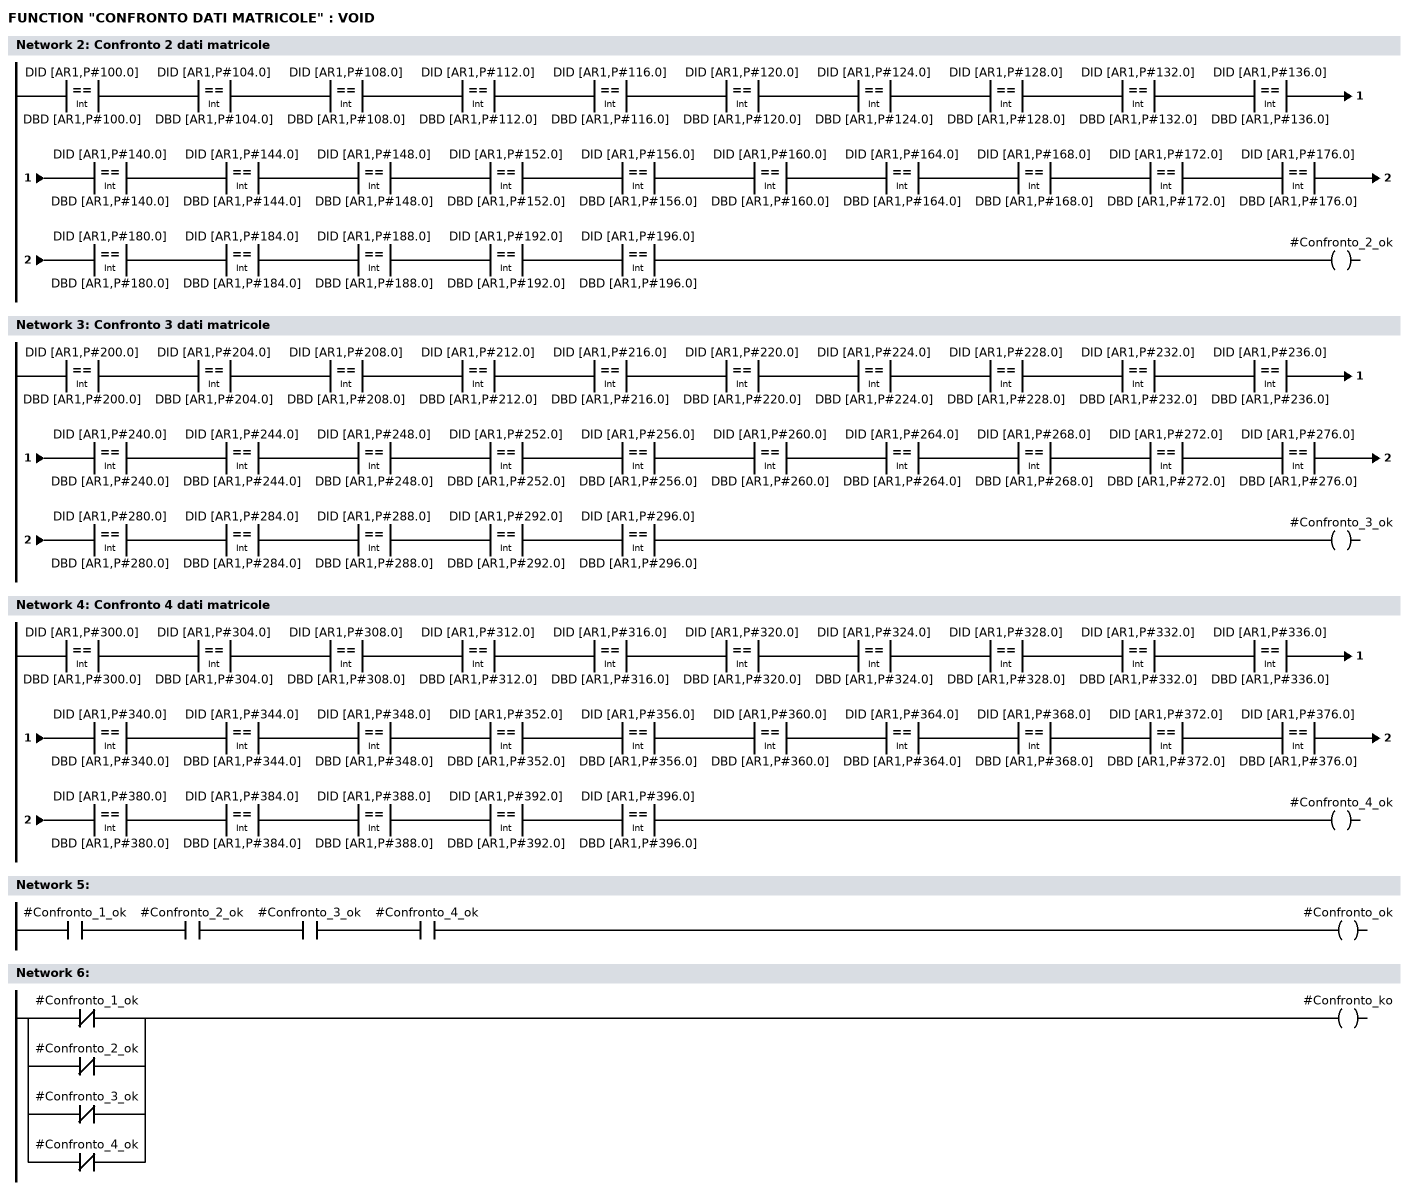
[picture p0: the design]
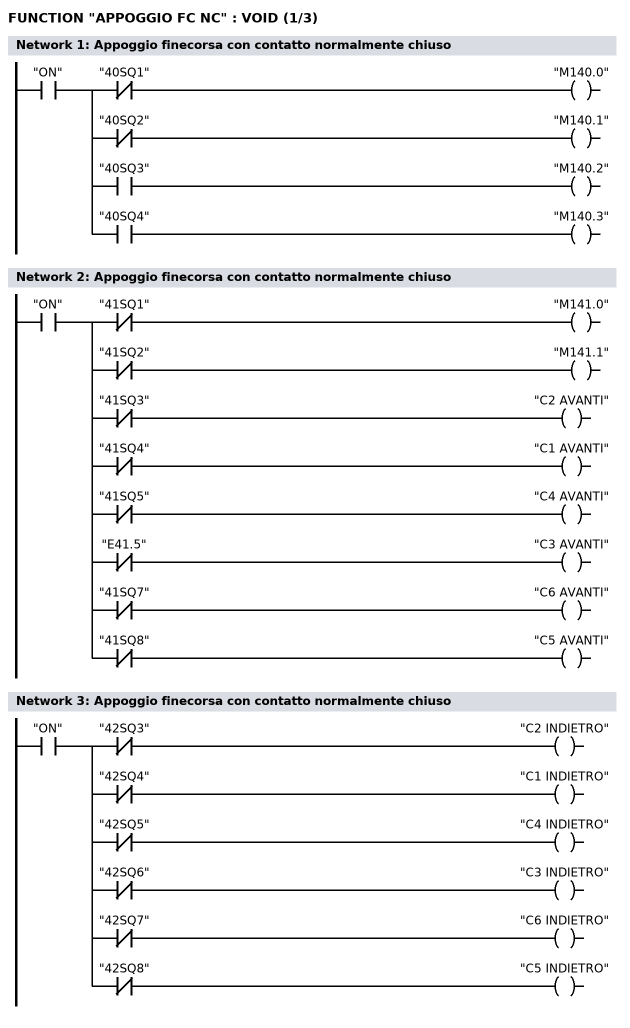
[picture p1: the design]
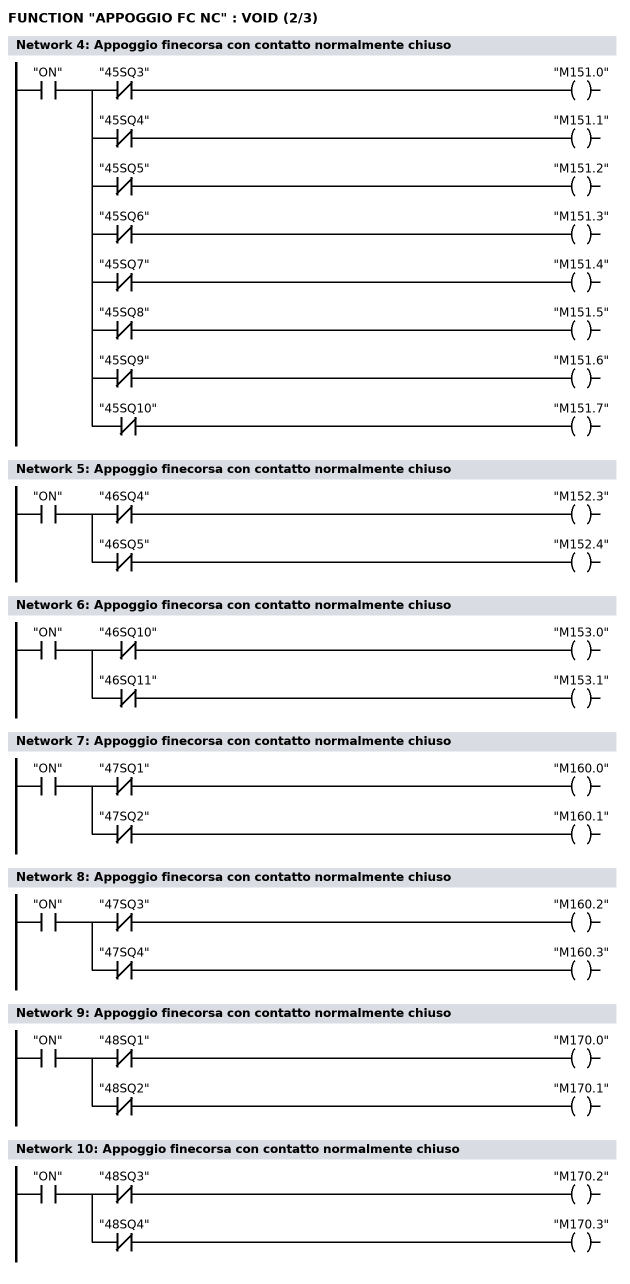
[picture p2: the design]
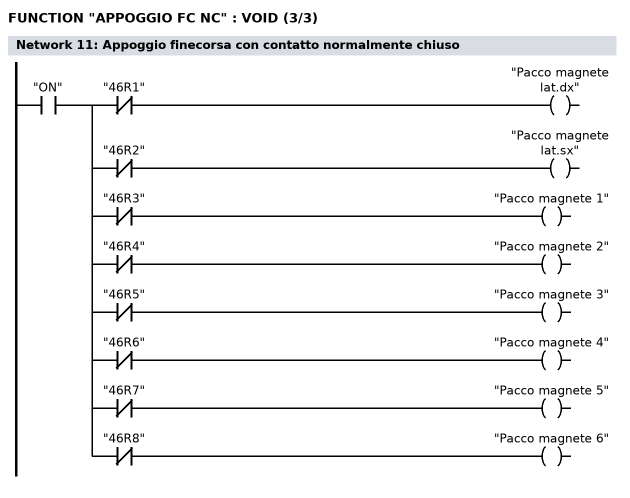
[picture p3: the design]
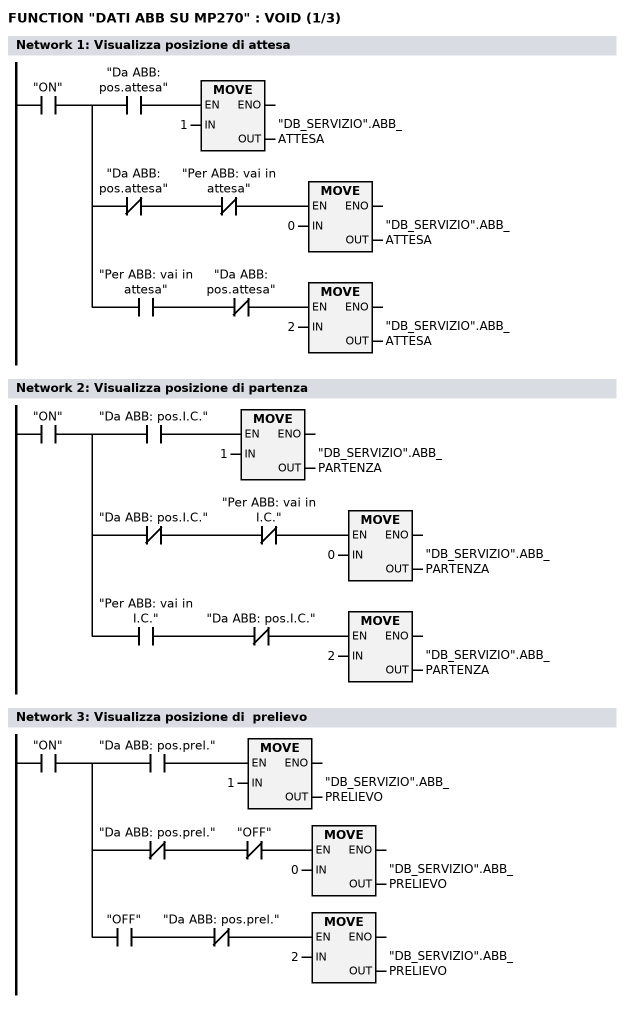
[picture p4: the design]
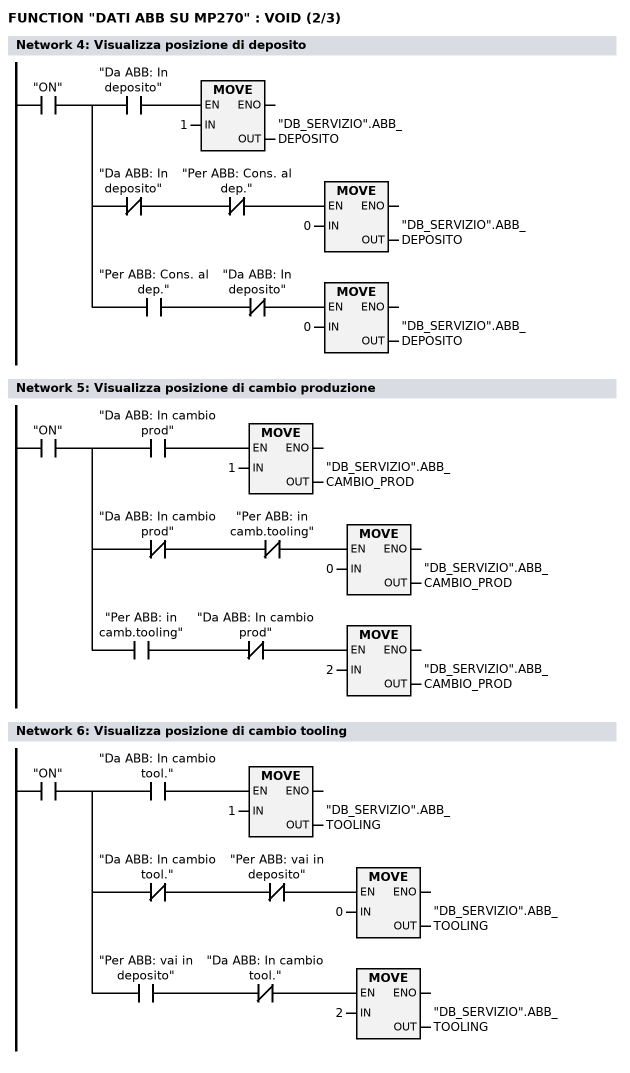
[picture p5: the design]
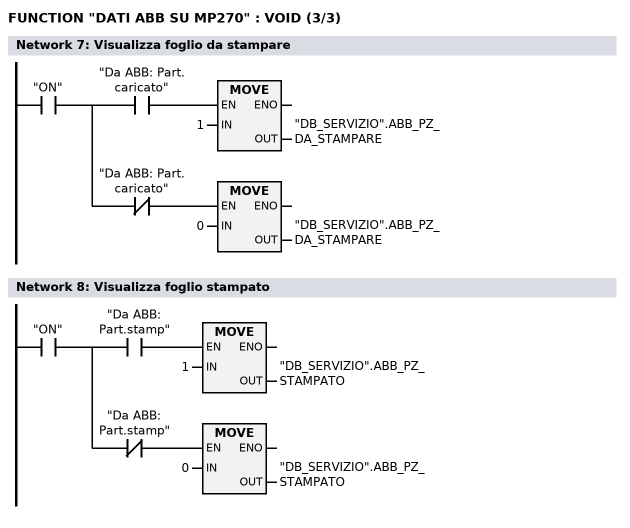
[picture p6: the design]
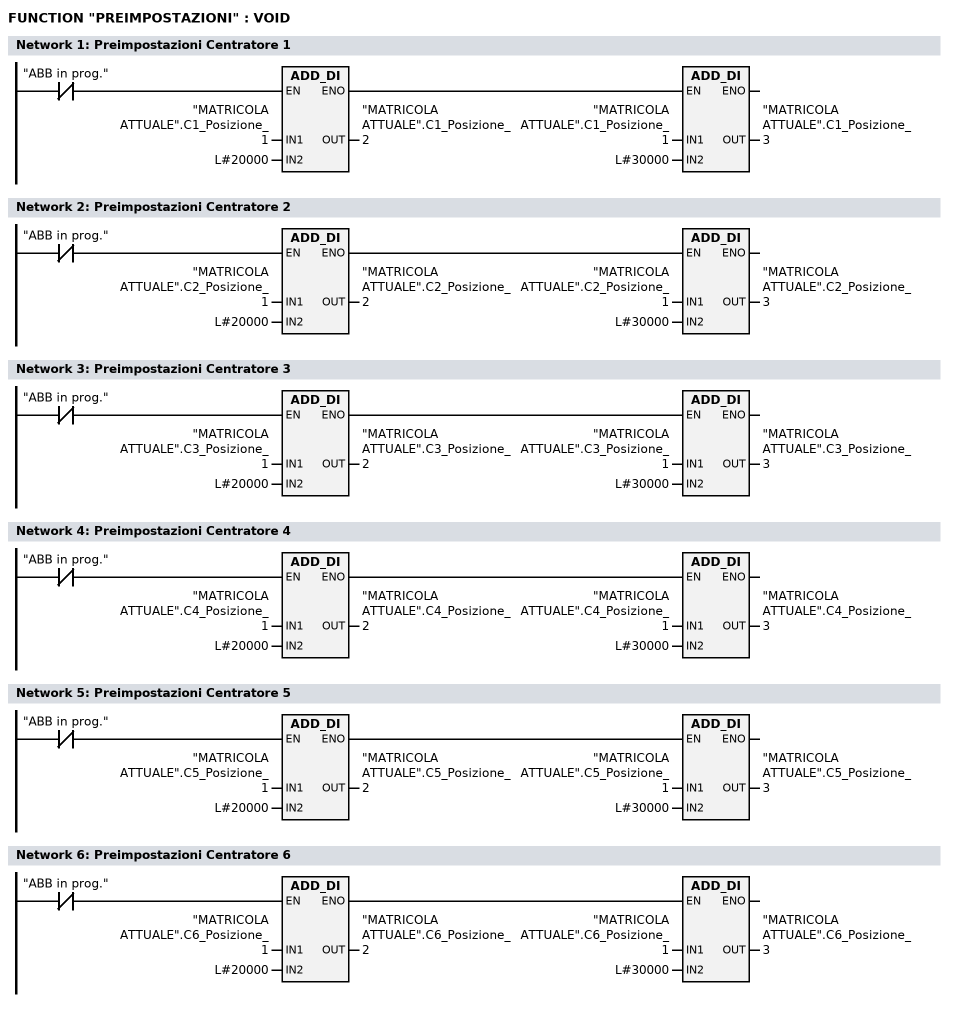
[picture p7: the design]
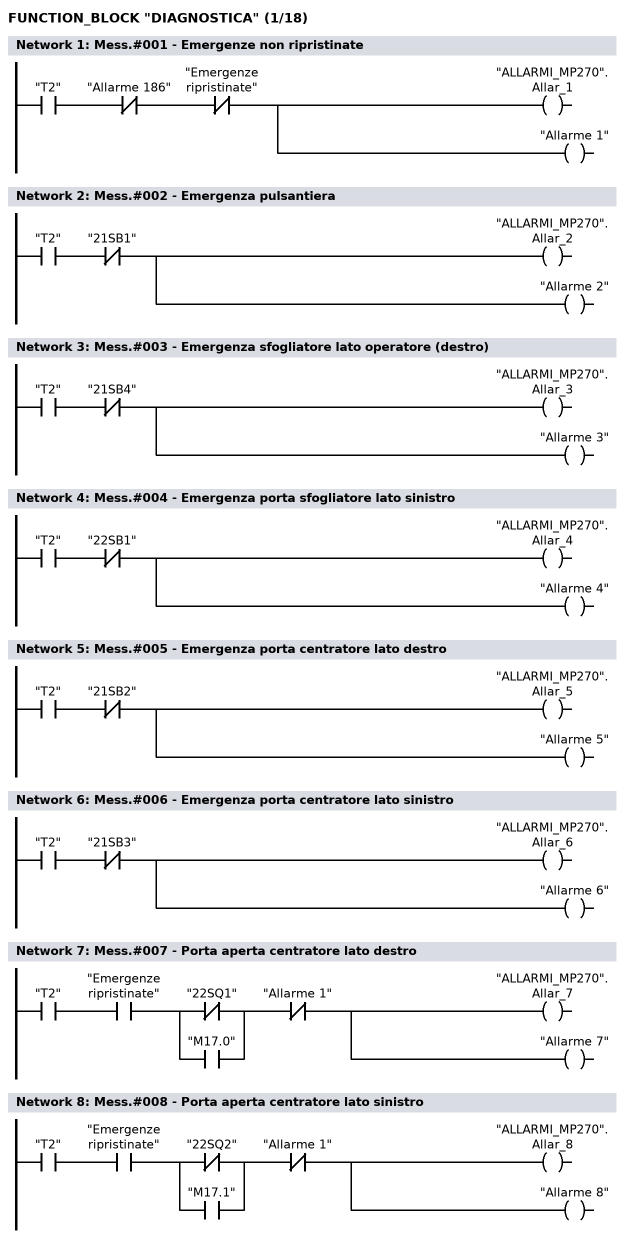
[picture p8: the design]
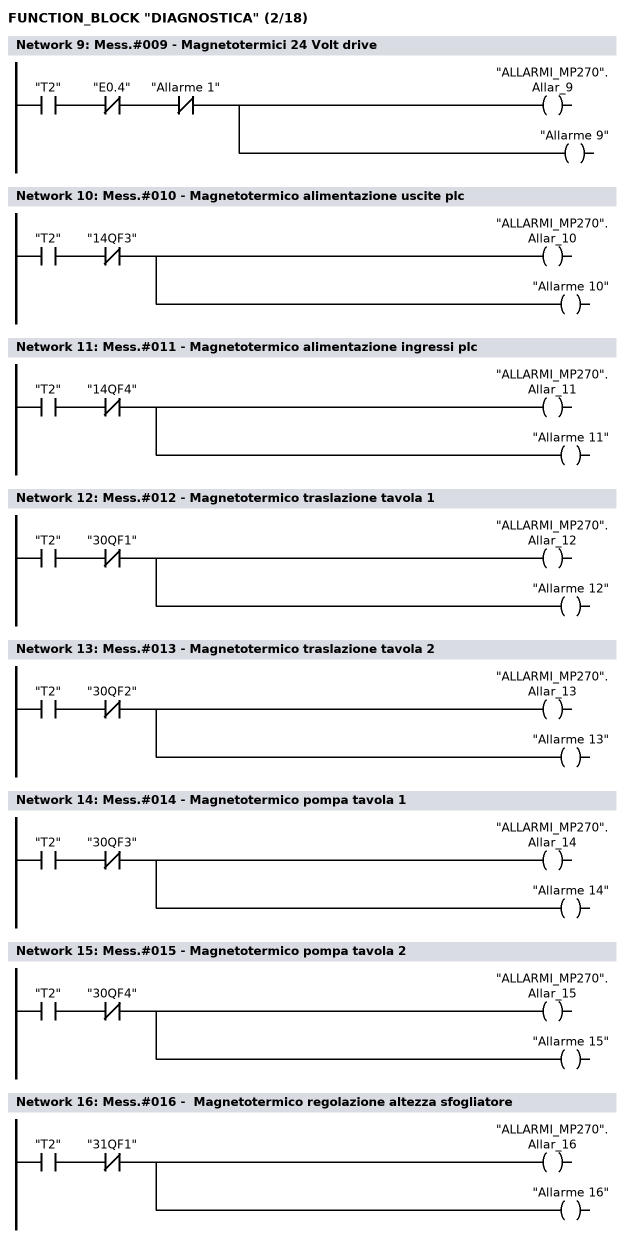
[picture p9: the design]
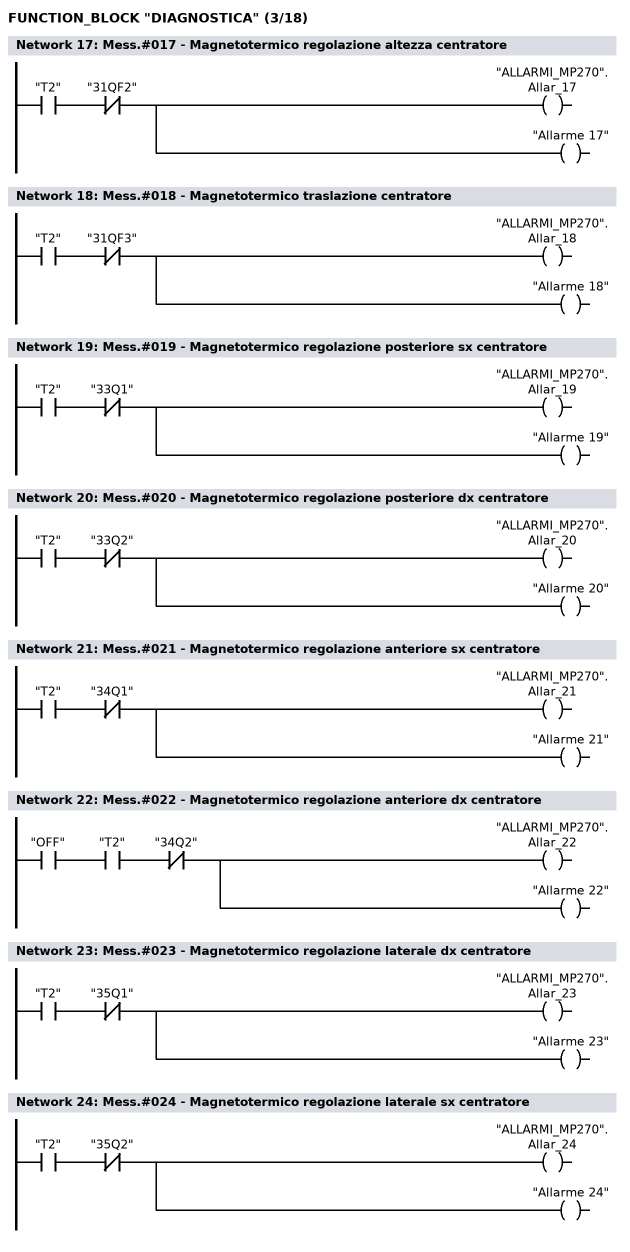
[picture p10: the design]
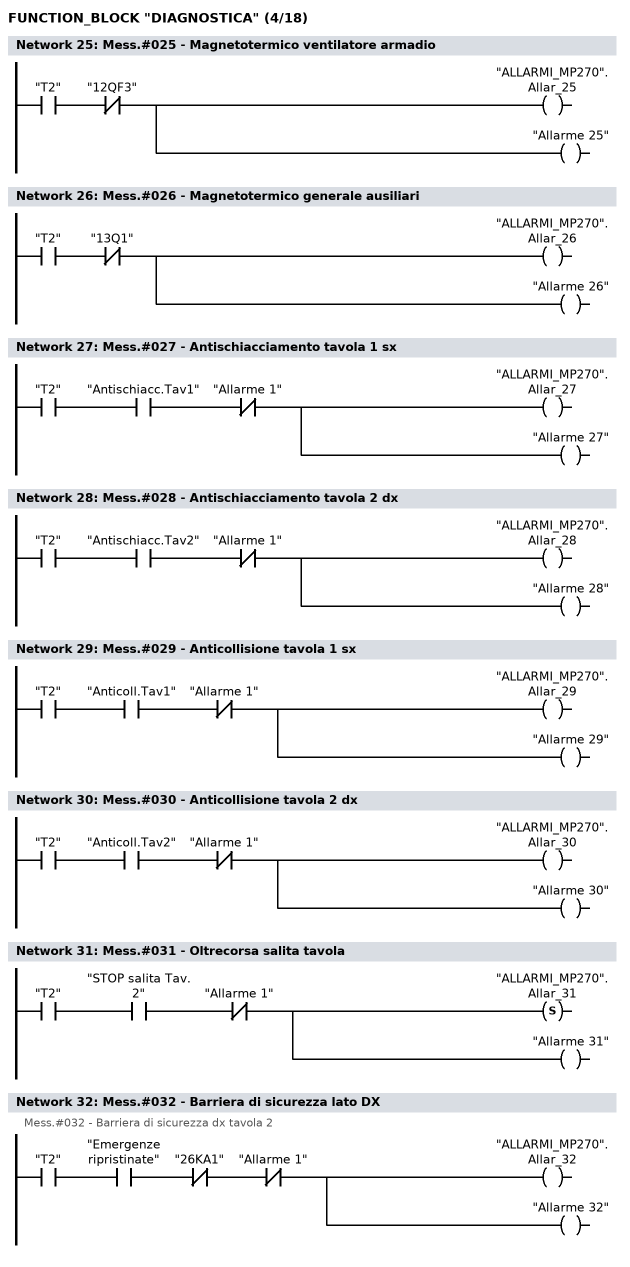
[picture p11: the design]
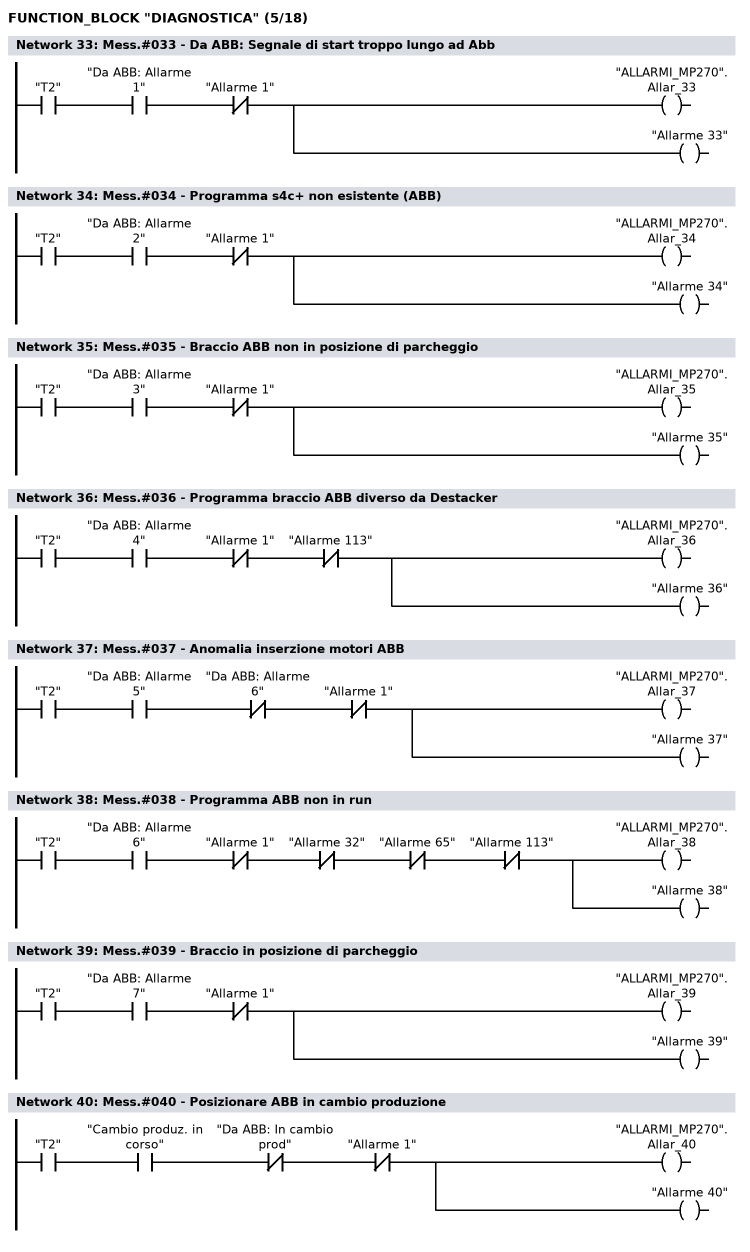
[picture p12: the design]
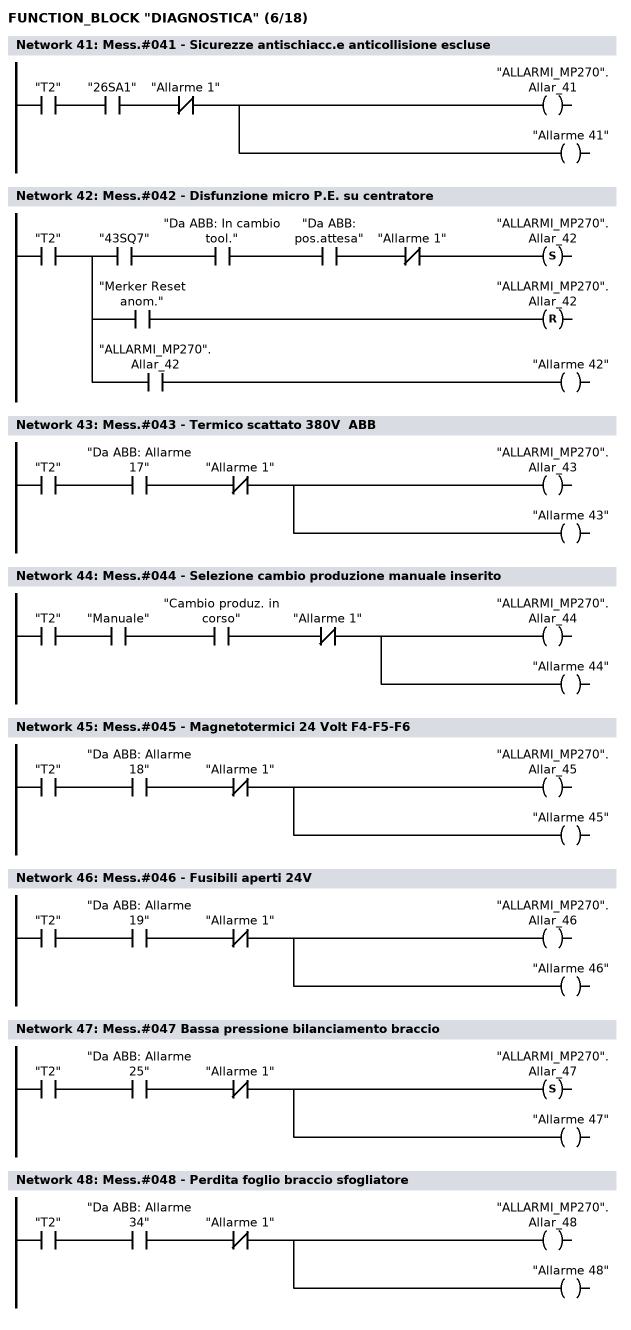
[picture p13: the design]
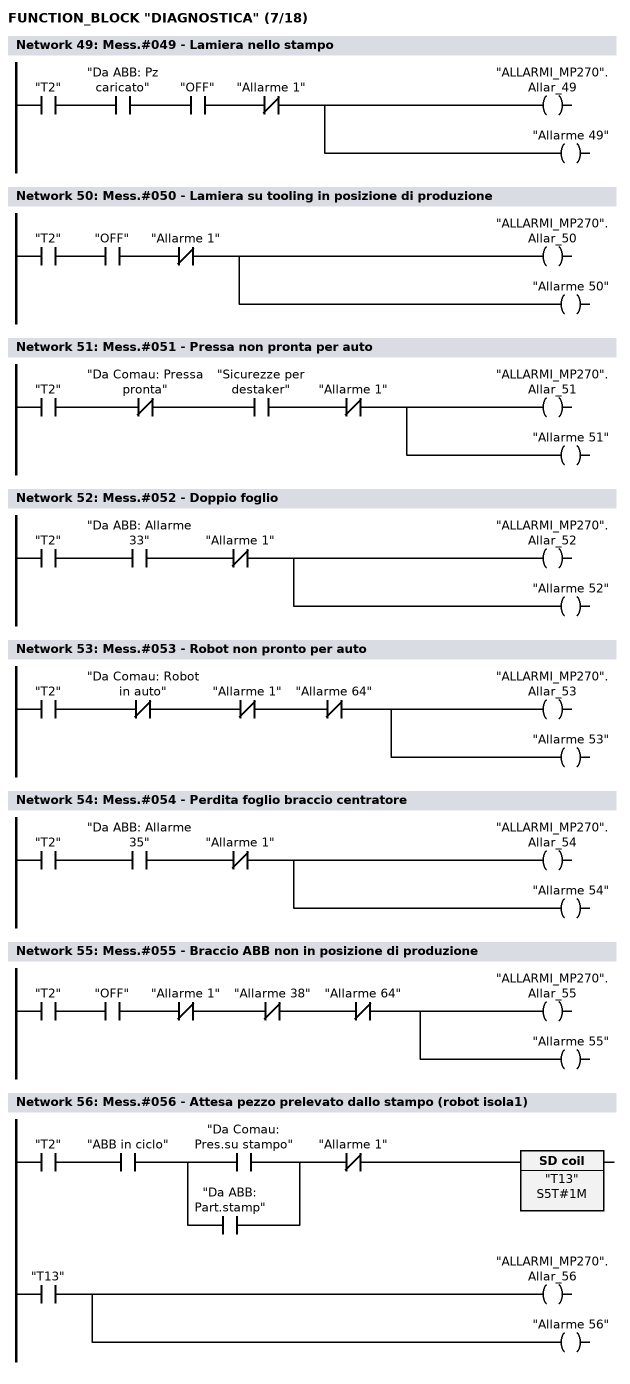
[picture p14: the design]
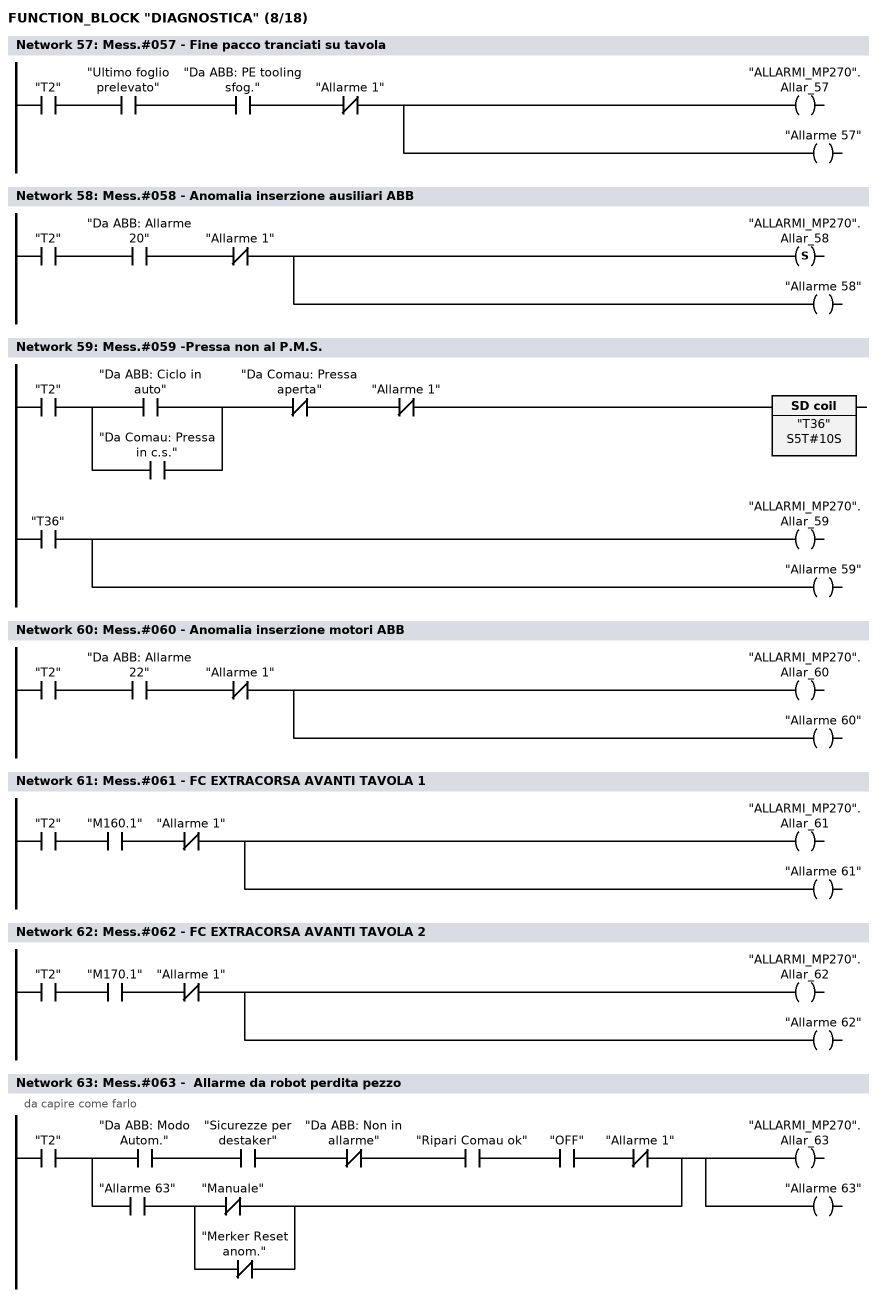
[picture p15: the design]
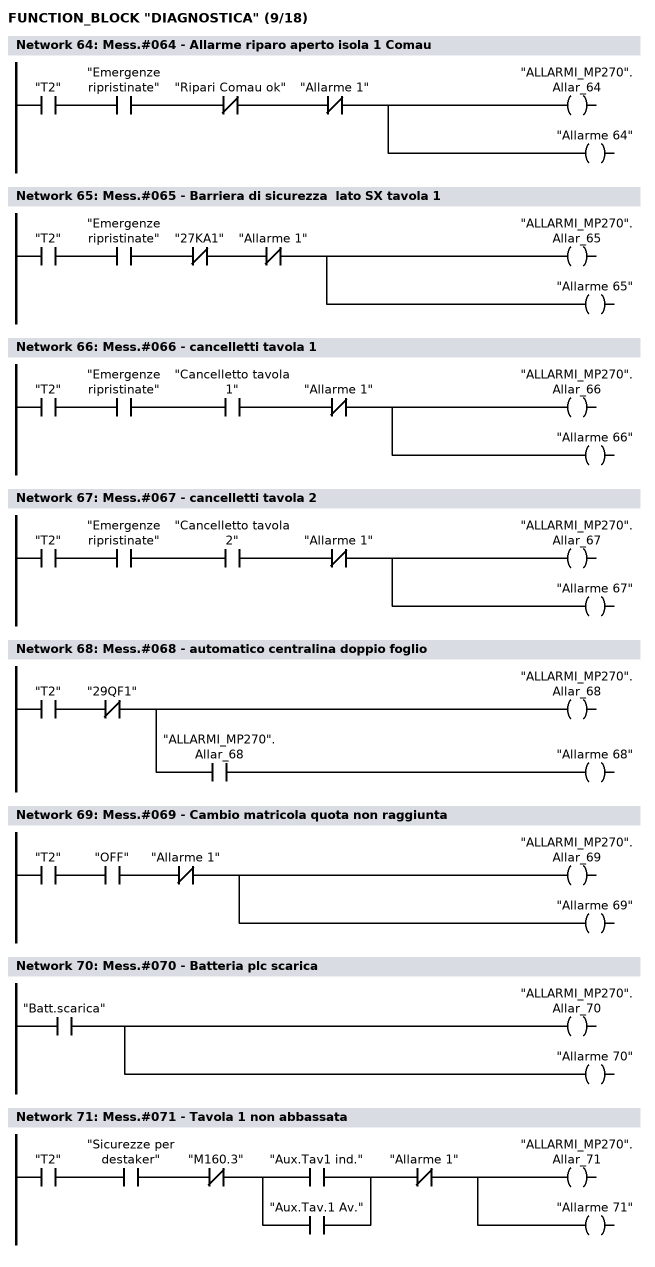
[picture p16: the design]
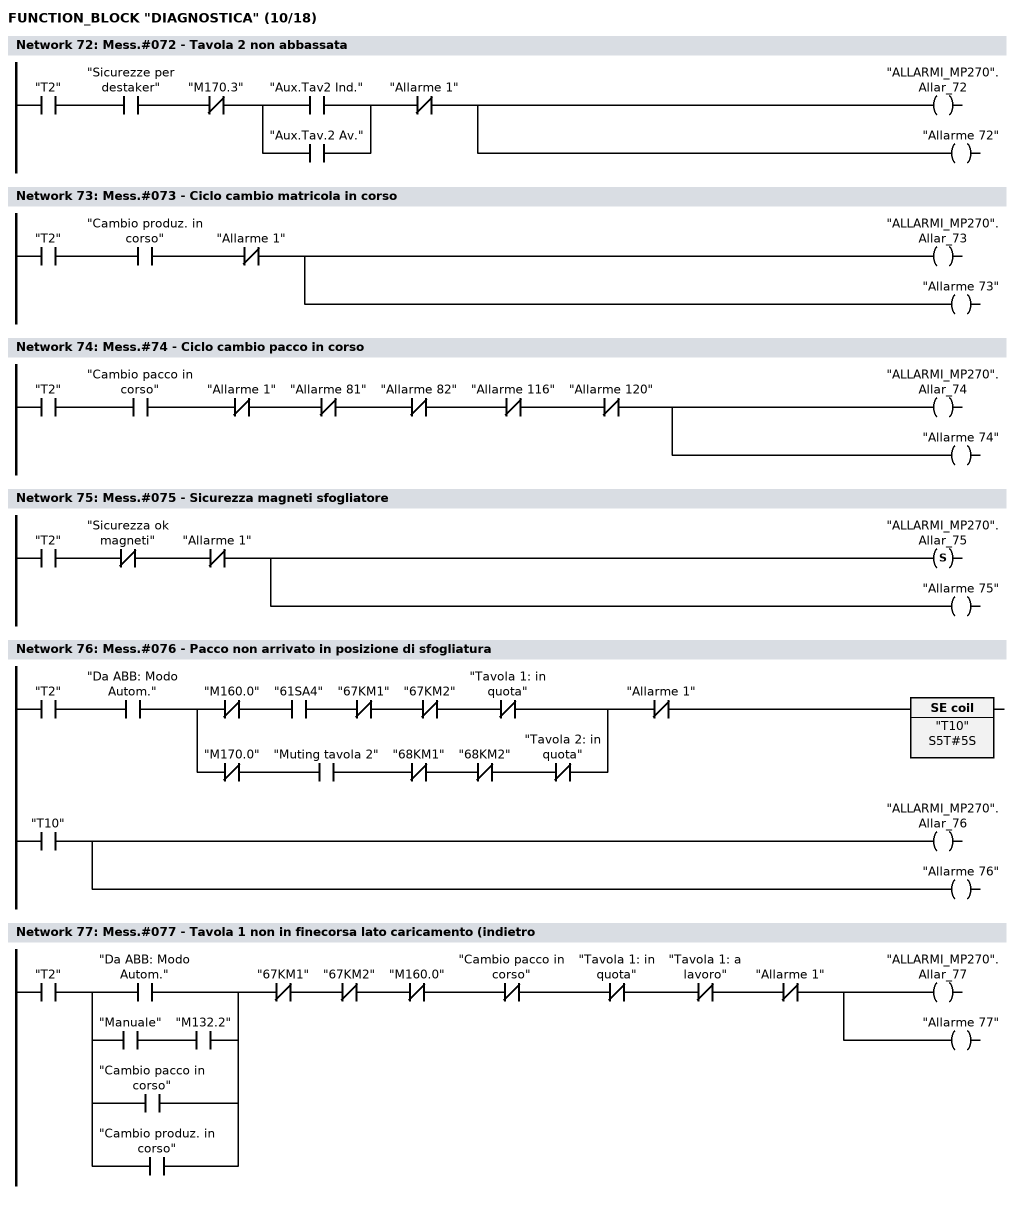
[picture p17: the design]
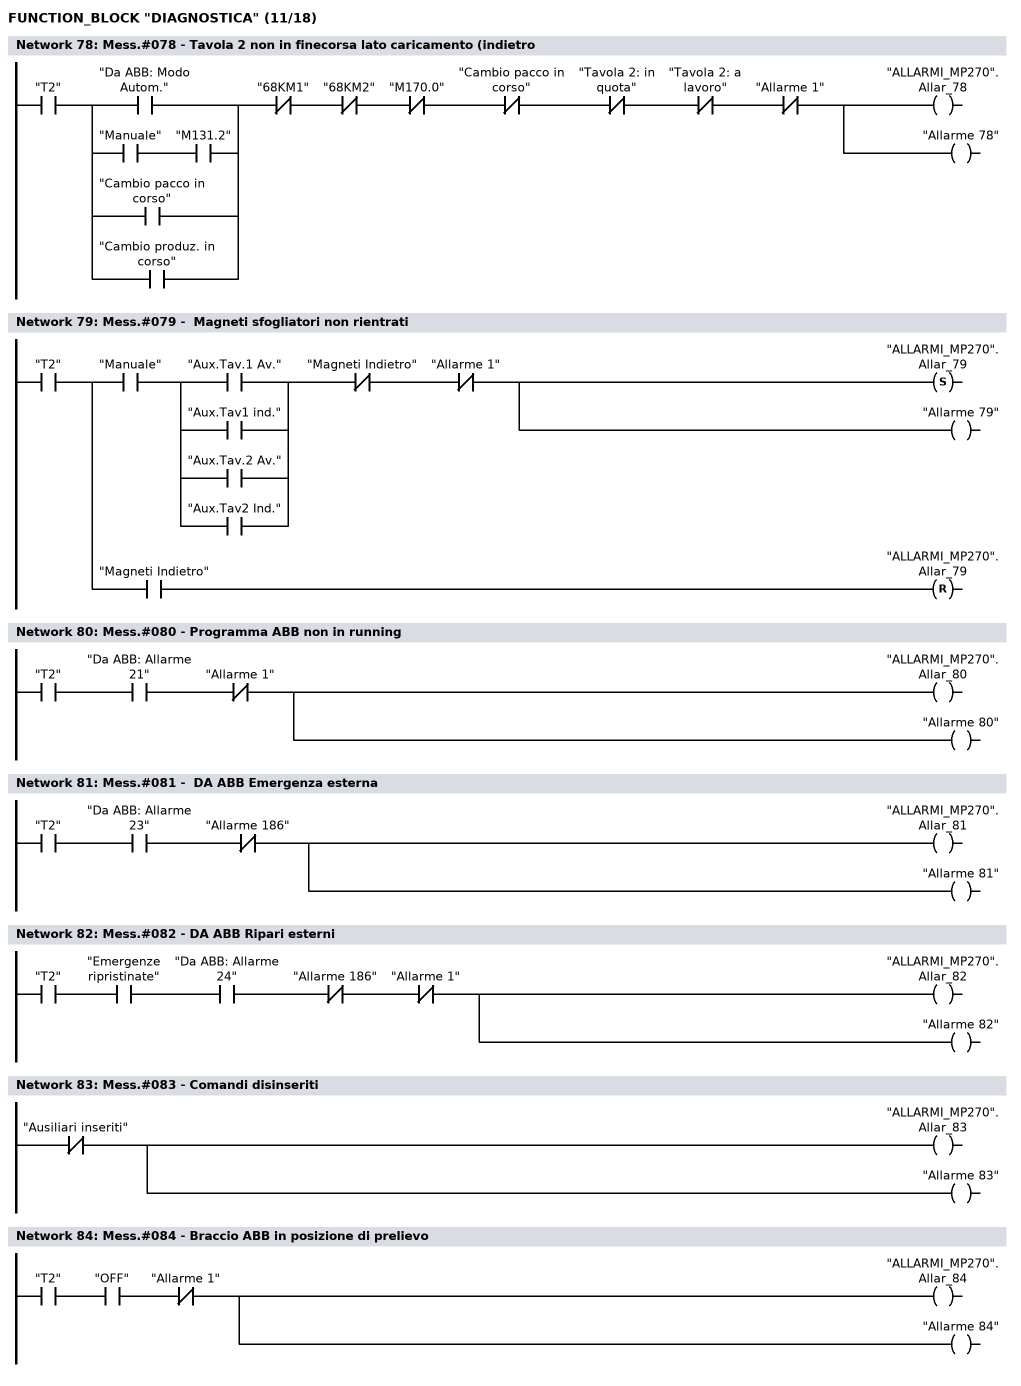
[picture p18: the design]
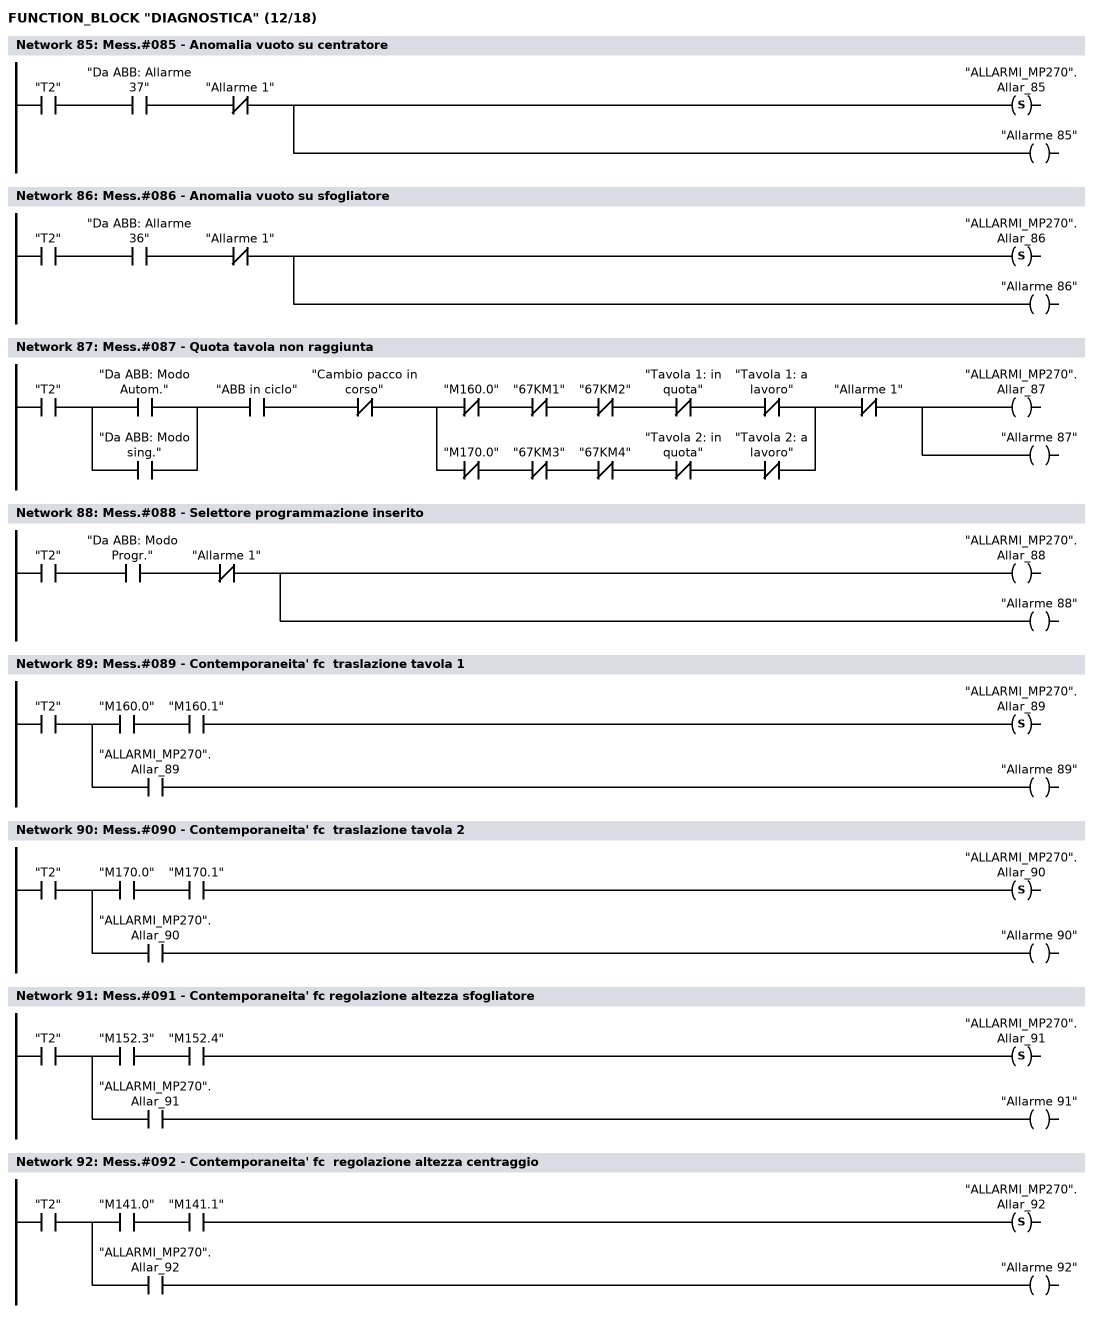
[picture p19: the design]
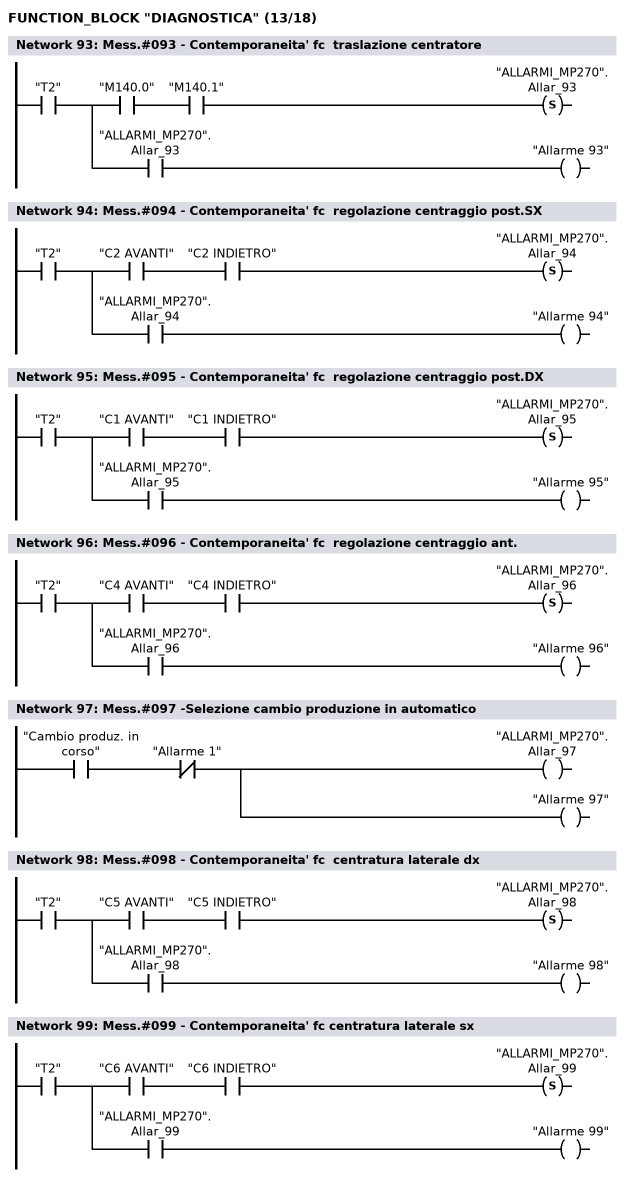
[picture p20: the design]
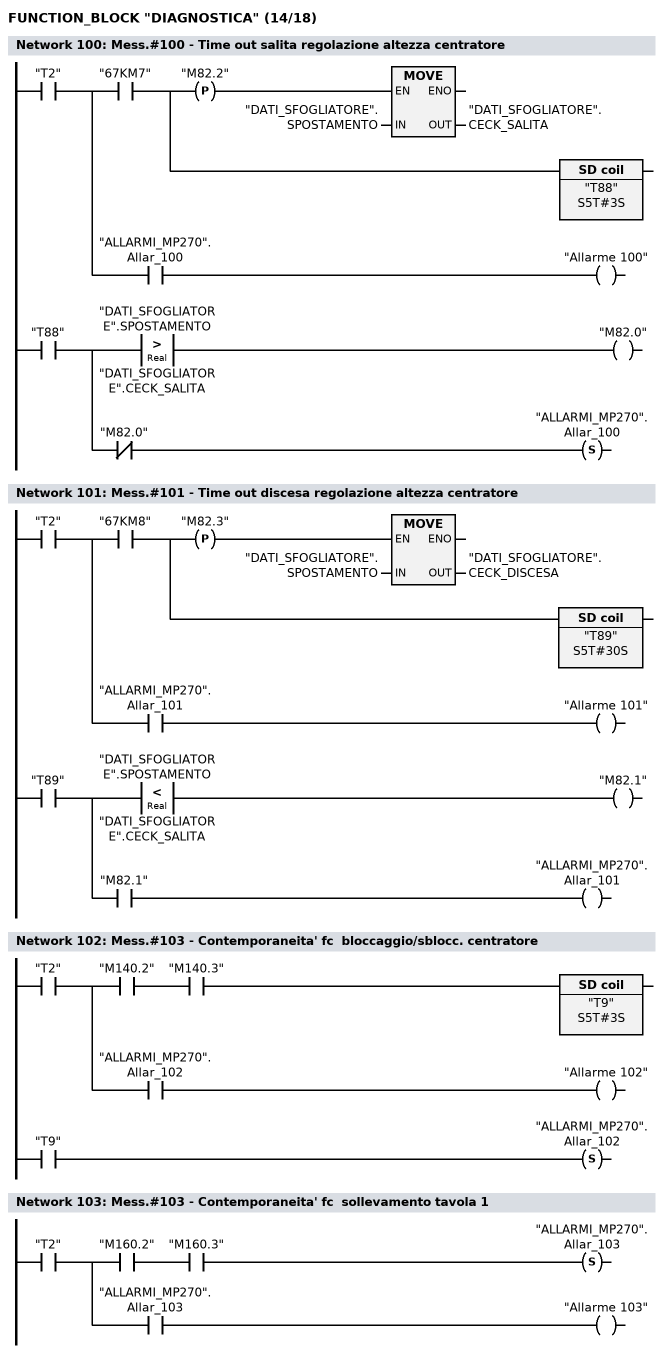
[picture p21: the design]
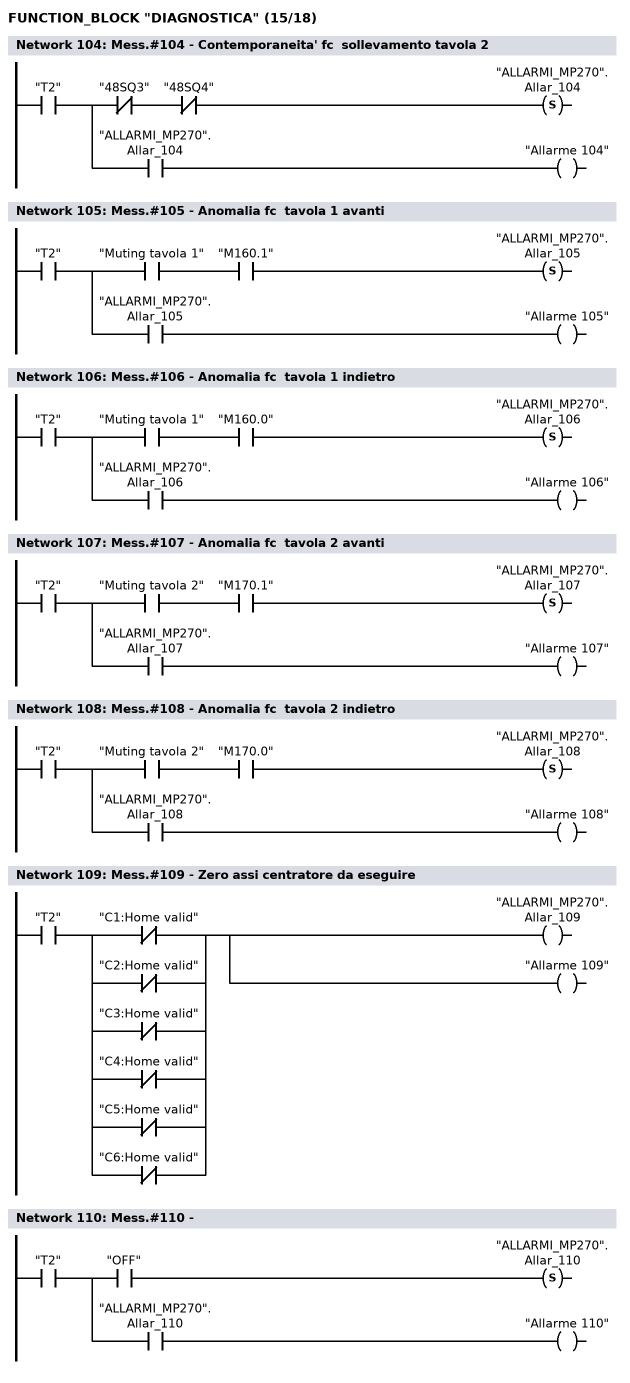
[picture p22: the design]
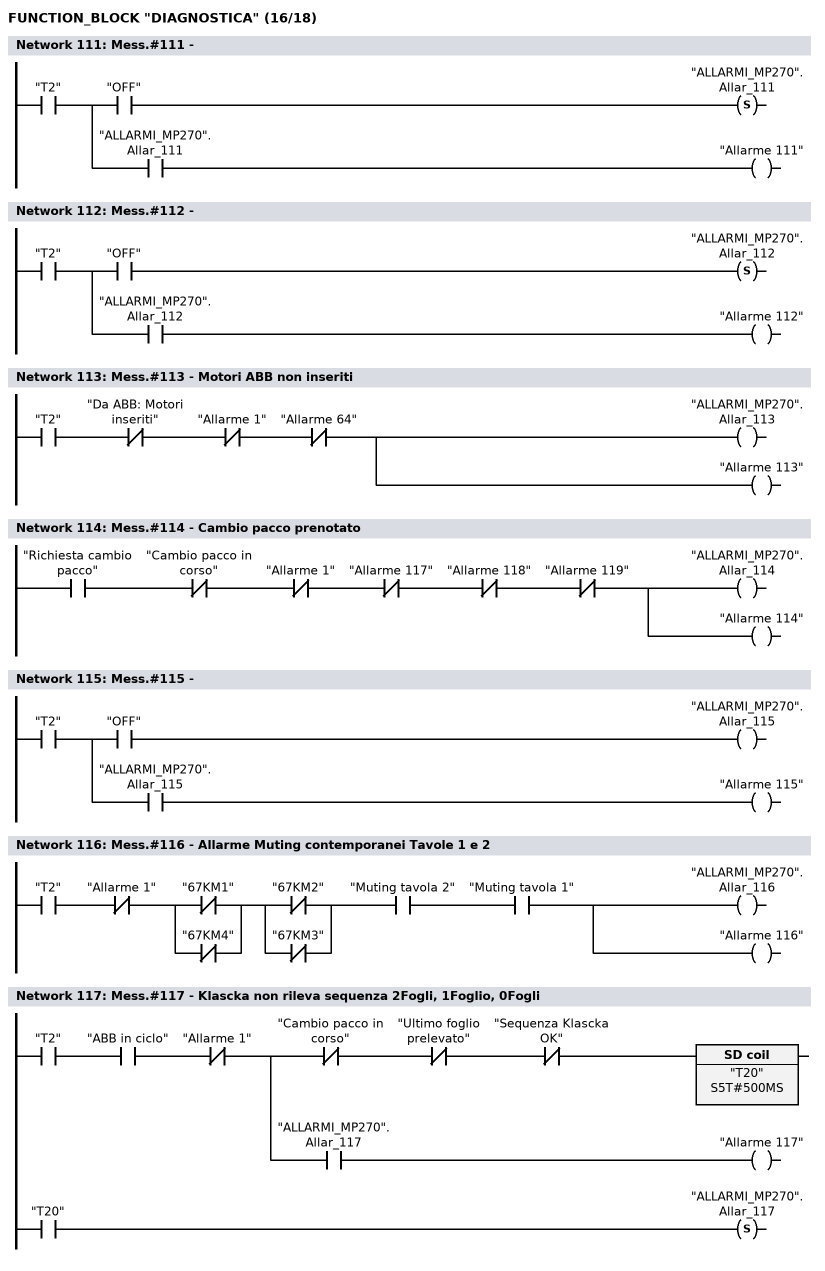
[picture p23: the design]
DATA_BLOCK "DB_MP270"
AUTHOR : DAVI
FAMILY : DESTACK
NAME : DB_OP
VERSION : 0.1


  STRUCT
   STAT0 : WORD ;
   STAT1 : S5TIME ;
   STAT2 : S5TIME ;
   STAT3 : S5TIME ;
   STAT4 : S5TIME ;
   STAT5 : S5TIME ;
   STAT6 : S5TIME ;
   STAT7 : S5TIME ;
   STAT8 : S5TIME ;
   STAT9 : S5TIME ;
   STAT10 : S5TIME ;
   STAT11 : S5TIME ;
   STAT12 : S5TIME ;
   STAT13 : S5TIME ;
   STAT14 : S5TIME ;
   STAT15 : S5TIME ;
   STAT16 : S5TIME ;
   STAT17 : S5TIME ;
   STAT18 : S5TIME ;
   STAT19 : S5TIME ;
   STAT20 : S5TIME ;
   STAT21 : S5TIME ;
   STAT22 : S5TIME ;
   STAT23 : S5TIME ;
   STAT24 : S5TIME ;
   STAT25 : S5TIME ;
   STAT26 : S5TIME ;
   STAT27 : S5TIME ;
   STAT28 : S5TIME ;
   STAT29 : S5TIME ;
   STAT30 : S5TIME ;
   STAT31 : S5TIME ;
   STAT32 : S5TIME ;
   STAT33 : S5TIME ;
   STAT34 : S5TIME ;
   STAT35 : S5TIME ;
   STAT36 : S5TIME ;
   STAT37 : S5TIME ;
   STAT38 : S5TIME ;
   STAT39 : S5TIME ;
   STAT40 : S5TIME ;
   STAT41 : S5TIME ;
   STAT42 : S5TIME ;
   STAT43 : S5TIME ;
   STAT44 : S5TIME ;
   STAT45 : S5TIME ;
   STAT46 : S5TIME ;
   STAT47 : S5TIME ;
   STAT48 : S5TIME ;
   STAT49 : S5TIME ;
   STAT50 : S5TIME ;
   STAT51 : S5TIME ;
   STAT52 : S5TIME ;
   STAT53 : S5TIME ;
   STAT54 : S5TIME ;
   STAT55 : S5TIME ;
   STAT56 : S5TIME ;
   STAT57 : S5TIME ;
   STAT58 : S5TIME ;
   STAT59 : S5TIME ;
   STAT60 : S5TIME ;
   STAT61 : S5TIME ;
   STAT62 : S5TIME ;
   STAT63 : S5TIME ;
   STAT64 : S5TIME ;
   STAT65 : S5TIME ;
   STAT66 : S5TIME ;
   STAT67 : S5TIME ;
   STAT68 : S5TIME ;
   STAT69 : S5TIME ;
   STAT70 : S5TIME ;
   STAT71 : S5TIME ;
   STAT72 : S5TIME ;
   STAT73 : S5TIME ;
   STAT74 : S5TIME ;
   STAT75 : S5TIME ;
   STAT76 : S5TIME ;
   STAT77 : S5TIME ;
   STAT78 : S5TIME ;
   STAT79 : S5TIME ;
   STAT80 : S5TIME ;
   STAT81 : S5TIME ;
   STAT82 : S5TIME ;
   STAT83 : S5TIME ;
   STAT84 : S5TIME ;
   STAT85 : S5TIME ;
   STAT86 : S5TIME ;
   STAT87 : S5TIME ;
   STAT88 : S5TIME ;
   STAT89 : S5TIME ;
   STAT90 : S5TIME ;
   STAT91 : S5TIME ;
   STAT92 : S5TIME ;
   STAT93 : S5TIME ;
   STAT94 : S5TIME ;
   STAT95 : S5TIME ;
   STAT96 : S5TIME ;
   STAT97 : S5TIME ;
   STAT98 : S5TIME ;
   STAT99 : S5TIME ;
   STAT100 : S5TIME ;
   STAT101 : S5TIME ;
   STAT102 : S5TIME ;
   STAT103 : S5TIME ;
   STAT104 : S5TIME ;
   STAT105 : S5TIME ;
   STAT106 : S5TIME ;
   STAT107 : S5TIME ;
   STAT108 : S5TIME ;
   STAT109 : S5TIME ;
   STAT110 : S5TIME ;
   STAT111 : S5TIME ;
   STAT112 : S5TIME ;
   STAT113 : S5TIME ;
   STAT114 : S5TIME ;
   STAT115 : S5TIME ;
   STAT116 : S5TIME ;
   STAT117 : S5TIME ;
   STAT118 : S5TIME ;
   STAT119 : S5TIME ;
   STAT120 : S5TIME ;
   STAT121 : S5TIME ;
   STAT122 : S5TIME ;
   STAT123 : S5TIME ;
   STAT124 : S5TIME ;
   STAT125 : S5TIME ;
   STAT126 : S5TIME ;
   STAT127 : S5TIME ;
   STAT128 : INT ;
   STAT129 : WORD ;
   STAT130 : WORD ;
   STAT131 : WORD ;
   STAT132 : WORD ;
   STAT133 : WORD ;
   STAT134 : WORD ;
   STAT135 : WORD ;
   STAT136 : WORD ;
   STAT137 : WORD ;
   STAT138 : WORD ;
   STAT139 : WORD ;
   STAT140 : WORD ;
   STAT141 : WORD ;
   STAT142 : WORD ;
   STAT143 : WORD ;
   STAT144 : WORD ;
   STAT145 : WORD ;
   STAT146 : WORD ;
   STAT147 : WORD ;
   STAT148 : WORD ;
   STAT149 : WORD ;
   STAT150 : BYTE ;
   STAT151 : BYTE ;
   STAT152 : BYTE ;
   STAT153 : BYTE ;
   STAT154 : WORD ;
   STAT155 : WORD ;
   STAT156 : WORD ;
   STAT157 : WORD ;
   STAT158 : BYTE ;
   STAT159 : BYTE ;
   STAT160 : BYTE ;
   STAT161 : BYTE ;
   STAT162 : BYTE ;
   STAT163 : BYTE ;
   STAT164 : BYTE ;
   STAT165 : BYTE ;
   STAT166 : BYTE ;
   STAT167 : BYTE ;
   STAT168 : BYTE ;
   STAT169 : BYTE ;
   STAT170 : BYTE ;
   STAT171 : BYTE ;
   STAT172 : BYTE ;
   STAT173 : BYTE ;
   STAT174 : BYTE ;
   STAT175 : BYTE ;
   STAT176 : BYTE ;
   STAT177 : BYTE ;
   STAT178 : WORD ;
   STAT179 : WORD ;
   STAT180 : WORD ;
   STAT181 : WORD ;
   STAT182 : INT ;
   STAT183 : BYTE ;
   STAT184 : BYTE ;
   STAT185 : BYTE ;
   STAT186 : BYTE ;
   STAT187 : WORD ;
   STAT188 : BOOL ;
   STAT189 : BOOL ;
   STAT190 : BOOL ;
   STAT191 : BOOL ;
   STAT192 : BOOL ;
   STAT193 : BOOL ;
   STAT194 : BOOL ;
   STAT195 : BOOL ;
   STAT196 : BOOL ;
   STAT197 : BOOL ;
   STAT198 : BOOL ;
   STAT199 : BOOL ;
   STAT200 : BOOL ;
   STAT201 : BOOL ;
   STAT202 : BOOL ;
   STAT203 : BOOL ;
   STAT204 : BOOL ;
   STAT205 : BOOL ;
   STAT206 : BOOL ;
   STAT207 : BOOL ;
   STAT208 : BOOL ;
   STAT209 : BOOL ;
   STAT210 : BOOL ;
   STAT211 : BOOL ;
   STAT212 : BOOL ;
   STAT213 : BOOL ;
   STAT214 : BOOL ;
   STAT215 : BOOL ;
   STAT216 : BOOL ;
   STAT217 : BOOL ;
   STAT218 : BOOL ;
   STAT219 : BOOL ;
   STAT220 : WORD ;
   STAT221 : WORD ;
   STAT222 : INT ;
   STAT223 : BYTE ;
   STAT224 : BYTE ;
   STAT225 : BOOL ;
   STAT226 : BOOL ;
   STAT227 : BOOL ;
   STAT228 : BOOL ;
   STAT229 : BOOL ;
   STAT230 : BOOL ;
   STAT231 : BOOL ;
   STAT232 : BOOL ;
   STAT233 : BOOL ;
   STAT234 : BOOL ;
   STAT235 : BOOL ;
   STAT236 : BOOL ;
   STAT237 : BOOL ;
   STAT238 : BOOL ;
   STAT239 : BOOL ;
   STAT240 : BOOL ;
   STAT241 : WORD ;
   STAT242 : INT ;
   STAT243 : WORD ;
   STAT244 : BOOL ;
   STAT245 : BOOL ;
   STAT246 : BOOL ;
   STAT247 : BOOL ;
   STAT248 : BOOL ;
   STAT249 : BOOL ;
   STAT250 : BOOL ;
   STAT251 : BOOL ;
   STAT252 : BOOL ;
   STAT253 : BOOL ;
   STAT254 : BOOL ;
   STAT255 : BOOL ;
   STAT256 : BOOL ;
   STAT257 : BOOL ;
   STAT258 : BOOL ;
   STAT259 : BOOL ;
   STAT260 : BOOL ;
   STAT261 : BOOL ;
   STAT262 : BOOL ;
   STAT263 : BOOL ;
   STAT264 : BOOL ;
   STAT265 : BOOL ;
   STAT266 : BOOL ;
   STAT267 : BOOL ;
   STAT268 : BOOL ;
   STAT269 : BOOL ;
   STAT270 : BOOL ;
   STAT271 : BOOL ;
   STAT272 : BOOL ;
   STAT273 : BOOL ;
   STAT274 : BOOL ;
   STAT275 : BOOL ;
   STAT276 : WORD ;
   STAT277 : WORD ;
   STAT278 : WORD ;
   STAT279 : WORD ;
   STAT280 : WORD ;
   STAT281 : WORD ;
   STAT282 : BOOL ;
   STAT283 : BOOL ;
   STAT284 : BOOL ;
   STAT285 : BOOL ;
   STAT286 : BOOL ;
   STAT287 : BOOL ;
   STAT288 : BOOL ;
   STAT289 : BOOL ;
   STAT290 : BOOL ;
   STAT291 : BOOL ;
   STAT292 : BOOL ;
   STAT293 : BOOL ;
   STAT294 : BOOL ;
   STAT295 : BOOL ;
   STAT296 : BOOL ;
   STAT297 : BOOL ;
   STAT298 : BOOL ;
   STAT299 : BOOL ;
   STAT300 : BOOL ;
   STAT301 : BOOL ;
   STAT302 : BOOL ;
   STAT303 : BOOL ;
   STAT304 : BOOL ;
   STAT305 : BOOL ;
   STAT306 : BOOL ;
   STAT307 : BOOL ;
   STAT308 : BOOL ;
   STAT309 : BOOL ;
   STAT310 : BOOL ;
   STAT311 : BOOL ;
   STAT312 : BOOL ;
   STAT313 : BOOL ;
   STAT314 : BOOL ;
   STAT315 : BOOL ;
   STAT316 : BOOL ;
   STAT317 : BOOL ;
   STAT318 : BOOL ;
   STAT319 : BOOL ;
   STAT320 : BOOL ;
   STAT321 : BOOL ;
   STAT322 : BOOL ;
   STAT323 : BOOL ;
   STAT324 : BOOL ;
   STAT325 : BOOL ;
   STAT326 : BOOL ;
   STAT327 : BOOL ;
   STAT328 : BOOL ;
   STAT329 : BOOL ;
   STAT330 : BOOL ;
   STAT331 : BOOL ;
   STAT332 : BOOL ;
   STAT333 : BOOL ;
   STAT334 : BOOL ;
   STAT335 : BOOL ;
   STAT336 : BOOL ;
   STAT337 : BOOL ;
   STAT338 : BOOL ;
   STAT339 : BOOL ;
   STAT340 : BOOL ;
   STAT341 : BOOL ;
   STAT342 : BOOL ;
   STAT343 : BOOL ;
   STAT344 : BOOL ;
   STAT345 : BOOL ;
   STAT346 : BOOL ;
   STAT347 : BOOL ;
   STAT348 : BOOL ;
   STAT349 : BOOL ;
   STAT350 : BOOL ;
   STAT351 : BOOL ;
   STAT352 : BOOL ;
   STAT353 : BOOL ;
   STAT354 : BOOL ;
   STAT355 : BOOL ;
   STAT356 : BOOL ;
   STAT357 : BOOL ;
   STAT358 : BOOL ;
   STAT359 : BOOL ;
   STAT360 : BOOL ;
   STAT361 : BOOL ;
   STAT362 : BYTE ;
   STAT363 : BYTE ;
   STAT364 : BOOL ;
   STAT365 : BOOL ;
   STAT366 : BOOL ;
   STAT367 : BOOL ;
   STAT368 : BOOL ;
   STAT369 : BOOL ;
   STAT370 : BOOL ;
   STAT371 : BOOL ;
   STAT372 : BOOL ;
   STAT373 : BOOL ;
   STAT374 : BOOL ;
   STAT375 : BOOL ;
   STAT376 : BOOL ;
   STAT377 : BOOL ;
   STAT378 : BOOL ;
   STAT379 : BOOL ;
   STAT380 : REAL  := 1.000000e+002;
   STAT381 : REAL  := 1.000000e+002;
   STAT382 : REAL ;
   STAT383 : REAL ;
   STAT384 : REAL ;
   STAT385 : REAL ;
   STAT386 : REAL ;
   STAT387 : REAL ;
   STAT388 : REAL ;
   STAT389 : REAL ;
   STAT390 : REAL ;
   STAT391 : REAL ;
   STAT392 : REAL ;
   STAT393 : REAL ;
   STAT394 : REAL ;
   STAT395 : DWORD ;
   STAT396 : REAL ;
   STAT397 : REAL ;
   STAT398 : REAL ;
   STAT399 : REAL ;
   STAT400 : REAL ;
   STAT401 : REAL ;
   STAT402 : INT ;
   STAT403 : INT ;
   STAT404 : REAL ;
   STAT405 : REAL ;
   STAT406 : REAL ;
   STAT407 : REAL ;
   STAT408 : REAL ;
   STAT409 : REAL ;
   STAT410 : REAL ;
   STAT411 : REAL ;
   STAT412 : REAL ;
   STAT413 : REAL ;
  END_STRUCT ;
BEGIN
   STAT0 := W#16#0;
   STAT1 := S5T#0MS;
   STAT2 := S5T#0MS;
   STAT3 := S5T#0MS;
   STAT4 := S5T#0MS;
   STAT5 := S5T#0MS;
   STAT6 := S5T#0MS;
   STAT7 := S5T#1S;
   STAT8 := S5T#0MS;
   STAT9 := S5T#0MS;
   STAT10 := S5T#0MS;
   STAT11 := S5T#0MS;
   STAT12 := S5T#0MS;
   STAT13 := S5T#3S;
   STAT14 := S5T#0MS;
   STAT15 := S5T#0MS;
   STAT16 := S5T#0MS;
   STAT17 := S5T#0MS;
   STAT18 := S5T#1S;
   STAT19 := S5T#60MS;
   STAT20 := S5T#0MS;
   STAT21 := S5T#1S;
   STAT22 := S5T#4S;
   STAT23 := S5T#4S;
   STAT24 := S5T#1S;
   STAT25 := S5T#1S;
   STAT26 := S5T#0MS;
   STAT27 := S5T#1M;
   STAT28 := S5T#0MS;
   STAT29 := S5T#0MS;
   STAT30 := S5T#0MS;
   STAT31 := S5T#0MS;
   STAT32 := S5T#0MS;
   STAT33 := S5T#0MS;
   STAT34 := S5T#0MS;
   STAT35 := S5T#0MS;
   STAT36 := S5T#0MS;
   STAT37 := S5T#0MS;
   STAT38 := S5T#0MS;
   STAT39 := S5T#0MS;
   STAT40 := S5T#0MS;
   STAT41 := S5T#2S;
   STAT42 := S5T#0MS;
   STAT43 := S5T#0MS;
   STAT44 := S5T#0MS;
   STAT45 := S5T#0MS;
   STAT46 := S5T#0MS;
   STAT47 := S5T#0MS;
   STAT48 := S5T#0MS;
   STAT49 := S5T#0MS;
   STAT50 := S5T#10MS;
   STAT51 := S5T#10MS;
   STAT52 := S5T#0MS;
   STAT53 := S5T#0MS;
   STAT54 := S5T#0MS;
   STAT55 := S5T#0MS;
   STAT56 := S5T#0MS;
   STAT57 := S5T#0MS;
   STAT58 := S5T#0MS;
   STAT59 := S5T#0MS;
   STAT60 := S5T#0MS;
   STAT61 := S5T#0MS;
   STAT62 := S5T#0MS;
   STAT63 := S5T#0MS;
   STAT64 := S5T#0MS;
   STAT65 := S5T#0MS;
   STAT66 := S5T#0MS;
   STAT67 := S5T#0MS;
   STAT68 := S5T#0MS;
   STAT69 := S5T#0MS;
   STAT70 := S5T#0MS;
   STAT71 := S5T#0MS;
   STAT72 := S5T#0MS;
   STAT73 := S5T#0MS;
   STAT74 := S5T#0MS;
   STAT75 := S5T#0MS;
   STAT76 := S5T#0MS;
   STAT77 := S5T#0MS;
   STAT78 := S5T#0MS;
   STAT79 := S5T#0MS;
   STAT80 := S5T#0MS;
   STAT81 := S5T#0MS;
   STAT82 := S5T#0MS;
   STAT83 := S5T#0MS;
   STAT84 := S5T#0MS;
   STAT85 := S5T#0MS;
   STAT86 := S5T#0MS;
   STAT87 := S5T#0MS;
   STAT88 := S5T#0MS;
   STAT89 := S5T#0MS;
   STAT90 := S5T#0MS;
   STAT91 := S5T#0MS;
   STAT92 := S5T#0MS;
   STAT93 := S5T#0MS;
   STAT94 := S5T#0MS;
   STAT95 := S5T#0MS;
   STAT96 := S5T#0MS;
   STAT97 := S5T#0MS;
   STAT98 := S5T#0MS;
   STAT99 := S5T#0MS;
   STAT100 := S5T#0MS;
   STAT101 := S5T#0MS;
   STAT102 := S5T#0MS;
   STAT103 := S5T#0MS;
   STAT104 := S5T#0MS;
   STAT105 := S5T#0MS;
   STAT106 := S5T#0MS;
   STAT107 := S5T#0MS;
   STAT108 := S5T#0MS;
   STAT109 := S5T#0MS;
   STAT110 := S5T#0MS;
   STAT111 := S5T#0MS;
   STAT112 := S5T#0MS;
   STAT113 := S5T#0MS;
   STAT114 := S5T#0MS;
   STAT115 := S5T#0MS;
   STAT116 := S5T#0MS;
   STAT117 := S5T#0MS;
   STAT118 := S5T#0MS;
   STAT119 := S5T#0MS;
   STAT120 := S5T#0MS;
   STAT121 := S5T#0MS;
   STAT122 := S5T#0MS;
   STAT123 := S5T#0MS;
   STAT124 := S5T#0MS;
   STAT125 := S5T#0MS;
   STAT126 := S5T#0MS;
   STAT127 := S5T#0MS;
   STAT128 := 0;
   STAT129 := W#16#0;
   STAT130 := W#16#0;
   STAT131 := W#16#0;
   STAT132 := W#16#0;
   STAT133 := W#16#0;
   STAT134 := W#16#0;
   STAT135 := W#16#0;
   STAT136 := W#16#0;
   STAT137 := W#16#0;
   STAT138 := W#16#0;
   STAT139 := W#16#0;
   STAT140 := W#16#0;
   STAT141 := W#16#0;
   STAT142 := W#16#0;
   STAT143 := W#16#0;
   STAT144 := W#16#0;
   STAT145 := W#16#0;
   STAT146 := W#16#0;
   STAT147 := W#16#0;
   STAT148 := W#16#0;
   STAT149 := W#16#0;
   STAT150 := B#16#0;
   STAT151 := B#16#1;
   STAT152 := B#16#0;
   STAT153 := B#16#0;
   STAT154 := W#16#0;
   STAT155 := W#16#5;
   STAT156 := W#16#0;
   STAT157 := W#16#0;
   STAT158 := B#16#0;
   STAT159 := B#16#0;
   STAT160 := B#16#0;
   STAT161 := B#16#0;
   STAT162 := B#16#0;
   STAT163 := B#16#0;
   STAT164 := B#16#0;
   STAT165 := B#16#0;
   STAT166 := B#16#0;
   STAT167 := B#16#0;
   STAT168 := B#16#0;
   STAT169 := B#16#0;
   STAT170 := B#16#0;
   STAT171 := B#16#0;
   STAT172 := B#16#0;
   STAT173 := B#16#0;
   STAT174 := B#16#0;
   STAT175 := B#16#0;
   STAT176 := B#16#0;
   STAT177 := B#16#0;
   STAT178 := W#16#0;
   STAT179 := W#16#0;
   STAT180 := W#16#0;
   STAT181 := W#16#0;
   STAT182 := 1;
   STAT183 := B#16#0;
   STAT184 := B#16#1;
   STAT185 := B#16#0;
   STAT186 := B#16#13;
   STAT187 := W#16#0;
   STAT188 := FALSE;
   STAT189 := FALSE;
   STAT190 := FALSE;
   STAT191 := FALSE;
   STAT192 := FALSE;
   STAT193 := FALSE;
   STAT194 := FALSE;
   STAT195 := FALSE;
   STAT196 := TRUE;
   STAT197 := FALSE;
   STAT198 := FALSE;
   STAT199 := FALSE;
   STAT200 := FALSE;
   STAT201 := FALSE;
   STAT202 := FALSE;
   STAT203 := FALSE;
   STAT204 := FALSE;
   STAT205 := FALSE;
   STAT206 := FALSE;
   STAT207 := FALSE;
   STAT208 := FALSE;
   STAT209 := FALSE;
   STAT210 := FALSE;
   STAT211 := FALSE;
   STAT212 := FALSE;
   STAT213 := FALSE;
   STAT214 := FALSE;
   STAT215 := FALSE;
   STAT216 := FALSE;
   STAT217 := FALSE;
   STAT218 := FALSE;
   STAT219 := FALSE;
   STAT220 := W#16#0;
   STAT221 := W#16#0;
   STAT222 := 0;
   STAT223 := B#16#0;
   STAT224 := B#16#0;
   STAT225 := FALSE;
   STAT226 := FALSE;
   STAT227 := FALSE;
   STAT228 := FALSE;
   STAT229 := FALSE;
   STAT230 := FALSE;
   STAT231 := FALSE;
   STAT232 := FALSE;
   STAT233 := FALSE;
   STAT234 := FALSE;
   STAT235 := FALSE;
   STAT236 := FALSE;
   STAT237 := FALSE;
   STAT238 := FALSE;
   STAT239 := FALSE;
   STAT240 := FALSE;
   STAT241 := W#16#0;
   STAT242 := 12;
   STAT243 := W#16#185;
   STAT244 := FALSE;
   STAT245 := FALSE;
   STAT246 := TRUE;
   STAT247 := FALSE;
   STAT248 := FALSE;
   STAT249 := FALSE;
   STAT250 := FALSE;
   STAT251 := FALSE;
   STAT252 := FALSE;
   STAT253 := FALSE;
   STAT254 := FALSE;
   STAT255 := FALSE;
   STAT256 := FALSE;
   STAT257 := FALSE;
   STAT258 := FALSE;
   STAT259 := FALSE;
   STAT260 := FALSE;
   STAT261 := FALSE;
   STAT262 := FALSE;
   STAT263 := FALSE;
   STAT264 := FALSE;
   STAT265 := FALSE;
   STAT266 := FALSE;
   STAT267 := FALSE;
   STAT268 := FALSE;
   STAT269 := FALSE;
   STAT270 := FALSE;
   STAT271 := FALSE;
   STAT272 := FALSE;
   STAT273 := FALSE;
   STAT274 := FALSE;
   STAT275 := FALSE;
   STAT276 := W#16#0;
   STAT277 := W#16#0;
   STAT278 := W#16#0;
   STAT279 := W#16#0;
   STAT280 := W#16#0;
   STAT281 := W#16#0;
   STAT282 := FALSE;
   STAT283 := FALSE;
   STAT284 := FALSE;
   STAT285 := FALSE;
   STAT286 := FALSE;
   STAT287 := FALSE;
   STAT288 := FALSE;
   STAT289 := FALSE;
   STAT290 := FALSE;
   STAT291 := FALSE;
   STAT292 := FALSE;
   STAT293 := FALSE;
   STAT294 := FALSE;
   STAT295 := FALSE;
   STAT296 := FALSE;
   STAT297 := FALSE;
   STAT298 := FALSE;
   STAT299 := FALSE;
   STAT300 := FALSE;
   STAT301 := FALSE;
   STAT302 := FALSE;
   STAT303 := FALSE;
   STAT304 := FALSE;
   STAT305 := TRUE;
   STAT306 := FALSE;
   STAT307 := FALSE;
   STAT308 := FALSE;
   STAT309 := FALSE;
   STAT310 := FALSE;
   STAT311 := FALSE;
   STAT312 := FALSE;
   STAT313 := FALSE;
   STAT314 := FALSE;
   STAT315 := FALSE;
   STAT316 := FALSE;
   STAT317 := FALSE;
   STAT318 := TRUE;
   STAT319 := FALSE;
   STAT320 := FALSE;
   STAT321 := FALSE;
   STAT322 := FALSE;
   STAT323 := FALSE;
   STAT324 := FALSE;
   STAT325 := FALSE;
   STAT326 := FALSE;
   STAT327 := FALSE;
   STAT328 := FALSE;
   STAT329 := FALSE;
   STAT330 := FALSE;
   STAT331 := FALSE;
   STAT332 := FALSE;
   STAT333 := FALSE;
   STAT334 := FALSE;
   STAT335 := FALSE;
   STAT336 := FALSE;
   STAT337 := FALSE;
   STAT338 := FALSE;
   STAT339 := FALSE;
   STAT340 := FALSE;
   STAT341 := FALSE;
   STAT342 := FALSE;
   STAT343 := FALSE;
   STAT344 := FALSE;
   STAT345 := FALSE;
   STAT346 := FALSE;
   STAT347 := FALSE;
   STAT348 := FALSE;
   STAT349 := FALSE;
   STAT350 := FALSE;
   STAT351 := FALSE;
   STAT352 := FALSE;
   STAT353 := FALSE;
   STAT354 := FALSE;
   STAT355 := FALSE;
   STAT356 := FALSE;
   STAT357 := FALSE;
   STAT358 := FALSE;
   STAT359 := FALSE;
   STAT360 := FALSE;
   STAT361 := FALSE;
   STAT362 := B#16#0;
   STAT363 := B#16#0;
   STAT364 := FALSE;
   STAT365 := FALSE;
   STAT366 := FALSE;
   STAT367 := FALSE;
   STAT368 := FALSE;
   STAT369 := FALSE;
   STAT370 := FALSE;
   STAT371 := FALSE;
   STAT372 := FALSE;
   STAT373 := FALSE;
   STAT374 := FALSE;
   STAT375 := FALSE;
   STAT376 := FALSE;
   STAT377 := FALSE;
   STAT378 := FALSE;
   STAT379 := FALSE;
   STAT380 := 0.000000e+000;
   STAT381 := 1.000000e+003;
   STAT382 := 1.500000e+003;
   STAT383 := 2.100000e+002;
   STAT384 := 7.100000e+002;
   STAT385 := 1.700000e+002;
   STAT386 := 2.500000e+002;
   STAT387 := 7.000000e+002;
   STAT388 := 1.450000e+003;
   STAT389 := 2.400013e+002;
   STAT390 := 7.100000e+002;
   STAT391 := 2.400013e+002;
   STAT392 := 1.500000e+003;
   STAT393 := 9.466667e+002;
   STAT394 := 2.001593e+003;
   STAT395 := DW#16#44F52525;
   STAT396 := 4.380000e+002;
   STAT397 := 4.560000e+002;
   STAT398 := 2.895000e+002;
   STAT399 := 0.000000e+000;
   STAT400 := 4.515000e+002;
   STAT401 := 3.735000e+002;
   STAT402 := 3;
   STAT403 := 350;
   STAT404 := 0.000000e+000;
   STAT405 := 0.000000e+000;
   STAT406 := 0.000000e+000;
   STAT407 := 4.000000e+001;
   STAT408 := 0.000000e+000;
   STAT409 := 6.289640e+003;
   STAT410 := 2.471810e-041;
   STAT411 := -2.403259e-004;
   STAT412 := 0.000000e+000;
   STAT413 := 0.000000e+000;
END_DATA_BLOCK

DATA_BLOCK "ALLARMI_MP270"
AUTHOR : LD
FAMILY : DESTACK
NAME : ALLARMI
VERSION : 0.1


  STRUCT
   Allar_9 : BOOL ;	//Magnetotermici 24 Volt drive
   Allar_10 : BOOL ;	//Magnetotermico alimentazione uscite plc
   Allar_11 : BOOL ;	//Magnetotermico alimentazione ingressi plc
   Allar_12 : BOOL ;	//Magnetotermico traslazione tavola 1
   Allar_13 : BOOL ;	//Magnetotermico traslazione tavola 2
   Allar_14 : BOOL ;	//Magnetotermico pompa tavola 1
   Allar_15 : BOOL ;	//Magnetotermico pompa tavola 2
   Allar_16 : BOOL ;	//Magnetotermico regolazione altezza sfogliatore
   Allar_1 : BOOL ;	//Emergenze da ripristinare
   Allar_2 : BOOL ;	//Emergenza pannello di comando
   Allar_3 : BOOL ;	//Emergenza sfogliatore lato operatore
   Allar_4 : BOOL ;	//Emergenza porta sfogliatore lato opposto operatore
   Allar_5 : BOOL ;	//Emergenza porta lato operatore
   Allar_6 : BOOL ;	//Emergenza porta lato opposto operatore
   Allar_7 : BOOL ;	//Porta aperta lato operatore
   Allar_8 : BOOL ;	//Porta aperta lato opposto operatore
   Allar_25 : BOOL ;	//Magnetotermico ventilatore armadio
   Allar_26 : BOOL ;	//Magnetotermico generale ausiliari
   Allar_27 : BOOL ;	//Antischiacciamento tavola 1 sx
   Allar_28 : BOOL ;	//Antischiacciamento tavola 2 dx
   Allar_29 : BOOL ;	//Anticollisione tavola 1 sx
   Allar_30 : BOOL ;	//Anticollisione tavola 2 dx
   Allar_31 : BOOL ;	//Oltrecorsa salita tavola
   Allar_32 : BOOL ;	//Barriera di sicurezza dx lato opposto operatore
   Allar_17 : BOOL ;	//Magnetotermico regolazione altezza centratore
   Allar_18 : BOOL ;	//Magnetotermico traslazione centratore
   Allar_19 : BOOL ;	//Magnetotermico regolazione posteriore sx centratore
   Allar_20 : BOOL ;	//Magnetotermico regolazione posteriore dx centratore
   Allar_21 : BOOL ;	//Magnetotermico regolazione anteriore sx centratore
   Allar_22 : BOOL ;	//Magnetotermico regolazione anteriore dx centratore
   Allar_23 : BOOL ;	//Magnetotermico regolazione laterale dx centratore
   Allar_24 : BOOL ;	//Magnetotermico regolazione laterale sx centratore
   Allar_41 : BOOL ;	//Sicurezze antischiacc.e anticollisione escluse
   Allar_42 : BOOL ;	//Disfunzione micro P.E. su centratore
   Allar_43 : BOOL ;	//Magnetotermico braccio ABB
   Allar_44 : BOOL ;	//Selezione cambio produzione manuale inserito
   Allar_45 : BOOL ;	//Magnetotermici 24 Volt F4-F5-F6
   Allar_46 : BOOL ;	//Magnetotermici 24 Volt F8-F9-F10
   Allar_47 : BOOL ;	//Bassa pressione bilanciamento braccio
   Allar_48 : BOOL ;	//Foglio presente solo su braccio centratore
   Allar_33 : BOOL ;	//Start programma s4c+ troppo lungo (ABB)
   Allar_34 : BOOL ;	//Programma s4c+ non esistente (ABB)
   Allar_35 : BOOL ;	//Braccio ABB non in posizione di parcheggio
   Allar_36 : BOOL ;	//Programma braccio ABB diverso da Destacker
   Allar_37 : BOOL ;	//Anomalia inserzione motori ABB
   Allar_38 : BOOL ;	//Programma ABB non in run
   Allar_39 : BOOL ;	//Braccio in posizione di parcheggio
   Allar_40 : BOOL ;	//Posizionare ABB in cambio produzione
   Allar_57 : BOOL ;	//Fine pacco tranciati su tavola
   Allar_58 : BOOL ;	//Perdita lamiera braccio caricatore lato sfogliatore
   Allar_59 : BOOL ;	//Pressa non al P.M.S.
   Allar_60 : BOOL ;	//Spina start pressa non inserita
   Allar_61 : BOOL ;	//FC TAVOLA 1 lato disimpilamento
   Allar_62 : BOOL ;	//FC TAVOLA 2 lato disimpilamento
   Allar_63 : BOOL ;	//Allarme da robot perdita pezzo
   Allar_64 : BOOL ;	//Allarme riparo aperto isola 1
   Allar_49 : BOOL ;	//Lamiera nello stampo
   Allar_50 : BOOL ;	//Lamiera su tooling in posizione di produzione
   Allar_51 : BOOL ;	//Pressa non pronta per auto
   Allar_52 : BOOL ;	//Doppio foglio
   Allar_53 : BOOL ;	//Robot non pronto per auto
   Allar_54 : BOOL ;	//Assenza foglio su stazione di centraggio
   Allar_55 : BOOL ;	//Braccio ABB non in posizione di produzione
   Allar_56 : BOOL ;	//Attesa pezzo prelevato dallo stampo (robot isola1)
   Allar_73 : BOOL ;	//Ciclo cambio matricola in corso
   Allar_74 : BOOL ;	//Ciclo cambio pacco in corso
   Allar_75 : BOOL ;	//Sicurezza magneti sfogliatore
   Allar_76 : BOOL ;	//Pacco non arrivato in posizione di sfogliatura
   Allar_77 : BOOL ;	//Tavola 1 non in finecorsa lato caricamento (indietro
   Allar_78 : BOOL ;	//Tavola 2 non in finecorsa lato caricamento (indietro
   Allar_79 : BOOL ;	//Magneti sfogliatori non rientrati
   Allar_80 : BOOL ;	//Anticollisione tavola 1 o 2 per urto accidentale
   Allar_65 : BOOL ;	//Barriera di sicurezza sx lato operatore
   Allar_66 : BOOL ;	//cancelletti tavola 1
   Allar_67 : BOOL ;	//cancelletti tavola 2x
   Allar_68 : BOOL ;	//Unita' di centraggio sbloccata
   Allar_69 : BOOL ;	//Cambio matricola quota non raggiunta
   Allar_70 : BOOL ;	//Batteria plc scarica
   Allar_71 : BOOL ;	//Tavola 1 non abbassata
   Allar_72 : BOOL ;	//Tavola 2 non abbassata
   Allar_89 : BOOL ;	//Contemporaneita' fc  traslazione tavola 1
   Allar_90 : BOOL ;	//Contemporaneita' fc  traslazione tavola 2
   Allar_91 : BOOL ;	//Contemporaneita' fc regolazione altezza sfogliatore
   Allar_92 : BOOL ;	//Contemporaneita' fc  regolazione altezza centraggio
   Allar_93 : BOOL ;	//Contemporaneita' fc  traslazione centratore
   Allar_94 : BOOL ;	//Contemporaneita' fc  regolazione centraggio post.SX
   Allar_95 : BOOL ;	//Contemporaneita' fc  regolazione centraggio post.DX
   Allar_96 : BOOL ;	//Contemporaneita' fc  regolazione centraggio ant.
   Allar_81 : BOOL ;	//Muting inserito tavola 1
   Allar_82 : BOOL ;	//Muting inserito tavola 2
   Allar_83 : BOOL ;	//Comandi disinseriti
   Allar_84 : BOOL ;	//Braccio ABB in posizione di prelievo
   Allar_85 : BOOL ;	//Anomalia vuoto su centratore
   Allar_86 : BOOL ;	//Anomalia vuoto su sfogliatore
   Allar_87 : BOOL ;	//Quota tavola non raggiunta
   Allar_88 : BOOL ;	//Selettore programmazione inserito
   Allar_105 : BOOL ;	//Anomalia fc  tavola 1 avanti lato dispilamento
   Allar_106 : BOOL ;	//Anomalia fc  tavola 1 indietro lato carico
   Allar_107 : BOOL ;	//Anomalia fc  tavola 2 avanti lato dispilamento
   Allar_108 : BOOL ;	//Anomalia fc  tavola 2 indietro lato carico
   Allar_109 : BOOL ;
   Allar_110 : BOOL ;
   Allar_111 : BOOL ;
   Allar_112 : BOOL ;
   Allar_97 : BOOL ;	//Selezione cambio produzione in automatico
   Allar_98 : BOOL ;	//Contemporaneita' fc  centratura laterale dx
   Allar_99 : BOOL ;	//Contemporaneita' fc centratura laterale sx
   Allar_100 : BOOL ;	//Time out centraggi longitudinali fuori
   Allar_101 : BOOL ;	//Time out centraggi laterale fuori
   Allar_102 : BOOL ;	//Contemporaneita' fc blocc/sblocc centratore
   Allar_103 : BOOL ;	//Contemporaneita' fc  sollevamento tavola 1
   Allar_104 : BOOL ;	//Contemporaneita' fc  sollevamento tavola 2
   Allar_121 : BOOL ;	//Assenza pedana materiale su tavola zona sfogliatura
   Allar_122 : BOOL ;	//Fotocellula 45B1 H200 guasta o disallineata
   Allar_123 : BOOL ;	//Fotocellula 45B3 H120 guasta o disallineata
   Allar_124 : BOOL ;	//Salire con la tavola in manuale
   Allar_125 : BOOL ;	//Anomalia dispositivo Klaska (cavo interrotto)
   Allar_126 : BOOL ;	//Time out Unita' di centraggio bloccata
   Allar_127 : BOOL ;	//Time out Unita' di centraggio sbloccata
   Allar_128 : BOOL ;	//Magnetotermico trasformatore brushless centratori (12QF2)
   Allar_113 : BOOL ;	//Motori ABB non inseriti
   Allar_114 : BOOL ;	//Cambio pacco prenotato
   Allar_115 : BOOL ;
   Allar_116 : BOOL ;	//Tavole 1 e 2  in muting
   Allar_117 : BOOL ;	//Klascka non rileva sequenza 2Fogli, 1Foglio, 0Fogli
   Allar_118 : BOOL ;	//Klascka non rileva 2 fogli nel prelievo
   Allar_119 : BOOL ;	//Klascka rileva 0 fogli nel ciclo di carico
   Allar_120 : BOOL ;	//Braccio ABB non in posizione di prelievo
   Allar_137 : BOOL ;	//Time out salita regolazione altezza centratore
   Allar_138 : BOOL ;	//Time out discesa regolazione altezza centratore
   Allar_139 : BOOL ;	//Time out centratore verso pressa
   Allar_140 : BOOL ;	//Time out centratore verso sfogliatore
   Allar_141 : BOOL ;	//Time out indietro magnete 1
   Allar_142 : BOOL ;	//Time out avanti magnete 1
   Allar_143 : BOOL ;	//Time out indietro magnete 2
   Allar_144 : BOOL ;	//Time out avanti magnete 2
   Allar_129 : BOOL ;	//Contemporaneita' fc magnete 1
   Allar_130 : BOOL ;	//Contemporaneita' fc magnete 2
   Allar_131 : BOOL ;	//Contemporaneita' fc magnete 3
   Allar_132 : BOOL ;	//Contemporaneita' fc magnete 4
   Allar_133 : BOOL ;	//Contemporaneita' fc magnete 5
   Allar_134 : BOOL ;	//Contemporaneita' fc magnete 6
   Allar_135 : BOOL ;	//Contemporaneita' fc magnete laterale sx
   Allar_136 : BOOL ;	//Contemporaneita' fc magnete laterale dx
   Allar_153 : BOOL ;	//Time out indietro magnete laterale sx
   Allar_154 : BOOL ;	//Time out avanti magnete laterale sx
   Allar_155 : BOOL ;	//Time out indietro magnete laterale dx
   Allar_156 : BOOL ;	//Time out avanti magnete laterale dx
   Allar_157 : BOOL ;	//Time out chiusura braccio magnete laterale sx
   Allar_158 : BOOL ;	//Time out apertura braccio magnete laterale sx
   Allar_159 : BOOL ;	//Time out chiusura braccio magnete laterale dx
   Allar_160 : BOOL ;	//Time out apertura braccio magnete laterale dx
   Allar_145 : BOOL ;	//Time out indietro magnete 3
   Allar_146 : BOOL ;	//Time out avanti magnete 3
   Allar_147 : BOOL ;	//Time out indietro magnete 4
   Allar_148 : BOOL ;	//Time out avanti magnete 4
   Allar_149 : BOOL ;	//Time out indietro magnete 5
   Allar_150 : BOOL ;	//Time out avanti magnete 5
   Allar_151 : BOOL ;	//Time out indietro magnete 6
   Allar_152 : BOOL ;	//Time out avanti magnete 6
   Allar_169 : BOOL ;	//Porta aperta sfogliatore lato dx
   Allar_170 : BOOL ;	//Porta aperta sfogliatore lato sx
   Allar_171 : BOOL ;	//Extracorsa avanti tavola 1
   Allar_172 : BOOL ;	//Extracorsa avanti tavola 2
   Allar_173 : BOOL ;	//Extracorsa indietro tavola 1
   Allar_174 : BOOL ;	//Extracorsa indietro tavola 2
   Allar_175 : BOOL ;	//Emergenza ABB
   Allar_176 : BOOL ;	//Extracorsa incremento pacco (fc su braccio ABB)
   Allar_161 : BOOL ;
   Allar_162 : BOOL ;
   Allar_163 : BOOL ;
   Allar_164 : BOOL ;
   Allar_165 : BOOL ;
   Allar_166 : BOOL ;
   Allar_167 : BOOL ;
   Allar_168 : BOOL ;
   Allar_185 : BOOL ;	//Attenzione!  dovresti aprire i centraggi
   Allar_186 : BOOL ;	//Emergenza linea Comau da ripristinare
   Allar_187 : BOOL ;	//Ripristinare sensore presenza su braccio ABB
   Allar_188 : BOOL ;	//Mancanza improvvisa consenso ingr.pressa
   Allar_189 : BOOL ;	//ABB non in start auto  (ciclo in corso)
   Allar_190 : BOOL ;	//Posizionare i gruppi a riposo per cambio tooling
   Allar_191 : BOOL ;	//Retrofitting pulsanti EM non premuti per comau
   Allar_192 : BOOL ;	//Retrofitting Ripari chiusi per ABB
   Allar_177 : BOOL ;	//Tavola 1 piena in uscita
   Allar_178 : BOOL ;	//Tavola 2 piena in uscita
   Allar_179 : BOOL ;	//Retrofitting rele' ciclo automatico destacker
   Allar_180 : BOOL ;	//Retrofitting rele' ripari/barriere destacker
   Allar_181 : BOOL ;	//Retrofitting rele' start pressa (per comau)
   Allar_182 : BOOL ;	//Retrofitting Rele' emergenza Destaker
   Allar_183 : BOOL ;	//Retrofitting anticollisione/antischiacciamento tavole
   Allar_184 : BOOL ;	//Retrofitting override barriere
   word_3042 : BOOL ;
   word_3043 : BOOL ;
   word_3044 : BOOL ;
   word_3045 : BOOL ;
   word_3046 : BOOL ;
   word_3047 : BOOL ;
   word_3048 : BOOL ;
   word_3049 : BOOL ;
   word_3050 : BOOL ;
   word_3051 : BOOL ;
   word_3052 : BOOL ;
   word_3053 : BOOL ;
   word_3054 : BOOL ;
   word_3055 : BOOL ;
   word_3056 : BOOL ;
   word_3057 : BOOL ;
   word_3058 : BOOL ;
   word_3059 : BOOL ;
   word_3060 : BOOL ;
   word_3061 : BOOL ;
   word_3062 : BOOL ;
   word_3063 : BOOL ;
  END_STRUCT ;
BEGIN
   Allar_9 := FALSE;
   Allar_10 := FALSE;
   Allar_11 := FALSE;
   Allar_12 := FALSE;
   Allar_13 := FALSE;
   Allar_14 := FALSE;
   Allar_15 := FALSE;
   Allar_16 := FALSE;
   Allar_1 := FALSE;
   Allar_2 := FALSE;
   Allar_3 := FALSE;
   Allar_4 := FALSE;
   Allar_5 := FALSE;
   Allar_6 := FALSE;
   Allar_7 := FALSE;
   Allar_8 := FALSE;
   Allar_25 := FALSE;
   Allar_26 := FALSE;
   Allar_27 := FALSE;
   Allar_28 := FALSE;
   Allar_29 := FALSE;
   Allar_30 := FALSE;
   Allar_31 := FALSE;
   Allar_32 := FALSE;
   Allar_17 := FALSE;
   Allar_18 := FALSE;
   Allar_19 := FALSE;
   Allar_20 := FALSE;
   Allar_21 := FALSE;
   Allar_22 := FALSE;
   Allar_23 := FALSE;
   Allar_24 := FALSE;
   Allar_41 := FALSE;
   Allar_42 := FALSE;
   Allar_43 := FALSE;
   Allar_44 := FALSE;
   Allar_45 := FALSE;
   Allar_46 := FALSE;
   Allar_47 := FALSE;
   Allar_48 := FALSE;
   Allar_33 := FALSE;
   Allar_34 := FALSE;
   Allar_35 := FALSE;
   Allar_36 := FALSE;
   Allar_37 := FALSE;
   Allar_38 := FALSE;
   Allar_39 := FALSE;
   Allar_40 := FALSE;
   Allar_57 := FALSE;
   Allar_58 := FALSE;
   Allar_59 := FALSE;
   Allar_60 := FALSE;
   Allar_61 := FALSE;
   Allar_62 := FALSE;
   Allar_63 := FALSE;
   Allar_64 := FALSE;
   Allar_49 := FALSE;
   Allar_50 := FALSE;
   Allar_51 := FALSE;
   Allar_52 := FALSE;
   Allar_53 := FALSE;
   Allar_54 := FALSE;
   Allar_55 := FALSE;
   Allar_56 := FALSE;
   Allar_73 := FALSE;
   Allar_74 := FALSE;
   Allar_75 := FALSE;
   Allar_76 := FALSE;
   Allar_77 := FALSE;
   Allar_78 := FALSE;
   Allar_79 := FALSE;
   Allar_80 := FALSE;
   Allar_65 := FALSE;
   Allar_66 := FALSE;
   Allar_67 := FALSE;
   Allar_68 := FALSE;
   Allar_69 := FALSE;
   Allar_70 := FALSE;
   Allar_71 := FALSE;
   Allar_72 := FALSE;
   Allar_89 := FALSE;
   Allar_90 := FALSE;
   Allar_91 := FALSE;
   Allar_92 := FALSE;
   Allar_93 := FALSE;
   Allar_94 := FALSE;
   Allar_95 := FALSE;
   Allar_96 := FALSE;
   Allar_81 := FALSE;
   Allar_82 := FALSE;
   Allar_83 := FALSE;
   Allar_84 := FALSE;
   Allar_85 := FALSE;
   Allar_86 := FALSE;
   Allar_87 := FALSE;
   Allar_88 := FALSE;
   Allar_105 := FALSE;
   Allar_106 := FALSE;
   Allar_107 := FALSE;
   Allar_108 := FALSE;
   Allar_109 := FALSE;
   Allar_110 := FALSE;
   Allar_111 := FALSE;
   Allar_112 := FALSE;
   Allar_97 := FALSE;
   Allar_98 := FALSE;
   Allar_99 := FALSE;
   Allar_100 := FALSE;
   Allar_101 := FALSE;
   Allar_102 := FALSE;
   Allar_103 := FALSE;
   Allar_104 := FALSE;
   Allar_121 := FALSE;
   Allar_122 := FALSE;
   Allar_123 := FALSE;
   Allar_124 := FALSE;
   Allar_125 := FALSE;
   Allar_126 := FALSE;
   Allar_127 := FALSE;
   Allar_128 := TRUE;
   Allar_113 := FALSE;
   Allar_114 := FALSE;
   Allar_115 := FALSE;
   Allar_116 := FALSE;
   Allar_117 := FALSE;
   Allar_118 := FALSE;
   Allar_119 := FALSE;
   Allar_120 := FALSE;
   Allar_137 := FALSE;
   Allar_138 := FALSE;
   Allar_139 := FALSE;
   Allar_140 := FALSE;
   Allar_141 := FALSE;
   Allar_142 := FALSE;
   Allar_143 := FALSE;
   Allar_144 := FALSE;
   Allar_129 := FALSE;
   Allar_130 := FALSE;
   Allar_131 := FALSE;
   Allar_132 := FALSE;
   Allar_133 := FALSE;
   Allar_134 := FALSE;
   Allar_135 := FALSE;
   Allar_136 := FALSE;
   Allar_153 := FALSE;
   Allar_154 := FALSE;
   Allar_155 := FALSE;
   Allar_156 := FALSE;
   Allar_157 := FALSE;
   Allar_158 := FALSE;
   Allar_159 := FALSE;
   Allar_160 := FALSE;
   Allar_145 := FALSE;
   Allar_146 := FALSE;
   Allar_147 := FALSE;
   Allar_148 := FALSE;
   Allar_149 := FALSE;
   Allar_150 := FALSE;
   Allar_151 := FALSE;
   Allar_152 := FALSE;
   Allar_169 := FALSE;
   Allar_170 := FALSE;
   Allar_171 := FALSE;
   Allar_172 := FALSE;
   Allar_173 := FALSE;
   Allar_174 := FALSE;
   Allar_175 := FALSE;
   Allar_176 := FALSE;
   Allar_161 := FALSE;
   Allar_162 := FALSE;
   Allar_163 := FALSE;
   Allar_164 := FALSE;
   Allar_165 := FALSE;
   Allar_166 := FALSE;
   Allar_167 := FALSE;
   Allar_168 := FALSE;
   Allar_185 := FALSE;
   Allar_186 := FALSE;
   Allar_187 := FALSE;
   Allar_188 := FALSE;
   Allar_189 := FALSE;
   Allar_190 := FALSE;
   Allar_191 := FALSE;
   Allar_192 := FALSE;
   Allar_177 := FALSE;
   Allar_178 := FALSE;
   Allar_179 := FALSE;
   Allar_180 := FALSE;
   Allar_181 := FALSE;
   Allar_182 := FALSE;
   Allar_183 := FALSE;
   Allar_184 := FALSE;
   word_3042 := FALSE;
   word_3043 := FALSE;
   word_3044 := FALSE;
   word_3045 := FALSE;
   word_3046 := FALSE;
   word_3047 := FALSE;
   word_3048 := FALSE;
   word_3049 := FALSE;
   word_3050 := FALSE;
   word_3051 := FALSE;
   word_3052 := FALSE;
   word_3053 := FALSE;
   word_3054 := FALSE;
   word_3055 := FALSE;
   word_3056 := FALSE;
   word_3057 := FALSE;
   word_3058 := FALSE;
   word_3059 := FALSE;
   word_3060 := FALSE;
   word_3061 := FALSE;
   word_3062 := FALSE;
   word_3063 := FALSE;
END_DATA_BLOCK

DATA_BLOCK "MATRICOLA ATTUALE"
AUTHOR : Lodato
FAMILY : DESTACK
NAME : DATI
VERSION : 0.1


  STRUCT
   LARGHEZZA_LAMIERA : REAL  := 1.500000e+003;	//LARGHEZZA LAMIERA ATTUALE
   COMPENSAZ_TAV_1 : REAL ;	//COMPENSAZIONE TAVOLA 1
   QUOTA_H_SFOGLIATORE : REAL ;	//Quota impostata altezza sfogliatore
   QUOTA_H_CENTRATORE : REAL ;	//Quota impostata altezza centratore
   word16 : S5TIME ;
   INCLINAZ_TAVOLA_ESCLUSA : BOOL ;	//INCLINAZIONE TAVOLA ESCLUSA
   dword20 : REAL ;
   dword24 : REAL ;
   dword28 : REAL ;
   dword32 : REAL ;
   dword36 : REAL ;
   NR_MATRICOLA : INT  := 1;	//Numero di matricola
   word42 : WORD ;
   MAGNETE_1_ESCLUSO : BOOL ;	//MAGNETE 1 ESCLUSO DA MP270
   MAGNETE_2_ESCLUSO : BOOL ;	//MAGNETE 2 ESCLUSO DA MP270
   MAGNETE_3_ESCLUSO : BOOL ;	//MAGNETE 3 ESCLUSO DA MP270
   MAGNETE_4_ESCLUSO : BOOL ;	//MAGNETE 4 ESCLUSO DA MP270
   MAGNETE_5_ESCLUSO : BOOL ;	//MAGNETE 5 ESCLUSO DA MP270
   MAGNETE_6_ESCLUSO : BOOL ;	//MAGNETE 6 ESCLUSO DA MP270
   MAGNETE_LAT_SX_ESCLUSO : BOOL ;	//MAGNETE LATERALE SX ESCLUSO DA MP270
   MAGNETE_LAT_DX_ESCLUSO : BOOL ;	//MAGNETE LATERALE DX ESCLUSO DA MP270
   COMPENSAZ_TAV_2 : REAL ;	//COMPENSAZIONE TAVOLA 2
   STAT22 : WORD ;
   STAT23 : WORD ;
   STAT24 : WORD ;
   STAT25 : WORD ;
   STAT251 : WORD ;
   STAT26 : TIME ;
   STAT29 : TIME ;
   STAT30 : TIME ;
   STAT31 : TIME ;
   C1_Timer : REAL ;	//Centratore 1: Timer ritardo partenza
   C2_Timer : REAL ;	//Centratore 2: Timer ritardo partenza
   C3_Timer : REAL ;	//Centratore 3: Timer ritardo partenza
   C4_Timer : REAL ;	//Centratore 4: Timer ritardo partenza
   C5_Timer : REAL ;	//Centratore 5: Timer ritardo partenza
   C6_Timer : REAL ;	//Centratore 6: Timer ritardo partenza
   C1_Posizione_1 : DINT  := L#500000;	//Centratore 1: Posizione 1 di avicinamento
   C1_Posizione_2 : DINT  := L#520000;	//Centratore 1: Posizione 2 di cambio velocita'
   C1_Posizione_3 : DINT  := L#530000;	//Centratore 1: Posizione 3 di cambio velocita'
   C1_Posizione_4 : DINT  := L#565400;	//Centratore 1: Posizione 4 di arrivo
   C1_Velocita_1 : DINT  := L#50;	//Centratore 1: Velocita' 1 di avvicinamento
   C1_Velocita_2 : DINT  := L#50;	//Centratore 1: Velocita' 2
   C1_Velocita_3 : DINT  := L#50;	//Centratore 1: Velocita' 3
   C1_Velocita_4 : DINT  := L#50;	//Centratore 1: Velocita' 4 di arrivo
   C1_Accell_1 : DINT  := L#500;	//Centratore 1: Accelerazione 1 di avvicinamento
   C1_Accell_2 : DINT  := L#500;	//Centratore 1: Accelerazione 2
   C1_Accell_3 : DINT  := L#500;	//Centratore 1: Accelerazione 3
   C1_Accell_4 : DINT  := L#500;	//Centratore 1: Accelerazione 4 di arrivo
   word_148 : WORD ;
   C2_Posizione_1 : DINT  := L#500000;	//Centratore 2: Posizione 1 di avicinamento
   C2_Posizione_2 : DINT  := L#520000;	//Centratore 2: Posizione 2 di cambio velocita'
   C2_Posizione_3 : DINT  := L#530000;	//Centratore 2: Posizione 3 di cambio velocita'
   C2_Posizione_4 : DINT  := L#559000;	//Centratore 2: Posizione 4 di arrivo
   C2_Velocita_1 : DINT  := L#50;	//Centratore 2: Velocita' 1 di avvicinamento
   C2_Velocita_2 : DINT  := L#50;	//Centratore 2: Velocita' 2
   C2_Velocita_3 : DINT  := L#50;	//Centratore 2: Velocita' 3
   C2_Velocita_4 : DINT  := L#50;	//Centratore 2: Velocita' 4 di arrivo
   C2_Accell_1 : DINT  := L#500;	//Centratore 2: Accelerazione 1 di avvicinamento
   C2_Accell_2 : DINT  := L#500;	//Centratore 2: Accelerazione 2
   C2_Accell_3 : DINT  := L#500;	//Centratore 2: Accelerazione 3
   C2_Accell_4 : DINT  := L#500;	//Centratore 2: Accelerazione 4 di arrivo
   word_198 : WORD ;
   C3_Posizione_1 : DINT  := L#630000;	//Centratore 3: Posizione 1 di avicinamento
   C3_Posizione_2 : DINT  := L#650000;	//Centratore 3: Posizione 2 di cambio velocita'
   C3_Posizione_3 : DINT  := L#660000;	//Centratore 3: Posizione 3 di cambio velocita'
   C3_Posizione_4 : DINT  := L#698600;	//Centratore 3: Posizione 4 di arrivo
   C3_Velocita_1 : DINT  := L#50;	//Centratore 3: Velocita' 1 di avvicinamento
   C3_Velocita_2 : DINT  := L#50;	//Centratore 3: Velocita' 2
   C3_Velocita_3 : DINT  := L#50;	//Centratore 3: Velocita' 3
   C3_Velocita_4 : DINT  := L#50;	//Centratore 3: Velocita' 4 di arrivo
   C3_Accell_1 : DINT  := L#500;	//Centratore 3: Accelerazione 1 di avvicinamento
   C3_Accell_2 : DINT  := L#500;	//Centratore 3: Accelerazione 2
   C3_Accell_3 : DINT  := L#500;	//Centratore 3: Accelerazione 3
   C3_Accell_4 : DINT  := L#500;	//Centratore 3: Accelerazione 4 di arrivo
   word_248 : WORD ;
   C4_Posizione_1 : DINT  := L#630000;	//Centratore 4: Posizione 1 di avicinamento
   C4_Posizione_2 : DINT  := L#650000;	//Centratore 4: Posizione 2 di cambio velocita'
   C4_Posizione_3 : DINT  := L#660000;	//Centratore 4: Posizione 3 di cambio velocita'
   C4_Posizione_4 : DINT  := L#706200;	//Centratore 4: Posizione 4 di arrivo
   C4_Velocita_1 : DINT  := L#50;	//Centratore 4: Velocita' 1 di avvicinamento
   C4_Velocita_2 : DINT  := L#50;	//Centratore 4: Velocita' 2
   C4_Velocita_3 : DINT  := L#50;	//Centratore 4: Velocita' 3
   C4_Velocita_4 : DINT  := L#50;	//Centratore 4: Velocita' 4 di arrivo
   C4_Accell_1 : DINT  := L#500;	//Centratore 4: Accelerazione 1 di avvicinamento
   C4_Accell_2 : DINT  := L#500;	//Centratore 4: Accelerazione 2
   C4_Accell_3 : DINT  := L#500;	//Centratore 4: Accelerazione 3
   C4_Accell_4 : DINT  := L#500;	//Centratore 4: Accelerazione 4 di arrivo
   word_298 : WORD ;
   C5_Posizione_1 : DINT  := L#1180000;	//Centratore 5: Posizione 1 di avicinamento
   C5_Posizione_2 : DINT  := L#1200000;	//Centratore 5: Posizione 2 di cambio velocita'
   C5_Posizione_3 : DINT  := L#1220000;	//Centratore 5: Posizione 3 di cambio velocita'
   C5_Posizione_4 : DINT  := L#1247000;	//Centratore 5: Posizione 4 di arrivo
   C5_Velocita_1 : DINT  := L#50;	//Centratore 5: Velocita' 1 di avvicinamento
   C5_Velocita_2 : DINT  := L#50;	//Centratore 5: Velocita' 2
   C5_Velocita_3 : DINT  := L#50;	//Centratore 5: Velocita' 3
   C5_Velocita_4 : DINT  := L#50;	//Centratore 5: Velocita' 4 di arrivo
   C5_Accell_1 : DINT  := L#500;	//Centratore 5: Accelerazione 1 di avvicinamento
   C5_Accell_2 : DINT  := L#500;	//Centratore 5: Accelerazione 2
   C5_Accell_3 : DINT  := L#500;	//Centratore 5: Accelerazione 3
   C5_Accell_4 : DINT  := L#500;	//Centratore 5: Accelerazione 4 di arrivo
   word_348 : WORD ;
   C6_Posizione_1 : DINT  := L#1180000;	//Centratore 6: Posizione 1 di avicinamento
   C6_Posizione_2 : DINT  := L#1200000;	//Centratore 6: Posizione 2 di cambio velocita'
   C6_Posizione_3 : DINT  := L#1220000;	//Centratore 6: Posizione 3 di cambio velocita'
   C6_Posizione_4 : DINT  := L#1237400;	//Centratore 6: Posizione 4 di arrivo
   C6_Velocita_1 : DINT  := L#50;	//Centratore 6: Velocita' 1 di avvicinamento
   C6_Velocita_2 : DINT  := L#50;	//Centratore 6: Velocita' 2
   C6_Velocita_3 : DINT  := L#50;	//Centratore 6: Velocita' 3
   C6_Velocita_4 : DINT  := L#50;	//Centratore 6: Velocita' 4 di arrivo
   C6_Accell_1 : DINT  := L#500;	//Centratore 6: Accelerazione 1 di avvicinamento
   C6_Accell_2 : DINT  := L#500;	//Centratore 6: Accelerazione 2
   C6_Accell_3 : DINT  := L#500;	//Centratore 6: Accelerazione 3
   C6_Accell_4 : DINT  := L#500;	//Centratore 6: Accelerazione 4 di arrivo
   word_398 : WORD ;
  END_STRUCT ;
BEGIN
   LARGHEZZA_LAMIERA := 1.500000e+003;
   COMPENSAZ_TAV_1 := 0.000000e+000;
   QUOTA_H_SFOGLIATORE := 0.000000e+000;
   QUOTA_H_CENTRATORE := 0.000000e+000;
   word16 := S5T#0MS;
   INCLINAZ_TAVOLA_ESCLUSA := FALSE;
   dword20 := 0.000000e+000;
   dword24 := 0.000000e+000;
   dword28 := 0.000000e+000;
   dword32 := 0.000000e+000;
   dword36 := 0.000000e+000;
   NR_MATRICOLA := 1;
   word42 := W#16#0;
   MAGNETE_1_ESCLUSO := FALSE;
   MAGNETE_2_ESCLUSO := FALSE;
   MAGNETE_3_ESCLUSO := FALSE;
   MAGNETE_4_ESCLUSO := FALSE;
   MAGNETE_5_ESCLUSO := FALSE;
   MAGNETE_6_ESCLUSO := FALSE;
   MAGNETE_LAT_SX_ESCLUSO := FALSE;
   MAGNETE_LAT_DX_ESCLUSO := FALSE;
   COMPENSAZ_TAV_2 := 0.000000e+000;
   STAT22 := W#16#0;
   STAT23 := W#16#0;
   STAT24 := W#16#0;
   STAT25 := W#16#0;
   STAT251 := W#16#0;
   STAT26 := T#0MS;
   STAT29 := T#0MS;
   STAT30 := T#0MS;
   STAT31 := T#0MS;
   C1_Timer := 0.000000e+000;
   C2_Timer := 0.000000e+000;
   C3_Timer := 0.000000e+000;
   C4_Timer := 0.000000e+000;
   C5_Timer := 0.000000e+000;
   C6_Timer := 0.000000e+000;
   C1_Posizione_1 := L#500000;
   C1_Posizione_2 := L#520000;
   C1_Posizione_3 := L#530000;
   C1_Posizione_4 := L#565400;
   C1_Velocita_1 := L#50;
   C1_Velocita_2 := L#50;
   C1_Velocita_3 := L#50;
   C1_Velocita_4 := L#50;
   C1_Accell_1 := L#500;
   C1_Accell_2 := L#500;
   C1_Accell_3 := L#500;
   C1_Accell_4 := L#500;
   word_148 := W#16#0;
   C2_Posizione_1 := L#500000;
   C2_Posizione_2 := L#520000;
   C2_Posizione_3 := L#530000;
   C2_Posizione_4 := L#559000;
   C2_Velocita_1 := L#50;
   C2_Velocita_2 := L#50;
   C2_Velocita_3 := L#50;
   C2_Velocita_4 := L#50;
   C2_Accell_1 := L#500;
   C2_Accell_2 := L#500;
   C2_Accell_3 := L#500;
   C2_Accell_4 := L#500;
   word_198 := W#16#0;
   C3_Posizione_1 := L#630000;
   C3_Posizione_2 := L#650000;
   C3_Posizione_3 := L#660000;
   C3_Posizione_4 := L#698600;
   C3_Velocita_1 := L#50;
   C3_Velocita_2 := L#50;
   C3_Velocita_3 := L#50;
   C3_Velocita_4 := L#50;
   C3_Accell_1 := L#500;
   C3_Accell_2 := L#500;
   C3_Accell_3 := L#500;
   C3_Accell_4 := L#500;
   word_248 := W#16#0;
   C4_Posizione_1 := L#630000;
   C4_Posizione_2 := L#650000;
   C4_Posizione_3 := L#660000;
   C4_Posizione_4 := L#706200;
   C4_Velocita_1 := L#50;
   C4_Velocita_2 := L#50;
   C4_Velocita_3 := L#50;
   C4_Velocita_4 := L#50;
   C4_Accell_1 := L#500;
   C4_Accell_2 := L#500;
   C4_Accell_3 := L#500;
   C4_Accell_4 := L#500;
   word_298 := W#16#0;
   C5_Posizione_1 := L#1180000;
   C5_Posizione_2 := L#1200000;
   C5_Posizione_3 := L#1220000;
   C5_Posizione_4 := L#1247000;
   C5_Velocita_1 := L#50;
   C5_Velocita_2 := L#50;
   C5_Velocita_3 := L#50;
   C5_Velocita_4 := L#50;
   C5_Accell_1 := L#500;
   C5_Accell_2 := L#500;
   C5_Accell_3 := L#500;
   C5_Accell_4 := L#500;
   word_348 := W#16#0;
   C6_Posizione_1 := L#1180000;
   C6_Posizione_2 := L#1200000;
   C6_Posizione_3 := L#1220000;
   C6_Posizione_4 := L#1237400;
   C6_Velocita_1 := L#50;
   C6_Velocita_2 := L#50;
   C6_Velocita_3 := L#50;
   C6_Velocita_4 := L#50;
   C6_Accell_1 := L#500;
   C6_Accell_2 := L#500;
   C6_Accell_3 := L#500;
   C6_Accell_4 := L#500;
   word_398 := W#16#0;
END_DATA_BLOCK

DATA_BLOCK DB 12
VERSION : 0.1


  STRUCT
   STAT0 : INT ;
   STAT1 : INT ;
   STAT2 : INT ;
   STAT3 : INT ;
   STAT4 : INT ;
   STAT5 : INT ;
   STAT6 : INT ;
   STAT7 : INT ;
   STAT8 : INT ;
   STAT9 : INT ;
   STAT10 : INT ;
   STAT11 : INT ;
   STAT12 : INT ;
   STAT13 : INT ;
   STAT14 : INT ;
   STAT15 : INT ;
   STAT16 : INT ;
   STAT17 : INT ;
   STAT18 : INT ;
   STAT19 : INT ;
   STAT20 : INT ;
   STAT21 : INT ;
   STAT22 : INT ;
   STAT23 : INT ;
   STAT24 : INT ;
   STAT25 : INT ;
   STAT26 : INT ;
   STAT27 : INT ;
  END_STRUCT ;
BEGIN
   STAT0 := 0;
   STAT1 := 0;
   STAT2 := 0;
   STAT3 := 0;
   STAT4 := 0;
   STAT5 := 0;
   STAT6 := 0;
   STAT7 := 0;
   STAT8 := 0;
   STAT9 := 0;
   STAT10 := 0;
   STAT11 := 0;
   STAT12 := 0;
   STAT13 := 0;
   STAT14 := 0;
   STAT15 := 0;
   STAT16 := 0;
   STAT17 := 0;
   STAT18 := 0;
   STAT19 := 0;
   STAT20 := 0;
   STAT21 := 0;
   STAT22 := 0;
   STAT23 := 0;
   STAT24 := 0;
   STAT25 := 0;
   STAT26 := 0;
   STAT27 := 0;
END_DATA_BLOCK

DATA_BLOCK "VISUALIZZA FC"
TITLE =
VERSION : 0.1


  STRUCT
   FC_TAV_1_IND : WORD ;	//FC TAVOLA 1 INDIETRO
   FC_TAV_1_AV : WORD ;	//FC TAVOLA 1 AVANTI
   FC_TAV_1_ALTA : WORD ;	//FC TAVOLA 1 ALTA
   FC_TAV_1_BASSA : WORD ;	//FC TAVOLA 1 BASSA
   FC_TAV_1_INCLINATA_ALTA : WORD ;	//FC TAVOLA 1 INCLINATA ALTA
   FC_TAV_2_IND : WORD ;	//FC TAVOLA 2 INDIETRO
   FC_TAV_2_AV : WORD ;	//FC TAVOLA 2 AVANTI
   FC_TAV_2_ALTA : WORD ;	//FC TAVOLA 2 ALTA
   FC_TAV_2_BASSA : WORD ;	//FC TAVOLA 2 BASSA
   FC_TAV_2_INCLINATA_ALTA : WORD ;	//FC TAVOLA 2 INCLINATA ALTA
   FC_MAGNETE_1_IND : WORD ;	//FC MAGNETE 1 INDIETRO
   FC_MAGNETE_1_ARRESTO : WORD ;	//FC MAGNETE 1 ARRESTO SOLLEVAMENTO PACCO
   FC_MAGNETE_1_CONT_PACCO : WORD ;	//FC MAGNETE 1 CONTATTO PACCO
   DB_VAR26 : WORD ;	//
   DB_VAR28 : WORD ;	//
   FC_MAGNETE_2_IND : WORD ;	//FC MAGNETE 2 INDIETRO
   FC_MAGNETE_2_ARRESTO : WORD ;	//FC MAGNETE 2 ARRESTO SOLLEVAMENTO PACCO
   FC_MAGNETE_2_CONT_PACCO : WORD ;	//FC MAGNETE 2 CONTATTO PACCO
   DB_VAR36 : WORD ;	//
   DB_VAR38 : WORD ;	//
   FC_MAGNETE_3_IND : WORD ;	//FC MAGNETE 3 INDIETRO
   FC_MAGNETE_3_ARRESTO : WORD ;	//FC MAGNETE 3 ARRESTO SOLLEVAMENTO PACCO
   FC_MAGNETE_3_CONT_PACCO : WORD ;	//FC MAGNETE 3 CONTATTO PACCO
   DB_VAR46 : WORD ;	//
   DB_VAR48 : WORD ;	//
   FC_MAGNETE_4_IND : WORD ;	//FC MAGNETE 4 INDIETRO
   FC_MAGNETE_4_ARRESTO : WORD ;	//FC MAGNETE 4 ARRESTO SOLLEVAMENTO PACCO
   FC_MAGNETE_4_CONT_PACCO : WORD ;	//FC MAGNETE 4 CONTATTO PACCO
   DB_VAR56 : WORD ;
   DB_VAR58 : WORD ;
   FC_MAGNETE_5_IND : WORD ;	//FC MAGNETE 5 INDIETRO
   FC_MAGNETE_5_ARRESTO : WORD ;	//FC MAGNETE 5 ARRESTO SOLLEVAMENTO PACCO
   FC_MAGNETE_5_CONT_PACCO : WORD ;	//FC MAGNETE 5 CONTATTO PACCO
   DB_VAR66 : WORD ;	//
   DB_VAR68 : WORD ;	//
   FC_MAGNETE_6_IND : WORD ;	//FC MAGNETE 6 INDIETRO
   FC_MAGNETE_6_ARRESTO : WORD ;	//FC MAGNETE 6 ARRESTO SOLLEVAMENTO PACCO
   FC_MAGNETE_6_CONT_PACCO : WORD ;	//FC MAGNETE 6 CONTATTO PACCO
   DB_VAR76 : WORD ;	//
   DB_VAR78 : WORD ;	//
   FC_MAGNETE_LAT_SX_IND : WORD ;	//FC MAGNETE SFOGLIATORE LATERALE SX INDIETRO
   FC_MAGNETE_LAT_SX_STOP : WORD ;	//FC MAGNETE SFOGLIATORE LATERALE SX ARRESTO SOLLEVAMENTO PACCO
   FC_MAGNETE_LAT_SX_CONT : WORD ;	//FC MAGNETE SFOGLIATORE LATERALE SX CONTATTO PACCO
   FC_BRACCIO_LAT_SX_APERTO : WORD ;	//FC BRACCIO MAGNETE LATERALE SX APERTO
   FC_MAGNETE_LAT_SX_AV : WORD ;	//FC MAGNETE SFOGLIATORE LATERALE SX AVANTI
   FC_MAGNETE_LAT_DX_IND : WORD ;	//FC MAGNETE SFOGLIATORE LATERALE DX INDIETRO
   FC_MAGNETE_LAT_DX_STOP : WORD ;	//FC MAGNETE SFOGLIATORE LATERALE DX ARRESTO SOLLEVAMENTO PACCO
   FC_MAGNETE_LAT_DX_CONT : WORD ;	//FC MAGNETE SFOGLIATORE LATERALE DX CONTATTO PACCO
   FC_BRACCIO_LAT_DX_APERTO : WORD ;	//FC BRACCIO MAGNETE LATERALE DX APERTO
   FC_MAGNETE_LAT_DX_AV : WORD ;	//FC MAGNETE SFOGLIATORE LATERALE DX AVANTI
   FC_SFOGLIATORE_ALTO : WORD ;	//FC SFOGLIATORE ALTO
   FC_SFOGLIATORE_BASSO : WORD ;	//FC SFOGLIATORE BASSO
   DB_VAR104 : WORD ;	//
   DB_VAR105 : WORD ;	//
   DB_VAR106 : WORD ;	//
   FC_CENTRATORE_BLOCCATO : WORD ;	//FC CENTRATORE BLOCCATO
   FC_CENTRATORE_SBLOCCATO : WORD ;	//FC CENTRATORE SBLOCCATO
   FC_CENTRATORE_ALTO : WORD ;	//FC CENTRATORE ALTO
   FC_CENTRATORE_BASSO : WORD ;	//FC CENTRATORE  ASSO
   FC_CENTRATORE_V_PRESSA : WORD ;	//FC CENTRATORE VERSO PRESSA
   FC_CENTRATORE_V_SFOGLIAT : WORD ;	//FC CENTRATORE VERSO SFOGLIATORE
  END_STRUCT ;
BEGIN
   FC_TAV_1_IND := W#16#2;
   FC_TAV_1_AV := W#16#0;
   FC_TAV_1_ALTA := W#16#0;
   FC_TAV_1_BASSA := W#16#2;
   FC_TAV_1_INCLINATA_ALTA := W#16#1;
   FC_TAV_2_IND := W#16#0;
   FC_TAV_2_AV := W#16#0;
   FC_TAV_2_ALTA := W#16#0;
   FC_TAV_2_BASSA := W#16#0;
   FC_TAV_2_INCLINATA_ALTA := W#16#1;
   FC_MAGNETE_1_IND := W#16#0;
   FC_MAGNETE_1_ARRESTO := W#16#0;
   FC_MAGNETE_1_CONT_PACCO := W#16#1;
   DB_VAR26 := W#16#0;
   DB_VAR28 := W#16#0;
   FC_MAGNETE_2_IND := W#16#0;
   FC_MAGNETE_2_ARRESTO := W#16#0;
   FC_MAGNETE_2_CONT_PACCO := W#16#1;
   DB_VAR36 := W#16#0;
   DB_VAR38 := W#16#0;
   FC_MAGNETE_3_IND := W#16#0;
   FC_MAGNETE_3_ARRESTO := W#16#0;
   FC_MAGNETE_3_CONT_PACCO := W#16#1;
   DB_VAR46 := W#16#0;
   DB_VAR48 := W#16#0;
   FC_MAGNETE_4_IND := W#16#0;
   FC_MAGNETE_4_ARRESTO := W#16#0;
   FC_MAGNETE_4_CONT_PACCO := W#16#1;
   DB_VAR56 := W#16#0;
   DB_VAR58 := W#16#0;
   FC_MAGNETE_5_IND := W#16#0;
   FC_MAGNETE_5_ARRESTO := W#16#0;
   FC_MAGNETE_5_CONT_PACCO := W#16#1;
   DB_VAR66 := W#16#0;
   DB_VAR68 := W#16#0;
   FC_MAGNETE_6_IND := W#16#0;
   FC_MAGNETE_6_ARRESTO := W#16#0;
   FC_MAGNETE_6_CONT_PACCO := W#16#1;
   DB_VAR76 := W#16#0;
   DB_VAR78 := W#16#0;
   FC_MAGNETE_LAT_SX_IND := W#16#0;
   FC_MAGNETE_LAT_SX_STOP := W#16#0;
   FC_MAGNETE_LAT_SX_CONT := W#16#1;
   FC_BRACCIO_LAT_SX_APERTO := W#16#0;
   FC_MAGNETE_LAT_SX_AV := W#16#1;
   FC_MAGNETE_LAT_DX_IND := W#16#0;
   FC_MAGNETE_LAT_DX_STOP := W#16#0;
   FC_MAGNETE_LAT_DX_CONT := W#16#1;
   FC_BRACCIO_LAT_DX_APERTO := W#16#0;
   FC_MAGNETE_LAT_DX_AV := W#16#1;
   FC_SFOGLIATORE_ALTO := W#16#0;
   FC_SFOGLIATORE_BASSO := W#16#0;
   DB_VAR104 := W#16#0;
   DB_VAR105 := W#16#0;
   DB_VAR106 := W#16#0;
   FC_CENTRATORE_BLOCCATO := W#16#1;
   FC_CENTRATORE_SBLOCCATO := W#16#0;
   FC_CENTRATORE_ALTO := W#16#5;
   FC_CENTRATORE_BASSO := W#16#0;
   FC_CENTRATORE_V_PRESSA := W#16#1;
   FC_CENTRATORE_V_SFOGLIAT := W#16#0;
END_DATA_BLOCK

DATA_BLOCK "DATI_TAVOLA1"
AUTHOR : DAVI
VERSION : 0.1


  STRUCT
   Pos_assoluta : REAL ;	//Posizione assoluta tavola
   Pos_relativa : REAL ;	//Posizione relativa tavola
   Pos_ass_da_MP270 : REAL ;	//Posizione assoluta tavola da MP270
   Ftc_Mezzeria : REAL ;	//Valore di posizione fotocellula
   dword_16 : REAL ;	//
   dword_20 : DWORD ;	//
   dword_24 : DWORD ;	//
   dword_28 : REAL ;	//
   Aux_compensazione : REAL ;	//Dato di appoggio: Aux compensazione tavola 1
   dword_36 : REAL ;	//
   CONTA_ENCODER : REAL ;	//Valore di conteggio corrente encoder in real assoluto
   SPOSTAMENTO_ASSOLUTO : REAL ;	//Valore convertito di spostamento tavola assoluto
   SPOSTAMENTO_RELATIVO : REAL ;	//Valore convertito di spostamento tavola relativo
   dword_52 : REAL ;
   dword_56 : REAL ;	//
   Aux_Pos_assoluta_DINT : DINT ;	//Dato di appoggio: Aux Posizione assoluta tavola in DINT
   Aux_Pos_relativa_DINT : DINT ;	//Dato di appoggio: Aux Posizione relativa tavola in DINT
   dword_68 : REAL ;	//
   dword_72 : REAL ;	//
   dword_76 : REAL ;
   dword_80 : DINT ;
  END_STRUCT ;
BEGIN
   Pos_assoluta := 0.000000e+000;
   Pos_relativa := 6.350000e+002;
   Pos_ass_da_MP270 := 4.223895e-043;
   Ftc_Mezzeria := 0.000000e+000;
   dword_16 := 3.509233e-043;
   dword_20 := DW#16#0;
   dword_24 := DW#16#0;
   dword_28 := 3.088844e-043;
   Aux_compensazione := 1.530000e+003;
   dword_36 := 1.743597e-043;
   CONTA_ENCODER := 0.000000e+000;
   SPOSTAMENTO_ASSOLUTO := 0.000000e+000;
   SPOSTAMENTO_RELATIVO := 0.000000e+000;
   dword_52 := 0.000000e+000;
   dword_56 := 1.080000e+002;
   Aux_Pos_assoluta_DINT := L#0;
   Aux_Pos_relativa_DINT := L#0;
   dword_68 := 3.251137e+003;
   dword_72 := 0.000000e+000;
   dword_76 := 0.000000e+000;
   dword_80 := L#0;
END_DATA_BLOCK

DATA_BLOCK "DATI_TAVOLA2"
AUTHOR : DAVI
VERSION : 0.1


  STRUCT
   Pos_assoluta : REAL ;	//Posizione assoluta tavola
   Pos_relativa : REAL ;	//Posizione relativa tavola
   Pos_ass_da_MP270 : REAL ;	//Posizione assoluta tavola da MP270
   Ftc_Mezzeria : REAL ;	//Valore di posizione fotocellula
   Posizioneincrementata : REAL ;	//Posizione incrementata
   dword_20 : DWORD ;	//
   dword_24 : DWORD ;	//
   dword_28 : REAL ;	//
   Aux_compensazione : REAL ;	//Dato di appoggio: Aux compensazione tavola 1
   dword_36 : REAL ;	//
   CONTA_ENCODER : REAL ;	//Valore di conteggio corrente encoder in real assoluto
   SPOSTAMENTO_ASSOLUTO : REAL ;	//Valore convertito di spostamento tavola assoluto
   SPOSTAMENTO_RELATIVO : REAL ;	//Valore convertito di spostamento tavola relativo
   dword_52 : REAL ;
   dword_56 : REAL ;	//
   Aux_Pos_assoluta_DINT : DINT ;	//Dato di appoggio: Aux Posizione assoluta tavola in DINT
   Aux_Pos_relativa_DINT : DINT ;	//Dato di appoggio: Aux Posizione relativa tavola in DINT
   dword_68 : REAL ;	//
   dword_72 : REAL ;	//
   dword_76 : REAL ;
   dword_80 : DINT ;
  END_STRUCT ;
BEGIN
   Pos_assoluta := 0.000000e+000;
   Pos_relativa := 6.350000e+002;
   Pos_ass_da_MP270 := 4.223895e-043;
   Ftc_Mezzeria := 0.000000e+000;
   Posizioneincrementata := 3.509233e-043;
   dword_20 := DW#16#0;
   dword_24 := DW#16#0;
   dword_28 := 3.088844e-043;
   Aux_compensazione := 1.530000e+003;
   dword_36 := 1.743597e-043;
   CONTA_ENCODER := 6.418000e+003;
   SPOSTAMENTO_ASSOLUTO := 6.289640e+003;
   SPOSTAMENTO_RELATIVO := 0.000000e+000;
   dword_52 := 0.000000e+000;
   dword_56 := 1.080000e+002;
   Aux_Pos_assoluta_DINT := L#0;
   Aux_Pos_relativa_DINT := L#0;
   dword_68 := 3.251137e+003;
   dword_72 := 0.000000e+000;
   dword_76 := 0.000000e+000;
   dword_80 := L#0;
END_DATA_BLOCK

DATA_BLOCK "DATI_SFOGLIATORE"
AUTHOR : DAVI
VERSION : 0.1


  STRUCT
   CONTA_ENCODER : REAL ;	//Valore di conteggio corrente encoder in real
   SPOSTAMENTO : REAL ;	//Valore convertito di spostamento sfogliatore
   CECK_SALITA : REAL ;	//Valore di controllo time out per salita
   CECK_DISCESA : REAL ;	//Valore di controllo time out per discesa
   dw16 : REAL ;
  END_STRUCT ;
BEGIN
   CONTA_ENCODER := 2.303000e+003;
   SPOSTAMENTO := 5.015934e+002;
   CECK_SALITA := -8.712000e+000;
   CECK_DISCESA := 5.015934e+002;
   dw16 := 3.509233e-043;
END_DATA_BLOCK

DATA_BLOCK "DATI_ALTEZZA_CENTRAT"
AUTHOR : DAVI
VERSION : 0.1


  STRUCT
   CONTA_ENCODER : REAL ;	//Valore di conteggio corrente encoder in real
   SPOSTAMENTO : REAL ;	//Valore convertito di spostamento centratore
   CECK_SALITA : REAL ;	//Valore di controllo time out per salita
   CECK_DISCESA : REAL ;	//Valore di controllo time out per discesa
   dw16 : REAL ;	//
  END_STRUCT ;
BEGIN
   CONTA_ENCODER := 4.486000e+003;
   SPOSTAMENTO := 4.611608e+002;
   CECK_SALITA := -4.112000e-001;
   CECK_DISCESA := 4.610580e+002;
   dw16 := 3.509233e-043;
END_DATA_BLOCK

DATA_BLOCK DB 26
VERSION : 0.1


  STRUCT
   STAT0 : INT ;
  END_STRUCT ;
BEGIN
   STAT0 := 0;
END_DATA_BLOCK

DATA_BLOCK "DB_SERVIZIO"
TITLE =
VERSION : 0.1


  STRUCT
   UP_DW_1 : DWORD ;	//
   UP_DW_2 : DWORD ;	//
   UP_DW_3 : DWORD ;	//
   Tasto_aquis_dati_pos1 : BOOL ;	//Tasto acquisisci dati posizione di avvicinamento
   Tasto_aquis_dati_pos2 : BOOL ;	//Tasto acquisisci dati posizione di cambio velocita'1
   Tasto_aquis_dati_pos3 : BOOL ;	//Tasto acquisisci dati posizione di cambio velocita'2
   Tasto_aquis_dati_pos4 : BOOL ;	//Tasto acquisisci dati posizione di arrivo
   Tasto_Zero_Assi : BOOL ;	//Tasto azeramento assi contemporaneo
   Tasto_Avvicinam_Assi : BOOL ;	//Tasto avanzamento assi contemporaneo verso arrivo
   Tasto_Arrivo_Assi : BOOL ;	//Tasto avanzamento assi contemporaneo verso avvicinamento
   Tasto_Restart : BOOL ;	//Tasto restart passi ciclo centratori
   Tasto_Riposo_assi : BOOL ;	//Tasto assi a riposo
   Tasto_Ritorno_magneti : BOOL ;	//Tasto ritorno magmeti
   TASTO_SI : BOOL ;	//Visualizza tasto si
   TASTO_NO : BOOL ;	//Visualizza tasto no
   VISUAL_TASTO_TRASF_DATI : BOOL ;	//Visualizza tasto trasferisci dati
   VISUAL_TASTO_SALVA_DATI : BOOL ;	//Visualizza tasto salva dati
   matric_trasfer_uguali : BOOL ;	//Visualizza i dati trasferiti sono uguali su MP270
   matric_salvati_uguali : BOOL ;	//Visualizza i dati salvati sono uguali su MP270
   DB_MATRICOLA_DA_TRASF : INT ;	//dB matricola da trasferire
   ALLARMI_MATRICOLA : BYTE ;	//Visualizza allarmi matricola su MP270
   DB_MATRICOLA_DA_SALVARE : INT ;	//dB matricola da salvare
   ABB_ATTESA : BYTE ;	//Visualizza stato ABB posizione di attesa al carico su MP270
   ABB_PARTENZA : BYTE ;	//Visualizza stato ABB posizione di partenza su MP270
   ABB_PRELIEVO : BYTE ;	//Visualizza stato ABB posizione di prelievo su MP270
   ABB_DEPOSITO : BYTE ;	//Visualizza stato ABB posizione di deposito su MP270
   ABB_CAMBIO_PROD : BYTE ;	//Visualizza stato ABB posizione di cambio produzione su MP270
   ABB_TOOLING : BYTE ;	//Visualizza stato ABB posizione di cambio tooling su MP270
   ABB_PZ_DA_STAMPARE : BYTE ;	//Visualizza stato ABB pezzo caricato da stampare su MP270
   ABB_PZ_STAMPATO : BYTE ;	//Visualizza stato ABB pezzo stampato da caricare su MP270
   Tasto_Canc_Elemento : BOOL ;	//Cancella Elemento Caricato
   DWORD_30 : DWORD ;
   CICLO_IN_CORSO : BYTE ;	//Visualizza ciclo in corso su MP270
   INFO_SALVA : WORD ;	//INFO SALVA  DATI MATRICOLA
   WORD_38 : WORD ;
   WORD_40 : WORD ;
   DWORD_42 : DWORD ;
   Contapezzi_totale : DWORD ;	//Contapezzi_totale
   Contapezzi_preset : DWORD ;	//Contapezzi_preset
   Contapezzi_parziale : DWORD ;	//Contapezzi_parziale
   INFO_TASFERISCI : BYTE ;	//INFO TRASFERISCI DATI MATRICOLA
   Contapezzi_servizio : BYTE ;	//Contapezzi per impulso magneti indietro
   BYTE_60 : BYTE ;	//
   C1_ASSE_A_ZERO : BYTE ;	//Visualizza stato asse centratore 1 a zero
   C2_ASSE_A_ZERO : BYTE ;	//Visualizza stato asse centratore 2 a zero
   C3_ASSE_A_ZERO : BYTE ;	//Visualizza stato asse centratore 3 a zero
   C4_ASSE_A_ZERO : BYTE ;	//Visualizza stato asse centratore 4 a zero
   C5_ASSE_A_ZERO : BYTE ;	//Visualizza stato asse centratore 5 a zero
   C6_ASSE_A_ZERO : BYTE ;	//Visualizza stato asse centratore 6 a zero
   POS_AVVICINAMENTO : BYTE ;	//Posizione di avvicinnamento di tutti i centratori
   POS_ARRRIVO : BYTE ;	//Posizione di arrivo di tutti i centratori
   POS_RIPOSO : BYTE ;	//Posizione di riposo di tutti i centratori
   BYTE70 : BYTE ;
   C1_ASSE_A_RIPOSO : BYTE ;	//Visualizza stato asse centratore 1 a riposo
   C2_ASSE_A_RIPOSO : BYTE ;	//Visualizza stato asse centratore 2 a riposo
   C3_ASSE_A_RIPOSO : BYTE ;	//Visualizza stato asse centratore 3 a riposo
   C4_ASSE_A_RIPOSO : BYTE ;	//Visualizza stato asse centratore 4 a riposo
   C5_ASSE_A_RIPOSO : BYTE ;	//Visualizza stato asse centratore 5 a riposo
   C6_ASSE_A_RIPOSO : BYTE ;	//Visualizza stato asse centratore 6 a riposo
   BYTE76 : BYTE ;
   BYTE77 : BYTE ;
   BYTE78 : BYTE ;
   BYTE79 : BYTE ;
   C1_ASSE_IN_AVVICIN : BYTE ;	//Visualizza stato asse centratore 1 in avvicinamento
   C2_ASSE_IN_AVVICIN : BYTE ;	//Visualizza stato asse centratore 2 in avvicinamento
   C3_ASSE_IN_AVVICIN : BYTE ;	//Visualizza stato asse centratore 3 in avvicinamento
   C4_ASSE_IN_AVVICIN : BYTE ;	//Visualizza stato asse centratore 4 in avvicinamento
   C5_ASSE_IN_AVVICIN : BYTE ;	//Visualizza stato asse centratore 5 in avvicinamento
   C6_ASSE_IN_AVVICIN : BYTE ;	//Visualizza stato asse centratore 6 in avvicinamento
   BYTE86 : BYTE ;
   BYTE87 : BYTE ;
   BYTE88 : BYTE ;
   BYTE89 : BYTE ;
   C1_ASSE_IN_ARRIVO : BYTE ;	//Visualizza stato asse centratore 1 in arrivo
   C2_ASSE_IN_ARRIVO : BYTE ;	//Visualizza stato asse centratore 2 in arrivo
   C3_ASSE_IN_ARRIVO : BYTE ;	//Visualizza stato asse centratore 3 in arrivo
   C4_ASSE_IN_ARRIVO : BYTE ;	//Visualizza stato asse centratore 4 in arrivo
   C5_ASSE_IN_ARRIVO : BYTE ;	//Visualizza stato asse centratore 5 in arrivo
   C6_ASSE_IN_ARRIVO : BYTE ;	//Visualizza stato asse centratore 6 in arrivo
  END_STRUCT ;
BEGIN
   UP_DW_1 := DW#16#0;
   UP_DW_2 := DW#16#0;
   UP_DW_3 := DW#16#0;
   Tasto_aquis_dati_pos1 := FALSE;
   Tasto_aquis_dati_pos2 := FALSE;
   Tasto_aquis_dati_pos3 := FALSE;
   Tasto_aquis_dati_pos4 := FALSE;
   Tasto_Zero_Assi := FALSE;
   Tasto_Avvicinam_Assi := FALSE;
   Tasto_Arrivo_Assi := FALSE;
   Tasto_Restart := FALSE;
   Tasto_Riposo_assi := FALSE;
   Tasto_Ritorno_magneti := FALSE;
   TASTO_SI := FALSE;
   TASTO_NO := FALSE;
   VISUAL_TASTO_TRASF_DATI := TRUE;
   VISUAL_TASTO_SALVA_DATI := TRUE;
   matric_trasfer_uguali := TRUE;
   matric_salvati_uguali := TRUE;
   DB_MATRICOLA_DA_TRASF := 203;
   ALLARMI_MATRICOLA := B#16#0;
   DB_MATRICOLA_DA_SALVARE := 203;
   ABB_ATTESA := B#16#1;
   ABB_PARTENZA := B#16#0;
   ABB_PRELIEVO := B#16#0;
   ABB_DEPOSITO := B#16#2;
   ABB_CAMBIO_PROD := B#16#0;
   ABB_TOOLING := B#16#0;
   ABB_PZ_DA_STAMPARE := B#16#0;
   ABB_PZ_STAMPATO := B#16#1;
   Tasto_Canc_Elemento := FALSE;
   DWORD_30 := DW#16#0;
   CICLO_IN_CORSO := B#16#1;
   INFO_SALVA := W#16#1;
   WORD_38 := W#16#0;
   WORD_40 := W#16#0;
   DWORD_42 := DW#16#D0000;
   Contapezzi_totale := DW#16#19D;
   Contapezzi_preset := DW#16#0;
   Contapezzi_parziale := DW#16#78;
   INFO_TASFERISCI := B#16#2;
   Contapezzi_servizio := B#16#0;
   BYTE_60 := B#16#0;
   C1_ASSE_A_ZERO := B#16#1;
   C2_ASSE_A_ZERO := B#16#1;
   C3_ASSE_A_ZERO := B#16#1;
   C4_ASSE_A_ZERO := B#16#1;
   C5_ASSE_A_ZERO := B#16#1;
   C6_ASSE_A_ZERO := B#16#1;
   POS_AVVICINAMENTO := B#16#1;
   POS_ARRRIVO := B#16#0;
   POS_RIPOSO := B#16#0;
   BYTE70 := B#16#0;
   C1_ASSE_A_RIPOSO := B#16#0;
   C2_ASSE_A_RIPOSO := B#16#0;
   C3_ASSE_A_RIPOSO := B#16#0;
   C4_ASSE_A_RIPOSO := B#16#0;
   C5_ASSE_A_RIPOSO := B#16#0;
   C6_ASSE_A_RIPOSO := B#16#0;
   BYTE76 := B#16#0;
   BYTE77 := B#16#0;
   BYTE78 := B#16#0;
   BYTE79 := B#16#0;
   C1_ASSE_IN_AVVICIN := B#16#1;
   C2_ASSE_IN_AVVICIN := B#16#1;
   C3_ASSE_IN_AVVICIN := B#16#1;
   C4_ASSE_IN_AVVICIN := B#16#1;
   C5_ASSE_IN_AVVICIN := B#16#1;
   C6_ASSE_IN_AVVICIN := B#16#1;
   BYTE86 := B#16#0;
   BYTE87 := B#16#0;
   BYTE88 := B#16#0;
   BYTE89 := B#16#0;
   C1_ASSE_IN_ARRIVO := B#16#0;
   C2_ASSE_IN_ARRIVO := B#16#0;
   C3_ASSE_IN_ARRIVO := B#16#0;
   C4_ASSE_IN_ARRIVO := B#16#0;
   C5_ASSE_IN_ARRIVO := B#16#0;
   C6_ASSE_IN_ARRIVO := B#16#0;
END_DATA_BLOCK

DATA_BLOCK "C1 SCRITTURA DATI"
TITLE =
VERSION : 0.1


  STRUCT
   Telegrammkennung : BYTE ;
   frei : BYTE ;	//vorläufige Platzhaltervariable
   PROFIDRIVE_Controlword : WORD ;
   Posizione_da_raggiungere : DINT ;	//zu übertragender Parameter in default-Parametrierung
   Velocita_da_attuare : DINT ;	//zu übertragender Parameter in default-Parametrierung
   Accelerazione_da_attuare : DINT ;	//zu übertragender Parameter in default-Parametrierung
   Velocita_Jog : DINT ;	//Velocita' di jog
   access : BYTE  := B#16#1;	//lettura = 1   scrittura = 2   nulla =0
   parameternumber_highbyte : BYTE  := B#16#24;	//byte alto numero di parametro can
   parameternumber_lowbyte : BYTE  := B#16#15;	//byte basso numero di parametro can
   subindex : BYTE  := B#16#2;	//sotto indice del parametro
   data_current_limit : DINT ;	//dato di corrente limite in milliampere
   dummy : DINT ;
  END_STRUCT ;
BEGIN
   Telegrammkennung := B#16#E0;
   frei := B#16#0;
   PROFIDRIVE_Controlword := W#16#43F;
   Posizione_da_raggiungere := L#163000;
   Velocita_da_attuare := L#500;
   Accelerazione_da_attuare := L#500;
   Velocita_Jog := L#50;
   access := B#16#42;
   parameternumber_highbyte := B#16#24;
   parameternumber_lowbyte := B#16#15;
   subindex := B#16#2;
   data_current_limit := L#5000;
   dummy := L#0;
END_DATA_BLOCK

DATA_BLOCK "C2 SCRITTURA DATI"
TITLE =
VERSION : 0.1


  STRUCT
   Telegrammkennung : BYTE ;
   frei : BYTE ;	//vorläufige Platzhaltervariable
   PROFIDRIVE_Controlword : WORD ;
   Posizione_da_raggiungere : DINT ;	//zu übertragender Parameter in default-Parametrierung
   Velocita_da_attuare : DINT ;	//zu übertragender Parameter in default-Parametrierung
   Accelerazione_da_attuare : DINT ;	//zu übertragender Parameter in default-Parametrierung
   Velocita_Jog : DINT ;	//Velocita' di jog
   access : BYTE  := B#16#1;	//lettura = 1   scrittura = 2   nulla =0
   parameternumber_highbyte : BYTE  := B#16#24;	//byte alto numero di parametro can
   parameternumber_lowbyte : BYTE  := B#16#15;	//byte basso numero di parametro can
   subindex : BYTE  := B#16#2;	//sotto indice del parametro
   data_current_limit : DINT ;	//dato di corrente limite in milliampere
   dummy : DINT ;
  END_STRUCT ;
BEGIN
   Telegrammkennung := B#16#E0;
   frei := B#16#0;
   PROFIDRIVE_Controlword := W#16#43F;
   Posizione_da_raggiungere := L#326000;
   Velocita_da_attuare := L#500;
   Accelerazione_da_attuare := L#500;
   Velocita_Jog := L#50;
   access := B#16#42;
   parameternumber_highbyte := B#16#24;
   parameternumber_lowbyte := B#16#15;
   subindex := B#16#2;
   data_current_limit := L#5000;
   dummy := L#0;
END_DATA_BLOCK

DATA_BLOCK "C3 SCRITTURA DATI"
TITLE =
VERSION : 0.1


  STRUCT
   Telegrammkennung : BYTE ;
   frei : BYTE ;	//vorläufige Platzhaltervariable
   PROFIDRIVE_Controlword : WORD ;
   Posizione_da_raggiungere : DINT ;	//zu übertragender Parameter in default-Parametrierung
   Velocita_da_attuare : DINT ;	//zu übertragender Parameter in default-Parametrierung
   Accelerazione_da_attuare : DINT ;	//zu übertragender Parameter in default-Parametrierung
   Velocita_Jog : DINT ;	//Velocita' di jog
   access : BYTE  := B#16#1;	//lettura = 1   scrittura = 2   nulla =0
   parameternumber_highbyte : BYTE  := B#16#24;	//byte alto numero di parametro can
   parameternumber_lowbyte : BYTE  := B#16#15;	//byte basso numero di parametro can
   subindex : BYTE  := B#16#2;	//sotto indice del parametro
   data_current_limit : DINT ;	//dato di corrente limite in milliampere
   dummy : DINT ;
  END_STRUCT ;
BEGIN
   Telegrammkennung := B#16#E0;
   frei := B#16#0;
   PROFIDRIVE_Controlword := W#16#43F;
   Posizione_da_raggiungere := L#256000;
   Velocita_da_attuare := L#500;
   Accelerazione_da_attuare := L#500;
   Velocita_Jog := L#50;
   access := B#16#42;
   parameternumber_highbyte := B#16#24;
   parameternumber_lowbyte := B#16#15;
   subindex := B#16#2;
   data_current_limit := L#5000;
   dummy := L#0;
END_DATA_BLOCK

DATA_BLOCK "C4 SCRITTURA DATI"
TITLE =
VERSION : 0.1


  STRUCT
   Telegrammkennung : BYTE ;
   frei : BYTE ;	//vorläufige Platzhaltervariable
   PROFIDRIVE_Controlword : WORD ;
   Posizione_da_raggiungere : DINT ;	//zu übertragender Parameter in default-Parametrierung
   Velocita_da_attuare : DINT ;	//zu übertragender Parameter in default-Parametrierung
   Accelerazione_da_attuare : DINT ;	//zu übertragender Parameter in default-Parametrierung
   Velocita_Jog : DINT ;	//Velocita' di jog
   access : BYTE  := B#16#1;	//lettura = 1   scrittura = 2   nulla =0
   parameternumber_highbyte : BYTE  := B#16#24;	//byte alto numero di parametro can
   parameternumber_lowbyte : BYTE  := B#16#15;	//byte basso numero di parametro can
   subindex : BYTE  := B#16#2;	//sotto indice del parametro
   data_current_limit : DINT ;	//dato di corrente limite in milliampere
   dummy : DINT ;
  END_STRUCT ;
BEGIN
   Telegrammkennung := B#16#E0;
   frei := B#16#0;
   PROFIDRIVE_Controlword := W#16#43F;
   Posizione_da_raggiungere := L#154000;
   Velocita_da_attuare := L#500;
   Accelerazione_da_attuare := L#500;
   Velocita_Jog := L#50;
   access := B#16#42;
   parameternumber_highbyte := B#16#24;
   parameternumber_lowbyte := B#16#15;
   subindex := B#16#2;
   data_current_limit := L#5000;
   dummy := L#0;
END_DATA_BLOCK

DATA_BLOCK "C5 SCRITTURA DATI"
TITLE =
VERSION : 0.1


  STRUCT
   Telegrammkennung : BYTE ;
   frei : BYTE ;	//vorläufige Platzhaltervariable
   PROFIDRIVE_Controlword : WORD ;
   Posizione_da_raggiungere : DINT ;	//zu übertragender Parameter in default-Parametrierung
   Velocita_da_attuare : DINT ;	//zu übertragender Parameter in default-Parametrierung
   Accelerazione_da_attuare : DINT ;	//zu übertragender Parameter in default-Parametrierung
   Velocita_Jog : DINT ;	//Velocita' di jog
   access : BYTE  := B#16#1;	//lettura = 1   scrittura = 2   nulla =0
   parameternumber_highbyte : BYTE  := B#16#24;	//byte alto numero di parametro can
   parameternumber_lowbyte : BYTE  := B#16#15;	//byte basso numero di parametro can
   subindex : BYTE  := B#16#2;	//sotto indice del parametro
   data_current_limit : DINT ;	//dato di corrente limite in milliampere
   dummy : DINT ;
  END_STRUCT ;
BEGIN
   Telegrammkennung := B#16#E0;
   frei := B#16#0;
   PROFIDRIVE_Controlword := W#16#43F;
   Posizione_da_raggiungere := L#395000;
   Velocita_da_attuare := L#500;
   Accelerazione_da_attuare := L#500;
   Velocita_Jog := L#50;
   access := B#16#42;
   parameternumber_highbyte := B#16#24;
   parameternumber_lowbyte := B#16#15;
   subindex := B#16#2;
   data_current_limit := L#5000;
   dummy := L#0;
END_DATA_BLOCK

DATA_BLOCK "C6 SCRITTURA DATI"
TITLE =
VERSION : 0.1


  STRUCT
   Telegrammkennung : BYTE ;
   frei : BYTE ;	//vorläufige Platzhaltervariable
   PROFIDRIVE_Controlword : WORD ;
   Posizione_da_raggiungere : DINT ;	//zu übertragender Parameter in default-Parametrierung
   Velocita_da_attuare : DINT ;	//zu übertragender Parameter in default-Parametrierung
   Accelerazione_da_attuare : DINT ;	//zu übertragender Parameter in default-Parametrierung
   Velocita_Jog : DINT ;	//Velocita' di jog
   access : BYTE  := B#16#1;	//lettura = 1   scrittura = 2   nulla =0
   parameternumber_highbyte : BYTE  := B#16#24;	//byte alto numero di parametro can
   parameternumber_lowbyte : BYTE  := B#16#15;	//byte basso numero di parametro can
   subindex : BYTE  := B#16#2;	//sotto indice del parametro
   data_current_limit : DINT ;	//dato di corrente limite in milliampere
   dummy : DINT ;
  END_STRUCT ;
BEGIN
   Telegrammkennung := B#16#E0;
   frei := B#16#0;
   PROFIDRIVE_Controlword := W#16#43F;
   Posizione_da_raggiungere := L#430000;
   Velocita_da_attuare := L#500;
   Accelerazione_da_attuare := L#500;
   Velocita_Jog := L#50;
   access := B#16#42;
   parameternumber_highbyte := B#16#24;
   parameternumber_lowbyte := B#16#15;
   subindex := B#16#2;
   data_current_limit := L#5000;
   dummy := L#0;
END_DATA_BLOCK

DATA_BLOCK "C1 LETTURA DATI"
TITLE =
VERSION : 0.1


  STRUCT
   Telegrammkennung : BYTE ;
   Betriebsart : BYTE ;	//herstellerspezifisch
   PROFIDRIVE_Statusword : WORD ;
   Posizione_attuale : DINT ;	//übertragener Parameter in default-Parametrierung
   Velocita_attuale : DINT ;	//übertragener Parameter in default-Parametrierung
   Accellerazione_attuale : DINT ;	//übertragener Parameter in default-Parametrierung
   digitale_Eingaenge : DINT ;	//übertragener Parameter in default-Parametrierung
   access : BYTE ;
   parameter_number_highbyt : BYTE ;
   parameter_number_lowbyte : BYTE ;
   subindex : BYTE ;
   data_current_limit1 : DINT ;
   current_actual_value : DINT ;	//valora di corrente attuale
  END_STRUCT ;
BEGIN
   Telegrammkennung := B#16#F0;
   Betriebsart := B#16#10;
   PROFIDRIVE_Statusword := W#16#2B07;
   Posizione_attuale := L#163003;
   Velocita_attuale := L#0;
   Accellerazione_attuale := L#-1;
   digitale_Eingaenge := L#480;
   access := B#16#42;
   parameter_number_highbyt := B#16#24;
   parameter_number_lowbyte := B#16#15;
   subindex := B#16#2;
   data_current_limit1 := L#0;
   current_actual_value := L#-1;
END_DATA_BLOCK

DATA_BLOCK "C2 LETTURA DATI"
TITLE =
VERSION : 0.1


  STRUCT
   Telegrammkennung : BYTE ;
   Betriebsart : BYTE ;	//herstellerspezifisch
   PROFIDRIVE_Statusword : WORD ;
   Posizione_attuale : DINT ;	//übertragener Parameter in default-Parametrierung
   Velocita_attuale : DINT ;	//übertragener Parameter in default-Parametrierung
   Accellerazione_attuale : DINT ;	//übertragener Parameter in default-Parametrierung
   digitale_Eingaenge : DINT ;	//übertragener Parameter in default-Parametrierung
   access : BYTE ;
   parameter_number_highbyt : BYTE ;
   parameter_number_lowbyte : BYTE ;
   subindex : BYTE ;
   data_current_limit1 : DINT ;
   current_actual_value : DINT ;	//valora di corrente attuale
  END_STRUCT ;
BEGIN
   Telegrammkennung := B#16#F0;
   Betriebsart := B#16#10;
   PROFIDRIVE_Statusword := W#16#2B07;
   Posizione_attuale := L#326008;
   Velocita_attuale := L#0;
   Accellerazione_attuale := L#-5;
   digitale_Eingaenge := L#482;
   access := B#16#42;
   parameter_number_highbyt := B#16#24;
   parameter_number_lowbyte := B#16#15;
   subindex := B#16#2;
   data_current_limit1 := L#0;
   current_actual_value := L#-5;
END_DATA_BLOCK

DATA_BLOCK "C3 LETTURA DATI"
TITLE =
VERSION : 0.1


  STRUCT
   Telegrammkennung : BYTE ;
   Betriebsart : BYTE ;	//herstellerspezifisch
   PROFIDRIVE_Statusword : WORD ;
   Posizione_attuale : DINT ;	//übertragener Parameter in default-Parametrierung
   Velocita_attuale : DINT ;	//übertragener Parameter in default-Parametrierung
   Accellerazione_attuale : DINT ;	//übertragener Parameter in default-Parametrierung
   digitale_Eingaenge : DINT ;	//übertragener Parameter in default-Parametrierung
   access : BYTE ;
   parameter_number_highbyt : BYTE ;
   parameter_number_lowbyte : BYTE ;
   subindex : BYTE ;
   data_current_limit1 : DINT ;
   current_actual_value : DINT ;	//valora di corrente attuale
  END_STRUCT ;
BEGIN
   Telegrammkennung := B#16#F0;
   Betriebsart := B#16#10;
   PROFIDRIVE_Statusword := W#16#2B07;
   Posizione_attuale := L#256006;
   Velocita_attuale := L#0;
   Accellerazione_attuale := L#2;
   digitale_Eingaenge := L#484;
   access := B#16#42;
   parameter_number_highbyt := B#16#24;
   parameter_number_lowbyte := B#16#15;
   subindex := B#16#2;
   data_current_limit1 := L#0;
   current_actual_value := L#2;
END_DATA_BLOCK

DATA_BLOCK "C4 LETTURA DATI"
TITLE =
VERSION : 0.1


  STRUCT
   Telegrammkennung : BYTE ;
   Betriebsart : BYTE ;	//herstellerspezifisch
   PROFIDRIVE_Statusword : WORD ;
   Posizione_attuale : DINT ;	//übertragener Parameter in default-Parametrierung
   Velocita_attuale : DINT ;	//übertragener Parameter in default-Parametrierung
   Accellerazione_attuale : DINT ;	//übertragener Parameter in default-Parametrierung
   digitale_Eingaenge : DINT ;	//übertragener Parameter in default-Parametrierung
   access : BYTE ;
   parameter_number_highbyt : BYTE ;
   parameter_number_lowbyte : BYTE ;
   subindex : BYTE ;
   data_current_limit1 : DINT ;
   current_actual_value : DINT ;	//valora di corrente attuale
  END_STRUCT ;
BEGIN
   Telegrammkennung := B#16#F0;
   Betriebsart := B#16#10;
   PROFIDRIVE_Statusword := W#16#2B07;
   Posizione_attuale := L#154012;
   Velocita_attuale := L#0;
   Accellerazione_attuale := L#-1;
   digitale_Eingaenge := L#486;
   access := B#16#42;
   parameter_number_highbyt := B#16#24;
   parameter_number_lowbyte := B#16#15;
   subindex := B#16#2;
   data_current_limit1 := L#0;
   current_actual_value := L#-1;
END_DATA_BLOCK

DATA_BLOCK "C5 LETTURA DATI"
TITLE =
VERSION : 0.1


  STRUCT
   Telegrammkennung : BYTE ;
   Betriebsart : BYTE ;	//herstellerspezifisch
   PROFIDRIVE_Statusword : WORD ;
   Posizione_attuale : DINT ;	//übertragener Parameter in default-Parametrierung
   Velocita_attuale : DINT ;	//übertragener Parameter in default-Parametrierung
   Accellerazione_attuale : DINT ;	//übertragener Parameter in default-Parametrierung
   digitale_Eingaenge : DINT ;	//übertragener Parameter in default-Parametrierung
   access : BYTE ;
   parameter_number_highbyt : BYTE ;
   parameter_number_lowbyte : BYTE ;
   subindex : BYTE ;
   data_current_limit1 : DINT ;
   current_actual_value : DINT ;	//valora di corrente attuale
  END_STRUCT ;
BEGIN
   Telegrammkennung := B#16#F0;
   Betriebsart := B#16#10;
   PROFIDRIVE_Statusword := W#16#2B07;
   Posizione_attuale := L#395002;
   Velocita_attuale := L#0;
   Accellerazione_attuale := L#-2;
   digitale_Eingaenge := L#488;
   access := B#16#42;
   parameter_number_highbyt := B#16#24;
   parameter_number_lowbyte := B#16#15;
   subindex := B#16#2;
   data_current_limit1 := L#0;
   current_actual_value := L#-2;
END_DATA_BLOCK

DATA_BLOCK "C6 LETTURA DATI"
TITLE =
VERSION : 0.1


  STRUCT
   Telegrammkennung : BYTE ;
   Betriebsart : BYTE ;	//herstellerspezifisch
   PROFIDRIVE_Statusword : WORD ;
   Posizione_attuale : DINT ;	//übertragener Parameter in default-Parametrierung
   Velocita_attuale : DINT ;	//übertragener Parameter in default-Parametrierung
   Accellerazione_attuale : DINT ;	//übertragener Parameter in default-Parametrierung
   digitale_Eingaenge : DINT ;	//übertragener Parameter in default-Parametrierung
   access : BYTE ;
   parameter_number_highbyt : BYTE ;
   parameter_number_lowbyte : BYTE ;
   subindex : BYTE ;
   data_current_limit1 : DINT ;
   current_actual_value : DINT ;	//valora di corrente attuale
  END_STRUCT ;
BEGIN
   Telegrammkennung := B#16#F0;
   Betriebsart := B#16#10;
   PROFIDRIVE_Statusword := W#16#2B07;
   Posizione_attuale := L#430000;
   Velocita_attuale := L#0;
   Accellerazione_attuale := L#2;
   digitale_Eingaenge := L#490;
   access := B#16#42;
   parameter_number_highbyt := B#16#24;
   parameter_number_lowbyte := B#16#15;
   subindex := B#16#2;
   data_current_limit1 := L#0;
   current_actual_value := L#2;
END_DATA_BLOCK

DATA_BLOCK "CONFRONTI CENTRATORI"
TITLE =
VERSION : 0.1


  STRUCT
   C1_Attuale : DINT ;	//
   C1_Pos_1_Max : DINT ;	//
   C1_Pos_1_Min : DINT ;	//
   C1_Pos_2_Max : DINT ;	//
   C1_Pos_2_Min : DINT ;	//
   C1_Pos_3_Max : DINT ;
   C1_Pos_3_Min : DINT ;	//
   C1_Pos_4_Max : DINT ;	//
   C1_Pos_4_Min : DINT ;	//
   C2_Attuale : DINT ;	//
   C2_Pos_1_Max : DINT ;	//
   C2_Pos_1_Min : DINT ;	//
   C2_Pos_2_Max : DINT ;	//
   C2_Pos_2_Min : DINT ;	//
   C2_Pos_3_Max : DINT ;
   C2_Pos_3_Min : DINT ;	//
   C2_Pos_4_Max : DINT ;	//
   C2_Pos_4_Min : DINT ;	//
   C3_Attuale : DINT ;
   C3_Pos_1_Max : DINT ;	//
   C3_Pos_1_Min : DINT ;	//
   C3_Pos_2_Max : DINT ;	//
   C3_Pos_2_Min : DINT ;	//
   C3_Pos_3_Max : DINT ;
   C3_Pos_3_Min : DINT ;	//
   C3_Pos_4_Max : DINT ;	//
   C3_Pos_4_Min : DINT ;	//
   C4_Attuale1 : DINT ;	//
   C4_Pos_1_Max : DINT ;	//
   C4_Pos_1_Min : DINT ;	//
   C4_Pos_2_Max : DINT ;	//
   C4_Pos_2_Min : DINT ;	//
   C4_Pos_3_Max : DINT ;
   C4_Pos_3_Min : DINT ;	//
   C4_Pos_4_Max : DINT ;	//
   C4_Pos_4_Min : DINT ;	//
   C5_Attuale : DINT ;	//
   C5_Pos_1_Max : DINT ;	//
   C5_Pos_1_Min : DINT ;	//
   C5_Pos_2_Max : DINT ;	//
   C5_Pos_2_Min : DINT ;	//
   C5_Pos_3_Max : DINT ;
   C5_Pos_3_Min : DINT ;	//
   C5_Pos_4_Max : DINT ;	//
   C5_Pos_4_Min : DINT ;	//
   C6_Attuale : DINT ;
   C6_Pos_1_Max : DINT ;	//
   C6_Pos_1_Min : DINT ;	//
   C6_Pos_2_Max : DINT ;	//
   C6_Pos_2_Min : DINT ;	//
   C6_Pos_3_Max : DINT ;
   C6_Pos_3_Min : DINT ;	//
   C6_Pos_4_Max : DINT ;	//
   C6_Pos_4_Min : DINT ;	//
  END_STRUCT ;
BEGIN
   C1_Attuale := L#0;
   C1_Pos_1_Max := L#163200;
   C1_Pos_1_Min := L#162900;
   C1_Pos_2_Max := L#233000;
   C1_Pos_2_Min := L#182900;
   C1_Pos_3_Max := L#243000;
   C1_Pos_3_Min := L#192900;
   C1_Pos_4_Max := L#235100;
   C1_Pos_4_Min := L#234900;
   C2_Attuale := L#0;
   C2_Pos_1_Max := L#326200;
   C2_Pos_1_Min := L#325900;
   C2_Pos_2_Max := L#396000;
   C2_Pos_2_Min := L#345900;
   C2_Pos_3_Max := L#406000;
   C2_Pos_3_Min := L#355900;
   C2_Pos_4_Max := L#401100;
   C2_Pos_4_Min := L#400900;
   C3_Attuale := L#0;
   C3_Pos_1_Max := L#256200;
   C3_Pos_1_Min := L#255900;
   C3_Pos_2_Max := L#326000;
   C3_Pos_2_Min := L#275900;
   C3_Pos_3_Max := L#336000;
   C3_Pos_3_Min := L#285900;
   C3_Pos_4_Max := L#385100;
   C3_Pos_4_Min := L#384900;
   C4_Attuale1 := L#0;
   C4_Pos_1_Max := L#154200;
   C4_Pos_1_Min := L#153900;
   C4_Pos_2_Max := L#224000;
   C4_Pos_2_Min := L#173900;
   C4_Pos_3_Max := L#234000;
   C4_Pos_3_Min := L#183900;
   C4_Pos_4_Max := L#283100;
   C4_Pos_4_Min := L#282900;
   C5_Attuale := L#0;
   C5_Pos_1_Max := L#395200;
   C5_Pos_1_Min := L#394900;
   C5_Pos_2_Max := L#465000;
   C5_Pos_2_Min := L#414900;
   C5_Pos_3_Max := L#475000;
   C5_Pos_3_Min := L#424900;
   C5_Pos_4_Max := L#510100;
   C5_Pos_4_Min := L#509900;
   C6_Attuale := L#0;
   C6_Pos_1_Max := L#430200;
   C6_Pos_1_Min := L#429900;
   C6_Pos_2_Max := L#500000;
   C6_Pos_2_Min := L#449900;
   C6_Pos_3_Max := L#510000;
   C6_Pos_3_Min := L#459900;
   C6_Pos_4_Max := L#525100;
   C6_Pos_4_Min := L#524900;
END_DATA_BLOCK

DATA_BLOCK "C1--MP270"
TITLE =
VERSION : 0.1


  STRUCT
   Bar_Graf : DINT ;	//Visualizza grafica quota attuale
   limite_Bar_Graf : WORD ;	//Variabile limite bar_graf
   Imposta_posizione : DINT ;	//Imposta_posizione
   Imposta_velocita : DINT ;	//Imposta_velocita
   Imposta_accelerazione : DINT ;	//Imposta_accelerazione
   word_18 : WORD ;	//
   FC_in_quota_zero : WORD ;	//Visualizza Fc in quota di zero
   FC_in_quota_avvicin : WORD ;	//Visualizza Fc in quota di avvicinamento
   FC_in_quota_arrivo : WORD ;	//Visualizza Fc in quota di arrivo
   word_26 : WORD ;	//
   word_28 : WORD ;	//
   Tasto_Jog_Piu : BOOL ;	//Tasto Jog +
   Tasto_Jog_Meno : BOOL ;	//Tasto Jog -
   Tasto_Avanti : BOOL ;	//Tasto Avanti
   Tasto_Indietro : BOOL ;	//Tasto Indietro
   Tasto_Riposo : BOOL ;	//Tasto Riposo
   Tasto_Homing : BOOL ;	//Tasto Homing (zero asse)
   bit_30_6 : BOOL ;
   bit_30_7 : BOOL ;
   flag_1 : BOOL ;	//One shot
   flag_2 : BOOL ;
   flag_3 : BOOL ;
   flag_4 : BOOL ;
   flag_5 : BOOL ;
   flag_6 : BOOL ;
   flag_7 : BOOL ;
   flag_8 : BOOL ;
   BYTE_32 : BYTE ;	//
   WORD_34 : WORD ;
   WORD_36 : WORD ;
   word_38 : WORD ;	//
   Posizione_attuale : DINT ;	//Posizione attuale
   Posizione_1_impostata : DINT ;	//Posizione 1 di avicinamento
   Posizione_2_impostata : DINT ;	//Posizione 2 di cambio velocita'
   Posizione_3_impostata : DINT ;	//Posizione 3 di cambio velocita'
   Posizione_4_impostata : DINT ;	//Posizione 4 di arrivo
   Velocita_1_impostata : DINT ;	//Velocita' 1 di avvicinamento
   Velocita_2_impostata : DINT ;	//Velocita' 2
   Velocita_3_impostata : DINT ;	//Velocita' 3
   Velocita_4_impostata : DINT ;	//Velocita' 4 di arrivo
   Accell_1_impostata : DINT ;	//Accelerazione 1 di avvicinamento
   Accell_2_impostata : DINT ;	//Accelerazione 2
   Accell_3_impostata : DINT ;	//Accelerazione 3
   Accell_4_impostata : DINT ;	//Accelerazione 4 di arrivo
  END_STRUCT ;
BEGIN
   Bar_Graf := L#163003;
   limite_Bar_Graf := W#16#0;
   Imposta_posizione := L#0;
   Imposta_velocita := L#0;
   Imposta_accelerazione := L#0;
   word_18 := W#16#0;
   FC_in_quota_zero := W#16#0;
   FC_in_quota_avvicin := W#16#1;
   FC_in_quota_arrivo := W#16#0;
   word_26 := W#16#0;
   word_28 := W#16#0;
   Tasto_Jog_Piu := FALSE;
   Tasto_Jog_Meno := FALSE;
   Tasto_Avanti := FALSE;
   Tasto_Indietro := FALSE;
   Tasto_Riposo := FALSE;
   Tasto_Homing := TRUE;
   bit_30_6 := FALSE;
   bit_30_7 := FALSE;
   flag_1 := TRUE;
   flag_2 := FALSE;
   flag_3 := FALSE;
   flag_4 := FALSE;
   flag_5 := FALSE;
   flag_6 := FALSE;
   flag_7 := FALSE;
   flag_8 := FALSE;
   BYTE_32 := B#16#0;
   WORD_34 := W#16#0;
   WORD_36 := W#16#0;
   word_38 := W#16#0;
   Posizione_attuale := L#163003;
   Posizione_1_impostata := L#0;
   Posizione_2_impostata := L#0;
   Posizione_3_impostata := L#0;
   Posizione_4_impostata := L#235000;
   Velocita_1_impostata := L#0;
   Velocita_2_impostata := L#0;
   Velocita_3_impostata := L#0;
   Velocita_4_impostata := L#0;
   Accell_1_impostata := L#0;
   Accell_2_impostata := L#0;
   Accell_3_impostata := L#0;
   Accell_4_impostata := L#0;
END_DATA_BLOCK

DATA_BLOCK "C2--MP270"
TITLE =
VERSION : 0.1


  STRUCT
   Bar_Graf : DINT ;	//Visualizza grafica quota attuale
   limite_Bar_Graf : WORD ;	//Variabile limite bar_graf
   Imposta_posizione : DINT ;	//Imposta_posizione
   Imposta_velocita : DINT ;	//Imposta_velocita
   Imposta_accelerazione : DINT ;	//Imposta_accelerazione
   word_18 : WORD ;	//
   FC_in_quota_zero : WORD ;	//Visualizza Fc in quota di zero
   FC_in_quota_avvicin : WORD ;	//Visualizza Fc in quota di avvicinamento
   FC_in_quota_arrivo : WORD ;	//Visualizza Fc in quota di arrivo
   word_26 : WORD ;	//
   word_28 : WORD ;	//
   Tasto_Jog_Piu : BOOL ;	//Tasto Jog +
   Tasto_Jog_Meno : BOOL ;	//Tasto Jog -
   Tasto_Avanti : BOOL ;	//Tasto Avanti
   Tasto_Indietro : BOOL ;	//Tasto Indietro
   Tasto_Riposo : BOOL ;	//Tasto Riposo
   Tasto_Homing : BOOL ;	//Tasto Homing (zero asse)
   bit_30_6 : BOOL ;
   bit_30_7 : BOOL ;
   flag_1 : BOOL ;	//One shot
   flag_2 : BOOL ;
   flag_3 : BOOL ;
   flag_4 : BOOL ;
   flag_5 : BOOL ;
   flag_6 : BOOL ;
   flag_7 : BOOL ;
   flag_8 : BOOL ;
   BYTE_32 : BYTE ;	//
   WORD_34 : WORD ;
   WORD_36 : WORD ;
   word_38 : WORD ;	//
   Posizione_attuale : DINT ;	//Posizione attuale
   Posizione_1_impostata : DINT ;	//Posizione 1 di avicinamento
   Posizione_2_impostata : DINT ;	//Posizione 2 di cambio velocita'
   Posizione_3_impostata : DINT ;	//Posizione 3 di cambio velocita'
   Posizione_4_impostata : DINT ;	//Posizione 4 di arrivo
   Velocita_1_impostata : DINT ;	//Velocita' 1 di avvicinamento
   Velocita_2_impostata : DINT ;	//Velocita' 2
   Velocita_3_impostata : DINT ;	//Velocita' 3
   Velocita_4_impostata : DINT ;	//Velocita' 4 di arrivo
   Accell_1_impostata : DINT ;	//Accelerazione 1 di avvicinamento
   Accell_2_impostata : DINT ;	//Accelerazione 2
   Accell_3_impostata : DINT ;	//Accelerazione 3
   Accell_4_impostata : DINT ;	//Accelerazione 4 di arrivo
  END_STRUCT ;
BEGIN
   Bar_Graf := L#326008;
   limite_Bar_Graf := W#16#0;
   Imposta_posizione := L#0;
   Imposta_velocita := L#0;
   Imposta_accelerazione := L#0;
   word_18 := W#16#0;
   FC_in_quota_zero := W#16#0;
   FC_in_quota_avvicin := W#16#1;
   FC_in_quota_arrivo := W#16#0;
   word_26 := W#16#0;
   word_28 := W#16#0;
   Tasto_Jog_Piu := FALSE;
   Tasto_Jog_Meno := FALSE;
   Tasto_Avanti := FALSE;
   Tasto_Indietro := FALSE;
   Tasto_Riposo := FALSE;
   Tasto_Homing := TRUE;
   bit_30_6 := FALSE;
   bit_30_7 := FALSE;
   flag_1 := TRUE;
   flag_2 := FALSE;
   flag_3 := FALSE;
   flag_4 := FALSE;
   flag_5 := FALSE;
   flag_6 := FALSE;
   flag_7 := FALSE;
   flag_8 := FALSE;
   BYTE_32 := B#16#0;
   WORD_34 := W#16#0;
   WORD_36 := W#16#0;
   word_38 := W#16#0;
   Posizione_attuale := L#326008;
   Posizione_1_impostata := L#0;
   Posizione_2_impostata := L#0;
   Posizione_3_impostata := L#0;
   Posizione_4_impostata := L#401000;
   Velocita_1_impostata := L#0;
   Velocita_2_impostata := L#0;
   Velocita_3_impostata := L#0;
   Velocita_4_impostata := L#0;
   Accell_1_impostata := L#0;
   Accell_2_impostata := L#0;
   Accell_3_impostata := L#0;
   Accell_4_impostata := L#0;
END_DATA_BLOCK

DATA_BLOCK "C3--MP270"
TITLE =
VERSION : 0.1


  STRUCT
   Bar_Graf : DINT ;	//Visualizza grafica quota attuale
   limite_Bar_Graf : WORD ;	//Variabile limite bar_graf
   Imposta_posizione : DINT ;	//Imposta_posizione
   Imposta_velocita : DINT ;	//Imposta_velocita
   Imposta_accelerazione : DINT ;	//Imposta_accelerazione
   word_18 : WORD ;	//
   FC_in_quota_zero : WORD ;	//Visualizza Fc in quota di zero
   FC_in_quota_avvicin : WORD ;	//Visualizza Fc in quota di avvicinamento
   FC_in_quota_arrivo : WORD ;	//Visualizza Fc in quota di arrivo
   word_26 : WORD ;	//
   word_28 : WORD ;	//
   Tasto_Jog_Piu : BOOL ;	//Tasto Jog +
   Tasto_Jog_Meno : BOOL ;	//Tasto Jog -
   Tasto_Avanti : BOOL ;	//Tasto Avanti
   Tasto_Indietro : BOOL ;	//Tasto Indietro
   Tasto_Riposo : BOOL ;	//Tasto Riposo
   Tasto_Homing : BOOL ;	//Tasto Homing (zero asse)
   bit_30_6 : BOOL ;
   bit_30_7 : BOOL ;
   flag_1 : BOOL ;	//One shot
   flag_2 : BOOL ;
   flag_3 : BOOL ;
   flag_4 : BOOL ;
   flag_5 : BOOL ;
   flag_6 : BOOL ;
   flag_7 : BOOL ;
   flag_8 : BOOL ;
   BYTE_32 : BYTE ;	//
   WORD_34 : WORD ;
   WORD_36 : WORD ;
   word_38 : WORD ;	//
   Posizione_attuale : DINT ;	//Posizione attuale
   Posizione_1_impostata : DINT ;	//Posizione 1 di avicinamento
   Posizione_2_impostata : DINT ;	//Posizione 2 di cambio velocita'
   Posizione_3_impostata : DINT ;	//Posizione 3 di cambio velocita'
   Posizione_4_impostata : DINT ;	//Posizione 4 di arrivo
   Velocita_1_impostata : DINT ;	//Velocita' 1 di avvicinamento
   Velocita_2_impostata : DINT ;	//Velocita' 2
   Velocita_3_impostata : DINT ;	//Velocita' 3
   Velocita_4_impostata : DINT ;	//Velocita' 4 di arrivo
   Accell_1_impostata : DINT ;	//Accelerazione 1 di avvicinamento
   Accell_2_impostata : DINT ;	//Accelerazione 2
   Accell_3_impostata : DINT ;	//Accelerazione 3
   Accell_4_impostata : DINT ;	//Accelerazione 4 di arrivo
  END_STRUCT ;
BEGIN
   Bar_Graf := L#256005;
   limite_Bar_Graf := W#16#0;
   Imposta_posizione := L#0;
   Imposta_velocita := L#0;
   Imposta_accelerazione := L#0;
   word_18 := W#16#0;
   FC_in_quota_zero := W#16#0;
   FC_in_quota_avvicin := W#16#1;
   FC_in_quota_arrivo := W#16#0;
   word_26 := W#16#0;
   word_28 := W#16#0;
   Tasto_Jog_Piu := FALSE;
   Tasto_Jog_Meno := FALSE;
   Tasto_Avanti := FALSE;
   Tasto_Indietro := FALSE;
   Tasto_Riposo := FALSE;
   Tasto_Homing := FALSE;
   bit_30_6 := FALSE;
   bit_30_7 := FALSE;
   flag_1 := TRUE;
   flag_2 := FALSE;
   flag_3 := FALSE;
   flag_4 := FALSE;
   flag_5 := FALSE;
   flag_6 := FALSE;
   flag_7 := FALSE;
   flag_8 := FALSE;
   BYTE_32 := B#16#0;
   WORD_34 := W#16#0;
   WORD_36 := W#16#0;
   word_38 := W#16#0;
   Posizione_attuale := L#256005;
   Posizione_1_impostata := L#0;
   Posizione_2_impostata := L#0;
   Posizione_3_impostata := L#0;
   Posizione_4_impostata := L#385000;
   Velocita_1_impostata := L#0;
   Velocita_2_impostata := L#0;
   Velocita_3_impostata := L#0;
   Velocita_4_impostata := L#0;
   Accell_1_impostata := L#0;
   Accell_2_impostata := L#0;
   Accell_3_impostata := L#0;
   Accell_4_impostata := L#0;
END_DATA_BLOCK

DATA_BLOCK "C4--MP270"
TITLE =
VERSION : 0.1


  STRUCT
   Bar_Graf : DINT ;	//Visualizza grafica quota attuale
   limite_Bar_Graf : WORD ;	//Variabile limite bar_graf
   Imposta_posizione : DINT ;	//Imposta_posizione
   Imposta_velocita : DINT ;	//Imposta_velocita
   Imposta_accelerazione : DINT ;	//Imposta_accelerazione
   word_18 : WORD ;	//
   FC_in_quota_zero : WORD ;	//Visualizza Fc in quota di zero
   FC_in_quota_avvicin : WORD ;	//Visualizza Fc in quota di avvicinamento
   FC_in_quota_arrivo : WORD ;	//Visualizza Fc in quota di arrivo
   word_26 : WORD ;	//
   word_28 : WORD ;	//
   Tasto_Jog_Piu : BOOL ;	//Tasto Jog +
   Tasto_Jog_Meno : BOOL ;	//Tasto Jog -
   Tasto_Avanti : BOOL ;	//Tasto Avanti
   Tasto_Indietro : BOOL ;	//Tasto Indietro
   Tasto_Riposo : BOOL ;	//Tasto Riposo
   Tasto_Homing : BOOL ;	//Tasto Homing (zero asse)
   bit_30_6 : BOOL ;
   bit_30_7 : BOOL ;
   flag_1 : BOOL ;	//One shot
   flag_2 : BOOL ;
   flag_3 : BOOL ;
   flag_4 : BOOL ;
   flag_5 : BOOL ;
   flag_6 : BOOL ;
   flag_7 : BOOL ;
   flag_8 : BOOL ;
   BYTE_32 : BYTE ;	//
   WORD_34 : WORD ;
   WORD_36 : WORD ;
   word_38 : WORD ;	//
   Posizione_attuale : DINT ;	//Posizione attuale
   Posizione_1_impostata : DINT ;	//Posizione 1 di avicinamento
   Posizione_2_impostata : DINT ;	//Posizione 2 di cambio velocita'
   Posizione_3_impostata : DINT ;	//Posizione 3 di cambio velocita'
   Posizione_4_impostata : DINT ;	//Posizione 4 di arrivo
   Velocita_1_impostata : DINT ;	//Velocita' 1 di avvicinamento
   Velocita_2_impostata : DINT ;	//Velocita' 2
   Velocita_3_impostata : DINT ;	//Velocita' 3
   Velocita_4_impostata : DINT ;	//Velocita' 4 di arrivo
   Accell_1_impostata : DINT ;	//Accelerazione 1 di avvicinamento
   Accell_2_impostata : DINT ;	//Accelerazione 2
   Accell_3_impostata : DINT ;	//Accelerazione 3
   Accell_4_impostata : DINT ;	//Accelerazione 4 di arrivo
  END_STRUCT ;
BEGIN
   Bar_Graf := L#154013;
   limite_Bar_Graf := W#16#0;
   Imposta_posizione := L#0;
   Imposta_velocita := L#0;
   Imposta_accelerazione := L#0;
   word_18 := W#16#0;
   FC_in_quota_zero := W#16#0;
   FC_in_quota_avvicin := W#16#1;
   FC_in_quota_arrivo := W#16#0;
   word_26 := W#16#0;
   word_28 := W#16#0;
   Tasto_Jog_Piu := FALSE;
   Tasto_Jog_Meno := FALSE;
   Tasto_Avanti := FALSE;
   Tasto_Indietro := FALSE;
   Tasto_Riposo := FALSE;
   Tasto_Homing := FALSE;
   bit_30_6 := FALSE;
   bit_30_7 := FALSE;
   flag_1 := TRUE;
   flag_2 := FALSE;
   flag_3 := FALSE;
   flag_4 := FALSE;
   flag_5 := FALSE;
   flag_6 := FALSE;
   flag_7 := FALSE;
   flag_8 := FALSE;
   BYTE_32 := B#16#0;
   WORD_34 := W#16#0;
   WORD_36 := W#16#0;
   word_38 := W#16#0;
   Posizione_attuale := L#154013;
   Posizione_1_impostata := L#0;
   Posizione_2_impostata := L#0;
   Posizione_3_impostata := L#0;
   Posizione_4_impostata := L#283000;
   Velocita_1_impostata := L#0;
   Velocita_2_impostata := L#0;
   Velocita_3_impostata := L#0;
   Velocita_4_impostata := L#0;
   Accell_1_impostata := L#0;
   Accell_2_impostata := L#0;
   Accell_3_impostata := L#0;
   Accell_4_impostata := L#0;
END_DATA_BLOCK

DATA_BLOCK "C5--MP270"
TITLE =
VERSION : 0.1


  STRUCT
   Bar_Graf : DINT ;	//Visualizza grafica quota attuale
   limite_Bar_Graf : WORD ;	//Variabile limite bar_graf
   Imposta_posizione : DINT ;	//Imposta_posizione
   Imposta_velocita : DINT ;	//Imposta_velocita
   Imposta_accelerazione : DINT ;	//Imposta_accelerazione
   word_18 : WORD ;	//
   FC_in_quota_zero : WORD ;	//Visualizza Fc in quota di zero
   FC_in_quota_avvicin : WORD ;	//Visualizza Fc in quota di avvicinamento
   FC_in_quota_arrivo : WORD ;	//Visualizza Fc in quota di arrivo
   word_26 : WORD ;	//
   word_28 : WORD ;	//
   Tasto_Jog_Piu : BOOL ;	//Tasto Jog +
   Tasto_Jog_Meno : BOOL ;	//Tasto Jog -
   Tasto_Avanti : BOOL ;	//Tasto Avanti
   Tasto_Indietro : BOOL ;	//Tasto Indietro
   Tasto_Riposo : BOOL ;	//Tasto Riposo
   Tasto_Homing : BOOL ;	//Tasto Homing (zero asse)
   bit_30_6 : BOOL ;
   bit_30_7 : BOOL ;
   flag_1 : BOOL ;	//One shot
   flag_2 : BOOL ;
   flag_3 : BOOL ;
   flag_4 : BOOL ;
   flag_5 : BOOL ;
   flag_6 : BOOL ;
   flag_7 : BOOL ;
   flag_8 : BOOL ;
   BYTE_32 : BYTE ;	//
   WORD_34 : WORD ;
   WORD_36 : WORD ;
   word_38 : WORD ;	//
   Posizione_attuale : DINT ;	//Posizione attuale
   Posizione_1_impostata : DINT ;	//Posizione 1 di avicinamento
   Posizione_2_impostata : DINT ;	//Posizione 2 di cambio velocita'
   Posizione_3_impostata : DINT ;	//Posizione 3 di cambio velocita'
   Posizione_4_impostata : DINT ;	//Posizione 4 di arrivo
   Velocita_1_impostata : DINT ;	//Velocita' 1 di avvicinamento
   Velocita_2_impostata : DINT ;	//Velocita' 2
   Velocita_3_impostata : DINT ;	//Velocita' 3
   Velocita_4_impostata : DINT ;	//Velocita' 4 di arrivo
   Accell_1_impostata : DINT ;	//Accelerazione 1 di avvicinamento
   Accell_2_impostata : DINT ;	//Accelerazione 2
   Accell_3_impostata : DINT ;	//Accelerazione 3
   Accell_4_impostata : DINT ;	//Accelerazione 4 di arrivo
  END_STRUCT ;
BEGIN
   Bar_Graf := L#395002;
   limite_Bar_Graf := W#16#0;
   Imposta_posizione := L#0;
   Imposta_velocita := L#0;
   Imposta_accelerazione := L#0;
   word_18 := W#16#0;
   FC_in_quota_zero := W#16#0;
   FC_in_quota_avvicin := W#16#1;
   FC_in_quota_arrivo := W#16#0;
   word_26 := W#16#0;
   word_28 := W#16#0;
   Tasto_Jog_Piu := FALSE;
   Tasto_Jog_Meno := FALSE;
   Tasto_Avanti := FALSE;
   Tasto_Indietro := FALSE;
   Tasto_Riposo := FALSE;
   Tasto_Homing := FALSE;
   bit_30_6 := FALSE;
   bit_30_7 := FALSE;
   flag_1 := TRUE;
   flag_2 := FALSE;
   flag_3 := FALSE;
   flag_4 := FALSE;
   flag_5 := FALSE;
   flag_6 := FALSE;
   flag_7 := FALSE;
   flag_8 := FALSE;
   BYTE_32 := B#16#0;
   WORD_34 := W#16#0;
   WORD_36 := W#16#0;
   word_38 := W#16#0;
   Posizione_attuale := L#395002;
   Posizione_1_impostata := L#0;
   Posizione_2_impostata := L#0;
   Posizione_3_impostata := L#0;
   Posizione_4_impostata := L#510000;
   Velocita_1_impostata := L#0;
   Velocita_2_impostata := L#0;
   Velocita_3_impostata := L#0;
   Velocita_4_impostata := L#0;
   Accell_1_impostata := L#0;
   Accell_2_impostata := L#0;
   Accell_3_impostata := L#0;
   Accell_4_impostata := L#0;
END_DATA_BLOCK

DATA_BLOCK "C6--MP270"
TITLE =
VERSION : 0.1


  STRUCT
   Bar_Graf : DINT ;	//Visualizza grafica quota attuale
   limite_Bar_Graf : WORD ;	//Variabile limite bar_graf
   Imposta_posizione : DINT ;	//Imposta_posizione
   Imposta_velocita : DINT ;	//Imposta_velocita
   Imposta_accelerazione : DINT ;	//Imposta_accelerazione
   word_18 : WORD ;	//
   FC_in_quota_zero : WORD ;	//Visualizza Fc in quota di zero
   FC_in_quota_avvicin : WORD ;	//Visualizza Fc in quota di avvicinamento
   FC_in_quota_arrivo : WORD ;	//Visualizza Fc in quota di arrivo
   word_26 : WORD ;	//
   word_28 : WORD ;	//
   Tasto_Jog_Piu : BOOL ;	//Tasto Jog +
   Tasto_Jog_Meno : BOOL ;	//Tasto Jog -
   Tasto_Avanti : BOOL ;	//Tasto Avanti
   Tasto_Indietro : BOOL ;	//Tasto Indietro
   Tasto_Riposo : BOOL ;	//Tasto Riposo
   Tasto_Homing : BOOL ;	//Tasto Homing (zero asse)
   bit_30_6 : BOOL ;
   bit_30_7 : BOOL ;
   flag_1 : BOOL ;	//One shot
   flag_2 : BOOL ;
   flag_3 : BOOL ;
   flag_4 : BOOL ;
   flag_5 : BOOL ;
   flag_6 : BOOL ;
   flag_7 : BOOL ;
   flag_8 : BOOL ;
   BYTE_32 : BYTE ;	//
   WORD_34 : WORD ;
   WORD_36 : WORD ;
   word_38 : WORD ;	//
   Posizione_attuale : DINT ;	//Posizione attuale
   Posizione_1_impostata : DINT ;	//Posizione 1 di avicinamento
   Posizione_2_impostata : DINT ;	//Posizione 2 di cambio velocita'
   Posizione_3_impostata : DINT ;	//Posizione 3 di cambio velocita'
   Posizione_4_impostata : DINT ;	//Posizione 4 di arrivo
   Velocita_1_impostata : DINT ;	//Velocita' 1 di avvicinamento
   Velocita_2_impostata : DINT ;	//Velocita' 2
   Velocita_3_impostata : DINT ;	//Velocita' 3
   Velocita_4_impostata : DINT ;	//Velocita' 4 di arrivo
   Accell_1_impostata : DINT ;	//Accelerazione 1 di avvicinamento
   Accell_2_impostata : DINT ;	//Accelerazione 2
   Accell_3_impostata : DINT ;	//Accelerazione 3
   Accell_4_impostata : DINT ;	//Accelerazione 4 di arrivo
  END_STRUCT ;
BEGIN
   Bar_Graf := L#430000;
   limite_Bar_Graf := W#16#0;
   Imposta_posizione := L#0;
   Imposta_velocita := L#0;
   Imposta_accelerazione := L#0;
   word_18 := W#16#0;
   FC_in_quota_zero := W#16#0;
   FC_in_quota_avvicin := W#16#1;
   FC_in_quota_arrivo := W#16#0;
   word_26 := W#16#0;
   word_28 := W#16#0;
   Tasto_Jog_Piu := FALSE;
   Tasto_Jog_Meno := FALSE;
   Tasto_Avanti := FALSE;
   Tasto_Indietro := FALSE;
   Tasto_Riposo := FALSE;
   Tasto_Homing := FALSE;
   bit_30_6 := FALSE;
   bit_30_7 := FALSE;
   flag_1 := TRUE;
   flag_2 := FALSE;
   flag_3 := FALSE;
   flag_4 := FALSE;
   flag_5 := FALSE;
   flag_6 := FALSE;
   flag_7 := FALSE;
   flag_8 := FALSE;
   BYTE_32 := B#16#0;
   WORD_34 := W#16#0;
   WORD_36 := W#16#0;
   word_38 := W#16#0;
   Posizione_attuale := L#430000;
   Posizione_1_impostata := L#0;
   Posizione_2_impostata := L#0;
   Posizione_3_impostata := L#0;
   Posizione_4_impostata := L#525000;
   Velocita_1_impostata := L#0;
   Velocita_2_impostata := L#0;
   Velocita_3_impostata := L#0;
   Velocita_4_impostata := L#0;
   Accell_1_impostata := L#0;
   Accell_2_impostata := L#0;
   Accell_3_impostata := L#0;
   Accell_4_impostata := L#0;
END_DATA_BLOCK

DATA_BLOCK "GESTIONE MATRICOLE"
TITLE =
VERSION : 0.1


  STRUCT
   NR_matric_da_MP270 : INT ;	//Numero matricola letta da operatore
   NR_matric_da_linea : INT ;	//Numero matricola letta da linea Comau
   NR_matric_MP270_confront : INT ;	//Numero matricola da confrontare letto da MP270
   NR_matric_linea_confront : INT ;	//Numero matricola da confrontare letto da linea
   word8 : INT ;
  END_STRUCT ;
BEGIN
   NR_matric_da_MP270 := 3;
   NR_matric_da_linea := 2;
   NR_matric_MP270_confront := 3;
   NR_matric_linea_confront := 2;
   word8 := 0;
END_DATA_BLOCK

DATA_BLOCK "MATRICOLA 1"
AUTHOR : Lodato
FAMILY : DESTACK
NAME : DATI
VERSION : 0.1


  STRUCT
   LARGHEZZA_LAMIERA : REAL  := 1.500000e+003;	//LARGHEZZA LAMIERA ATTUALE
   COMPENSAZ_TAV_1 : REAL ;	//COMPENSAZIONE TAVOLA 1
   QUOTA_H_SFOGLIATORE : REAL ;	//Quota impostata altezza sfogliatore
   QUOTA_H_CENTRATORE : REAL ;	//Quota impostata altezza centratore
   word16 : S5TIME ;
   INCLINAZ_TAVOLA_ESCLUSA : BOOL ;	//INCLINAZIONE TAVOLA ESCLUSA
   dword20 : REAL ;
   dword24 : REAL ;
   dword28 : REAL ;
   dword32 : REAL ;
   dword36 : REAL ;
   NR_MATRICOLA : INT  := 1;	//Numero di matricola
   word42 : WORD ;
   MAGNETE_1_ESCLUSO : BOOL ;	//MAGNETE 1 ESCLUSO DA MP270
   MAGNETE_2_ESCLUSO : BOOL ;	//MAGNETE 2 ESCLUSO DA MP270
   MAGNETE_3_ESCLUSO : BOOL ;	//MAGNETE 3 ESCLUSO DA MP270
   MAGNETE_4_ESCLUSO : BOOL ;	//MAGNETE 4 ESCLUSO DA MP270
   MAGNETE_5_ESCLUSO : BOOL ;	//MAGNETE 5 ESCLUSO DA MP270
   MAGNETE_6_ESCLUSO : BOOL ;	//MAGNETE 6 ESCLUSO DA MP270
   MAGNETE_LAT_SX_ESCLUSO : BOOL ;	//MAGNETE LATERALE SX ESCLUSO DA MP270
   MAGNETE_LAT_DX_ESCLUSO : BOOL ;	//MAGNETE LATERALE DX ESCLUSO DA MP270
   COMPENSAZ_TAV_2 : REAL ;	//COMPENSAZIONE TAVOLA 2
   STAT22 : WORD ;
   STAT23 : WORD ;
   STAT24 : WORD ;
   STAT25 : WORD ;
   STAT251 : WORD ;
   STAT26 : TIME ;
   STAT29 : TIME ;
   STAT30 : TIME ;
   STAT31 : TIME ;
   C1_Timer : REAL ;	//Centratore 1: Timer ritardo partenza
   C2_Timer : REAL ;	//Centratore 2: Timer ritardo partenza
   C3_Timer : REAL ;	//Centratore 3: Timer ritardo partenza
   C4_Timer : REAL ;	//Centratore 4: Timer ritardo partenza
   C5_Timer : REAL ;	//Centratore 5: Timer ritardo partenza
   C6_Timer : REAL ;	//Centratore 6: Timer ritardo partenza
   C1_Posizione_1 : DINT  := L#500000;	//Centratore 1: Posizione 1 di avicinamento
   C1_Posizione_2 : DINT  := L#520000;	//Centratore 1: Posizione 2 di cambio velocita'
   C1_Posizione_3 : DINT  := L#530000;	//Centratore 1: Posizione 3 di cambio velocita'
   C1_Posizione_4 : DINT  := L#565400;	//Centratore 1: Posizione 4 di arrivo
   C1_Velocita_1 : DINT  := L#50;	//Centratore 1: Velocita' 1 di avvicinamento
   C1_Velocita_2 : DINT  := L#50;	//Centratore 1: Velocita' 2
   C1_Velocita_3 : DINT  := L#50;	//Centratore 1: Velocita' 3
   C1_Velocita_4 : DINT  := L#50;	//Centratore 1: Velocita' 4 di arrivo
   C1_Accell_1 : DINT  := L#500;	//Centratore 1: Accelerazione 1 di avvicinamento
   C1_Accell_2 : DINT  := L#500;	//Centratore 1: Accelerazione 2
   C1_Accell_3 : DINT  := L#500;	//Centratore 1: Accelerazione 3
   C1_Accell_4 : DINT  := L#500;	//Centratore 1: Accelerazione 4 di arrivo
   word_148 : WORD ;
   C2_Posizione_1 : DINT  := L#500000;	//Centratore 2: Posizione 1 di avicinamento
   C2_Posizione_2 : DINT  := L#520000;	//Centratore 2: Posizione 2 di cambio velocita'
   C2_Posizione_3 : DINT  := L#530000;	//Centratore 2: Posizione 3 di cambio velocita'
   C2_Posizione_4 : DINT  := L#559000;	//Centratore 2: Posizione 4 di arrivo
   C2_Velocita_1 : DINT  := L#50;	//Centratore 2: Velocita' 1 di avvicinamento
   C2_Velocita_2 : DINT  := L#50;	//Centratore 2: Velocita' 2
   C2_Velocita_3 : DINT  := L#50;	//Centratore 2: Velocita' 3
   C2_Velocita_4 : DINT  := L#50;	//Centratore 2: Velocita' 4 di arrivo
   C2_Accell_1 : DINT  := L#500;	//Centratore 2: Accelerazione 1 di avvicinamento
   C2_Accell_2 : DINT  := L#500;	//Centratore 2: Accelerazione 2
   C2_Accell_3 : DINT  := L#500;	//Centratore 2: Accelerazione 3
   C2_Accell_4 : DINT  := L#500;	//Centratore 2: Accelerazione 4 di arrivo
   word_198 : WORD ;
   C3_Posizione_1 : DINT  := L#630000;	//Centratore 3: Posizione 1 di avicinamento
   C3_Posizione_2 : DINT  := L#650000;	//Centratore 3: Posizione 2 di cambio velocita'
   C3_Posizione_3 : DINT  := L#660000;	//Centratore 3: Posizione 3 di cambio velocita'
   C3_Posizione_4 : DINT  := L#698600;	//Centratore 3: Posizione 4 di arrivo
   C3_Velocita_1 : DINT  := L#50;	//Centratore 3: Velocita' 1 di avvicinamento
   C3_Velocita_2 : DINT  := L#50;	//Centratore 3: Velocita' 2
   C3_Velocita_3 : DINT  := L#50;	//Centratore 3: Velocita' 3
   C3_Velocita_4 : DINT  := L#50;	//Centratore 3: Velocita' 4 di arrivo
   C3_Accell_1 : DINT  := L#500;	//Centratore 3: Accelerazione 1 di avvicinamento
   C3_Accell_2 : DINT  := L#500;	//Centratore 3: Accelerazione 2
   C3_Accell_3 : DINT  := L#500;	//Centratore 3: Accelerazione 3
   C3_Accell_4 : DINT  := L#500;	//Centratore 3: Accelerazione 4 di arrivo
   word_248 : WORD ;
   C4_Posizione_1 : DINT  := L#630000;	//Centratore 4: Posizione 1 di avicinamento
   C4_Posizione_2 : DINT  := L#650000;	//Centratore 4: Posizione 2 di cambio velocita'
   C4_Posizione_3 : DINT  := L#660000;	//Centratore 4: Posizione 3 di cambio velocita'
   C4_Posizione_4 : DINT  := L#706200;	//Centratore 4: Posizione 4 di arrivo
   C4_Velocita_1 : DINT  := L#50;	//Centratore 4: Velocita' 1 di avvicinamento
   C4_Velocita_2 : DINT  := L#50;	//Centratore 4: Velocita' 2
   C4_Velocita_3 : DINT  := L#50;	//Centratore 4: Velocita' 3
   C4_Velocita_4 : DINT  := L#50;	//Centratore 4: Velocita' 4 di arrivo
   C4_Accell_1 : DINT  := L#500;	//Centratore 4: Accelerazione 1 di avvicinamento
   C4_Accell_2 : DINT  := L#500;	//Centratore 4: Accelerazione 2
   C4_Accell_3 : DINT  := L#500;	//Centratore 4: Accelerazione 3
   C4_Accell_4 : DINT  := L#500;	//Centratore 4: Accelerazione 4 di arrivo
   word_298 : WORD ;
   C5_Posizione_1 : DINT  := L#1180000;	//Centratore 5: Posizione 1 di avicinamento
   C5_Posizione_2 : DINT  := L#1200000;	//Centratore 5: Posizione 2 di cambio velocita'
   C5_Posizione_3 : DINT  := L#1220000;	//Centratore 5: Posizione 3 di cambio velocita'
   C5_Posizione_4 : DINT  := L#1247000;	//Centratore 5: Posizione 4 di arrivo
   C5_Velocita_1 : DINT  := L#50;	//Centratore 5: Velocita' 1 di avvicinamento
   C5_Velocita_2 : DINT  := L#50;	//Centratore 5: Velocita' 2
   C5_Velocita_3 : DINT  := L#50;	//Centratore 5: Velocita' 3
   C5_Velocita_4 : DINT  := L#50;	//Centratore 5: Velocita' 4 di arrivo
   C5_Accell_1 : DINT  := L#500;	//Centratore 5: Accelerazione 1 di avvicinamento
   C5_Accell_2 : DINT  := L#500;	//Centratore 5: Accelerazione 2
   C5_Accell_3 : DINT  := L#500;	//Centratore 5: Accelerazione 3
   C5_Accell_4 : DINT  := L#500;	//Centratore 5: Accelerazione 4 di arrivo
   word_348 : WORD ;
   C6_Posizione_1 : DINT  := L#1180000;	//Centratore 6: Posizione 1 di avicinamento
   C6_Posizione_2 : DINT  := L#1200000;	//Centratore 6: Posizione 2 di cambio velocita'
   C6_Posizione_3 : DINT  := L#1220000;	//Centratore 6: Posizione 3 di cambio velocita'
   C6_Posizione_4 : DINT  := L#1237400;	//Centratore 6: Posizione 4 di arrivo
   C6_Velocita_1 : DINT  := L#50;	//Centratore 6: Velocita' 1 di avvicinamento
   C6_Velocita_2 : DINT  := L#50;	//Centratore 6: Velocita' 2
   C6_Velocita_3 : DINT  := L#50;	//Centratore 6: Velocita' 3
   C6_Velocita_4 : DINT  := L#50;	//Centratore 6: Velocita' 4 di arrivo
   C6_Accell_1 : DINT  := L#500;	//Centratore 6: Accelerazione 1 di avvicinamento
   C6_Accell_2 : DINT  := L#500;	//Centratore 6: Accelerazione 2
   C6_Accell_3 : DINT  := L#500;	//Centratore 6: Accelerazione 3
   C6_Accell_4 : DINT  := L#500;	//Centratore 6: Accelerazione 4 di arrivo
   word_398 : WORD ;
  END_STRUCT ;
BEGIN
   LARGHEZZA_LAMIERA := 1.600000e+003;
   COMPENSAZ_TAV_1 := -3.000000e+001;
   QUOTA_H_SFOGLIATORE := 1.630000e+003;
   QUOTA_H_CENTRATORE := 1.630000e+003;
   word16 := S5T#0MS;
   INCLINAZ_TAVOLA_ESCLUSA := TRUE;
   dword20 := 0.000000e+000;
   dword24 := 0.000000e+000;
   dword28 := 0.000000e+000;
   dword32 := 0.000000e+000;
   dword36 := 0.000000e+000;
   NR_MATRICOLA := 1;
   word42 := W#16#0;
   MAGNETE_1_ESCLUSO := TRUE;
   MAGNETE_2_ESCLUSO := FALSE;
   MAGNETE_3_ESCLUSO := FALSE;
   MAGNETE_4_ESCLUSO := FALSE;
   MAGNETE_5_ESCLUSO := FALSE;
   MAGNETE_6_ESCLUSO := TRUE;
   MAGNETE_LAT_SX_ESCLUSO := TRUE;
   MAGNETE_LAT_DX_ESCLUSO := TRUE;
   COMPENSAZ_TAV_2 := -3.000000e+001;
   STAT22 := W#16#0;
   STAT23 := W#16#0;
   STAT24 := W#16#0;
   STAT25 := W#16#0;
   STAT251 := W#16#0;
   STAT26 := T#0MS;
   STAT29 := T#0MS;
   STAT30 := T#0MS;
   STAT31 := T#0MS;
   C1_Timer := 0.000000e+000;
   C2_Timer := 0.000000e+000;
   C3_Timer := 0.000000e+000;
   C4_Timer := 0.000000e+000;
   C5_Timer := 0.000000e+000;
   C6_Timer := 0.000000e+000;
   C1_Posizione_1 := L#500000;
   C1_Posizione_2 := L#520000;
   C1_Posizione_3 := L#530000;
   C1_Posizione_4 := L#565400;
   C1_Velocita_1 := L#500;
   C1_Velocita_2 := L#200;
   C1_Velocita_3 := L#200;
   C1_Velocita_4 := L#50;
   C1_Accell_1 := L#500;
   C1_Accell_2 := L#500;
   C1_Accell_3 := L#500;
   C1_Accell_4 := L#500;
   word_148 := W#16#0;
   C2_Posizione_1 := L#500000;
   C2_Posizione_2 := L#520000;
   C2_Posizione_3 := L#530000;
   C2_Posizione_4 := L#559000;
   C2_Velocita_1 := L#500;
   C2_Velocita_2 := L#200;
   C2_Velocita_3 := L#200;
   C2_Velocita_4 := L#50;
   C2_Accell_1 := L#500;
   C2_Accell_2 := L#500;
   C2_Accell_3 := L#500;
   C2_Accell_4 := L#500;
   word_198 := W#16#0;
   C3_Posizione_1 := L#630000;
   C3_Posizione_2 := L#650000;
   C3_Posizione_3 := L#660000;
   C3_Posizione_4 := L#698600;
   C3_Velocita_1 := L#500;
   C3_Velocita_2 := L#200;
   C3_Velocita_3 := L#200;
   C3_Velocita_4 := L#50;
   C3_Accell_1 := L#500;
   C3_Accell_2 := L#500;
   C3_Accell_3 := L#500;
   C3_Accell_4 := L#500;
   word_248 := W#16#0;
   C4_Posizione_1 := L#630000;
   C4_Posizione_2 := L#650000;
   C4_Posizione_3 := L#660000;
   C4_Posizione_4 := L#706200;
   C4_Velocita_1 := L#500;
   C4_Velocita_2 := L#200;
   C4_Velocita_3 := L#200;
   C4_Velocita_4 := L#50;
   C4_Accell_1 := L#500;
   C4_Accell_2 := L#500;
   C4_Accell_3 := L#500;
   C4_Accell_4 := L#500;
   word_298 := W#16#0;
   C5_Posizione_1 := L#1180000;
   C5_Posizione_2 := L#1200000;
   C5_Posizione_3 := L#1210000;
   C5_Posizione_4 := L#1247000;
   C5_Velocita_1 := L#500;
   C5_Velocita_2 := L#200;
   C5_Velocita_3 := L#200;
   C5_Velocita_4 := L#50;
   C5_Accell_1 := L#500;
   C5_Accell_2 := L#500;
   C5_Accell_3 := L#500;
   C5_Accell_4 := L#500;
   word_348 := W#16#0;
   C6_Posizione_1 := L#1180000;
   C6_Posizione_2 := L#1200000;
   C6_Posizione_3 := L#1210000;
   C6_Posizione_4 := L#1237400;
   C6_Velocita_1 := L#500;
   C6_Velocita_2 := L#200;
   C6_Velocita_3 := L#200;
   C6_Velocita_4 := L#50;
   C6_Accell_1 := L#500;
   C6_Accell_2 := L#500;
   C6_Accell_3 := L#500;
   C6_Accell_4 := L#500;
   word_398 := W#16#0;
END_DATA_BLOCK

DATA_BLOCK "MATRICOLA 2"
AUTHOR : Lodato
FAMILY : DESTACK
NAME : DATI
VERSION : 0.1


  STRUCT
   LARGHEZZA_LAMIERA : REAL  := 1.500000e+003;	//LARGHEZZA LAMIERA ATTUALE
   COMPENSAZ_TAV_1 : REAL ;	//COMPENSAZIONE TAVOLA 1
   QUOTA_H_SFOGLIATORE : REAL ;	//Quota impostata altezza sfogliatore
   QUOTA_H_CENTRATORE : REAL ;	//Quota impostata altezza centratore
   word16 : S5TIME ;
   INCLINAZ_TAVOLA_ESCLUSA : BOOL ;	//INCLINAZIONE TAVOLA ESCLUSA
   dword20 : REAL ;
   dword24 : REAL ;
   dword28 : REAL ;
   dword32 : REAL ;
   dword36 : REAL ;
   NR_MATRICOLA : INT  := 1;	//Numero di matricola
   word42 : WORD ;
   MAGNETE_1_ESCLUSO : BOOL ;	//MAGNETE 1 ESCLUSO DA MP270
   MAGNETE_2_ESCLUSO : BOOL ;	//MAGNETE 2 ESCLUSO DA MP270
   MAGNETE_3_ESCLUSO : BOOL ;	//MAGNETE 3 ESCLUSO DA MP270
   MAGNETE_4_ESCLUSO : BOOL ;	//MAGNETE 4 ESCLUSO DA MP270
   MAGNETE_5_ESCLUSO : BOOL ;	//MAGNETE 5 ESCLUSO DA MP270
   MAGNETE_6_ESCLUSO : BOOL ;	//MAGNETE 6 ESCLUSO DA MP270
   MAGNETE_LAT_SX_ESCLUSO : BOOL ;	//MAGNETE LATERALE SX ESCLUSO DA MP270
   MAGNETE_LAT_DX_ESCLUSO : BOOL ;	//MAGNETE LATERALE DX ESCLUSO DA MP270
   COMPENSAZ_TAV_2 : REAL ;	//COMPENSAZIONE TAVOLA 2
   STAT22 : WORD ;
   STAT23 : WORD ;
   STAT24 : WORD ;
   STAT25 : WORD ;
   STAT251 : WORD ;
   STAT26 : TIME ;
   STAT29 : TIME ;
   STAT30 : TIME ;
   STAT31 : TIME ;
   C1_Timer : REAL ;	//Centratore 1: Timer ritardo partenza
   C2_Timer : REAL ;	//Centratore 2: Timer ritardo partenza
   C3_Timer : REAL ;	//Centratore 3: Timer ritardo partenza
   C4_Timer : REAL ;	//Centratore 4: Timer ritardo partenza
   C5_Timer : REAL ;	//Centratore 5: Timer ritardo partenza
   C6_Timer : REAL ;	//Centratore 6: Timer ritardo partenza
   C1_Posizione_1 : DINT  := L#500000;	//Centratore 1: Posizione 1 di avicinamento
   C1_Posizione_2 : DINT  := L#520000;	//Centratore 1: Posizione 2 di cambio velocita'
   C1_Posizione_3 : DINT  := L#530000;	//Centratore 1: Posizione 3 di cambio velocita'
   C1_Posizione_4 : DINT  := L#565400;	//Centratore 1: Posizione 4 di arrivo
   C1_Velocita_1 : DINT  := L#50;	//Centratore 1: Velocita' 1 di avvicinamento
   C1_Velocita_2 : DINT  := L#50;	//Centratore 1: Velocita' 2
   C1_Velocita_3 : DINT  := L#50;	//Centratore 1: Velocita' 3
   C1_Velocita_4 : DINT  := L#50;	//Centratore 1: Velocita' 4 di arrivo
   C1_Accell_1 : DINT  := L#500;	//Centratore 1: Accelerazione 1 di avvicinamento
   C1_Accell_2 : DINT  := L#500;	//Centratore 1: Accelerazione 2
   C1_Accell_3 : DINT  := L#500;	//Centratore 1: Accelerazione 3
   C1_Accell_4 : DINT  := L#500;	//Centratore 1: Accelerazione 4 di arrivo
   word_148 : WORD ;
   C2_Posizione_1 : DINT  := L#500000;	//Centratore 2: Posizione 1 di avicinamento
   C2_Posizione_2 : DINT  := L#520000;	//Centratore 2: Posizione 2 di cambio velocita'
   C2_Posizione_3 : DINT  := L#530000;	//Centratore 2: Posizione 3 di cambio velocita'
   C2_Posizione_4 : DINT  := L#559000;	//Centratore 2: Posizione 4 di arrivo
   C2_Velocita_1 : DINT  := L#50;	//Centratore 2: Velocita' 1 di avvicinamento
   C2_Velocita_2 : DINT  := L#50;	//Centratore 2: Velocita' 2
   C2_Velocita_3 : DINT  := L#50;	//Centratore 2: Velocita' 3
   C2_Velocita_4 : DINT  := L#50;	//Centratore 2: Velocita' 4 di arrivo
   C2_Accell_1 : DINT  := L#500;	//Centratore 2: Accelerazione 1 di avvicinamento
   C2_Accell_2 : DINT  := L#500;	//Centratore 2: Accelerazione 2
   C2_Accell_3 : DINT  := L#500;	//Centratore 2: Accelerazione 3
   C2_Accell_4 : DINT  := L#500;	//Centratore 2: Accelerazione 4 di arrivo
   word_198 : WORD ;
   C3_Posizione_1 : DINT  := L#630000;	//Centratore 3: Posizione 1 di avicinamento
   C3_Posizione_2 : DINT  := L#650000;	//Centratore 3: Posizione 2 di cambio velocita'
   C3_Posizione_3 : DINT  := L#660000;	//Centratore 3: Posizione 3 di cambio velocita'
   C3_Posizione_4 : DINT  := L#698600;	//Centratore 3: Posizione 4 di arrivo
   C3_Velocita_1 : DINT  := L#50;	//Centratore 3: Velocita' 1 di avvicinamento
   C3_Velocita_2 : DINT  := L#50;	//Centratore 3: Velocita' 2
   C3_Velocita_3 : DINT  := L#50;	//Centratore 3: Velocita' 3
   C3_Velocita_4 : DINT  := L#50;	//Centratore 3: Velocita' 4 di arrivo
   C3_Accell_1 : DINT  := L#500;	//Centratore 3: Accelerazione 1 di avvicinamento
   C3_Accell_2 : DINT  := L#500;	//Centratore 3: Accelerazione 2
   C3_Accell_3 : DINT  := L#500;	//Centratore 3: Accelerazione 3
   C3_Accell_4 : DINT  := L#500;	//Centratore 3: Accelerazione 4 di arrivo
   word_248 : WORD ;
   C4_Posizione_1 : DINT  := L#630000;	//Centratore 4: Posizione 1 di avicinamento
   C4_Posizione_2 : DINT  := L#650000;	//Centratore 4: Posizione 2 di cambio velocita'
   C4_Posizione_3 : DINT  := L#660000;	//Centratore 4: Posizione 3 di cambio velocita'
   C4_Posizione_4 : DINT  := L#706200;	//Centratore 4: Posizione 4 di arrivo
   C4_Velocita_1 : DINT  := L#50;	//Centratore 4: Velocita' 1 di avvicinamento
   C4_Velocita_2 : DINT  := L#50;	//Centratore 4: Velocita' 2
   C4_Velocita_3 : DINT  := L#50;	//Centratore 4: Velocita' 3
   C4_Velocita_4 : DINT  := L#50;	//Centratore 4: Velocita' 4 di arrivo
   C4_Accell_1 : DINT  := L#500;	//Centratore 4: Accelerazione 1 di avvicinamento
   C4_Accell_2 : DINT  := L#500;	//Centratore 4: Accelerazione 2
   C4_Accell_3 : DINT  := L#500;	//Centratore 4: Accelerazione 3
   C4_Accell_4 : DINT  := L#500;	//Centratore 4: Accelerazione 4 di arrivo
   word_298 : WORD ;
   C5_Posizione_1 : DINT  := L#1180000;	//Centratore 5: Posizione 1 di avicinamento
   C5_Posizione_2 : DINT  := L#1200000;	//Centratore 5: Posizione 2 di cambio velocita'
   C5_Posizione_3 : DINT  := L#1220000;	//Centratore 5: Posizione 3 di cambio velocita'
   C5_Posizione_4 : DINT  := L#1247000;	//Centratore 5: Posizione 4 di arrivo
   C5_Velocita_1 : DINT  := L#50;	//Centratore 5: Velocita' 1 di avvicinamento
   C5_Velocita_2 : DINT  := L#50;	//Centratore 5: Velocita' 2
   C5_Velocita_3 : DINT  := L#50;	//Centratore 5: Velocita' 3
   C5_Velocita_4 : DINT  := L#50;	//Centratore 5: Velocita' 4 di arrivo
   C5_Accell_1 : DINT  := L#500;	//Centratore 5: Accelerazione 1 di avvicinamento
   C5_Accell_2 : DINT  := L#500;	//Centratore 5: Accelerazione 2
   C5_Accell_3 : DINT  := L#500;	//Centratore 5: Accelerazione 3
   C5_Accell_4 : DINT  := L#500;	//Centratore 5: Accelerazione 4 di arrivo
   word_348 : WORD ;
   C6_Posizione_1 : DINT  := L#1180000;	//Centratore 6: Posizione 1 di avicinamento
   C6_Posizione_2 : DINT  := L#1200000;	//Centratore 6: Posizione 2 di cambio velocita'
   C6_Posizione_3 : DINT  := L#1220000;	//Centratore 6: Posizione 3 di cambio velocita'
   C6_Posizione_4 : DINT  := L#1237400;	//Centratore 6: Posizione 4 di arrivo
   C6_Velocita_1 : DINT  := L#50;	//Centratore 6: Velocita' 1 di avvicinamento
   C6_Velocita_2 : DINT  := L#50;	//Centratore 6: Velocita' 2
   C6_Velocita_3 : DINT  := L#50;	//Centratore 6: Velocita' 3
   C6_Velocita_4 : DINT  := L#50;	//Centratore 6: Velocita' 4 di arrivo
   C6_Accell_1 : DINT  := L#500;	//Centratore 6: Accelerazione 1 di avvicinamento
   C6_Accell_2 : DINT  := L#500;	//Centratore 6: Accelerazione 2
   C6_Accell_3 : DINT  := L#500;	//Centratore 6: Accelerazione 3
   C6_Accell_4 : DINT  := L#500;	//Centratore 6: Accelerazione 4 di arrivo
   word_398 : WORD ;
  END_STRUCT ;
BEGIN
   LARGHEZZA_LAMIERA := 3.060000e+003;
   COMPENSAZ_TAV_1 := -7.000000e+001;
   QUOTA_H_SFOGLIATORE := 2.000000e+003;
   QUOTA_H_CENTRATORE := 1.960000e+003;
   word16 := S5T#0MS;
   INCLINAZ_TAVOLA_ESCLUSA := FALSE;
   dword20 := 0.000000e+000;
   dword24 := 0.000000e+000;
   dword28 := 0.000000e+000;
   dword32 := 0.000000e+000;
   dword36 := 0.000000e+000;
   NR_MATRICOLA := 2;
   word42 := W#16#0;
   MAGNETE_1_ESCLUSO := FALSE;
   MAGNETE_2_ESCLUSO := FALSE;
   MAGNETE_3_ESCLUSO := FALSE;
   MAGNETE_4_ESCLUSO := FALSE;
   MAGNETE_5_ESCLUSO := FALSE;
   MAGNETE_6_ESCLUSO := FALSE;
   MAGNETE_LAT_SX_ESCLUSO := FALSE;
   MAGNETE_LAT_DX_ESCLUSO := FALSE;
   COMPENSAZ_TAV_2 := -3.000000e+001;
   STAT22 := W#16#0;
   STAT23 := W#16#0;
   STAT24 := W#16#0;
   STAT25 := W#16#0;
   STAT251 := W#16#0;
   STAT26 := T#0MS;
   STAT29 := T#0MS;
   STAT30 := T#0MS;
   STAT31 := T#0MS;
   C1_Timer := 0.000000e+000;
   C2_Timer := 0.000000e+000;
   C3_Timer := 0.000000e+000;
   C4_Timer := 0.000000e+000;
   C5_Timer := 0.000000e+000;
   C6_Timer := 0.000000e+000;
   C1_Posizione_1 := L#163000;
   C1_Posizione_2 := L#183000;
   C1_Posizione_3 := L#193000;
   C1_Posizione_4 := L#235000;
   C1_Velocita_1 := L#500;
   C1_Velocita_2 := L#200;
   C1_Velocita_3 := L#200;
   C1_Velocita_4 := L#50;
   C1_Accell_1 := L#500;
   C1_Accell_2 := L#500;
   C1_Accell_3 := L#500;
   C1_Accell_4 := L#500;
   word_148 := W#16#0;
   C2_Posizione_1 := L#326000;
   C2_Posizione_2 := L#346000;
   C2_Posizione_3 := L#356000;
   C2_Posizione_4 := L#401000;
   C2_Velocita_1 := L#500;
   C2_Velocita_2 := L#200;
   C2_Velocita_3 := L#200;
   C2_Velocita_4 := L#50;
   C2_Accell_1 := L#500;
   C2_Accell_2 := L#500;
   C2_Accell_3 := L#500;
   C2_Accell_4 := L#500;
   word_198 := W#16#0;
   C3_Posizione_1 := L#200000;
   C3_Posizione_2 := L#220000;
   C3_Posizione_3 := L#230000;
   C3_Posizione_4 := L#385000;
   C3_Velocita_1 := L#500;
   C3_Velocita_2 := L#200;
   C3_Velocita_3 := L#200;
   C3_Velocita_4 := L#50;
   C3_Accell_1 := L#500;
   C3_Accell_2 := L#500;
   C3_Accell_3 := L#500;
   C3_Accell_4 := L#500;
   word_248 := W#16#0;
   C4_Posizione_1 := L#100000;
   C4_Posizione_2 := L#120000;
   C4_Posizione_3 := L#130000;
   C4_Posizione_4 := L#283000;
   C4_Velocita_1 := L#500;
   C4_Velocita_2 := L#200;
   C4_Velocita_3 := L#200;
   C4_Velocita_4 := L#50;
   C4_Accell_1 := L#500;
   C4_Accell_2 := L#500;
   C4_Accell_3 := L#500;
   C4_Accell_4 := L#500;
   word_298 := W#16#0;
   C5_Posizione_1 := L#395000;
   C5_Posizione_2 := L#415000;
   C5_Posizione_3 := L#425000;
   C5_Posizione_4 := L#510000;
   C5_Velocita_1 := L#500;
   C5_Velocita_2 := L#200;
   C5_Velocita_3 := L#200;
   C5_Velocita_4 := L#50;
   C5_Accell_1 := L#500;
   C5_Accell_2 := L#500;
   C5_Accell_3 := L#500;
   C5_Accell_4 := L#500;
   word_348 := W#16#0;
   C6_Posizione_1 := L#430000;
   C6_Posizione_2 := L#450000;
   C6_Posizione_3 := L#460000;
   C6_Posizione_4 := L#525000;
   C6_Velocita_1 := L#500;
   C6_Velocita_2 := L#200;
   C6_Velocita_3 := L#200;
   C6_Velocita_4 := L#50;
   C6_Accell_1 := L#500;
   C6_Accell_2 := L#500;
   C6_Accell_3 := L#500;
   C6_Accell_4 := L#500;
   word_398 := W#16#0;
END_DATA_BLOCK

DATA_BLOCK "MATRICOLA 3"
AUTHOR : Lodato
FAMILY : DESTACK
NAME : DATI
VERSION : 0.1


  STRUCT
   LARGHEZZA_LAMIERA : REAL  := 1.500000e+003;	//LARGHEZZA LAMIERA ATTUALE
   COMPENSAZ_TAV_1 : REAL ;	//COMPENSAZIONE TAVOLA 1
   QUOTA_H_SFOGLIATORE : REAL ;	//Quota impostata altezza sfogliatore
   QUOTA_H_CENTRATORE : REAL ;	//Quota impostata altezza centratore
   word16 : S5TIME ;
   INCLINAZ_TAVOLA_ESCLUSA : BOOL ;	//INCLINAZIONE TAVOLA ESCLUSA
   dword20 : REAL ;
   dword24 : REAL ;
   dword28 : REAL ;
   dword32 : REAL ;
   dword36 : REAL ;
   NR_MATRICOLA : INT  := 1;	//Numero di matricola
   word42 : WORD ;
   MAGNETE_1_ESCLUSO : BOOL ;	//MAGNETE 1 ESCLUSO DA MP270
   MAGNETE_2_ESCLUSO : BOOL ;	//MAGNETE 2 ESCLUSO DA MP270
   MAGNETE_3_ESCLUSO : BOOL ;	//MAGNETE 3 ESCLUSO DA MP270
   MAGNETE_4_ESCLUSO : BOOL ;	//MAGNETE 4 ESCLUSO DA MP270
   MAGNETE_5_ESCLUSO : BOOL ;	//MAGNETE 5 ESCLUSO DA MP270
   MAGNETE_6_ESCLUSO : BOOL ;	//MAGNETE 6 ESCLUSO DA MP270
   MAGNETE_LAT_SX_ESCLUSO : BOOL ;	//MAGNETE LATERALE SX ESCLUSO DA MP270
   MAGNETE_LAT_DX_ESCLUSO : BOOL ;	//MAGNETE LATERALE DX ESCLUSO DA MP270
   COMPENSAZ_TAV_2 : REAL ;	//COMPENSAZIONE TAVOLA 2
   STAT22 : WORD ;
   STAT23 : WORD ;
   STAT24 : WORD ;
   STAT25 : WORD ;
   STAT251 : WORD ;
   STAT26 : TIME ;
   STAT29 : TIME ;
   STAT30 : TIME ;
   STAT31 : TIME ;
   C1_Timer : REAL ;	//Centratore 1: Timer ritardo partenza
   C2_Timer : REAL ;	//Centratore 2: Timer ritardo partenza
   C3_Timer : REAL ;	//Centratore 3: Timer ritardo partenza
   C4_Timer : REAL ;	//Centratore 4: Timer ritardo partenza
   C5_Timer : REAL ;	//Centratore 5: Timer ritardo partenza
   C6_Timer : REAL ;	//Centratore 6: Timer ritardo partenza
   C1_Posizione_1 : DINT  := L#500000;	//Centratore 1: Posizione 1 di avicinamento
   C1_Posizione_2 : DINT  := L#520000;	//Centratore 1: Posizione 2 di cambio velocita'
   C1_Posizione_3 : DINT  := L#530000;	//Centratore 1: Posizione 3 di cambio velocita'
   C1_Posizione_4 : DINT  := L#565400;	//Centratore 1: Posizione 4 di arrivo
   C1_Velocita_1 : DINT  := L#50;	//Centratore 1: Velocita' 1 di avvicinamento
   C1_Velocita_2 : DINT  := L#50;	//Centratore 1: Velocita' 2
   C1_Velocita_3 : DINT  := L#50;	//Centratore 1: Velocita' 3
   C1_Velocita_4 : DINT  := L#50;	//Centratore 1: Velocita' 4 di arrivo
   C1_Accell_1 : DINT  := L#500;	//Centratore 1: Accelerazione 1 di avvicinamento
   C1_Accell_2 : DINT  := L#500;	//Centratore 1: Accelerazione 2
   C1_Accell_3 : DINT  := L#500;	//Centratore 1: Accelerazione 3
   C1_Accell_4 : DINT  := L#500;	//Centratore 1: Accelerazione 4 di arrivo
   word_148 : WORD ;
   C2_Posizione_1 : DINT  := L#500000;	//Centratore 2: Posizione 1 di avicinamento
   C2_Posizione_2 : DINT  := L#520000;	//Centratore 2: Posizione 2 di cambio velocita'
   C2_Posizione_3 : DINT  := L#530000;	//Centratore 2: Posizione 3 di cambio velocita'
   C2_Posizione_4 : DINT  := L#559000;	//Centratore 2: Posizione 4 di arrivo
   C2_Velocita_1 : DINT  := L#50;	//Centratore 2: Velocita' 1 di avvicinamento
   C2_Velocita_2 : DINT  := L#50;	//Centratore 2: Velocita' 2
   C2_Velocita_3 : DINT  := L#50;	//Centratore 2: Velocita' 3
   C2_Velocita_4 : DINT  := L#50;	//Centratore 2: Velocita' 4 di arrivo
   C2_Accell_1 : DINT  := L#500;	//Centratore 2: Accelerazione 1 di avvicinamento
   C2_Accell_2 : DINT  := L#500;	//Centratore 2: Accelerazione 2
   C2_Accell_3 : DINT  := L#500;	//Centratore 2: Accelerazione 3
   C2_Accell_4 : DINT  := L#500;	//Centratore 2: Accelerazione 4 di arrivo
   word_198 : WORD ;
   C3_Posizione_1 : DINT  := L#630000;	//Centratore 3: Posizione 1 di avicinamento
   C3_Posizione_2 : DINT  := L#650000;	//Centratore 3: Posizione 2 di cambio velocita'
   C3_Posizione_3 : DINT  := L#660000;	//Centratore 3: Posizione 3 di cambio velocita'
   C3_Posizione_4 : DINT  := L#698600;	//Centratore 3: Posizione 4 di arrivo
   C3_Velocita_1 : DINT  := L#50;	//Centratore 3: Velocita' 1 di avvicinamento
   C3_Velocita_2 : DINT  := L#50;	//Centratore 3: Velocita' 2
   C3_Velocita_3 : DINT  := L#50;	//Centratore 3: Velocita' 3
   C3_Velocita_4 : DINT  := L#50;	//Centratore 3: Velocita' 4 di arrivo
   C3_Accell_1 : DINT  := L#500;	//Centratore 3: Accelerazione 1 di avvicinamento
   C3_Accell_2 : DINT  := L#500;	//Centratore 3: Accelerazione 2
   C3_Accell_3 : DINT  := L#500;	//Centratore 3: Accelerazione 3
   C3_Accell_4 : DINT  := L#500;	//Centratore 3: Accelerazione 4 di arrivo
   word_248 : WORD ;
   C4_Posizione_1 : DINT  := L#630000;	//Centratore 4: Posizione 1 di avicinamento
   C4_Posizione_2 : DINT  := L#650000;	//Centratore 4: Posizione 2 di cambio velocita'
   C4_Posizione_3 : DINT  := L#660000;	//Centratore 4: Posizione 3 di cambio velocita'
   C4_Posizione_4 : DINT  := L#706200;	//Centratore 4: Posizione 4 di arrivo
   C4_Velocita_1 : DINT  := L#50;	//Centratore 4: Velocita' 1 di avvicinamento
   C4_Velocita_2 : DINT  := L#50;	//Centratore 4: Velocita' 2
   C4_Velocita_3 : DINT  := L#50;	//Centratore 4: Velocita' 3
   C4_Velocita_4 : DINT  := L#50;	//Centratore 4: Velocita' 4 di arrivo
   C4_Accell_1 : DINT  := L#500;	//Centratore 4: Accelerazione 1 di avvicinamento
   C4_Accell_2 : DINT  := L#500;	//Centratore 4: Accelerazione 2
   C4_Accell_3 : DINT  := L#500;	//Centratore 4: Accelerazione 3
   C4_Accell_4 : DINT  := L#500;	//Centratore 4: Accelerazione 4 di arrivo
   word_298 : WORD ;
   C5_Posizione_1 : DINT  := L#1180000;	//Centratore 5: Posizione 1 di avicinamento
   C5_Posizione_2 : DINT  := L#1200000;	//Centratore 5: Posizione 2 di cambio velocita'
   C5_Posizione_3 : DINT  := L#1220000;	//Centratore 5: Posizione 3 di cambio velocita'
   C5_Posizione_4 : DINT  := L#1247000;	//Centratore 5: Posizione 4 di arrivo
   C5_Velocita_1 : DINT  := L#50;	//Centratore 5: Velocita' 1 di avvicinamento
   C5_Velocita_2 : DINT  := L#50;	//Centratore 5: Velocita' 2
   C5_Velocita_3 : DINT  := L#50;	//Centratore 5: Velocita' 3
   C5_Velocita_4 : DINT  := L#50;	//Centratore 5: Velocita' 4 di arrivo
   C5_Accell_1 : DINT  := L#500;	//Centratore 5: Accelerazione 1 di avvicinamento
   C5_Accell_2 : DINT  := L#500;	//Centratore 5: Accelerazione 2
   C5_Accell_3 : DINT  := L#500;	//Centratore 5: Accelerazione 3
   C5_Accell_4 : DINT  := L#500;	//Centratore 5: Accelerazione 4 di arrivo
   word_348 : WORD ;
   C6_Posizione_1 : DINT  := L#1180000;	//Centratore 6: Posizione 1 di avicinamento
   C6_Posizione_2 : DINT  := L#1200000;	//Centratore 6: Posizione 2 di cambio velocita'
   C6_Posizione_3 : DINT  := L#1220000;	//Centratore 6: Posizione 3 di cambio velocita'
   C6_Posizione_4 : DINT  := L#1237400;	//Centratore 6: Posizione 4 di arrivo
   C6_Velocita_1 : DINT  := L#50;	//Centratore 6: Velocita' 1 di avvicinamento
   C6_Velocita_2 : DINT  := L#50;	//Centratore 6: Velocita' 2
   C6_Velocita_3 : DINT  := L#50;	//Centratore 6: Velocita' 3
   C6_Velocita_4 : DINT  := L#50;	//Centratore 6: Velocita' 4 di arrivo
   C6_Accell_1 : DINT  := L#500;	//Centratore 6: Accelerazione 1 di avvicinamento
   C6_Accell_2 : DINT  := L#500;	//Centratore 6: Accelerazione 2
   C6_Accell_3 : DINT  := L#500;	//Centratore 6: Accelerazione 3
   C6_Accell_4 : DINT  := L#500;	//Centratore 6: Accelerazione 4 di arrivo
   word_398 : WORD ;
  END_STRUCT ;
BEGIN
   LARGHEZZA_LAMIERA := 3.060000e+003;
   COMPENSAZ_TAV_1 := -7.000000e+001;
   QUOTA_H_SFOGLIATORE := 2.000000e+003;
   QUOTA_H_CENTRATORE := 1.960000e+003;
   word16 := S5T#0MS;
   INCLINAZ_TAVOLA_ESCLUSA := FALSE;
   dword20 := 0.000000e+000;
   dword24 := 0.000000e+000;
   dword28 := 0.000000e+000;
   dword32 := 0.000000e+000;
   dword36 := 0.000000e+000;
   NR_MATRICOLA := 2;
   word42 := W#16#0;
   MAGNETE_1_ESCLUSO := FALSE;
   MAGNETE_2_ESCLUSO := FALSE;
   MAGNETE_3_ESCLUSO := FALSE;
   MAGNETE_4_ESCLUSO := FALSE;
   MAGNETE_5_ESCLUSO := FALSE;
   MAGNETE_6_ESCLUSO := FALSE;
   MAGNETE_LAT_SX_ESCLUSO := FALSE;
   MAGNETE_LAT_DX_ESCLUSO := FALSE;
   COMPENSAZ_TAV_2 := -3.000000e+001;
   STAT22 := W#16#0;
   STAT23 := W#16#0;
   STAT24 := W#16#0;
   STAT25 := W#16#0;
   STAT251 := W#16#0;
   STAT26 := T#0MS;
   STAT29 := T#0MS;
   STAT30 := T#0MS;
   STAT31 := T#0MS;
   C1_Timer := 0.000000e+000;
   C2_Timer := 0.000000e+000;
   C3_Timer := 0.000000e+000;
   C4_Timer := 0.000000e+000;
   C5_Timer := 0.000000e+000;
   C6_Timer := 0.000000e+000;
   C1_Posizione_1 := L#163000;
   C1_Posizione_2 := L#183000;
   C1_Posizione_3 := L#193000;
   C1_Posizione_4 := L#235000;
   C1_Velocita_1 := L#500;
   C1_Velocita_2 := L#200;
   C1_Velocita_3 := L#200;
   C1_Velocita_4 := L#50;
   C1_Accell_1 := L#500;
   C1_Accell_2 := L#500;
   C1_Accell_3 := L#500;
   C1_Accell_4 := L#500;
   word_148 := W#16#0;
   C2_Posizione_1 := L#326000;
   C2_Posizione_2 := L#346000;
   C2_Posizione_3 := L#356000;
   C2_Posizione_4 := L#401000;
   C2_Velocita_1 := L#500;
   C2_Velocita_2 := L#200;
   C2_Velocita_3 := L#200;
   C2_Velocita_4 := L#50;
   C2_Accell_1 := L#500;
   C2_Accell_2 := L#500;
   C2_Accell_3 := L#500;
   C2_Accell_4 := L#500;
   word_198 := W#16#0;
   C3_Posizione_1 := L#200000;
   C3_Posizione_2 := L#220000;
   C3_Posizione_3 := L#230000;
   C3_Posizione_4 := L#385000;
   C3_Velocita_1 := L#500;
   C3_Velocita_2 := L#200;
   C3_Velocita_3 := L#200;
   C3_Velocita_4 := L#50;
   C3_Accell_1 := L#500;
   C3_Accell_2 := L#500;
   C3_Accell_3 := L#500;
   C3_Accell_4 := L#500;
   word_248 := W#16#0;
   C4_Posizione_1 := L#100000;
   C4_Posizione_2 := L#120000;
   C4_Posizione_3 := L#130000;
   C4_Posizione_4 := L#283000;
   C4_Velocita_1 := L#500;
   C4_Velocita_2 := L#200;
   C4_Velocita_3 := L#200;
   C4_Velocita_4 := L#50;
   C4_Accell_1 := L#500;
   C4_Accell_2 := L#500;
   C4_Accell_3 := L#500;
   C4_Accell_4 := L#500;
   word_298 := W#16#0;
   C5_Posizione_1 := L#395000;
   C5_Posizione_2 := L#415000;
   C5_Posizione_3 := L#425000;
   C5_Posizione_4 := L#510000;
   C5_Velocita_1 := L#500;
   C5_Velocita_2 := L#200;
   C5_Velocita_3 := L#200;
   C5_Velocita_4 := L#50;
   C5_Accell_1 := L#500;
   C5_Accell_2 := L#500;
   C5_Accell_3 := L#500;
   C5_Accell_4 := L#500;
   word_348 := W#16#0;
   C6_Posizione_1 := L#430000;
   C6_Posizione_2 := L#450000;
   C6_Posizione_3 := L#460000;
   C6_Posizione_4 := L#525000;
   C6_Velocita_1 := L#500;
   C6_Velocita_2 := L#200;
   C6_Velocita_3 := L#200;
   C6_Velocita_4 := L#50;
   C6_Accell_1 := L#500;
   C6_Accell_2 := L#500;
   C6_Accell_3 := L#500;
   C6_Accell_4 := L#500;
   word_398 := W#16#0;
END_DATA_BLOCK

DATA_BLOCK "MATRICOLA 4"
AUTHOR : Lodato
FAMILY : DESTACK
NAME : DATI
VERSION : 0.1


  STRUCT
   LARGHEZZA_LAMIERA : REAL  := 1.500000e+003;	//LARGHEZZA LAMIERA ATTUALE
   COMPENSAZ_TAV_1 : REAL ;	//COMPENSAZIONE TAVOLA 1
   QUOTA_H_SFOGLIATORE : REAL ;	//Quota impostata altezza sfogliatore
   QUOTA_H_CENTRATORE : REAL ;	//Quota impostata altezza centratore
   word16 : S5TIME ;
   INCLINAZ_TAVOLA_ESCLUSA : BOOL ;	//INCLINAZIONE TAVOLA ESCLUSA
   dword20 : REAL ;
   dword24 : REAL ;
   dword28 : REAL ;
   dword32 : REAL ;
   dword36 : REAL ;
   NR_MATRICOLA : INT  := 1;	//Numero di matricola
   word42 : WORD ;
   MAGNETE_1_ESCLUSO : BOOL ;	//MAGNETE 1 ESCLUSO DA MP270
   MAGNETE_2_ESCLUSO : BOOL ;	//MAGNETE 2 ESCLUSO DA MP270
   MAGNETE_3_ESCLUSO : BOOL ;	//MAGNETE 3 ESCLUSO DA MP270
   MAGNETE_4_ESCLUSO : BOOL ;	//MAGNETE 4 ESCLUSO DA MP270
   MAGNETE_5_ESCLUSO : BOOL ;	//MAGNETE 5 ESCLUSO DA MP270
   MAGNETE_6_ESCLUSO : BOOL ;	//MAGNETE 6 ESCLUSO DA MP270
   MAGNETE_LAT_SX_ESCLUSO : BOOL ;	//MAGNETE LATERALE SX ESCLUSO DA MP270
   MAGNETE_LAT_DX_ESCLUSO : BOOL ;	//MAGNETE LATERALE DX ESCLUSO DA MP270
   COMPENSAZ_TAV_2 : REAL ;	//COMPENSAZIONE TAVOLA 2
   STAT22 : WORD ;
   STAT23 : WORD ;
   STAT24 : WORD ;
   STAT25 : WORD ;
   STAT251 : WORD ;
   STAT26 : TIME ;
   STAT29 : TIME ;
   STAT30 : TIME ;
   STAT31 : TIME ;
   C1_Timer : REAL ;	//Centratore 1: Timer ritardo partenza
   C2_Timer : REAL ;	//Centratore 2: Timer ritardo partenza
   C3_Timer : REAL ;	//Centratore 3: Timer ritardo partenza
   C4_Timer : REAL ;	//Centratore 4: Timer ritardo partenza
   C5_Timer : REAL ;	//Centratore 5: Timer ritardo partenza
   C6_Timer : REAL ;	//Centratore 6: Timer ritardo partenza
   C1_Posizione_1 : DINT  := L#500000;	//Centratore 1: Posizione 1 di avicinamento
   C1_Posizione_2 : DINT  := L#520000;	//Centratore 1: Posizione 2 di cambio velocita'
   C1_Posizione_3 : DINT  := L#530000;	//Centratore 1: Posizione 3 di cambio velocita'
   C1_Posizione_4 : DINT  := L#565400;	//Centratore 1: Posizione 4 di arrivo
   C1_Velocita_1 : DINT  := L#50;	//Centratore 1: Velocita' 1 di avvicinamento
   C1_Velocita_2 : DINT  := L#50;	//Centratore 1: Velocita' 2
   C1_Velocita_3 : DINT  := L#50;	//Centratore 1: Velocita' 3
   C1_Velocita_4 : DINT  := L#50;	//Centratore 1: Velocita' 4 di arrivo
   C1_Accell_1 : DINT  := L#500;	//Centratore 1: Accelerazione 1 di avvicinamento
   C1_Accell_2 : DINT  := L#500;	//Centratore 1: Accelerazione 2
   C1_Accell_3 : DINT  := L#500;	//Centratore 1: Accelerazione 3
   C1_Accell_4 : DINT  := L#500;	//Centratore 1: Accelerazione 4 di arrivo
   word_148 : WORD ;
   C2_Posizione_1 : DINT  := L#500000;	//Centratore 2: Posizione 1 di avicinamento
   C2_Posizione_2 : DINT  := L#520000;	//Centratore 2: Posizione 2 di cambio velocita'
   C2_Posizione_3 : DINT  := L#530000;	//Centratore 2: Posizione 3 di cambio velocita'
   C2_Posizione_4 : DINT  := L#559000;	//Centratore 2: Posizione 4 di arrivo
   C2_Velocita_1 : DINT  := L#50;	//Centratore 2: Velocita' 1 di avvicinamento
   C2_Velocita_2 : DINT  := L#50;	//Centratore 2: Velocita' 2
   C2_Velocita_3 : DINT  := L#50;	//Centratore 2: Velocita' 3
   C2_Velocita_4 : DINT  := L#50;	//Centratore 2: Velocita' 4 di arrivo
   C2_Accell_1 : DINT  := L#500;	//Centratore 2: Accelerazione 1 di avvicinamento
   C2_Accell_2 : DINT  := L#500;	//Centratore 2: Accelerazione 2
   C2_Accell_3 : DINT  := L#500;	//Centratore 2: Accelerazione 3
   C2_Accell_4 : DINT  := L#500;	//Centratore 2: Accelerazione 4 di arrivo
   word_198 : WORD ;
   C3_Posizione_1 : DINT  := L#630000;	//Centratore 3: Posizione 1 di avicinamento
   C3_Posizione_2 : DINT  := L#650000;	//Centratore 3: Posizione 2 di cambio velocita'
   C3_Posizione_3 : DINT  := L#660000;	//Centratore 3: Posizione 3 di cambio velocita'
   C3_Posizione_4 : DINT  := L#698600;	//Centratore 3: Posizione 4 di arrivo
   C3_Velocita_1 : DINT  := L#50;	//Centratore 3: Velocita' 1 di avvicinamento
   C3_Velocita_2 : DINT  := L#50;	//Centratore 3: Velocita' 2
   C3_Velocita_3 : DINT  := L#50;	//Centratore 3: Velocita' 3
   C3_Velocita_4 : DINT  := L#50;	//Centratore 3: Velocita' 4 di arrivo
   C3_Accell_1 : DINT  := L#500;	//Centratore 3: Accelerazione 1 di avvicinamento
   C3_Accell_2 : DINT  := L#500;	//Centratore 3: Accelerazione 2
   C3_Accell_3 : DINT  := L#500;	//Centratore 3: Accelerazione 3
   C3_Accell_4 : DINT  := L#500;	//Centratore 3: Accelerazione 4 di arrivo
   word_248 : WORD ;
   C4_Posizione_1 : DINT  := L#630000;	//Centratore 4: Posizione 1 di avicinamento
   C4_Posizione_2 : DINT  := L#650000;	//Centratore 4: Posizione 2 di cambio velocita'
   C4_Posizione_3 : DINT  := L#660000;	//Centratore 4: Posizione 3 di cambio velocita'
   C4_Posizione_4 : DINT  := L#706200;	//Centratore 4: Posizione 4 di arrivo
   C4_Velocita_1 : DINT  := L#50;	//Centratore 4: Velocita' 1 di avvicinamento
   C4_Velocita_2 : DINT  := L#50;	//Centratore 4: Velocita' 2
   C4_Velocita_3 : DINT  := L#50;	//Centratore 4: Velocita' 3
   C4_Velocita_4 : DINT  := L#50;	//Centratore 4: Velocita' 4 di arrivo
   C4_Accell_1 : DINT  := L#500;	//Centratore 4: Accelerazione 1 di avvicinamento
   C4_Accell_2 : DINT  := L#500;	//Centratore 4: Accelerazione 2
   C4_Accell_3 : DINT  := L#500;	//Centratore 4: Accelerazione 3
   C4_Accell_4 : DINT  := L#500;	//Centratore 4: Accelerazione 4 di arrivo
   word_298 : WORD ;
   C5_Posizione_1 : DINT  := L#1180000;	//Centratore 5: Posizione 1 di avicinamento
   C5_Posizione_2 : DINT  := L#1200000;	//Centratore 5: Posizione 2 di cambio velocita'
   C5_Posizione_3 : DINT  := L#1220000;	//Centratore 5: Posizione 3 di cambio velocita'
   C5_Posizione_4 : DINT  := L#1247000;	//Centratore 5: Posizione 4 di arrivo
   C5_Velocita_1 : DINT  := L#50;	//Centratore 5: Velocita' 1 di avvicinamento
   C5_Velocita_2 : DINT  := L#50;	//Centratore 5: Velocita' 2
   C5_Velocita_3 : DINT  := L#50;	//Centratore 5: Velocita' 3
   C5_Velocita_4 : DINT  := L#50;	//Centratore 5: Velocita' 4 di arrivo
   C5_Accell_1 : DINT  := L#500;	//Centratore 5: Accelerazione 1 di avvicinamento
   C5_Accell_2 : DINT  := L#500;	//Centratore 5: Accelerazione 2
   C5_Accell_3 : DINT  := L#500;	//Centratore 5: Accelerazione 3
   C5_Accell_4 : DINT  := L#500;	//Centratore 5: Accelerazione 4 di arrivo
   word_348 : WORD ;
   C6_Posizione_1 : DINT  := L#1180000;	//Centratore 6: Posizione 1 di avicinamento
   C6_Posizione_2 : DINT  := L#1200000;	//Centratore 6: Posizione 2 di cambio velocita'
   C6_Posizione_3 : DINT  := L#1220000;	//Centratore 6: Posizione 3 di cambio velocita'
   C6_Posizione_4 : DINT  := L#1237400;	//Centratore 6: Posizione 4 di arrivo
   C6_Velocita_1 : DINT  := L#50;	//Centratore 6: Velocita' 1 di avvicinamento
   C6_Velocita_2 : DINT  := L#50;	//Centratore 6: Velocita' 2
   C6_Velocita_3 : DINT  := L#50;	//Centratore 6: Velocita' 3
   C6_Velocita_4 : DINT  := L#50;	//Centratore 6: Velocita' 4 di arrivo
   C6_Accell_1 : DINT  := L#500;	//Centratore 6: Accelerazione 1 di avvicinamento
   C6_Accell_2 : DINT  := L#500;	//Centratore 6: Accelerazione 2
   C6_Accell_3 : DINT  := L#500;	//Centratore 6: Accelerazione 3
   C6_Accell_4 : DINT  := L#500;	//Centratore 6: Accelerazione 4 di arrivo
   word_398 : WORD ;
  END_STRUCT ;
BEGIN
   LARGHEZZA_LAMIERA := 1.600000e+003;
   COMPENSAZ_TAV_1 := -3.000000e+001;
   QUOTA_H_SFOGLIATORE := 1.630000e+003;
   QUOTA_H_CENTRATORE := 1.630000e+003;
   word16 := S5T#0MS;
   INCLINAZ_TAVOLA_ESCLUSA := TRUE;
   dword20 := 0.000000e+000;
   dword24 := 0.000000e+000;
   dword28 := 0.000000e+000;
   dword32 := 0.000000e+000;
   dword36 := 0.000000e+000;
   NR_MATRICOLA := 1;
   word42 := W#16#0;
   MAGNETE_1_ESCLUSO := TRUE;
   MAGNETE_2_ESCLUSO := FALSE;
   MAGNETE_3_ESCLUSO := FALSE;
   MAGNETE_4_ESCLUSO := FALSE;
   MAGNETE_5_ESCLUSO := FALSE;
   MAGNETE_6_ESCLUSO := TRUE;
   MAGNETE_LAT_SX_ESCLUSO := TRUE;
   MAGNETE_LAT_DX_ESCLUSO := TRUE;
   COMPENSAZ_TAV_2 := -3.000000e+001;
   STAT22 := W#16#0;
   STAT23 := W#16#0;
   STAT24 := W#16#0;
   STAT25 := W#16#0;
   STAT251 := W#16#0;
   STAT26 := T#0MS;
   STAT29 := T#0MS;
   STAT30 := T#0MS;
   STAT31 := T#0MS;
   C1_Timer := 0.000000e+000;
   C2_Timer := 0.000000e+000;
   C3_Timer := 0.000000e+000;
   C4_Timer := 0.000000e+000;
   C5_Timer := 0.000000e+000;
   C6_Timer := 0.000000e+000;
   C1_Posizione_1 := L#500000;
   C1_Posizione_2 := L#520000;
   C1_Posizione_3 := L#530000;
   C1_Posizione_4 := L#565400;
   C1_Velocita_1 := L#500;
   C1_Velocita_2 := L#200;
   C1_Velocita_3 := L#200;
   C1_Velocita_4 := L#50;
   C1_Accell_1 := L#500;
   C1_Accell_2 := L#500;
   C1_Accell_3 := L#500;
   C1_Accell_4 := L#500;
   word_148 := W#16#0;
   C2_Posizione_1 := L#500000;
   C2_Posizione_2 := L#520000;
   C2_Posizione_3 := L#530000;
   C2_Posizione_4 := L#559000;
   C2_Velocita_1 := L#500;
   C2_Velocita_2 := L#200;
   C2_Velocita_3 := L#200;
   C2_Velocita_4 := L#50;
   C2_Accell_1 := L#500;
   C2_Accell_2 := L#500;
   C2_Accell_3 := L#500;
   C2_Accell_4 := L#500;
   word_198 := W#16#0;
   C3_Posizione_1 := L#630000;
   C3_Posizione_2 := L#650000;
   C3_Posizione_3 := L#660000;
   C3_Posizione_4 := L#698600;
   C3_Velocita_1 := L#500;
   C3_Velocita_2 := L#200;
   C3_Velocita_3 := L#200;
   C3_Velocita_4 := L#50;
   C3_Accell_1 := L#500;
   C3_Accell_2 := L#500;
   C3_Accell_3 := L#500;
   C3_Accell_4 := L#500;
   word_248 := W#16#0;
   C4_Posizione_1 := L#630000;
   C4_Posizione_2 := L#650000;
   C4_Posizione_3 := L#660000;
   C4_Posizione_4 := L#706200;
   C4_Velocita_1 := L#500;
   C4_Velocita_2 := L#200;
   C4_Velocita_3 := L#200;
   C4_Velocita_4 := L#50;
   C4_Accell_1 := L#500;
   C4_Accell_2 := L#500;
   C4_Accell_3 := L#500;
   C4_Accell_4 := L#500;
   word_298 := W#16#0;
   C5_Posizione_1 := L#1180000;
   C5_Posizione_2 := L#1200000;
   C5_Posizione_3 := L#1210000;
   C5_Posizione_4 := L#1247000;
   C5_Velocita_1 := L#500;
   C5_Velocita_2 := L#200;
   C5_Velocita_3 := L#200;
   C5_Velocita_4 := L#50;
   C5_Accell_1 := L#500;
   C5_Accell_2 := L#500;
   C5_Accell_3 := L#500;
   C5_Accell_4 := L#500;
   word_348 := W#16#0;
   C6_Posizione_1 := L#1180000;
   C6_Posizione_2 := L#1200000;
   C6_Posizione_3 := L#1210000;
   C6_Posizione_4 := L#1237400;
   C6_Velocita_1 := L#500;
   C6_Velocita_2 := L#200;
   C6_Velocita_3 := L#200;
   C6_Velocita_4 := L#50;
   C6_Accell_1 := L#500;
   C6_Accell_2 := L#500;
   C6_Accell_3 := L#500;
   C6_Accell_4 := L#500;
   word_398 := W#16#0;
END_DATA_BLOCK

DATA_BLOCK "MATRICOLA 5"
AUTHOR : Lodato
FAMILY : DESTACK
NAME : DATI
VERSION : 0.1


  STRUCT
   LARGHEZZA_LAMIERA : REAL  := 1.500000e+003;	//LARGHEZZA LAMIERA ATTUALE
   COMPENSAZ_TAV_1 : REAL ;	//COMPENSAZIONE TAVOLA 1
   QUOTA_H_SFOGLIATORE : REAL ;	//Quota impostata altezza sfogliatore
   QUOTA_H_CENTRATORE : REAL ;	//Quota impostata altezza centratore
   word16 : S5TIME ;
   INCLINAZ_TAVOLA_ESCLUSA : BOOL ;	//INCLINAZIONE TAVOLA ESCLUSA
   dword20 : REAL ;
   dword24 : REAL ;
   dword28 : REAL ;
   dword32 : REAL ;
   dword36 : REAL ;
   NR_MATRICOLA : INT  := 1;	//Numero di matricola
   word42 : WORD ;
   MAGNETE_1_ESCLUSO : BOOL ;	//MAGNETE 1 ESCLUSO DA MP270
   MAGNETE_2_ESCLUSO : BOOL ;	//MAGNETE 2 ESCLUSO DA MP270
   MAGNETE_3_ESCLUSO : BOOL ;	//MAGNETE 3 ESCLUSO DA MP270
   MAGNETE_4_ESCLUSO : BOOL ;	//MAGNETE 4 ESCLUSO DA MP270
   MAGNETE_5_ESCLUSO : BOOL ;	//MAGNETE 5 ESCLUSO DA MP270
   MAGNETE_6_ESCLUSO : BOOL ;	//MAGNETE 6 ESCLUSO DA MP270
   MAGNETE_LAT_SX_ESCLUSO : BOOL ;	//MAGNETE LATERALE SX ESCLUSO DA MP270
   MAGNETE_LAT_DX_ESCLUSO : BOOL ;	//MAGNETE LATERALE DX ESCLUSO DA MP270
   COMPENSAZ_TAV_2 : REAL ;	//COMPENSAZIONE TAVOLA 2
   STAT22 : WORD ;
   STAT23 : WORD ;
   STAT24 : WORD ;
   STAT25 : WORD ;
   STAT251 : WORD ;
   STAT26 : TIME ;
   STAT29 : TIME ;
   STAT30 : TIME ;
   STAT31 : TIME ;
   C1_Timer : REAL ;	//Centratore 1: Timer ritardo partenza
   C2_Timer : REAL ;	//Centratore 2: Timer ritardo partenza
   C3_Timer : REAL ;	//Centratore 3: Timer ritardo partenza
   C4_Timer : REAL ;	//Centratore 4: Timer ritardo partenza
   C5_Timer : REAL ;	//Centratore 5: Timer ritardo partenza
   C6_Timer : REAL ;	//Centratore 6: Timer ritardo partenza
   C1_Posizione_1 : DINT  := L#500000;	//Centratore 1: Posizione 1 di avicinamento
   C1_Posizione_2 : DINT  := L#520000;	//Centratore 1: Posizione 2 di cambio velocita'
   C1_Posizione_3 : DINT  := L#530000;	//Centratore 1: Posizione 3 di cambio velocita'
   C1_Posizione_4 : DINT  := L#565400;	//Centratore 1: Posizione 4 di arrivo
   C1_Velocita_1 : DINT  := L#50;	//Centratore 1: Velocita' 1 di avvicinamento
   C1_Velocita_2 : DINT  := L#50;	//Centratore 1: Velocita' 2
   C1_Velocita_3 : DINT  := L#50;	//Centratore 1: Velocita' 3
   C1_Velocita_4 : DINT  := L#50;	//Centratore 1: Velocita' 4 di arrivo
   C1_Accell_1 : DINT  := L#500;	//Centratore 1: Accelerazione 1 di avvicinamento
   C1_Accell_2 : DINT  := L#500;	//Centratore 1: Accelerazione 2
   C1_Accell_3 : DINT  := L#500;	//Centratore 1: Accelerazione 3
   C1_Accell_4 : DINT  := L#500;	//Centratore 1: Accelerazione 4 di arrivo
   word_148 : WORD ;
   C2_Posizione_1 : DINT  := L#500000;	//Centratore 2: Posizione 1 di avicinamento
   C2_Posizione_2 : DINT  := L#520000;	//Centratore 2: Posizione 2 di cambio velocita'
   C2_Posizione_3 : DINT  := L#530000;	//Centratore 2: Posizione 3 di cambio velocita'
   C2_Posizione_4 : DINT  := L#559000;	//Centratore 2: Posizione 4 di arrivo
   C2_Velocita_1 : DINT  := L#50;	//Centratore 2: Velocita' 1 di avvicinamento
   C2_Velocita_2 : DINT  := L#50;	//Centratore 2: Velocita' 2
   C2_Velocita_3 : DINT  := L#50;	//Centratore 2: Velocita' 3
   C2_Velocita_4 : DINT  := L#50;	//Centratore 2: Velocita' 4 di arrivo
   C2_Accell_1 : DINT  := L#500;	//Centratore 2: Accelerazione 1 di avvicinamento
   C2_Accell_2 : DINT  := L#500;	//Centratore 2: Accelerazione 2
   C2_Accell_3 : DINT  := L#500;	//Centratore 2: Accelerazione 3
   C2_Accell_4 : DINT  := L#500;	//Centratore 2: Accelerazione 4 di arrivo
   word_198 : WORD ;
   C3_Posizione_1 : DINT  := L#630000;	//Centratore 3: Posizione 1 di avicinamento
   C3_Posizione_2 : DINT  := L#650000;	//Centratore 3: Posizione 2 di cambio velocita'
   C3_Posizione_3 : DINT  := L#660000;	//Centratore 3: Posizione 3 di cambio velocita'
   C3_Posizione_4 : DINT  := L#698600;	//Centratore 3: Posizione 4 di arrivo
   C3_Velocita_1 : DINT  := L#50;	//Centratore 3: Velocita' 1 di avvicinamento
   C3_Velocita_2 : DINT  := L#50;	//Centratore 3: Velocita' 2
   C3_Velocita_3 : DINT  := L#50;	//Centratore 3: Velocita' 3
   C3_Velocita_4 : DINT  := L#50;	//Centratore 3: Velocita' 4 di arrivo
   C3_Accell_1 : DINT  := L#500;	//Centratore 3: Accelerazione 1 di avvicinamento
   C3_Accell_2 : DINT  := L#500;	//Centratore 3: Accelerazione 2
   C3_Accell_3 : DINT  := L#500;	//Centratore 3: Accelerazione 3
   C3_Accell_4 : DINT  := L#500;	//Centratore 3: Accelerazione 4 di arrivo
   word_248 : WORD ;
   C4_Posizione_1 : DINT  := L#630000;	//Centratore 4: Posizione 1 di avicinamento
   C4_Posizione_2 : DINT  := L#650000;	//Centratore 4: Posizione 2 di cambio velocita'
   C4_Posizione_3 : DINT  := L#660000;	//Centratore 4: Posizione 3 di cambio velocita'
   C4_Posizione_4 : DINT  := L#706200;	//Centratore 4: Posizione 4 di arrivo
   C4_Velocita_1 : DINT  := L#50;	//Centratore 4: Velocita' 1 di avvicinamento
   C4_Velocita_2 : DINT  := L#50;	//Centratore 4: Velocita' 2
   C4_Velocita_3 : DINT  := L#50;	//Centratore 4: Velocita' 3
   C4_Velocita_4 : DINT  := L#50;	//Centratore 4: Velocita' 4 di arrivo
   C4_Accell_1 : DINT  := L#500;	//Centratore 4: Accelerazione 1 di avvicinamento
   C4_Accell_2 : DINT  := L#500;	//Centratore 4: Accelerazione 2
   C4_Accell_3 : DINT  := L#500;	//Centratore 4: Accelerazione 3
   C4_Accell_4 : DINT  := L#500;	//Centratore 4: Accelerazione 4 di arrivo
   word_298 : WORD ;
   C5_Posizione_1 : DINT  := L#1180000;	//Centratore 5: Posizione 1 di avicinamento
   C5_Posizione_2 : DINT  := L#1200000;	//Centratore 5: Posizione 2 di cambio velocita'
   C5_Posizione_3 : DINT  := L#1220000;	//Centratore 5: Posizione 3 di cambio velocita'
   C5_Posizione_4 : DINT  := L#1247000;	//Centratore 5: Posizione 4 di arrivo
   C5_Velocita_1 : DINT  := L#50;	//Centratore 5: Velocita' 1 di avvicinamento
   C5_Velocita_2 : DINT  := L#50;	//Centratore 5: Velocita' 2
   C5_Velocita_3 : DINT  := L#50;	//Centratore 5: Velocita' 3
   C5_Velocita_4 : DINT  := L#50;	//Centratore 5: Velocita' 4 di arrivo
   C5_Accell_1 : DINT  := L#500;	//Centratore 5: Accelerazione 1 di avvicinamento
   C5_Accell_2 : DINT  := L#500;	//Centratore 5: Accelerazione 2
   C5_Accell_3 : DINT  := L#500;	//Centratore 5: Accelerazione 3
   C5_Accell_4 : DINT  := L#500;	//Centratore 5: Accelerazione 4 di arrivo
   word_348 : WORD ;
   C6_Posizione_1 : DINT  := L#1180000;	//Centratore 6: Posizione 1 di avicinamento
   C6_Posizione_2 : DINT  := L#1200000;	//Centratore 6: Posizione 2 di cambio velocita'
   C6_Posizione_3 : DINT  := L#1220000;	//Centratore 6: Posizione 3 di cambio velocita'
   C6_Posizione_4 : DINT  := L#1237400;	//Centratore 6: Posizione 4 di arrivo
   C6_Velocita_1 : DINT  := L#50;	//Centratore 6: Velocita' 1 di avvicinamento
   C6_Velocita_2 : DINT  := L#50;	//Centratore 6: Velocita' 2
   C6_Velocita_3 : DINT  := L#50;	//Centratore 6: Velocita' 3
   C6_Velocita_4 : DINT  := L#50;	//Centratore 6: Velocita' 4 di arrivo
   C6_Accell_1 : DINT  := L#500;	//Centratore 6: Accelerazione 1 di avvicinamento
   C6_Accell_2 : DINT  := L#500;	//Centratore 6: Accelerazione 2
   C6_Accell_3 : DINT  := L#500;	//Centratore 6: Accelerazione 3
   C6_Accell_4 : DINT  := L#500;	//Centratore 6: Accelerazione 4 di arrivo
   word_398 : WORD ;
  END_STRUCT ;
BEGIN
   LARGHEZZA_LAMIERA := 3.060000e+003;
   COMPENSAZ_TAV_1 := -7.000000e+001;
   QUOTA_H_SFOGLIATORE := 2.000000e+003;
   QUOTA_H_CENTRATORE := 1.960000e+003;
   word16 := S5T#0MS;
   INCLINAZ_TAVOLA_ESCLUSA := FALSE;
   dword20 := 0.000000e+000;
   dword24 := 0.000000e+000;
   dword28 := 0.000000e+000;
   dword32 := 0.000000e+000;
   dword36 := 0.000000e+000;
   NR_MATRICOLA := 2;
   word42 := W#16#0;
   MAGNETE_1_ESCLUSO := FALSE;
   MAGNETE_2_ESCLUSO := FALSE;
   MAGNETE_3_ESCLUSO := FALSE;
   MAGNETE_4_ESCLUSO := FALSE;
   MAGNETE_5_ESCLUSO := FALSE;
   MAGNETE_6_ESCLUSO := FALSE;
   MAGNETE_LAT_SX_ESCLUSO := FALSE;
   MAGNETE_LAT_DX_ESCLUSO := FALSE;
   COMPENSAZ_TAV_2 := -3.000000e+001;
   STAT22 := W#16#0;
   STAT23 := W#16#0;
   STAT24 := W#16#0;
   STAT25 := W#16#0;
   STAT251 := W#16#0;
   STAT26 := T#0MS;
   STAT29 := T#0MS;
   STAT30 := T#0MS;
   STAT31 := T#0MS;
   C1_Timer := 0.000000e+000;
   C2_Timer := 0.000000e+000;
   C3_Timer := 0.000000e+000;
   C4_Timer := 0.000000e+000;
   C5_Timer := 0.000000e+000;
   C6_Timer := 0.000000e+000;
   C1_Posizione_1 := L#163000;
   C1_Posizione_2 := L#183000;
   C1_Posizione_3 := L#193000;
   C1_Posizione_4 := L#235000;
   C1_Velocita_1 := L#500;
   C1_Velocita_2 := L#200;
   C1_Velocita_3 := L#200;
   C1_Velocita_4 := L#50;
   C1_Accell_1 := L#500;
   C1_Accell_2 := L#500;
   C1_Accell_3 := L#500;
   C1_Accell_4 := L#500;
   word_148 := W#16#0;
   C2_Posizione_1 := L#326000;
   C2_Posizione_2 := L#346000;
   C2_Posizione_3 := L#356000;
   C2_Posizione_4 := L#401000;
   C2_Velocita_1 := L#500;
   C2_Velocita_2 := L#200;
   C2_Velocita_3 := L#200;
   C2_Velocita_4 := L#50;
   C2_Accell_1 := L#500;
   C2_Accell_2 := L#500;
   C2_Accell_3 := L#500;
   C2_Accell_4 := L#500;
   word_198 := W#16#0;
   C3_Posizione_1 := L#200000;
   C3_Posizione_2 := L#220000;
   C3_Posizione_3 := L#230000;
   C3_Posizione_4 := L#385000;
   C3_Velocita_1 := L#500;
   C3_Velocita_2 := L#200;
   C3_Velocita_3 := L#200;
   C3_Velocita_4 := L#50;
   C3_Accell_1 := L#500;
   C3_Accell_2 := L#500;
   C3_Accell_3 := L#500;
   C3_Accell_4 := L#500;
   word_248 := W#16#0;
   C4_Posizione_1 := L#100000;
   C4_Posizione_2 := L#120000;
   C4_Posizione_3 := L#130000;
   C4_Posizione_4 := L#283000;
   C4_Velocita_1 := L#500;
   C4_Velocita_2 := L#200;
   C4_Velocita_3 := L#200;
   C4_Velocita_4 := L#50;
   C4_Accell_1 := L#500;
   C4_Accell_2 := L#500;
   C4_Accell_3 := L#500;
   C4_Accell_4 := L#500;
   word_298 := W#16#0;
   C5_Posizione_1 := L#395000;
   C5_Posizione_2 := L#415000;
   C5_Posizione_3 := L#425000;
   C5_Posizione_4 := L#510000;
   C5_Velocita_1 := L#500;
   C5_Velocita_2 := L#200;
   C5_Velocita_3 := L#200;
   C5_Velocita_4 := L#50;
   C5_Accell_1 := L#500;
   C5_Accell_2 := L#500;
   C5_Accell_3 := L#500;
   C5_Accell_4 := L#500;
   word_348 := W#16#0;
   C6_Posizione_1 := L#430000;
   C6_Posizione_2 := L#450000;
   C6_Posizione_3 := L#460000;
   C6_Posizione_4 := L#525000;
   C6_Velocita_1 := L#500;
   C6_Velocita_2 := L#200;
   C6_Velocita_3 := L#200;
   C6_Velocita_4 := L#50;
   C6_Accell_1 := L#500;
   C6_Accell_2 := L#500;
   C6_Accell_3 := L#500;
   C6_Accell_4 := L#500;
   word_398 := W#16#0;
END_DATA_BLOCK

DATA_BLOCK "MATRICOLA 6"
AUTHOR : Lodato
FAMILY : DESTACK
NAME : DATI
VERSION : 0.1


  STRUCT
   LARGHEZZA_LAMIERA : REAL  := 1.500000e+003;	//LARGHEZZA LAMIERA ATTUALE
   COMPENSAZ_TAV_1 : REAL ;	//COMPENSAZIONE TAVOLA 1
   QUOTA_H_SFOGLIATORE : REAL ;	//Quota impostata altezza sfogliatore
   QUOTA_H_CENTRATORE : REAL ;	//Quota impostata altezza centratore
   word16 : S5TIME ;
   INCLINAZ_TAVOLA_ESCLUSA : BOOL ;	//INCLINAZIONE TAVOLA ESCLUSA
   dword20 : REAL ;
   dword24 : REAL ;
   dword28 : REAL ;
   dword32 : REAL ;
   dword36 : REAL ;
   NR_MATRICOLA : INT  := 1;	//Numero di matricola
   word42 : WORD ;
   MAGNETE_1_ESCLUSO : BOOL ;	//MAGNETE 1 ESCLUSO DA MP270
   MAGNETE_2_ESCLUSO : BOOL ;	//MAGNETE 2 ESCLUSO DA MP270
   MAGNETE_3_ESCLUSO : BOOL ;	//MAGNETE 3 ESCLUSO DA MP270
   MAGNETE_4_ESCLUSO : BOOL ;	//MAGNETE 4 ESCLUSO DA MP270
   MAGNETE_5_ESCLUSO : BOOL ;	//MAGNETE 5 ESCLUSO DA MP270
   MAGNETE_6_ESCLUSO : BOOL ;	//MAGNETE 6 ESCLUSO DA MP270
   MAGNETE_LAT_SX_ESCLUSO : BOOL ;	//MAGNETE LATERALE SX ESCLUSO DA MP270
   MAGNETE_LAT_DX_ESCLUSO : BOOL ;	//MAGNETE LATERALE DX ESCLUSO DA MP270
   COMPENSAZ_TAV_2 : REAL ;	//COMPENSAZIONE TAVOLA 2
   STAT22 : WORD ;
   STAT23 : WORD ;
   STAT24 : WORD ;
   STAT25 : WORD ;
   STAT251 : WORD ;
   STAT26 : TIME ;
   STAT29 : TIME ;
   STAT30 : TIME ;
   STAT31 : TIME ;
   C1_Timer : REAL ;	//Centratore 1: Timer ritardo partenza
   C2_Timer : REAL ;	//Centratore 2: Timer ritardo partenza
   C3_Timer : REAL ;	//Centratore 3: Timer ritardo partenza
   C4_Timer : REAL ;	//Centratore 4: Timer ritardo partenza
   C5_Timer : REAL ;	//Centratore 5: Timer ritardo partenza
   C6_Timer : REAL ;	//Centratore 6: Timer ritardo partenza
   C1_Posizione_1 : DINT  := L#500000;	//Centratore 1: Posizione 1 di avicinamento
   C1_Posizione_2 : DINT  := L#520000;	//Centratore 1: Posizione 2 di cambio velocita'
   C1_Posizione_3 : DINT  := L#530000;	//Centratore 1: Posizione 3 di cambio velocita'
   C1_Posizione_4 : DINT  := L#565400;	//Centratore 1: Posizione 4 di arrivo
   C1_Velocita_1 : DINT  := L#50;	//Centratore 1: Velocita' 1 di avvicinamento
   C1_Velocita_2 : DINT  := L#50;	//Centratore 1: Velocita' 2
   C1_Velocita_3 : DINT  := L#50;	//Centratore 1: Velocita' 3
   C1_Velocita_4 : DINT  := L#50;	//Centratore 1: Velocita' 4 di arrivo
   C1_Accell_1 : DINT  := L#500;	//Centratore 1: Accelerazione 1 di avvicinamento
   C1_Accell_2 : DINT  := L#500;	//Centratore 1: Accelerazione 2
   C1_Accell_3 : DINT  := L#500;	//Centratore 1: Accelerazione 3
   C1_Accell_4 : DINT  := L#500;	//Centratore 1: Accelerazione 4 di arrivo
   word_148 : WORD ;
   C2_Posizione_1 : DINT  := L#500000;	//Centratore 2: Posizione 1 di avicinamento
   C2_Posizione_2 : DINT  := L#520000;	//Centratore 2: Posizione 2 di cambio velocita'
   C2_Posizione_3 : DINT  := L#530000;	//Centratore 2: Posizione 3 di cambio velocita'
   C2_Posizione_4 : DINT  := L#559000;	//Centratore 2: Posizione 4 di arrivo
   C2_Velocita_1 : DINT  := L#50;	//Centratore 2: Velocita' 1 di avvicinamento
   C2_Velocita_2 : DINT  := L#50;	//Centratore 2: Velocita' 2
   C2_Velocita_3 : DINT  := L#50;	//Centratore 2: Velocita' 3
   C2_Velocita_4 : DINT  := L#50;	//Centratore 2: Velocita' 4 di arrivo
   C2_Accell_1 : DINT  := L#500;	//Centratore 2: Accelerazione 1 di avvicinamento
   C2_Accell_2 : DINT  := L#500;	//Centratore 2: Accelerazione 2
   C2_Accell_3 : DINT  := L#500;	//Centratore 2: Accelerazione 3
   C2_Accell_4 : DINT  := L#500;	//Centratore 2: Accelerazione 4 di arrivo
   word_198 : WORD ;
   C3_Posizione_1 : DINT  := L#630000;	//Centratore 3: Posizione 1 di avicinamento
   C3_Posizione_2 : DINT  := L#650000;	//Centratore 3: Posizione 2 di cambio velocita'
   C3_Posizione_3 : DINT  := L#660000;	//Centratore 3: Posizione 3 di cambio velocita'
   C3_Posizione_4 : DINT  := L#698600;	//Centratore 3: Posizione 4 di arrivo
   C3_Velocita_1 : DINT  := L#50;	//Centratore 3: Velocita' 1 di avvicinamento
   C3_Velocita_2 : DINT  := L#50;	//Centratore 3: Velocita' 2
   C3_Velocita_3 : DINT  := L#50;	//Centratore 3: Velocita' 3
   C3_Velocita_4 : DINT  := L#50;	//Centratore 3: Velocita' 4 di arrivo
   C3_Accell_1 : DINT  := L#500;	//Centratore 3: Accelerazione 1 di avvicinamento
   C3_Accell_2 : DINT  := L#500;	//Centratore 3: Accelerazione 2
   C3_Accell_3 : DINT  := L#500;	//Centratore 3: Accelerazione 3
   C3_Accell_4 : DINT  := L#500;	//Centratore 3: Accelerazione 4 di arrivo
   word_248 : WORD ;
   C4_Posizione_1 : DINT  := L#630000;	//Centratore 4: Posizione 1 di avicinamento
   C4_Posizione_2 : DINT  := L#650000;	//Centratore 4: Posizione 2 di cambio velocita'
   C4_Posizione_3 : DINT  := L#660000;	//Centratore 4: Posizione 3 di cambio velocita'
   C4_Posizione_4 : DINT  := L#706200;	//Centratore 4: Posizione 4 di arrivo
   C4_Velocita_1 : DINT  := L#50;	//Centratore 4: Velocita' 1 di avvicinamento
   C4_Velocita_2 : DINT  := L#50;	//Centratore 4: Velocita' 2
   C4_Velocita_3 : DINT  := L#50;	//Centratore 4: Velocita' 3
   C4_Velocita_4 : DINT  := L#50;	//Centratore 4: Velocita' 4 di arrivo
   C4_Accell_1 : DINT  := L#500;	//Centratore 4: Accelerazione 1 di avvicinamento
   C4_Accell_2 : DINT  := L#500;	//Centratore 4: Accelerazione 2
   C4_Accell_3 : DINT  := L#500;	//Centratore 4: Accelerazione 3
   C4_Accell_4 : DINT  := L#500;	//Centratore 4: Accelerazione 4 di arrivo
   word_298 : WORD ;
   C5_Posizione_1 : DINT  := L#1180000;	//Centratore 5: Posizione 1 di avicinamento
   C5_Posizione_2 : DINT  := L#1200000;	//Centratore 5: Posizione 2 di cambio velocita'
   C5_Posizione_3 : DINT  := L#1220000;	//Centratore 5: Posizione 3 di cambio velocita'
   C5_Posizione_4 : DINT  := L#1247000;	//Centratore 5: Posizione 4 di arrivo
   C5_Velocita_1 : DINT  := L#50;	//Centratore 5: Velocita' 1 di avvicinamento
   C5_Velocita_2 : DINT  := L#50;	//Centratore 5: Velocita' 2
   C5_Velocita_3 : DINT  := L#50;	//Centratore 5: Velocita' 3
   C5_Velocita_4 : DINT  := L#50;	//Centratore 5: Velocita' 4 di arrivo
   C5_Accell_1 : DINT  := L#500;	//Centratore 5: Accelerazione 1 di avvicinamento
   C5_Accell_2 : DINT  := L#500;	//Centratore 5: Accelerazione 2
   C5_Accell_3 : DINT  := L#500;	//Centratore 5: Accelerazione 3
   C5_Accell_4 : DINT  := L#500;	//Centratore 5: Accelerazione 4 di arrivo
   word_348 : WORD ;
   C6_Posizione_1 : DINT  := L#1180000;	//Centratore 6: Posizione 1 di avicinamento
   C6_Posizione_2 : DINT  := L#1200000;	//Centratore 6: Posizione 2 di cambio velocita'
   C6_Posizione_3 : DINT  := L#1220000;	//Centratore 6: Posizione 3 di cambio velocita'
   C6_Posizione_4 : DINT  := L#1237400;	//Centratore 6: Posizione 4 di arrivo
   C6_Velocita_1 : DINT  := L#50;	//Centratore 6: Velocita' 1 di avvicinamento
   C6_Velocita_2 : DINT  := L#50;	//Centratore 6: Velocita' 2
   C6_Velocita_3 : DINT  := L#50;	//Centratore 6: Velocita' 3
   C6_Velocita_4 : DINT  := L#50;	//Centratore 6: Velocita' 4 di arrivo
   C6_Accell_1 : DINT  := L#500;	//Centratore 6: Accelerazione 1 di avvicinamento
   C6_Accell_2 : DINT  := L#500;	//Centratore 6: Accelerazione 2
   C6_Accell_3 : DINT  := L#500;	//Centratore 6: Accelerazione 3
   C6_Accell_4 : DINT  := L#500;	//Centratore 6: Accelerazione 4 di arrivo
   word_398 : WORD ;
  END_STRUCT ;
BEGIN
   LARGHEZZA_LAMIERA := 3.060000e+003;
   COMPENSAZ_TAV_1 := -7.000000e+001;
   QUOTA_H_SFOGLIATORE := 2.000000e+003;
   QUOTA_H_CENTRATORE := 1.960000e+003;
   word16 := S5T#0MS;
   INCLINAZ_TAVOLA_ESCLUSA := FALSE;
   dword20 := 0.000000e+000;
   dword24 := 0.000000e+000;
   dword28 := 0.000000e+000;
   dword32 := 0.000000e+000;
   dword36 := 0.000000e+000;
   NR_MATRICOLA := 2;
   word42 := W#16#0;
   MAGNETE_1_ESCLUSO := FALSE;
   MAGNETE_2_ESCLUSO := FALSE;
   MAGNETE_3_ESCLUSO := FALSE;
   MAGNETE_4_ESCLUSO := FALSE;
   MAGNETE_5_ESCLUSO := FALSE;
   MAGNETE_6_ESCLUSO := FALSE;
   MAGNETE_LAT_SX_ESCLUSO := FALSE;
   MAGNETE_LAT_DX_ESCLUSO := FALSE;
   COMPENSAZ_TAV_2 := -3.000000e+001;
   STAT22 := W#16#0;
   STAT23 := W#16#0;
   STAT24 := W#16#0;
   STAT25 := W#16#0;
   STAT251 := W#16#0;
   STAT26 := T#0MS;
   STAT29 := T#0MS;
   STAT30 := T#0MS;
   STAT31 := T#0MS;
   C1_Timer := 0.000000e+000;
   C2_Timer := 0.000000e+000;
   C3_Timer := 0.000000e+000;
   C4_Timer := 0.000000e+000;
   C5_Timer := 0.000000e+000;
   C6_Timer := 0.000000e+000;
   C1_Posizione_1 := L#163000;
   C1_Posizione_2 := L#183000;
   C1_Posizione_3 := L#193000;
   C1_Posizione_4 := L#235000;
   C1_Velocita_1 := L#500;
   C1_Velocita_2 := L#200;
   C1_Velocita_3 := L#200;
   C1_Velocita_4 := L#50;
   C1_Accell_1 := L#500;
   C1_Accell_2 := L#500;
   C1_Accell_3 := L#500;
   C1_Accell_4 := L#500;
   word_148 := W#16#0;
   C2_Posizione_1 := L#326000;
   C2_Posizione_2 := L#346000;
   C2_Posizione_3 := L#356000;
   C2_Posizione_4 := L#401000;
   C2_Velocita_1 := L#500;
   C2_Velocita_2 := L#200;
   C2_Velocita_3 := L#200;
   C2_Velocita_4 := L#50;
   C2_Accell_1 := L#500;
   C2_Accell_2 := L#500;
   C2_Accell_3 := L#500;
   C2_Accell_4 := L#500;
   word_198 := W#16#0;
   C3_Posizione_1 := L#200000;
   C3_Posizione_2 := L#220000;
   C3_Posizione_3 := L#230000;
   C3_Posizione_4 := L#385000;
   C3_Velocita_1 := L#500;
   C3_Velocita_2 := L#200;
   C3_Velocita_3 := L#200;
   C3_Velocita_4 := L#50;
   C3_Accell_1 := L#500;
   C3_Accell_2 := L#500;
   C3_Accell_3 := L#500;
   C3_Accell_4 := L#500;
   word_248 := W#16#0;
   C4_Posizione_1 := L#100000;
   C4_Posizione_2 := L#120000;
   C4_Posizione_3 := L#130000;
   C4_Posizione_4 := L#283000;
   C4_Velocita_1 := L#500;
   C4_Velocita_2 := L#200;
   C4_Velocita_3 := L#200;
   C4_Velocita_4 := L#50;
   C4_Accell_1 := L#500;
   C4_Accell_2 := L#500;
   C4_Accell_3 := L#500;
   C4_Accell_4 := L#500;
   word_298 := W#16#0;
   C5_Posizione_1 := L#395000;
   C5_Posizione_2 := L#415000;
   C5_Posizione_3 := L#425000;
   C5_Posizione_4 := L#510000;
   C5_Velocita_1 := L#500;
   C5_Velocita_2 := L#200;
   C5_Velocita_3 := L#200;
   C5_Velocita_4 := L#50;
   C5_Accell_1 := L#500;
   C5_Accell_2 := L#500;
   C5_Accell_3 := L#500;
   C5_Accell_4 := L#500;
   word_348 := W#16#0;
   C6_Posizione_1 := L#430000;
   C6_Posizione_2 := L#450000;
   C6_Posizione_3 := L#460000;
   C6_Posizione_4 := L#525000;
   C6_Velocita_1 := L#500;
   C6_Velocita_2 := L#200;
   C6_Velocita_3 := L#200;
   C6_Velocita_4 := L#50;
   C6_Accell_1 := L#500;
   C6_Accell_2 := L#500;
   C6_Accell_3 := L#500;
   C6_Accell_4 := L#500;
   word_398 := W#16#0;
END_DATA_BLOCK

DATA_BLOCK "MATRICOLA 7"
AUTHOR : Lodato
FAMILY : DESTACK
NAME : DATI
VERSION : 0.1


  STRUCT
   LARGHEZZA_LAMIERA : REAL  := 1.500000e+003;	//LARGHEZZA LAMIERA ATTUALE
   COMPENSAZ_TAV_1 : REAL ;	//COMPENSAZIONE TAVOLA 1
   QUOTA_H_SFOGLIATORE : REAL ;	//Quota impostata altezza sfogliatore
   QUOTA_H_CENTRATORE : REAL ;	//Quota impostata altezza centratore
   word16 : S5TIME ;
   INCLINAZ_TAVOLA_ESCLUSA : BOOL ;	//INCLINAZIONE TAVOLA ESCLUSA
   dword20 : REAL ;
   dword24 : REAL ;
   dword28 : REAL ;
   dword32 : REAL ;
   dword36 : REAL ;
   NR_MATRICOLA : INT  := 1;	//Numero di matricola
   word42 : WORD ;
   MAGNETE_1_ESCLUSO : BOOL ;	//MAGNETE 1 ESCLUSO DA MP270
   MAGNETE_2_ESCLUSO : BOOL ;	//MAGNETE 2 ESCLUSO DA MP270
   MAGNETE_3_ESCLUSO : BOOL ;	//MAGNETE 3 ESCLUSO DA MP270
   MAGNETE_4_ESCLUSO : BOOL ;	//MAGNETE 4 ESCLUSO DA MP270
   MAGNETE_5_ESCLUSO : BOOL ;	//MAGNETE 5 ESCLUSO DA MP270
   MAGNETE_6_ESCLUSO : BOOL ;	//MAGNETE 6 ESCLUSO DA MP270
   MAGNETE_LAT_SX_ESCLUSO : BOOL ;	//MAGNETE LATERALE SX ESCLUSO DA MP270
   MAGNETE_LAT_DX_ESCLUSO : BOOL ;	//MAGNETE LATERALE DX ESCLUSO DA MP270
   COMPENSAZ_TAV_2 : REAL ;	//COMPENSAZIONE TAVOLA 2
   STAT22 : WORD ;
   STAT23 : WORD ;
   STAT24 : WORD ;
   STAT25 : WORD ;
   STAT251 : WORD ;
   STAT26 : TIME ;
   STAT29 : TIME ;
   STAT30 : TIME ;
   STAT31 : TIME ;
   C1_Timer : REAL ;	//Centratore 1: Timer ritardo partenza
   C2_Timer : REAL ;	//Centratore 2: Timer ritardo partenza
   C3_Timer : REAL ;	//Centratore 3: Timer ritardo partenza
   C4_Timer : REAL ;	//Centratore 4: Timer ritardo partenza
   C5_Timer : REAL ;	//Centratore 5: Timer ritardo partenza
   C6_Timer : REAL ;	//Centratore 6: Timer ritardo partenza
   C1_Posizione_1 : DINT  := L#500000;	//Centratore 1: Posizione 1 di avicinamento
   C1_Posizione_2 : DINT  := L#520000;	//Centratore 1: Posizione 2 di cambio velocita'
   C1_Posizione_3 : DINT  := L#530000;	//Centratore 1: Posizione 3 di cambio velocita'
   C1_Posizione_4 : DINT  := L#565400;	//Centratore 1: Posizione 4 di arrivo
   C1_Velocita_1 : DINT  := L#50;	//Centratore 1: Velocita' 1 di avvicinamento
   C1_Velocita_2 : DINT  := L#50;	//Centratore 1: Velocita' 2
   C1_Velocita_3 : DINT  := L#50;	//Centratore 1: Velocita' 3
   C1_Velocita_4 : DINT  := L#50;	//Centratore 1: Velocita' 4 di arrivo
   C1_Accell_1 : DINT  := L#500;	//Centratore 1: Accelerazione 1 di avvicinamento
   C1_Accell_2 : DINT  := L#500;	//Centratore 1: Accelerazione 2
   C1_Accell_3 : DINT  := L#500;	//Centratore 1: Accelerazione 3
   C1_Accell_4 : DINT  := L#500;	//Centratore 1: Accelerazione 4 di arrivo
   word_148 : WORD ;
   C2_Posizione_1 : DINT  := L#500000;	//Centratore 2: Posizione 1 di avicinamento
   C2_Posizione_2 : DINT  := L#520000;	//Centratore 2: Posizione 2 di cambio velocita'
   C2_Posizione_3 : DINT  := L#530000;	//Centratore 2: Posizione 3 di cambio velocita'
   C2_Posizione_4 : DINT  := L#559000;	//Centratore 2: Posizione 4 di arrivo
   C2_Velocita_1 : DINT  := L#50;	//Centratore 2: Velocita' 1 di avvicinamento
   C2_Velocita_2 : DINT  := L#50;	//Centratore 2: Velocita' 2
   C2_Velocita_3 : DINT  := L#50;	//Centratore 2: Velocita' 3
   C2_Velocita_4 : DINT  := L#50;	//Centratore 2: Velocita' 4 di arrivo
   C2_Accell_1 : DINT  := L#500;	//Centratore 2: Accelerazione 1 di avvicinamento
   C2_Accell_2 : DINT  := L#500;	//Centratore 2: Accelerazione 2
   C2_Accell_3 : DINT  := L#500;	//Centratore 2: Accelerazione 3
   C2_Accell_4 : DINT  := L#500;	//Centratore 2: Accelerazione 4 di arrivo
   word_198 : WORD ;
   C3_Posizione_1 : DINT  := L#630000;	//Centratore 3: Posizione 1 di avicinamento
   C3_Posizione_2 : DINT  := L#650000;	//Centratore 3: Posizione 2 di cambio velocita'
   C3_Posizione_3 : DINT  := L#660000;	//Centratore 3: Posizione 3 di cambio velocita'
   C3_Posizione_4 : DINT  := L#698600;	//Centratore 3: Posizione 4 di arrivo
   C3_Velocita_1 : DINT  := L#50;	//Centratore 3: Velocita' 1 di avvicinamento
   C3_Velocita_2 : DINT  := L#50;	//Centratore 3: Velocita' 2
   C3_Velocita_3 : DINT  := L#50;	//Centratore 3: Velocita' 3
   C3_Velocita_4 : DINT  := L#50;	//Centratore 3: Velocita' 4 di arrivo
   C3_Accell_1 : DINT  := L#500;	//Centratore 3: Accelerazione 1 di avvicinamento
   C3_Accell_2 : DINT  := L#500;	//Centratore 3: Accelerazione 2
   C3_Accell_3 : DINT  := L#500;	//Centratore 3: Accelerazione 3
   C3_Accell_4 : DINT  := L#500;	//Centratore 3: Accelerazione 4 di arrivo
   word_248 : WORD ;
   C4_Posizione_1 : DINT  := L#630000;	//Centratore 4: Posizione 1 di avicinamento
   C4_Posizione_2 : DINT  := L#650000;	//Centratore 4: Posizione 2 di cambio velocita'
   C4_Posizione_3 : DINT  := L#660000;	//Centratore 4: Posizione 3 di cambio velocita'
   C4_Posizione_4 : DINT  := L#706200;	//Centratore 4: Posizione 4 di arrivo
   C4_Velocita_1 : DINT  := L#50;	//Centratore 4: Velocita' 1 di avvicinamento
   C4_Velocita_2 : DINT  := L#50;	//Centratore 4: Velocita' 2
   C4_Velocita_3 : DINT  := L#50;	//Centratore 4: Velocita' 3
   C4_Velocita_4 : DINT  := L#50;	//Centratore 4: Velocita' 4 di arrivo
   C4_Accell_1 : DINT  := L#500;	//Centratore 4: Accelerazione 1 di avvicinamento
   C4_Accell_2 : DINT  := L#500;	//Centratore 4: Accelerazione 2
   C4_Accell_3 : DINT  := L#500;	//Centratore 4: Accelerazione 3
   C4_Accell_4 : DINT  := L#500;	//Centratore 4: Accelerazione 4 di arrivo
   word_298 : WORD ;
   C5_Posizione_1 : DINT  := L#1180000;	//Centratore 5: Posizione 1 di avicinamento
   C5_Posizione_2 : DINT  := L#1200000;	//Centratore 5: Posizione 2 di cambio velocita'
   C5_Posizione_3 : DINT  := L#1220000;	//Centratore 5: Posizione 3 di cambio velocita'
   C5_Posizione_4 : DINT  := L#1247000;	//Centratore 5: Posizione 4 di arrivo
   C5_Velocita_1 : DINT  := L#50;	//Centratore 5: Velocita' 1 di avvicinamento
   C5_Velocita_2 : DINT  := L#50;	//Centratore 5: Velocita' 2
   C5_Velocita_3 : DINT  := L#50;	//Centratore 5: Velocita' 3
   C5_Velocita_4 : DINT  := L#50;	//Centratore 5: Velocita' 4 di arrivo
   C5_Accell_1 : DINT  := L#500;	//Centratore 5: Accelerazione 1 di avvicinamento
   C5_Accell_2 : DINT  := L#500;	//Centratore 5: Accelerazione 2
   C5_Accell_3 : DINT  := L#500;	//Centratore 5: Accelerazione 3
   C5_Accell_4 : DINT  := L#500;	//Centratore 5: Accelerazione 4 di arrivo
   word_348 : WORD ;
   C6_Posizione_1 : DINT  := L#1180000;	//Centratore 6: Posizione 1 di avicinamento
   C6_Posizione_2 : DINT  := L#1200000;	//Centratore 6: Posizione 2 di cambio velocita'
   C6_Posizione_3 : DINT  := L#1220000;	//Centratore 6: Posizione 3 di cambio velocita'
   C6_Posizione_4 : DINT  := L#1237400;	//Centratore 6: Posizione 4 di arrivo
   C6_Velocita_1 : DINT  := L#50;	//Centratore 6: Velocita' 1 di avvicinamento
   C6_Velocita_2 : DINT  := L#50;	//Centratore 6: Velocita' 2
   C6_Velocita_3 : DINT  := L#50;	//Centratore 6: Velocita' 3
   C6_Velocita_4 : DINT  := L#50;	//Centratore 6: Velocita' 4 di arrivo
   C6_Accell_1 : DINT  := L#500;	//Centratore 6: Accelerazione 1 di avvicinamento
   C6_Accell_2 : DINT  := L#500;	//Centratore 6: Accelerazione 2
   C6_Accell_3 : DINT  := L#500;	//Centratore 6: Accelerazione 3
   C6_Accell_4 : DINT  := L#500;	//Centratore 6: Accelerazione 4 di arrivo
   word_398 : WORD ;
  END_STRUCT ;
BEGIN
   LARGHEZZA_LAMIERA := 3.060000e+003;
   COMPENSAZ_TAV_1 := -7.000000e+001;
   QUOTA_H_SFOGLIATORE := 2.000000e+003;
   QUOTA_H_CENTRATORE := 1.960000e+003;
   word16 := S5T#0MS;
   INCLINAZ_TAVOLA_ESCLUSA := FALSE;
   dword20 := 0.000000e+000;
   dword24 := 0.000000e+000;
   dword28 := 0.000000e+000;
   dword32 := 0.000000e+000;
   dword36 := 0.000000e+000;
   NR_MATRICOLA := 2;
   word42 := W#16#0;
   MAGNETE_1_ESCLUSO := FALSE;
   MAGNETE_2_ESCLUSO := FALSE;
   MAGNETE_3_ESCLUSO := FALSE;
   MAGNETE_4_ESCLUSO := FALSE;
   MAGNETE_5_ESCLUSO := FALSE;
   MAGNETE_6_ESCLUSO := FALSE;
   MAGNETE_LAT_SX_ESCLUSO := FALSE;
   MAGNETE_LAT_DX_ESCLUSO := FALSE;
   COMPENSAZ_TAV_2 := -3.000000e+001;
   STAT22 := W#16#0;
   STAT23 := W#16#0;
   STAT24 := W#16#0;
   STAT25 := W#16#0;
   STAT251 := W#16#0;
   STAT26 := T#0MS;
   STAT29 := T#0MS;
   STAT30 := T#0MS;
   STAT31 := T#0MS;
   C1_Timer := 0.000000e+000;
   C2_Timer := 0.000000e+000;
   C3_Timer := 0.000000e+000;
   C4_Timer := 0.000000e+000;
   C5_Timer := 0.000000e+000;
   C6_Timer := 0.000000e+000;
   C1_Posizione_1 := L#163000;
   C1_Posizione_2 := L#183000;
   C1_Posizione_3 := L#193000;
   C1_Posizione_4 := L#235000;
   C1_Velocita_1 := L#500;
   C1_Velocita_2 := L#200;
   C1_Velocita_3 := L#200;
   C1_Velocita_4 := L#50;
   C1_Accell_1 := L#500;
   C1_Accell_2 := L#500;
   C1_Accell_3 := L#500;
   C1_Accell_4 := L#500;
   word_148 := W#16#0;
   C2_Posizione_1 := L#326000;
   C2_Posizione_2 := L#346000;
   C2_Posizione_3 := L#356000;
   C2_Posizione_4 := L#401000;
   C2_Velocita_1 := L#500;
   C2_Velocita_2 := L#200;
   C2_Velocita_3 := L#200;
   C2_Velocita_4 := L#50;
   C2_Accell_1 := L#500;
   C2_Accell_2 := L#500;
   C2_Accell_3 := L#500;
   C2_Accell_4 := L#500;
   word_198 := W#16#0;
   C3_Posizione_1 := L#200000;
   C3_Posizione_2 := L#220000;
   C3_Posizione_3 := L#230000;
   C3_Posizione_4 := L#385000;
   C3_Velocita_1 := L#500;
   C3_Velocita_2 := L#200;
   C3_Velocita_3 := L#200;
   C3_Velocita_4 := L#50;
   C3_Accell_1 := L#500;
   C3_Accell_2 := L#500;
   C3_Accell_3 := L#500;
   C3_Accell_4 := L#500;
   word_248 := W#16#0;
   C4_Posizione_1 := L#100000;
   C4_Posizione_2 := L#120000;
   C4_Posizione_3 := L#130000;
   C4_Posizione_4 := L#283000;
   C4_Velocita_1 := L#500;
   C4_Velocita_2 := L#200;
   C4_Velocita_3 := L#200;
   C4_Velocita_4 := L#50;
   C4_Accell_1 := L#500;
   C4_Accell_2 := L#500;
   C4_Accell_3 := L#500;
   C4_Accell_4 := L#500;
   word_298 := W#16#0;
   C5_Posizione_1 := L#395000;
   C5_Posizione_2 := L#415000;
   C5_Posizione_3 := L#425000;
   C5_Posizione_4 := L#510000;
   C5_Velocita_1 := L#500;
   C5_Velocita_2 := L#200;
   C5_Velocita_3 := L#200;
   C5_Velocita_4 := L#50;
   C5_Accell_1 := L#500;
   C5_Accell_2 := L#500;
   C5_Accell_3 := L#500;
   C5_Accell_4 := L#500;
   word_348 := W#16#0;
   C6_Posizione_1 := L#430000;
   C6_Posizione_2 := L#450000;
   C6_Posizione_3 := L#460000;
   C6_Posizione_4 := L#525000;
   C6_Velocita_1 := L#500;
   C6_Velocita_2 := L#200;
   C6_Velocita_3 := L#200;
   C6_Velocita_4 := L#50;
   C6_Accell_1 := L#500;
   C6_Accell_2 := L#500;
   C6_Accell_3 := L#500;
   C6_Accell_4 := L#500;
   word_398 := W#16#0;
END_DATA_BLOCK

DATA_BLOCK "MATRICOLA 8"
AUTHOR : Lodato
FAMILY : DESTACK
NAME : DATI
VERSION : 0.1


  STRUCT
   LARGHEZZA_LAMIERA : REAL  := 1.500000e+003;	//LARGHEZZA LAMIERA ATTUALE
   COMPENSAZ_TAV_1 : REAL ;	//COMPENSAZIONE TAVOLA 1
   QUOTA_H_SFOGLIATORE : REAL ;	//Quota impostata altezza sfogliatore
   QUOTA_H_CENTRATORE : REAL ;	//Quota impostata altezza centratore
   word16 : S5TIME ;
   INCLINAZ_TAVOLA_ESCLUSA : BOOL ;	//INCLINAZIONE TAVOLA ESCLUSA
   dword20 : REAL ;
   dword24 : REAL ;
   dword28 : REAL ;
   dword32 : REAL ;
   dword36 : REAL ;
   NR_MATRICOLA : INT  := 1;	//Numero di matricola
   word42 : WORD ;
   MAGNETE_1_ESCLUSO : BOOL ;	//MAGNETE 1 ESCLUSO DA MP270
   MAGNETE_2_ESCLUSO : BOOL ;	//MAGNETE 2 ESCLUSO DA MP270
   MAGNETE_3_ESCLUSO : BOOL ;	//MAGNETE 3 ESCLUSO DA MP270
   MAGNETE_4_ESCLUSO : BOOL ;	//MAGNETE 4 ESCLUSO DA MP270
   MAGNETE_5_ESCLUSO : BOOL ;	//MAGNETE 5 ESCLUSO DA MP270
   MAGNETE_6_ESCLUSO : BOOL ;	//MAGNETE 6 ESCLUSO DA MP270
   MAGNETE_LAT_SX_ESCLUSO : BOOL ;	//MAGNETE LATERALE SX ESCLUSO DA MP270
   MAGNETE_LAT_DX_ESCLUSO : BOOL ;	//MAGNETE LATERALE DX ESCLUSO DA MP270
   COMPENSAZ_TAV_2 : REAL ;	//COMPENSAZIONE TAVOLA 2
   STAT22 : WORD ;
   STAT23 : WORD ;
   STAT24 : WORD ;
   STAT25 : WORD ;
   STAT251 : WORD ;
   STAT26 : TIME ;
   STAT29 : TIME ;
   STAT30 : TIME ;
   STAT31 : TIME ;
   C1_Timer : REAL ;	//Centratore 1: Timer ritardo partenza
   C2_Timer : REAL ;	//Centratore 2: Timer ritardo partenza
   C3_Timer : REAL ;	//Centratore 3: Timer ritardo partenza
   C4_Timer : REAL ;	//Centratore 4: Timer ritardo partenza
   C5_Timer : REAL ;	//Centratore 5: Timer ritardo partenza
   C6_Timer : REAL ;	//Centratore 6: Timer ritardo partenza
   C1_Posizione_1 : DINT  := L#500000;	//Centratore 1: Posizione 1 di avicinamento
   C1_Posizione_2 : DINT  := L#520000;	//Centratore 1: Posizione 2 di cambio velocita'
   C1_Posizione_3 : DINT  := L#530000;	//Centratore 1: Posizione 3 di cambio velocita'
   C1_Posizione_4 : DINT  := L#565400;	//Centratore 1: Posizione 4 di arrivo
   C1_Velocita_1 : DINT  := L#50;	//Centratore 1: Velocita' 1 di avvicinamento
   C1_Velocita_2 : DINT  := L#50;	//Centratore 1: Velocita' 2
   C1_Velocita_3 : DINT  := L#50;	//Centratore 1: Velocita' 3
   C1_Velocita_4 : DINT  := L#50;	//Centratore 1: Velocita' 4 di arrivo
   C1_Accell_1 : DINT  := L#500;	//Centratore 1: Accelerazione 1 di avvicinamento
   C1_Accell_2 : DINT  := L#500;	//Centratore 1: Accelerazione 2
   C1_Accell_3 : DINT  := L#500;	//Centratore 1: Accelerazione 3
   C1_Accell_4 : DINT  := L#500;	//Centratore 1: Accelerazione 4 di arrivo
   word_148 : WORD ;
   C2_Posizione_1 : DINT  := L#500000;	//Centratore 2: Posizione 1 di avicinamento
   C2_Posizione_2 : DINT  := L#520000;	//Centratore 2: Posizione 2 di cambio velocita'
   C2_Posizione_3 : DINT  := L#530000;	//Centratore 2: Posizione 3 di cambio velocita'
   C2_Posizione_4 : DINT  := L#559000;	//Centratore 2: Posizione 4 di arrivo
   C2_Velocita_1 : DINT  := L#50;	//Centratore 2: Velocita' 1 di avvicinamento
   C2_Velocita_2 : DINT  := L#50;	//Centratore 2: Velocita' 2
   C2_Velocita_3 : DINT  := L#50;	//Centratore 2: Velocita' 3
   C2_Velocita_4 : DINT  := L#50;	//Centratore 2: Velocita' 4 di arrivo
   C2_Accell_1 : DINT  := L#500;	//Centratore 2: Accelerazione 1 di avvicinamento
   C2_Accell_2 : DINT  := L#500;	//Centratore 2: Accelerazione 2
   C2_Accell_3 : DINT  := L#500;	//Centratore 2: Accelerazione 3
   C2_Accell_4 : DINT  := L#500;	//Centratore 2: Accelerazione 4 di arrivo
   word_198 : WORD ;
   C3_Posizione_1 : DINT  := L#630000;	//Centratore 3: Posizione 1 di avicinamento
   C3_Posizione_2 : DINT  := L#650000;	//Centratore 3: Posizione 2 di cambio velocita'
   C3_Posizione_3 : DINT  := L#660000;	//Centratore 3: Posizione 3 di cambio velocita'
   C3_Posizione_4 : DINT  := L#698600;	//Centratore 3: Posizione 4 di arrivo
   C3_Velocita_1 : DINT  := L#50;	//Centratore 3: Velocita' 1 di avvicinamento
   C3_Velocita_2 : DINT  := L#50;	//Centratore 3: Velocita' 2
   C3_Velocita_3 : DINT  := L#50;	//Centratore 3: Velocita' 3
   C3_Velocita_4 : DINT  := L#50;	//Centratore 3: Velocita' 4 di arrivo
   C3_Accell_1 : DINT  := L#500;	//Centratore 3: Accelerazione 1 di avvicinamento
   C3_Accell_2 : DINT  := L#500;	//Centratore 3: Accelerazione 2
   C3_Accell_3 : DINT  := L#500;	//Centratore 3: Accelerazione 3
   C3_Accell_4 : DINT  := L#500;	//Centratore 3: Accelerazione 4 di arrivo
   word_248 : WORD ;
   C4_Posizione_1 : DINT  := L#630000;	//Centratore 4: Posizione 1 di avicinamento
   C4_Posizione_2 : DINT  := L#650000;	//Centratore 4: Posizione 2 di cambio velocita'
   C4_Posizione_3 : DINT  := L#660000;	//Centratore 4: Posizione 3 di cambio velocita'
   C4_Posizione_4 : DINT  := L#706200;	//Centratore 4: Posizione 4 di arrivo
   C4_Velocita_1 : DINT  := L#50;	//Centratore 4: Velocita' 1 di avvicinamento
   C4_Velocita_2 : DINT  := L#50;	//Centratore 4: Velocita' 2
   C4_Velocita_3 : DINT  := L#50;	//Centratore 4: Velocita' 3
   C4_Velocita_4 : DINT  := L#50;	//Centratore 4: Velocita' 4 di arrivo
   C4_Accell_1 : DINT  := L#500;	//Centratore 4: Accelerazione 1 di avvicinamento
   C4_Accell_2 : DINT  := L#500;	//Centratore 4: Accelerazione 2
   C4_Accell_3 : DINT  := L#500;	//Centratore 4: Accelerazione 3
   C4_Accell_4 : DINT  := L#500;	//Centratore 4: Accelerazione 4 di arrivo
   word_298 : WORD ;
   C5_Posizione_1 : DINT  := L#1180000;	//Centratore 5: Posizione 1 di avicinamento
   C5_Posizione_2 : DINT  := L#1200000;	//Centratore 5: Posizione 2 di cambio velocita'
   C5_Posizione_3 : DINT  := L#1220000;	//Centratore 5: Posizione 3 di cambio velocita'
   C5_Posizione_4 : DINT  := L#1247000;	//Centratore 5: Posizione 4 di arrivo
   C5_Velocita_1 : DINT  := L#50;	//Centratore 5: Velocita' 1 di avvicinamento
   C5_Velocita_2 : DINT  := L#50;	//Centratore 5: Velocita' 2
   C5_Velocita_3 : DINT  := L#50;	//Centratore 5: Velocita' 3
   C5_Velocita_4 : DINT  := L#50;	//Centratore 5: Velocita' 4 di arrivo
   C5_Accell_1 : DINT  := L#500;	//Centratore 5: Accelerazione 1 di avvicinamento
   C5_Accell_2 : DINT  := L#500;	//Centratore 5: Accelerazione 2
   C5_Accell_3 : DINT  := L#500;	//Centratore 5: Accelerazione 3
   C5_Accell_4 : DINT  := L#500;	//Centratore 5: Accelerazione 4 di arrivo
   word_348 : WORD ;
   C6_Posizione_1 : DINT  := L#1180000;	//Centratore 6: Posizione 1 di avicinamento
   C6_Posizione_2 : DINT  := L#1200000;	//Centratore 6: Posizione 2 di cambio velocita'
   C6_Posizione_3 : DINT  := L#1220000;	//Centratore 6: Posizione 3 di cambio velocita'
   C6_Posizione_4 : DINT  := L#1237400;	//Centratore 6: Posizione 4 di arrivo
   C6_Velocita_1 : DINT  := L#50;	//Centratore 6: Velocita' 1 di avvicinamento
   C6_Velocita_2 : DINT  := L#50;	//Centratore 6: Velocita' 2
   C6_Velocita_3 : DINT  := L#50;	//Centratore 6: Velocita' 3
   C6_Velocita_4 : DINT  := L#50;	//Centratore 6: Velocita' 4 di arrivo
   C6_Accell_1 : DINT  := L#500;	//Centratore 6: Accelerazione 1 di avvicinamento
   C6_Accell_2 : DINT  := L#500;	//Centratore 6: Accelerazione 2
   C6_Accell_3 : DINT  := L#500;	//Centratore 6: Accelerazione 3
   C6_Accell_4 : DINT  := L#500;	//Centratore 6: Accelerazione 4 di arrivo
   word_398 : WORD ;
  END_STRUCT ;
BEGIN
   LARGHEZZA_LAMIERA := 3.060000e+003;
   COMPENSAZ_TAV_1 := -7.000000e+001;
   QUOTA_H_SFOGLIATORE := 2.000000e+003;
   QUOTA_H_CENTRATORE := 1.960000e+003;
   word16 := S5T#0MS;
   INCLINAZ_TAVOLA_ESCLUSA := FALSE;
   dword20 := 0.000000e+000;
   dword24 := 0.000000e+000;
   dword28 := 0.000000e+000;
   dword32 := 0.000000e+000;
   dword36 := 0.000000e+000;
   NR_MATRICOLA := 2;
   word42 := W#16#0;
   MAGNETE_1_ESCLUSO := FALSE;
   MAGNETE_2_ESCLUSO := FALSE;
   MAGNETE_3_ESCLUSO := FALSE;
   MAGNETE_4_ESCLUSO := FALSE;
   MAGNETE_5_ESCLUSO := FALSE;
   MAGNETE_6_ESCLUSO := FALSE;
   MAGNETE_LAT_SX_ESCLUSO := FALSE;
   MAGNETE_LAT_DX_ESCLUSO := FALSE;
   COMPENSAZ_TAV_2 := -3.000000e+001;
   STAT22 := W#16#0;
   STAT23 := W#16#0;
   STAT24 := W#16#0;
   STAT25 := W#16#0;
   STAT251 := W#16#0;
   STAT26 := T#0MS;
   STAT29 := T#0MS;
   STAT30 := T#0MS;
   STAT31 := T#0MS;
   C1_Timer := 0.000000e+000;
   C2_Timer := 0.000000e+000;
   C3_Timer := 0.000000e+000;
   C4_Timer := 0.000000e+000;
   C5_Timer := 0.000000e+000;
   C6_Timer := 0.000000e+000;
   C1_Posizione_1 := L#163000;
   C1_Posizione_2 := L#183000;
   C1_Posizione_3 := L#193000;
   C1_Posizione_4 := L#235000;
   C1_Velocita_1 := L#500;
   C1_Velocita_2 := L#200;
   C1_Velocita_3 := L#200;
   C1_Velocita_4 := L#50;
   C1_Accell_1 := L#500;
   C1_Accell_2 := L#500;
   C1_Accell_3 := L#500;
   C1_Accell_4 := L#500;
   word_148 := W#16#0;
   C2_Posizione_1 := L#326000;
   C2_Posizione_2 := L#346000;
   C2_Posizione_3 := L#356000;
   C2_Posizione_4 := L#401000;
   C2_Velocita_1 := L#500;
   C2_Velocita_2 := L#200;
   C2_Velocita_3 := L#200;
   C2_Velocita_4 := L#50;
   C2_Accell_1 := L#500;
   C2_Accell_2 := L#500;
   C2_Accell_3 := L#500;
   C2_Accell_4 := L#500;
   word_198 := W#16#0;
   C3_Posizione_1 := L#200000;
   C3_Posizione_2 := L#220000;
   C3_Posizione_3 := L#230000;
   C3_Posizione_4 := L#385000;
   C3_Velocita_1 := L#500;
   C3_Velocita_2 := L#200;
   C3_Velocita_3 := L#200;
   C3_Velocita_4 := L#50;
   C3_Accell_1 := L#500;
   C3_Accell_2 := L#500;
   C3_Accell_3 := L#500;
   C3_Accell_4 := L#500;
   word_248 := W#16#0;
   C4_Posizione_1 := L#100000;
   C4_Posizione_2 := L#120000;
   C4_Posizione_3 := L#130000;
   C4_Posizione_4 := L#283000;
   C4_Velocita_1 := L#500;
   C4_Velocita_2 := L#200;
   C4_Velocita_3 := L#200;
   C4_Velocita_4 := L#50;
   C4_Accell_1 := L#500;
   C4_Accell_2 := L#500;
   C4_Accell_3 := L#500;
   C4_Accell_4 := L#500;
   word_298 := W#16#0;
   C5_Posizione_1 := L#395000;
   C5_Posizione_2 := L#415000;
   C5_Posizione_3 := L#425000;
   C5_Posizione_4 := L#510000;
   C5_Velocita_1 := L#500;
   C5_Velocita_2 := L#200;
   C5_Velocita_3 := L#200;
   C5_Velocita_4 := L#50;
   C5_Accell_1 := L#500;
   C5_Accell_2 := L#500;
   C5_Accell_3 := L#500;
   C5_Accell_4 := L#500;
   word_348 := W#16#0;
   C6_Posizione_1 := L#430000;
   C6_Posizione_2 := L#450000;
   C6_Posizione_3 := L#460000;
   C6_Posizione_4 := L#525000;
   C6_Velocita_1 := L#500;
   C6_Velocita_2 := L#200;
   C6_Velocita_3 := L#200;
   C6_Velocita_4 := L#50;
   C6_Accell_1 := L#500;
   C6_Accell_2 := L#500;
   C6_Accell_3 := L#500;
   C6_Accell_4 := L#500;
   word_398 := W#16#0;
END_DATA_BLOCK

DATA_BLOCK "MATRICOLA 9"
AUTHOR : Lodato
FAMILY : DESTACK
NAME : DATI
VERSION : 0.1


  STRUCT
   LARGHEZZA_LAMIERA : REAL  := 1.500000e+003;	//LARGHEZZA LAMIERA ATTUALE
   COMPENSAZ_TAV_1 : REAL ;	//COMPENSAZIONE TAVOLA 1
   QUOTA_H_SFOGLIATORE : REAL ;	//Quota impostata altezza sfogliatore
   QUOTA_H_CENTRATORE : REAL ;	//Quota impostata altezza centratore
   word16 : S5TIME ;
   INCLINAZ_TAVOLA_ESCLUSA : BOOL ;	//INCLINAZIONE TAVOLA ESCLUSA
   dword20 : REAL ;
   dword24 : REAL ;
   dword28 : REAL ;
   dword32 : REAL ;
   dword36 : REAL ;
   NR_MATRICOLA : INT  := 1;	//Numero di matricola
   word42 : WORD ;
   MAGNETE_1_ESCLUSO : BOOL ;	//MAGNETE 1 ESCLUSO DA MP270
   MAGNETE_2_ESCLUSO : BOOL ;	//MAGNETE 2 ESCLUSO DA MP270
   MAGNETE_3_ESCLUSO : BOOL ;	//MAGNETE 3 ESCLUSO DA MP270
   MAGNETE_4_ESCLUSO : BOOL ;	//MAGNETE 4 ESCLUSO DA MP270
   MAGNETE_5_ESCLUSO : BOOL ;	//MAGNETE 5 ESCLUSO DA MP270
   MAGNETE_6_ESCLUSO : BOOL ;	//MAGNETE 6 ESCLUSO DA MP270
   MAGNETE_LAT_SX_ESCLUSO : BOOL ;	//MAGNETE LATERALE SX ESCLUSO DA MP270
   MAGNETE_LAT_DX_ESCLUSO : BOOL ;	//MAGNETE LATERALE DX ESCLUSO DA MP270
   COMPENSAZ_TAV_2 : REAL ;	//COMPENSAZIONE TAVOLA 2
   STAT22 : WORD ;
   STAT23 : WORD ;
   STAT24 : WORD ;
   STAT25 : WORD ;
   STAT251 : WORD ;
   STAT26 : TIME ;
   STAT29 : TIME ;
   STAT30 : TIME ;
   STAT31 : TIME ;
   C1_Timer : REAL ;	//Centratore 1: Timer ritardo partenza
   C2_Timer : REAL ;	//Centratore 2: Timer ritardo partenza
   C3_Timer : REAL ;	//Centratore 3: Timer ritardo partenza
   C4_Timer : REAL ;	//Centratore 4: Timer ritardo partenza
   C5_Timer : REAL ;	//Centratore 5: Timer ritardo partenza
   C6_Timer : REAL ;	//Centratore 6: Timer ritardo partenza
   C1_Posizione_1 : DINT  := L#500000;	//Centratore 1: Posizione 1 di avicinamento
   C1_Posizione_2 : DINT  := L#520000;	//Centratore 1: Posizione 2 di cambio velocita'
   C1_Posizione_3 : DINT  := L#530000;	//Centratore 1: Posizione 3 di cambio velocita'
   C1_Posizione_4 : DINT  := L#565400;	//Centratore 1: Posizione 4 di arrivo
   C1_Velocita_1 : DINT  := L#50;	//Centratore 1: Velocita' 1 di avvicinamento
   C1_Velocita_2 : DINT  := L#50;	//Centratore 1: Velocita' 2
   C1_Velocita_3 : DINT  := L#50;	//Centratore 1: Velocita' 3
   C1_Velocita_4 : DINT  := L#50;	//Centratore 1: Velocita' 4 di arrivo
   C1_Accell_1 : DINT  := L#500;	//Centratore 1: Accelerazione 1 di avvicinamento
   C1_Accell_2 : DINT  := L#500;	//Centratore 1: Accelerazione 2
   C1_Accell_3 : DINT  := L#500;	//Centratore 1: Accelerazione 3
   C1_Accell_4 : DINT  := L#500;	//Centratore 1: Accelerazione 4 di arrivo
   word_148 : WORD ;
   C2_Posizione_1 : DINT  := L#500000;	//Centratore 2: Posizione 1 di avicinamento
   C2_Posizione_2 : DINT  := L#520000;	//Centratore 2: Posizione 2 di cambio velocita'
   C2_Posizione_3 : DINT  := L#530000;	//Centratore 2: Posizione 3 di cambio velocita'
   C2_Posizione_4 : DINT  := L#559000;	//Centratore 2: Posizione 4 di arrivo
   C2_Velocita_1 : DINT  := L#50;	//Centratore 2: Velocita' 1 di avvicinamento
   C2_Velocita_2 : DINT  := L#50;	//Centratore 2: Velocita' 2
   C2_Velocita_3 : DINT  := L#50;	//Centratore 2: Velocita' 3
   C2_Velocita_4 : DINT  := L#50;	//Centratore 2: Velocita' 4 di arrivo
   C2_Accell_1 : DINT  := L#500;	//Centratore 2: Accelerazione 1 di avvicinamento
   C2_Accell_2 : DINT  := L#500;	//Centratore 2: Accelerazione 2
   C2_Accell_3 : DINT  := L#500;	//Centratore 2: Accelerazione 3
   C2_Accell_4 : DINT  := L#500;	//Centratore 2: Accelerazione 4 di arrivo
   word_198 : WORD ;
   C3_Posizione_1 : DINT  := L#630000;	//Centratore 3: Posizione 1 di avicinamento
   C3_Posizione_2 : DINT  := L#650000;	//Centratore 3: Posizione 2 di cambio velocita'
   C3_Posizione_3 : DINT  := L#660000;	//Centratore 3: Posizione 3 di cambio velocita'
   C3_Posizione_4 : DINT  := L#698600;	//Centratore 3: Posizione 4 di arrivo
   C3_Velocita_1 : DINT  := L#50;	//Centratore 3: Velocita' 1 di avvicinamento
   C3_Velocita_2 : DINT  := L#50;	//Centratore 3: Velocita' 2
   C3_Velocita_3 : DINT  := L#50;	//Centratore 3: Velocita' 3
   C3_Velocita_4 : DINT  := L#50;	//Centratore 3: Velocita' 4 di arrivo
   C3_Accell_1 : DINT  := L#500;	//Centratore 3: Accelerazione 1 di avvicinamento
   C3_Accell_2 : DINT  := L#500;	//Centratore 3: Accelerazione 2
   C3_Accell_3 : DINT  := L#500;	//Centratore 3: Accelerazione 3
   C3_Accell_4 : DINT  := L#500;	//Centratore 3: Accelerazione 4 di arrivo
   word_248 : WORD ;
   C4_Posizione_1 : DINT  := L#630000;	//Centratore 4: Posizione 1 di avicinamento
   C4_Posizione_2 : DINT  := L#650000;	//Centratore 4: Posizione 2 di cambio velocita'
   C4_Posizione_3 : DINT  := L#660000;	//Centratore 4: Posizione 3 di cambio velocita'
   C4_Posizione_4 : DINT  := L#706200;	//Centratore 4: Posizione 4 di arrivo
   C4_Velocita_1 : DINT  := L#50;	//Centratore 4: Velocita' 1 di avvicinamento
   C4_Velocita_2 : DINT  := L#50;	//Centratore 4: Velocita' 2
   C4_Velocita_3 : DINT  := L#50;	//Centratore 4: Velocita' 3
   C4_Velocita_4 : DINT  := L#50;	//Centratore 4: Velocita' 4 di arrivo
   C4_Accell_1 : DINT  := L#500;	//Centratore 4: Accelerazione 1 di avvicinamento
   C4_Accell_2 : DINT  := L#500;	//Centratore 4: Accelerazione 2
   C4_Accell_3 : DINT  := L#500;	//Centratore 4: Accelerazione 3
   C4_Accell_4 : DINT  := L#500;	//Centratore 4: Accelerazione 4 di arrivo
   word_298 : WORD ;
   C5_Posizione_1 : DINT  := L#1180000;	//Centratore 5: Posizione 1 di avicinamento
   C5_Posizione_2 : DINT  := L#1200000;	//Centratore 5: Posizione 2 di cambio velocita'
   C5_Posizione_3 : DINT  := L#1220000;	//Centratore 5: Posizione 3 di cambio velocita'
   C5_Posizione_4 : DINT  := L#1247000;	//Centratore 5: Posizione 4 di arrivo
   C5_Velocita_1 : DINT  := L#50;	//Centratore 5: Velocita' 1 di avvicinamento
   C5_Velocita_2 : DINT  := L#50;	//Centratore 5: Velocita' 2
   C5_Velocita_3 : DINT  := L#50;	//Centratore 5: Velocita' 3
   C5_Velocita_4 : DINT  := L#50;	//Centratore 5: Velocita' 4 di arrivo
   C5_Accell_1 : DINT  := L#500;	//Centratore 5: Accelerazione 1 di avvicinamento
   C5_Accell_2 : DINT  := L#500;	//Centratore 5: Accelerazione 2
   C5_Accell_3 : DINT  := L#500;	//Centratore 5: Accelerazione 3
   C5_Accell_4 : DINT  := L#500;	//Centratore 5: Accelerazione 4 di arrivo
   word_348 : WORD ;
   C6_Posizione_1 : DINT  := L#1180000;	//Centratore 6: Posizione 1 di avicinamento
   C6_Posizione_2 : DINT  := L#1200000;	//Centratore 6: Posizione 2 di cambio velocita'
   C6_Posizione_3 : DINT  := L#1220000;	//Centratore 6: Posizione 3 di cambio velocita'
   C6_Posizione_4 : DINT  := L#1237400;	//Centratore 6: Posizione 4 di arrivo
   C6_Velocita_1 : DINT  := L#50;	//Centratore 6: Velocita' 1 di avvicinamento
   C6_Velocita_2 : DINT  := L#50;	//Centratore 6: Velocita' 2
   C6_Velocita_3 : DINT  := L#50;	//Centratore 6: Velocita' 3
   C6_Velocita_4 : DINT  := L#50;	//Centratore 6: Velocita' 4 di arrivo
   C6_Accell_1 : DINT  := L#500;	//Centratore 6: Accelerazione 1 di avvicinamento
   C6_Accell_2 : DINT  := L#500;	//Centratore 6: Accelerazione 2
   C6_Accell_3 : DINT  := L#500;	//Centratore 6: Accelerazione 3
   C6_Accell_4 : DINT  := L#500;	//Centratore 6: Accelerazione 4 di arrivo
   word_398 : WORD ;
  END_STRUCT ;
BEGIN
   LARGHEZZA_LAMIERA := 3.060000e+003;
   COMPENSAZ_TAV_1 := -7.000000e+001;
   QUOTA_H_SFOGLIATORE := 2.000000e+003;
   QUOTA_H_CENTRATORE := 1.960000e+003;
   word16 := S5T#0MS;
   INCLINAZ_TAVOLA_ESCLUSA := FALSE;
   dword20 := 0.000000e+000;
   dword24 := 0.000000e+000;
   dword28 := 0.000000e+000;
   dword32 := 0.000000e+000;
   dword36 := 0.000000e+000;
   NR_MATRICOLA := 2;
   word42 := W#16#0;
   MAGNETE_1_ESCLUSO := FALSE;
   MAGNETE_2_ESCLUSO := FALSE;
   MAGNETE_3_ESCLUSO := FALSE;
   MAGNETE_4_ESCLUSO := FALSE;
   MAGNETE_5_ESCLUSO := FALSE;
   MAGNETE_6_ESCLUSO := FALSE;
   MAGNETE_LAT_SX_ESCLUSO := FALSE;
   MAGNETE_LAT_DX_ESCLUSO := FALSE;
   COMPENSAZ_TAV_2 := -3.000000e+001;
   STAT22 := W#16#0;
   STAT23 := W#16#0;
   STAT24 := W#16#0;
   STAT25 := W#16#0;
   STAT251 := W#16#0;
   STAT26 := T#0MS;
   STAT29 := T#0MS;
   STAT30 := T#0MS;
   STAT31 := T#0MS;
   C1_Timer := 0.000000e+000;
   C2_Timer := 0.000000e+000;
   C3_Timer := 0.000000e+000;
   C4_Timer := 0.000000e+000;
   C5_Timer := 0.000000e+000;
   C6_Timer := 0.000000e+000;
   C1_Posizione_1 := L#163000;
   C1_Posizione_2 := L#183000;
   C1_Posizione_3 := L#193000;
   C1_Posizione_4 := L#235000;
   C1_Velocita_1 := L#500;
   C1_Velocita_2 := L#200;
   C1_Velocita_3 := L#200;
   C1_Velocita_4 := L#50;
   C1_Accell_1 := L#500;
   C1_Accell_2 := L#500;
   C1_Accell_3 := L#500;
   C1_Accell_4 := L#500;
   word_148 := W#16#0;
   C2_Posizione_1 := L#326000;
   C2_Posizione_2 := L#346000;
   C2_Posizione_3 := L#356000;
   C2_Posizione_4 := L#401000;
   C2_Velocita_1 := L#500;
   C2_Velocita_2 := L#200;
   C2_Velocita_3 := L#200;
   C2_Velocita_4 := L#50;
   C2_Accell_1 := L#500;
   C2_Accell_2 := L#500;
   C2_Accell_3 := L#500;
   C2_Accell_4 := L#500;
   word_198 := W#16#0;
   C3_Posizione_1 := L#200000;
   C3_Posizione_2 := L#220000;
   C3_Posizione_3 := L#230000;
   C3_Posizione_4 := L#385000;
   C3_Velocita_1 := L#500;
   C3_Velocita_2 := L#200;
   C3_Velocita_3 := L#200;
   C3_Velocita_4 := L#50;
   C3_Accell_1 := L#500;
   C3_Accell_2 := L#500;
   C3_Accell_3 := L#500;
   C3_Accell_4 := L#500;
   word_248 := W#16#0;
   C4_Posizione_1 := L#100000;
   C4_Posizione_2 := L#120000;
   C4_Posizione_3 := L#130000;
   C4_Posizione_4 := L#283000;
   C4_Velocita_1 := L#500;
   C4_Velocita_2 := L#200;
   C4_Velocita_3 := L#200;
   C4_Velocita_4 := L#50;
   C4_Accell_1 := L#500;
   C4_Accell_2 := L#500;
   C4_Accell_3 := L#500;
   C4_Accell_4 := L#500;
   word_298 := W#16#0;
   C5_Posizione_1 := L#395000;
   C5_Posizione_2 := L#415000;
   C5_Posizione_3 := L#425000;
   C5_Posizione_4 := L#510000;
   C5_Velocita_1 := L#500;
   C5_Velocita_2 := L#200;
   C5_Velocita_3 := L#200;
   C5_Velocita_4 := L#50;
   C5_Accell_1 := L#500;
   C5_Accell_2 := L#500;
   C5_Accell_3 := L#500;
   C5_Accell_4 := L#500;
   word_348 := W#16#0;
   C6_Posizione_1 := L#430000;
   C6_Posizione_2 := L#450000;
   C6_Posizione_3 := L#460000;
   C6_Posizione_4 := L#525000;
   C6_Velocita_1 := L#500;
   C6_Velocita_2 := L#200;
   C6_Velocita_3 := L#200;
   C6_Velocita_4 := L#50;
   C6_Accell_1 := L#500;
   C6_Accell_2 := L#500;
   C6_Accell_3 := L#500;
   C6_Accell_4 := L#500;
   word_398 := W#16#0;
END_DATA_BLOCK

DATA_BLOCK "MATRICOLA 10"
AUTHOR : Lodato
FAMILY : DESTACK
NAME : DATI
VERSION : 0.1


  STRUCT
   LARGHEZZA_LAMIERA : REAL  := 1.500000e+003;	//LARGHEZZA LAMIERA ATTUALE
   COMPENSAZ_TAV_1 : REAL ;	//COMPENSAZIONE TAVOLA 1
   QUOTA_H_SFOGLIATORE : REAL ;	//Quota impostata altezza sfogliatore
   QUOTA_H_CENTRATORE : REAL ;	//Quota impostata altezza centratore
   word16 : S5TIME ;
   INCLINAZ_TAVOLA_ESCLUSA : BOOL ;	//INCLINAZIONE TAVOLA ESCLUSA
   dword20 : REAL ;
   dword24 : REAL ;
   dword28 : REAL ;
   dword32 : REAL ;
   dword36 : REAL ;
   NR_MATRICOLA : INT  := 1;	//Numero di matricola
   word42 : WORD ;
   MAGNETE_1_ESCLUSO : BOOL ;	//MAGNETE 1 ESCLUSO DA MP270
   MAGNETE_2_ESCLUSO : BOOL ;	//MAGNETE 2 ESCLUSO DA MP270
   MAGNETE_3_ESCLUSO : BOOL ;	//MAGNETE 3 ESCLUSO DA MP270
   MAGNETE_4_ESCLUSO : BOOL ;	//MAGNETE 4 ESCLUSO DA MP270
   MAGNETE_5_ESCLUSO : BOOL ;	//MAGNETE 5 ESCLUSO DA MP270
   MAGNETE_6_ESCLUSO : BOOL ;	//MAGNETE 6 ESCLUSO DA MP270
   MAGNETE_LAT_SX_ESCLUSO : BOOL ;	//MAGNETE LATERALE SX ESCLUSO DA MP270
   MAGNETE_LAT_DX_ESCLUSO : BOOL ;	//MAGNETE LATERALE DX ESCLUSO DA MP270
   COMPENSAZ_TAV_2 : REAL ;	//COMPENSAZIONE TAVOLA 2
   STAT22 : WORD ;
   STAT23 : WORD ;
   STAT24 : WORD ;
   STAT25 : WORD ;
   STAT251 : WORD ;
   STAT26 : TIME ;
   STAT29 : TIME ;
   STAT30 : TIME ;
   STAT31 : TIME ;
   C1_Timer : REAL ;	//Centratore 1: Timer ritardo partenza
   C2_Timer : REAL ;	//Centratore 2: Timer ritardo partenza
   C3_Timer : REAL ;	//Centratore 3: Timer ritardo partenza
   C4_Timer : REAL ;	//Centratore 4: Timer ritardo partenza
   C5_Timer : REAL ;	//Centratore 5: Timer ritardo partenza
   C6_Timer : REAL ;	//Centratore 6: Timer ritardo partenza
   C1_Posizione_1 : DINT  := L#500000;	//Centratore 1: Posizione 1 di avicinamento
   C1_Posizione_2 : DINT  := L#520000;	//Centratore 1: Posizione 2 di cambio velocita'
   C1_Posizione_3 : DINT  := L#530000;	//Centratore 1: Posizione 3 di cambio velocita'
   C1_Posizione_4 : DINT  := L#565400;	//Centratore 1: Posizione 4 di arrivo
   C1_Velocita_1 : DINT  := L#50;	//Centratore 1: Velocita' 1 di avvicinamento
   C1_Velocita_2 : DINT  := L#50;	//Centratore 1: Velocita' 2
   C1_Velocita_3 : DINT  := L#50;	//Centratore 1: Velocita' 3
   C1_Velocita_4 : DINT  := L#50;	//Centratore 1: Velocita' 4 di arrivo
   C1_Accell_1 : DINT  := L#500;	//Centratore 1: Accelerazione 1 di avvicinamento
   C1_Accell_2 : DINT  := L#500;	//Centratore 1: Accelerazione 2
   C1_Accell_3 : DINT  := L#500;	//Centratore 1: Accelerazione 3
   C1_Accell_4 : DINT  := L#500;	//Centratore 1: Accelerazione 4 di arrivo
   word_148 : WORD ;
   C2_Posizione_1 : DINT  := L#500000;	//Centratore 2: Posizione 1 di avicinamento
   C2_Posizione_2 : DINT  := L#520000;	//Centratore 2: Posizione 2 di cambio velocita'
   C2_Posizione_3 : DINT  := L#530000;	//Centratore 2: Posizione 3 di cambio velocita'
   C2_Posizione_4 : DINT  := L#559000;	//Centratore 2: Posizione 4 di arrivo
   C2_Velocita_1 : DINT  := L#50;	//Centratore 2: Velocita' 1 di avvicinamento
   C2_Velocita_2 : DINT  := L#50;	//Centratore 2: Velocita' 2
   C2_Velocita_3 : DINT  := L#50;	//Centratore 2: Velocita' 3
   C2_Velocita_4 : DINT  := L#50;	//Centratore 2: Velocita' 4 di arrivo
   C2_Accell_1 : DINT  := L#500;	//Centratore 2: Accelerazione 1 di avvicinamento
   C2_Accell_2 : DINT  := L#500;	//Centratore 2: Accelerazione 2
   C2_Accell_3 : DINT  := L#500;	//Centratore 2: Accelerazione 3
   C2_Accell_4 : DINT  := L#500;	//Centratore 2: Accelerazione 4 di arrivo
   word_198 : WORD ;
   C3_Posizione_1 : DINT  := L#630000;	//Centratore 3: Posizione 1 di avicinamento
   C3_Posizione_2 : DINT  := L#650000;	//Centratore 3: Posizione 2 di cambio velocita'
   C3_Posizione_3 : DINT  := L#660000;	//Centratore 3: Posizione 3 di cambio velocita'
   C3_Posizione_4 : DINT  := L#698600;	//Centratore 3: Posizione 4 di arrivo
   C3_Velocita_1 : DINT  := L#50;	//Centratore 3: Velocita' 1 di avvicinamento
   C3_Velocita_2 : DINT  := L#50;	//Centratore 3: Velocita' 2
   C3_Velocita_3 : DINT  := L#50;	//Centratore 3: Velocita' 3
   C3_Velocita_4 : DINT  := L#50;	//Centratore 3: Velocita' 4 di arrivo
   C3_Accell_1 : DINT  := L#500;	//Centratore 3: Accelerazione 1 di avvicinamento
   C3_Accell_2 : DINT  := L#500;	//Centratore 3: Accelerazione 2
   C3_Accell_3 : DINT  := L#500;	//Centratore 3: Accelerazione 3
   C3_Accell_4 : DINT  := L#500;	//Centratore 3: Accelerazione 4 di arrivo
   word_248 : WORD ;
   C4_Posizione_1 : DINT  := L#630000;	//Centratore 4: Posizione 1 di avicinamento
   C4_Posizione_2 : DINT  := L#650000;	//Centratore 4: Posizione 2 di cambio velocita'
   C4_Posizione_3 : DINT  := L#660000;	//Centratore 4: Posizione 3 di cambio velocita'
   C4_Posizione_4 : DINT  := L#706200;	//Centratore 4: Posizione 4 di arrivo
   C4_Velocita_1 : DINT  := L#50;	//Centratore 4: Velocita' 1 di avvicinamento
   C4_Velocita_2 : DINT  := L#50;	//Centratore 4: Velocita' 2
   C4_Velocita_3 : DINT  := L#50;	//Centratore 4: Velocita' 3
   C4_Velocita_4 : DINT  := L#50;	//Centratore 4: Velocita' 4 di arrivo
   C4_Accell_1 : DINT  := L#500;	//Centratore 4: Accelerazione 1 di avvicinamento
   C4_Accell_2 : DINT  := L#500;	//Centratore 4: Accelerazione 2
   C4_Accell_3 : DINT  := L#500;	//Centratore 4: Accelerazione 3
   C4_Accell_4 : DINT  := L#500;	//Centratore 4: Accelerazione 4 di arrivo
   word_298 : WORD ;
   C5_Posizione_1 : DINT  := L#1180000;	//Centratore 5: Posizione 1 di avicinamento
   C5_Posizione_2 : DINT  := L#1200000;	//Centratore 5: Posizione 2 di cambio velocita'
   C5_Posizione_3 : DINT  := L#1220000;	//Centratore 5: Posizione 3 di cambio velocita'
   C5_Posizione_4 : DINT  := L#1247000;	//Centratore 5: Posizione 4 di arrivo
   C5_Velocita_1 : DINT  := L#50;	//Centratore 5: Velocita' 1 di avvicinamento
   C5_Velocita_2 : DINT  := L#50;	//Centratore 5: Velocita' 2
   C5_Velocita_3 : DINT  := L#50;	//Centratore 5: Velocita' 3
   C5_Velocita_4 : DINT  := L#50;	//Centratore 5: Velocita' 4 di arrivo
   C5_Accell_1 : DINT  := L#500;	//Centratore 5: Accelerazione 1 di avvicinamento
   C5_Accell_2 : DINT  := L#500;	//Centratore 5: Accelerazione 2
   C5_Accell_3 : DINT  := L#500;	//Centratore 5: Accelerazione 3
   C5_Accell_4 : DINT  := L#500;	//Centratore 5: Accelerazione 4 di arrivo
   word_348 : WORD ;
   C6_Posizione_1 : DINT  := L#1180000;	//Centratore 6: Posizione 1 di avicinamento
   C6_Posizione_2 : DINT  := L#1200000;	//Centratore 6: Posizione 2 di cambio velocita'
   C6_Posizione_3 : DINT  := L#1220000;	//Centratore 6: Posizione 3 di cambio velocita'
   C6_Posizione_4 : DINT  := L#1237400;	//Centratore 6: Posizione 4 di arrivo
   C6_Velocita_1 : DINT  := L#50;	//Centratore 6: Velocita' 1 di avvicinamento
   C6_Velocita_2 : DINT  := L#50;	//Centratore 6: Velocita' 2
   C6_Velocita_3 : DINT  := L#50;	//Centratore 6: Velocita' 3
   C6_Velocita_4 : DINT  := L#50;	//Centratore 6: Velocita' 4 di arrivo
   C6_Accell_1 : DINT  := L#500;	//Centratore 6: Accelerazione 1 di avvicinamento
   C6_Accell_2 : DINT  := L#500;	//Centratore 6: Accelerazione 2
   C6_Accell_3 : DINT  := L#500;	//Centratore 6: Accelerazione 3
   C6_Accell_4 : DINT  := L#500;	//Centratore 6: Accelerazione 4 di arrivo
   word_398 : WORD ;
  END_STRUCT ;
BEGIN
   LARGHEZZA_LAMIERA := 3.060000e+003;
   COMPENSAZ_TAV_1 := -7.000000e+001;
   QUOTA_H_SFOGLIATORE := 2.000000e+003;
   QUOTA_H_CENTRATORE := 1.960000e+003;
   word16 := S5T#0MS;
   INCLINAZ_TAVOLA_ESCLUSA := FALSE;
   dword20 := 0.000000e+000;
   dword24 := 0.000000e+000;
   dword28 := 0.000000e+000;
   dword32 := 0.000000e+000;
   dword36 := 0.000000e+000;
   NR_MATRICOLA := 2;
   word42 := W#16#0;
   MAGNETE_1_ESCLUSO := FALSE;
   MAGNETE_2_ESCLUSO := FALSE;
   MAGNETE_3_ESCLUSO := FALSE;
   MAGNETE_4_ESCLUSO := FALSE;
   MAGNETE_5_ESCLUSO := FALSE;
   MAGNETE_6_ESCLUSO := FALSE;
   MAGNETE_LAT_SX_ESCLUSO := FALSE;
   MAGNETE_LAT_DX_ESCLUSO := FALSE;
   COMPENSAZ_TAV_2 := -3.000000e+001;
   STAT22 := W#16#0;
   STAT23 := W#16#0;
   STAT24 := W#16#0;
   STAT25 := W#16#0;
   STAT251 := W#16#0;
   STAT26 := T#0MS;
   STAT29 := T#0MS;
   STAT30 := T#0MS;
   STAT31 := T#0MS;
   C1_Timer := 0.000000e+000;
   C2_Timer := 0.000000e+000;
   C3_Timer := 0.000000e+000;
   C4_Timer := 0.000000e+000;
   C5_Timer := 0.000000e+000;
   C6_Timer := 0.000000e+000;
   C1_Posizione_1 := L#163000;
   C1_Posizione_2 := L#183000;
   C1_Posizione_3 := L#193000;
   C1_Posizione_4 := L#235000;
   C1_Velocita_1 := L#500;
   C1_Velocita_2 := L#200;
   C1_Velocita_3 := L#200;
   C1_Velocita_4 := L#50;
   C1_Accell_1 := L#500;
   C1_Accell_2 := L#500;
   C1_Accell_3 := L#500;
   C1_Accell_4 := L#500;
   word_148 := W#16#0;
   C2_Posizione_1 := L#326000;
   C2_Posizione_2 := L#346000;
   C2_Posizione_3 := L#356000;
   C2_Posizione_4 := L#401000;
   C2_Velocita_1 := L#500;
   C2_Velocita_2 := L#200;
   C2_Velocita_3 := L#200;
   C2_Velocita_4 := L#50;
   C2_Accell_1 := L#500;
   C2_Accell_2 := L#500;
   C2_Accell_3 := L#500;
   C2_Accell_4 := L#500;
   word_198 := W#16#0;
   C3_Posizione_1 := L#200000;
   C3_Posizione_2 := L#220000;
   C3_Posizione_3 := L#230000;
   C3_Posizione_4 := L#385000;
   C3_Velocita_1 := L#500;
   C3_Velocita_2 := L#200;
   C3_Velocita_3 := L#200;
   C3_Velocita_4 := L#50;
   C3_Accell_1 := L#500;
   C3_Accell_2 := L#500;
   C3_Accell_3 := L#500;
   C3_Accell_4 := L#500;
   word_248 := W#16#0;
   C4_Posizione_1 := L#100000;
   C4_Posizione_2 := L#120000;
   C4_Posizione_3 := L#130000;
   C4_Posizione_4 := L#283000;
   C4_Velocita_1 := L#500;
   C4_Velocita_2 := L#200;
   C4_Velocita_3 := L#200;
   C4_Velocita_4 := L#50;
   C4_Accell_1 := L#500;
   C4_Accell_2 := L#500;
   C4_Accell_3 := L#500;
   C4_Accell_4 := L#500;
   word_298 := W#16#0;
   C5_Posizione_1 := L#395000;
   C5_Posizione_2 := L#415000;
   C5_Posizione_3 := L#425000;
   C5_Posizione_4 := L#510000;
   C5_Velocita_1 := L#500;
   C5_Velocita_2 := L#200;
   C5_Velocita_3 := L#200;
   C5_Velocita_4 := L#50;
   C5_Accell_1 := L#500;
   C5_Accell_2 := L#500;
   C5_Accell_3 := L#500;
   C5_Accell_4 := L#500;
   word_348 := W#16#0;
   C6_Posizione_1 := L#430000;
   C6_Posizione_2 := L#450000;
   C6_Posizione_3 := L#460000;
   C6_Posizione_4 := L#525000;
   C6_Velocita_1 := L#500;
   C6_Velocita_2 := L#200;
   C6_Velocita_3 := L#200;
   C6_Velocita_4 := L#50;
   C6_Accell_1 := L#500;
   C6_Accell_2 := L#500;
   C6_Accell_3 := L#500;
   C6_Accell_4 := L#500;
   word_398 := W#16#0;
END_DATA_BLOCK

DATA_BLOCK "MATRICOLA 11"
AUTHOR : Lodato
FAMILY : DESTACK
NAME : DATI
VERSION : 0.1


  STRUCT
   LARGHEZZA_LAMIERA : REAL  := 1.500000e+003;	//LARGHEZZA LAMIERA ATTUALE
   COMPENSAZ_TAV_1 : REAL ;	//COMPENSAZIONE TAVOLA 1
   QUOTA_H_SFOGLIATORE : REAL ;	//Quota impostata altezza sfogliatore
   QUOTA_H_CENTRATORE : REAL ;	//Quota impostata altezza centratore
   word16 : S5TIME ;
   INCLINAZ_TAVOLA_ESCLUSA : BOOL ;	//INCLINAZIONE TAVOLA ESCLUSA
   dword20 : REAL ;
   dword24 : REAL ;
   dword28 : REAL ;
   dword32 : REAL ;
   dword36 : REAL ;
   NR_MATRICOLA : INT  := 1;	//Numero di matricola
   word42 : WORD ;
   MAGNETE_1_ESCLUSO : BOOL ;	//MAGNETE 1 ESCLUSO DA MP270
   MAGNETE_2_ESCLUSO : BOOL ;	//MAGNETE 2 ESCLUSO DA MP270
   MAGNETE_3_ESCLUSO : BOOL ;	//MAGNETE 3 ESCLUSO DA MP270
   MAGNETE_4_ESCLUSO : BOOL ;	//MAGNETE 4 ESCLUSO DA MP270
   MAGNETE_5_ESCLUSO : BOOL ;	//MAGNETE 5 ESCLUSO DA MP270
   MAGNETE_6_ESCLUSO : BOOL ;	//MAGNETE 6 ESCLUSO DA MP270
   MAGNETE_LAT_SX_ESCLUSO : BOOL ;	//MAGNETE LATERALE SX ESCLUSO DA MP270
   MAGNETE_LAT_DX_ESCLUSO : BOOL ;	//MAGNETE LATERALE DX ESCLUSO DA MP270
   COMPENSAZ_TAV_2 : REAL ;	//COMPENSAZIONE TAVOLA 2
   STAT22 : WORD ;
   STAT23 : WORD ;
   STAT24 : WORD ;
   STAT25 : WORD ;
   STAT251 : WORD ;
   STAT26 : TIME ;
   STAT29 : TIME ;
   STAT30 : TIME ;
   STAT31 : TIME ;
   C1_Timer : REAL ;	//Centratore 1: Timer ritardo partenza
   C2_Timer : REAL ;	//Centratore 2: Timer ritardo partenza
   C3_Timer : REAL ;	//Centratore 3: Timer ritardo partenza
   C4_Timer : REAL ;	//Centratore 4: Timer ritardo partenza
   C5_Timer : REAL ;	//Centratore 5: Timer ritardo partenza
   C6_Timer : REAL ;	//Centratore 6: Timer ritardo partenza
   C1_Posizione_1 : DINT  := L#500000;	//Centratore 1: Posizione 1 di avicinamento
   C1_Posizione_2 : DINT  := L#520000;	//Centratore 1: Posizione 2 di cambio velocita'
   C1_Posizione_3 : DINT  := L#530000;	//Centratore 1: Posizione 3 di cambio velocita'
   C1_Posizione_4 : DINT  := L#565400;	//Centratore 1: Posizione 4 di arrivo
   C1_Velocita_1 : DINT  := L#50;	//Centratore 1: Velocita' 1 di avvicinamento
   C1_Velocita_2 : DINT  := L#50;	//Centratore 1: Velocita' 2
   C1_Velocita_3 : DINT  := L#50;	//Centratore 1: Velocita' 3
   C1_Velocita_4 : DINT  := L#50;	//Centratore 1: Velocita' 4 di arrivo
   C1_Accell_1 : DINT  := L#500;	//Centratore 1: Accelerazione 1 di avvicinamento
   C1_Accell_2 : DINT  := L#500;	//Centratore 1: Accelerazione 2
   C1_Accell_3 : DINT  := L#500;	//Centratore 1: Accelerazione 3
   C1_Accell_4 : DINT  := L#500;	//Centratore 1: Accelerazione 4 di arrivo
   word_148 : WORD ;
   C2_Posizione_1 : DINT  := L#500000;	//Centratore 2: Posizione 1 di avicinamento
   C2_Posizione_2 : DINT  := L#520000;	//Centratore 2: Posizione 2 di cambio velocita'
   C2_Posizione_3 : DINT  := L#530000;	//Centratore 2: Posizione 3 di cambio velocita'
   C2_Posizione_4 : DINT  := L#559000;	//Centratore 2: Posizione 4 di arrivo
   C2_Velocita_1 : DINT  := L#50;	//Centratore 2: Velocita' 1 di avvicinamento
   C2_Velocita_2 : DINT  := L#50;	//Centratore 2: Velocita' 2
   C2_Velocita_3 : DINT  := L#50;	//Centratore 2: Velocita' 3
   C2_Velocita_4 : DINT  := L#50;	//Centratore 2: Velocita' 4 di arrivo
   C2_Accell_1 : DINT  := L#500;	//Centratore 2: Accelerazione 1 di avvicinamento
   C2_Accell_2 : DINT  := L#500;	//Centratore 2: Accelerazione 2
   C2_Accell_3 : DINT  := L#500;	//Centratore 2: Accelerazione 3
   C2_Accell_4 : DINT  := L#500;	//Centratore 2: Accelerazione 4 di arrivo
   word_198 : WORD ;
   C3_Posizione_1 : DINT  := L#630000;	//Centratore 3: Posizione 1 di avicinamento
   C3_Posizione_2 : DINT  := L#650000;	//Centratore 3: Posizione 2 di cambio velocita'
   C3_Posizione_3 : DINT  := L#660000;	//Centratore 3: Posizione 3 di cambio velocita'
   C3_Posizione_4 : DINT  := L#698600;	//Centratore 3: Posizione 4 di arrivo
   C3_Velocita_1 : DINT  := L#50;	//Centratore 3: Velocita' 1 di avvicinamento
   C3_Velocita_2 : DINT  := L#50;	//Centratore 3: Velocita' 2
   C3_Velocita_3 : DINT  := L#50;	//Centratore 3: Velocita' 3
   C3_Velocita_4 : DINT  := L#50;	//Centratore 3: Velocita' 4 di arrivo
   C3_Accell_1 : DINT  := L#500;	//Centratore 3: Accelerazione 1 di avvicinamento
   C3_Accell_2 : DINT  := L#500;	//Centratore 3: Accelerazione 2
   C3_Accell_3 : DINT  := L#500;	//Centratore 3: Accelerazione 3
   C3_Accell_4 : DINT  := L#500;	//Centratore 3: Accelerazione 4 di arrivo
   word_248 : WORD ;
   C4_Posizione_1 : DINT  := L#630000;	//Centratore 4: Posizione 1 di avicinamento
   C4_Posizione_2 : DINT  := L#650000;	//Centratore 4: Posizione 2 di cambio velocita'
   C4_Posizione_3 : DINT  := L#660000;	//Centratore 4: Posizione 3 di cambio velocita'
   C4_Posizione_4 : DINT  := L#706200;	//Centratore 4: Posizione 4 di arrivo
   C4_Velocita_1 : DINT  := L#50;	//Centratore 4: Velocita' 1 di avvicinamento
   C4_Velocita_2 : DINT  := L#50;	//Centratore 4: Velocita' 2
   C4_Velocita_3 : DINT  := L#50;	//Centratore 4: Velocita' 3
   C4_Velocita_4 : DINT  := L#50;	//Centratore 4: Velocita' 4 di arrivo
   C4_Accell_1 : DINT  := L#500;	//Centratore 4: Accelerazione 1 di avvicinamento
   C4_Accell_2 : DINT  := L#500;	//Centratore 4: Accelerazione 2
   C4_Accell_3 : DINT  := L#500;	//Centratore 4: Accelerazione 3
   C4_Accell_4 : DINT  := L#500;	//Centratore 4: Accelerazione 4 di arrivo
   word_298 : WORD ;
   C5_Posizione_1 : DINT  := L#1180000;	//Centratore 5: Posizione 1 di avicinamento
   C5_Posizione_2 : DINT  := L#1200000;	//Centratore 5: Posizione 2 di cambio velocita'
   C5_Posizione_3 : DINT  := L#1220000;	//Centratore 5: Posizione 3 di cambio velocita'
   C5_Posizione_4 : DINT  := L#1247000;	//Centratore 5: Posizione 4 di arrivo
   C5_Velocita_1 : DINT  := L#50;	//Centratore 5: Velocita' 1 di avvicinamento
   C5_Velocita_2 : DINT  := L#50;	//Centratore 5: Velocita' 2
   C5_Velocita_3 : DINT  := L#50;	//Centratore 5: Velocita' 3
   C5_Velocita_4 : DINT  := L#50;	//Centratore 5: Velocita' 4 di arrivo
   C5_Accell_1 : DINT  := L#500;	//Centratore 5: Accelerazione 1 di avvicinamento
   C5_Accell_2 : DINT  := L#500;	//Centratore 5: Accelerazione 2
   C5_Accell_3 : DINT  := L#500;	//Centratore 5: Accelerazione 3
   C5_Accell_4 : DINT  := L#500;	//Centratore 5: Accelerazione 4 di arrivo
   word_348 : WORD ;
   C6_Posizione_1 : DINT  := L#1180000;	//Centratore 6: Posizione 1 di avicinamento
   C6_Posizione_2 : DINT  := L#1200000;	//Centratore 6: Posizione 2 di cambio velocita'
   C6_Posizione_3 : DINT  := L#1220000;	//Centratore 6: Posizione 3 di cambio velocita'
   C6_Posizione_4 : DINT  := L#1237400;	//Centratore 6: Posizione 4 di arrivo
   C6_Velocita_1 : DINT  := L#50;	//Centratore 6: Velocita' 1 di avvicinamento
   C6_Velocita_2 : DINT  := L#50;	//Centratore 6: Velocita' 2
   C6_Velocita_3 : DINT  := L#50;	//Centratore 6: Velocita' 3
   C6_Velocita_4 : DINT  := L#50;	//Centratore 6: Velocita' 4 di arrivo
   C6_Accell_1 : DINT  := L#500;	//Centratore 6: Accelerazione 1 di avvicinamento
   C6_Accell_2 : DINT  := L#500;	//Centratore 6: Accelerazione 2
   C6_Accell_3 : DINT  := L#500;	//Centratore 6: Accelerazione 3
   C6_Accell_4 : DINT  := L#500;	//Centratore 6: Accelerazione 4 di arrivo
   word_398 : WORD ;
  END_STRUCT ;
BEGIN
   LARGHEZZA_LAMIERA := 3.060000e+003;
   COMPENSAZ_TAV_1 := -7.000000e+001;
   QUOTA_H_SFOGLIATORE := 2.000000e+003;
   QUOTA_H_CENTRATORE := 1.960000e+003;
   word16 := S5T#0MS;
   INCLINAZ_TAVOLA_ESCLUSA := FALSE;
   dword20 := 0.000000e+000;
   dword24 := 0.000000e+000;
   dword28 := 0.000000e+000;
   dword32 := 0.000000e+000;
   dword36 := 0.000000e+000;
   NR_MATRICOLA := 2;
   word42 := W#16#0;
   MAGNETE_1_ESCLUSO := FALSE;
   MAGNETE_2_ESCLUSO := FALSE;
   MAGNETE_3_ESCLUSO := FALSE;
   MAGNETE_4_ESCLUSO := FALSE;
   MAGNETE_5_ESCLUSO := FALSE;
   MAGNETE_6_ESCLUSO := FALSE;
   MAGNETE_LAT_SX_ESCLUSO := FALSE;
   MAGNETE_LAT_DX_ESCLUSO := FALSE;
   COMPENSAZ_TAV_2 := -3.000000e+001;
   STAT22 := W#16#0;
   STAT23 := W#16#0;
   STAT24 := W#16#0;
   STAT25 := W#16#0;
   STAT251 := W#16#0;
   STAT26 := T#0MS;
   STAT29 := T#0MS;
   STAT30 := T#0MS;
   STAT31 := T#0MS;
   C1_Timer := 0.000000e+000;
   C2_Timer := 0.000000e+000;
   C3_Timer := 0.000000e+000;
   C4_Timer := 0.000000e+000;
   C5_Timer := 0.000000e+000;
   C6_Timer := 0.000000e+000;
   C1_Posizione_1 := L#163000;
   C1_Posizione_2 := L#183000;
   C1_Posizione_3 := L#193000;
   C1_Posizione_4 := L#235000;
   C1_Velocita_1 := L#500;
   C1_Velocita_2 := L#200;
   C1_Velocita_3 := L#200;
   C1_Velocita_4 := L#50;
   C1_Accell_1 := L#500;
   C1_Accell_2 := L#500;
   C1_Accell_3 := L#500;
   C1_Accell_4 := L#500;
   word_148 := W#16#0;
   C2_Posizione_1 := L#326000;
   C2_Posizione_2 := L#346000;
   C2_Posizione_3 := L#356000;
   C2_Posizione_4 := L#401000;
   C2_Velocita_1 := L#500;
   C2_Velocita_2 := L#200;
   C2_Velocita_3 := L#200;
   C2_Velocita_4 := L#50;
   C2_Accell_1 := L#500;
   C2_Accell_2 := L#500;
   C2_Accell_3 := L#500;
   C2_Accell_4 := L#500;
   word_198 := W#16#0;
   C3_Posizione_1 := L#200000;
   C3_Posizione_2 := L#220000;
   C3_Posizione_3 := L#230000;
   C3_Posizione_4 := L#385000;
   C3_Velocita_1 := L#500;
   C3_Velocita_2 := L#200;
   C3_Velocita_3 := L#200;
   C3_Velocita_4 := L#50;
   C3_Accell_1 := L#500;
   C3_Accell_2 := L#500;
   C3_Accell_3 := L#500;
   C3_Accell_4 := L#500;
   word_248 := W#16#0;
   C4_Posizione_1 := L#100000;
   C4_Posizione_2 := L#120000;
   C4_Posizione_3 := L#130000;
   C4_Posizione_4 := L#283000;
   C4_Velocita_1 := L#500;
   C4_Velocita_2 := L#200;
   C4_Velocita_3 := L#200;
   C4_Velocita_4 := L#50;
   C4_Accell_1 := L#500;
   C4_Accell_2 := L#500;
   C4_Accell_3 := L#500;
   C4_Accell_4 := L#500;
   word_298 := W#16#0;
   C5_Posizione_1 := L#395000;
   C5_Posizione_2 := L#415000;
   C5_Posizione_3 := L#425000;
   C5_Posizione_4 := L#510000;
   C5_Velocita_1 := L#500;
   C5_Velocita_2 := L#200;
   C5_Velocita_3 := L#200;
   C5_Velocita_4 := L#50;
   C5_Accell_1 := L#500;
   C5_Accell_2 := L#500;
   C5_Accell_3 := L#500;
   C5_Accell_4 := L#500;
   word_348 := W#16#0;
   C6_Posizione_1 := L#430000;
   C6_Posizione_2 := L#450000;
   C6_Posizione_3 := L#460000;
   C6_Posizione_4 := L#525000;
   C6_Velocita_1 := L#500;
   C6_Velocita_2 := L#200;
   C6_Velocita_3 := L#200;
   C6_Velocita_4 := L#50;
   C6_Accell_1 := L#500;
   C6_Accell_2 := L#500;
   C6_Accell_3 := L#500;
   C6_Accell_4 := L#500;
   word_398 := W#16#0;
END_DATA_BLOCK

DATA_BLOCK "MATRICOLA 12"
AUTHOR : Lodato
FAMILY : DESTACK
NAME : DATI
VERSION : 0.1


  STRUCT
   LARGHEZZA_LAMIERA : REAL  := 1.500000e+003;	//LARGHEZZA LAMIERA ATTUALE
   COMPENSAZ_TAV_1 : REAL ;	//COMPENSAZIONE TAVOLA 1
   QUOTA_H_SFOGLIATORE : REAL ;	//Quota impostata altezza sfogliatore
   QUOTA_H_CENTRATORE : REAL ;	//Quota impostata altezza centratore
   word16 : S5TIME ;
   INCLINAZ_TAVOLA_ESCLUSA : BOOL ;	//INCLINAZIONE TAVOLA ESCLUSA
   dword20 : REAL ;
   dword24 : REAL ;
   dword28 : REAL ;
   dword32 : REAL ;
   dword36 : REAL ;
   NR_MATRICOLA : INT  := 1;	//Numero di matricola
   word42 : WORD ;
   MAGNETE_1_ESCLUSO : BOOL ;	//MAGNETE 1 ESCLUSO DA MP270
   MAGNETE_2_ESCLUSO : BOOL ;	//MAGNETE 2 ESCLUSO DA MP270
   MAGNETE_3_ESCLUSO : BOOL ;	//MAGNETE 3 ESCLUSO DA MP270
   MAGNETE_4_ESCLUSO : BOOL ;	//MAGNETE 4 ESCLUSO DA MP270
   MAGNETE_5_ESCLUSO : BOOL ;	//MAGNETE 5 ESCLUSO DA MP270
   MAGNETE_6_ESCLUSO : BOOL ;	//MAGNETE 6 ESCLUSO DA MP270
   MAGNETE_LAT_SX_ESCLUSO : BOOL ;	//MAGNETE LATERALE SX ESCLUSO DA MP270
   MAGNETE_LAT_DX_ESCLUSO : BOOL ;	//MAGNETE LATERALE DX ESCLUSO DA MP270
   COMPENSAZ_TAV_2 : REAL ;	//COMPENSAZIONE TAVOLA 2
   STAT22 : WORD ;
   STAT23 : WORD ;
   STAT24 : WORD ;
   STAT25 : WORD ;
   STAT251 : WORD ;
   STAT26 : TIME ;
   STAT29 : TIME ;
   STAT30 : TIME ;
   STAT31 : TIME ;
   C1_Timer : REAL ;	//Centratore 1: Timer ritardo partenza
   C2_Timer : REAL ;	//Centratore 2: Timer ritardo partenza
   C3_Timer : REAL ;	//Centratore 3: Timer ritardo partenza
   C4_Timer : REAL ;	//Centratore 4: Timer ritardo partenza
   C5_Timer : REAL ;	//Centratore 5: Timer ritardo partenza
   C6_Timer : REAL ;	//Centratore 6: Timer ritardo partenza
   C1_Posizione_1 : DINT  := L#500000;	//Centratore 1: Posizione 1 di avicinamento
   C1_Posizione_2 : DINT  := L#520000;	//Centratore 1: Posizione 2 di cambio velocita'
   C1_Posizione_3 : DINT  := L#530000;	//Centratore 1: Posizione 3 di cambio velocita'
   C1_Posizione_4 : DINT  := L#565400;	//Centratore 1: Posizione 4 di arrivo
   C1_Velocita_1 : DINT  := L#50;	//Centratore 1: Velocita' 1 di avvicinamento
   C1_Velocita_2 : DINT  := L#50;	//Centratore 1: Velocita' 2
   C1_Velocita_3 : DINT  := L#50;	//Centratore 1: Velocita' 3
   C1_Velocita_4 : DINT  := L#50;	//Centratore 1: Velocita' 4 di arrivo
   C1_Accell_1 : DINT  := L#500;	//Centratore 1: Accelerazione 1 di avvicinamento
   C1_Accell_2 : DINT  := L#500;	//Centratore 1: Accelerazione 2
   C1_Accell_3 : DINT  := L#500;	//Centratore 1: Accelerazione 3
   C1_Accell_4 : DINT  := L#500;	//Centratore 1: Accelerazione 4 di arrivo
   word_148 : WORD ;
   C2_Posizione_1 : DINT  := L#500000;	//Centratore 2: Posizione 1 di avicinamento
   C2_Posizione_2 : DINT  := L#520000;	//Centratore 2: Posizione 2 di cambio velocita'
   C2_Posizione_3 : DINT  := L#530000;	//Centratore 2: Posizione 3 di cambio velocita'
   C2_Posizione_4 : DINT  := L#559000;	//Centratore 2: Posizione 4 di arrivo
   C2_Velocita_1 : DINT  := L#50;	//Centratore 2: Velocita' 1 di avvicinamento
   C2_Velocita_2 : DINT  := L#50;	//Centratore 2: Velocita' 2
   C2_Velocita_3 : DINT  := L#50;	//Centratore 2: Velocita' 3
   C2_Velocita_4 : DINT  := L#50;	//Centratore 2: Velocita' 4 di arrivo
   C2_Accell_1 : DINT  := L#500;	//Centratore 2: Accelerazione 1 di avvicinamento
   C2_Accell_2 : DINT  := L#500;	//Centratore 2: Accelerazione 2
   C2_Accell_3 : DINT  := L#500;	//Centratore 2: Accelerazione 3
   C2_Accell_4 : DINT  := L#500;	//Centratore 2: Accelerazione 4 di arrivo
   word_198 : WORD ;
   C3_Posizione_1 : DINT  := L#630000;	//Centratore 3: Posizione 1 di avicinamento
   C3_Posizione_2 : DINT  := L#650000;	//Centratore 3: Posizione 2 di cambio velocita'
   C3_Posizione_3 : DINT  := L#660000;	//Centratore 3: Posizione 3 di cambio velocita'
   C3_Posizione_4 : DINT  := L#698600;	//Centratore 3: Posizione 4 di arrivo
   C3_Velocita_1 : DINT  := L#50;	//Centratore 3: Velocita' 1 di avvicinamento
   C3_Velocita_2 : DINT  := L#50;	//Centratore 3: Velocita' 2
   C3_Velocita_3 : DINT  := L#50;	//Centratore 3: Velocita' 3
   C3_Velocita_4 : DINT  := L#50;	//Centratore 3: Velocita' 4 di arrivo
   C3_Accell_1 : DINT  := L#500;	//Centratore 3: Accelerazione 1 di avvicinamento
   C3_Accell_2 : DINT  := L#500;	//Centratore 3: Accelerazione 2
   C3_Accell_3 : DINT  := L#500;	//Centratore 3: Accelerazione 3
   C3_Accell_4 : DINT  := L#500;	//Centratore 3: Accelerazione 4 di arrivo
   word_248 : WORD ;
   C4_Posizione_1 : DINT  := L#630000;	//Centratore 4: Posizione 1 di avicinamento
   C4_Posizione_2 : DINT  := L#650000;	//Centratore 4: Posizione 2 di cambio velocita'
   C4_Posizione_3 : DINT  := L#660000;	//Centratore 4: Posizione 3 di cambio velocita'
   C4_Posizione_4 : DINT  := L#706200;	//Centratore 4: Posizione 4 di arrivo
   C4_Velocita_1 : DINT  := L#50;	//Centratore 4: Velocita' 1 di avvicinamento
   C4_Velocita_2 : DINT  := L#50;	//Centratore 4: Velocita' 2
   C4_Velocita_3 : DINT  := L#50;	//Centratore 4: Velocita' 3
   C4_Velocita_4 : DINT  := L#50;	//Centratore 4: Velocita' 4 di arrivo
   C4_Accell_1 : DINT  := L#500;	//Centratore 4: Accelerazione 1 di avvicinamento
   C4_Accell_2 : DINT  := L#500;	//Centratore 4: Accelerazione 2
   C4_Accell_3 : DINT  := L#500;	//Centratore 4: Accelerazione 3
   C4_Accell_4 : DINT  := L#500;	//Centratore 4: Accelerazione 4 di arrivo
   word_298 : WORD ;
   C5_Posizione_1 : DINT  := L#1180000;	//Centratore 5: Posizione 1 di avicinamento
   C5_Posizione_2 : DINT  := L#1200000;	//Centratore 5: Posizione 2 di cambio velocita'
   C5_Posizione_3 : DINT  := L#1220000;	//Centratore 5: Posizione 3 di cambio velocita'
   C5_Posizione_4 : DINT  := L#1247000;	//Centratore 5: Posizione 4 di arrivo
   C5_Velocita_1 : DINT  := L#50;	//Centratore 5: Velocita' 1 di avvicinamento
   C5_Velocita_2 : DINT  := L#50;	//Centratore 5: Velocita' 2
   C5_Velocita_3 : DINT  := L#50;	//Centratore 5: Velocita' 3
   C5_Velocita_4 : DINT  := L#50;	//Centratore 5: Velocita' 4 di arrivo
   C5_Accell_1 : DINT  := L#500;	//Centratore 5: Accelerazione 1 di avvicinamento
   C5_Accell_2 : DINT  := L#500;	//Centratore 5: Accelerazione 2
   C5_Accell_3 : DINT  := L#500;	//Centratore 5: Accelerazione 3
   C5_Accell_4 : DINT  := L#500;	//Centratore 5: Accelerazione 4 di arrivo
   word_348 : WORD ;
   C6_Posizione_1 : DINT  := L#1180000;	//Centratore 6: Posizione 1 di avicinamento
   C6_Posizione_2 : DINT  := L#1200000;	//Centratore 6: Posizione 2 di cambio velocita'
   C6_Posizione_3 : DINT  := L#1220000;	//Centratore 6: Posizione 3 di cambio velocita'
   C6_Posizione_4 : DINT  := L#1237400;	//Centratore 6: Posizione 4 di arrivo
   C6_Velocita_1 : DINT  := L#50;	//Centratore 6: Velocita' 1 di avvicinamento
   C6_Velocita_2 : DINT  := L#50;	//Centratore 6: Velocita' 2
   C6_Velocita_3 : DINT  := L#50;	//Centratore 6: Velocita' 3
   C6_Velocita_4 : DINT  := L#50;	//Centratore 6: Velocita' 4 di arrivo
   C6_Accell_1 : DINT  := L#500;	//Centratore 6: Accelerazione 1 di avvicinamento
   C6_Accell_2 : DINT  := L#500;	//Centratore 6: Accelerazione 2
   C6_Accell_3 : DINT  := L#500;	//Centratore 6: Accelerazione 3
   C6_Accell_4 : DINT  := L#500;	//Centratore 6: Accelerazione 4 di arrivo
   word_398 : WORD ;
  END_STRUCT ;
BEGIN
   LARGHEZZA_LAMIERA := 3.060000e+003;
   COMPENSAZ_TAV_1 := -7.000000e+001;
   QUOTA_H_SFOGLIATORE := 2.000000e+003;
   QUOTA_H_CENTRATORE := 1.960000e+003;
   word16 := S5T#0MS;
   INCLINAZ_TAVOLA_ESCLUSA := FALSE;
   dword20 := 0.000000e+000;
   dword24 := 0.000000e+000;
   dword28 := 0.000000e+000;
   dword32 := 0.000000e+000;
   dword36 := 0.000000e+000;
   NR_MATRICOLA := 2;
   word42 := W#16#0;
   MAGNETE_1_ESCLUSO := FALSE;
   MAGNETE_2_ESCLUSO := FALSE;
   MAGNETE_3_ESCLUSO := FALSE;
   MAGNETE_4_ESCLUSO := FALSE;
   MAGNETE_5_ESCLUSO := FALSE;
   MAGNETE_6_ESCLUSO := FALSE;
   MAGNETE_LAT_SX_ESCLUSO := FALSE;
   MAGNETE_LAT_DX_ESCLUSO := FALSE;
   COMPENSAZ_TAV_2 := -3.000000e+001;
   STAT22 := W#16#0;
   STAT23 := W#16#0;
   STAT24 := W#16#0;
   STAT25 := W#16#0;
   STAT251 := W#16#0;
   STAT26 := T#0MS;
   STAT29 := T#0MS;
   STAT30 := T#0MS;
   STAT31 := T#0MS;
   C1_Timer := 0.000000e+000;
   C2_Timer := 0.000000e+000;
   C3_Timer := 0.000000e+000;
   C4_Timer := 0.000000e+000;
   C5_Timer := 0.000000e+000;
   C6_Timer := 0.000000e+000;
   C1_Posizione_1 := L#163000;
   C1_Posizione_2 := L#183000;
   C1_Posizione_3 := L#193000;
   C1_Posizione_4 := L#235000;
   C1_Velocita_1 := L#500;
   C1_Velocita_2 := L#200;
   C1_Velocita_3 := L#200;
   C1_Velocita_4 := L#50;
   C1_Accell_1 := L#500;
   C1_Accell_2 := L#500;
   C1_Accell_3 := L#500;
   C1_Accell_4 := L#500;
   word_148 := W#16#0;
   C2_Posizione_1 := L#326000;
   C2_Posizione_2 := L#346000;
   C2_Posizione_3 := L#356000;
   C2_Posizione_4 := L#401000;
   C2_Velocita_1 := L#500;
   C2_Velocita_2 := L#200;
   C2_Velocita_3 := L#200;
   C2_Velocita_4 := L#50;
   C2_Accell_1 := L#500;
   C2_Accell_2 := L#500;
   C2_Accell_3 := L#500;
   C2_Accell_4 := L#500;
   word_198 := W#16#0;
   C3_Posizione_1 := L#200000;
   C3_Posizione_2 := L#220000;
   C3_Posizione_3 := L#230000;
   C3_Posizione_4 := L#385000;
   C3_Velocita_1 := L#500;
   C3_Velocita_2 := L#200;
   C3_Velocita_3 := L#200;
   C3_Velocita_4 := L#50;
   C3_Accell_1 := L#500;
   C3_Accell_2 := L#500;
   C3_Accell_3 := L#500;
   C3_Accell_4 := L#500;
   word_248 := W#16#0;
   C4_Posizione_1 := L#100000;
   C4_Posizione_2 := L#120000;
   C4_Posizione_3 := L#130000;
   C4_Posizione_4 := L#283000;
   C4_Velocita_1 := L#500;
   C4_Velocita_2 := L#200;
   C4_Velocita_3 := L#200;
   C4_Velocita_4 := L#50;
   C4_Accell_1 := L#500;
   C4_Accell_2 := L#500;
   C4_Accell_3 := L#500;
   C4_Accell_4 := L#500;
   word_298 := W#16#0;
   C5_Posizione_1 := L#395000;
   C5_Posizione_2 := L#415000;
   C5_Posizione_3 := L#425000;
   C5_Posizione_4 := L#510000;
   C5_Velocita_1 := L#500;
   C5_Velocita_2 := L#200;
   C5_Velocita_3 := L#200;
   C5_Velocita_4 := L#50;
   C5_Accell_1 := L#500;
   C5_Accell_2 := L#500;
   C5_Accell_3 := L#500;
   C5_Accell_4 := L#500;
   word_348 := W#16#0;
   C6_Posizione_1 := L#430000;
   C6_Posizione_2 := L#450000;
   C6_Posizione_3 := L#460000;
   C6_Posizione_4 := L#525000;
   C6_Velocita_1 := L#500;
   C6_Velocita_2 := L#200;
   C6_Velocita_3 := L#200;
   C6_Velocita_4 := L#50;
   C6_Accell_1 := L#500;
   C6_Accell_2 := L#500;
   C6_Accell_3 := L#500;
   C6_Accell_4 := L#500;
   word_398 := W#16#0;
END_DATA_BLOCK

DATA_BLOCK "MATRICOLA 13"
AUTHOR : Lodato
FAMILY : DESTACK
NAME : DATI
VERSION : 0.1


  STRUCT
   LARGHEZZA_LAMIERA : REAL  := 1.500000e+003;	//LARGHEZZA LAMIERA ATTUALE
   COMPENSAZ_TAV_1 : REAL ;	//COMPENSAZIONE TAVOLA 1
   QUOTA_H_SFOGLIATORE : REAL ;	//Quota impostata altezza sfogliatore
   QUOTA_H_CENTRATORE : REAL ;	//Quota impostata altezza centratore
   word16 : S5TIME ;
   INCLINAZ_TAVOLA_ESCLUSA : BOOL ;	//INCLINAZIONE TAVOLA ESCLUSA
   dword20 : REAL ;
   dword24 : REAL ;
   dword28 : REAL ;
   dword32 : REAL ;
   dword36 : REAL ;
   NR_MATRICOLA : INT  := 1;	//Numero di matricola
   word42 : WORD ;
   MAGNETE_1_ESCLUSO : BOOL ;	//MAGNETE 1 ESCLUSO DA MP270
   MAGNETE_2_ESCLUSO : BOOL ;	//MAGNETE 2 ESCLUSO DA MP270
   MAGNETE_3_ESCLUSO : BOOL ;	//MAGNETE 3 ESCLUSO DA MP270
   MAGNETE_4_ESCLUSO : BOOL ;	//MAGNETE 4 ESCLUSO DA MP270
   MAGNETE_5_ESCLUSO : BOOL ;	//MAGNETE 5 ESCLUSO DA MP270
   MAGNETE_6_ESCLUSO : BOOL ;	//MAGNETE 6 ESCLUSO DA MP270
   MAGNETE_LAT_SX_ESCLUSO : BOOL ;	//MAGNETE LATERALE SX ESCLUSO DA MP270
   MAGNETE_LAT_DX_ESCLUSO : BOOL ;	//MAGNETE LATERALE DX ESCLUSO DA MP270
   COMPENSAZ_TAV_2 : REAL ;	//COMPENSAZIONE TAVOLA 2
   STAT22 : WORD ;
   STAT23 : WORD ;
   STAT24 : WORD ;
   STAT25 : WORD ;
   STAT251 : WORD ;
   STAT26 : TIME ;
   STAT29 : TIME ;
   STAT30 : TIME ;
   STAT31 : TIME ;
   C1_Timer : REAL ;	//Centratore 1: Timer ritardo partenza
   C2_Timer : REAL ;	//Centratore 2: Timer ritardo partenza
   C3_Timer : REAL ;	//Centratore 3: Timer ritardo partenza
   C4_Timer : REAL ;	//Centratore 4: Timer ritardo partenza
   C5_Timer : REAL ;	//Centratore 5: Timer ritardo partenza
   C6_Timer : REAL ;	//Centratore 6: Timer ritardo partenza
   C1_Posizione_1 : DINT  := L#500000;	//Centratore 1: Posizione 1 di avicinamento
   C1_Posizione_2 : DINT  := L#520000;	//Centratore 1: Posizione 2 di cambio velocita'
   C1_Posizione_3 : DINT  := L#530000;	//Centratore 1: Posizione 3 di cambio velocita'
   C1_Posizione_4 : DINT  := L#565400;	//Centratore 1: Posizione 4 di arrivo
   C1_Velocita_1 : DINT  := L#50;	//Centratore 1: Velocita' 1 di avvicinamento
   C1_Velocita_2 : DINT  := L#50;	//Centratore 1: Velocita' 2
   C1_Velocita_3 : DINT  := L#50;	//Centratore 1: Velocita' 3
   C1_Velocita_4 : DINT  := L#50;	//Centratore 1: Velocita' 4 di arrivo
   C1_Accell_1 : DINT  := L#500;	//Centratore 1: Accelerazione 1 di avvicinamento
   C1_Accell_2 : DINT  := L#500;	//Centratore 1: Accelerazione 2
   C1_Accell_3 : DINT  := L#500;	//Centratore 1: Accelerazione 3
   C1_Accell_4 : DINT  := L#500;	//Centratore 1: Accelerazione 4 di arrivo
   word_148 : WORD ;
   C2_Posizione_1 : DINT  := L#500000;	//Centratore 2: Posizione 1 di avicinamento
   C2_Posizione_2 : DINT  := L#520000;	//Centratore 2: Posizione 2 di cambio velocita'
   C2_Posizione_3 : DINT  := L#530000;	//Centratore 2: Posizione 3 di cambio velocita'
   C2_Posizione_4 : DINT  := L#559000;	//Centratore 2: Posizione 4 di arrivo
   C2_Velocita_1 : DINT  := L#50;	//Centratore 2: Velocita' 1 di avvicinamento
   C2_Velocita_2 : DINT  := L#50;	//Centratore 2: Velocita' 2
   C2_Velocita_3 : DINT  := L#50;	//Centratore 2: Velocita' 3
   C2_Velocita_4 : DINT  := L#50;	//Centratore 2: Velocita' 4 di arrivo
   C2_Accell_1 : DINT  := L#500;	//Centratore 2: Accelerazione 1 di avvicinamento
   C2_Accell_2 : DINT  := L#500;	//Centratore 2: Accelerazione 2
   C2_Accell_3 : DINT  := L#500;	//Centratore 2: Accelerazione 3
   C2_Accell_4 : DINT  := L#500;	//Centratore 2: Accelerazione 4 di arrivo
   word_198 : WORD ;
   C3_Posizione_1 : DINT  := L#630000;	//Centratore 3: Posizione 1 di avicinamento
   C3_Posizione_2 : DINT  := L#650000;	//Centratore 3: Posizione 2 di cambio velocita'
   C3_Posizione_3 : DINT  := L#660000;	//Centratore 3: Posizione 3 di cambio velocita'
   C3_Posizione_4 : DINT  := L#698600;	//Centratore 3: Posizione 4 di arrivo
   C3_Velocita_1 : DINT  := L#50;	//Centratore 3: Velocita' 1 di avvicinamento
   C3_Velocita_2 : DINT  := L#50;	//Centratore 3: Velocita' 2
   C3_Velocita_3 : DINT  := L#50;	//Centratore 3: Velocita' 3
   C3_Velocita_4 : DINT  := L#50;	//Centratore 3: Velocita' 4 di arrivo
   C3_Accell_1 : DINT  := L#500;	//Centratore 3: Accelerazione 1 di avvicinamento
   C3_Accell_2 : DINT  := L#500;	//Centratore 3: Accelerazione 2
   C3_Accell_3 : DINT  := L#500;	//Centratore 3: Accelerazione 3
   C3_Accell_4 : DINT  := L#500;	//Centratore 3: Accelerazione 4 di arrivo
   word_248 : WORD ;
   C4_Posizione_1 : DINT  := L#630000;	//Centratore 4: Posizione 1 di avicinamento
   C4_Posizione_2 : DINT  := L#650000;	//Centratore 4: Posizione 2 di cambio velocita'
   C4_Posizione_3 : DINT  := L#660000;	//Centratore 4: Posizione 3 di cambio velocita'
   C4_Posizione_4 : DINT  := L#706200;	//Centratore 4: Posizione 4 di arrivo
   C4_Velocita_1 : DINT  := L#50;	//Centratore 4: Velocita' 1 di avvicinamento
   C4_Velocita_2 : DINT  := L#50;	//Centratore 4: Velocita' 2
   C4_Velocita_3 : DINT  := L#50;	//Centratore 4: Velocita' 3
   C4_Velocita_4 : DINT  := L#50;	//Centratore 4: Velocita' 4 di arrivo
   C4_Accell_1 : DINT  := L#500;	//Centratore 4: Accelerazione 1 di avvicinamento
   C4_Accell_2 : DINT  := L#500;	//Centratore 4: Accelerazione 2
   C4_Accell_3 : DINT  := L#500;	//Centratore 4: Accelerazione 3
   C4_Accell_4 : DINT  := L#500;	//Centratore 4: Accelerazione 4 di arrivo
   word_298 : WORD ;
   C5_Posizione_1 : DINT  := L#1180000;	//Centratore 5: Posizione 1 di avicinamento
   C5_Posizione_2 : DINT  := L#1200000;	//Centratore 5: Posizione 2 di cambio velocita'
   C5_Posizione_3 : DINT  := L#1220000;	//Centratore 5: Posizione 3 di cambio velocita'
   C5_Posizione_4 : DINT  := L#1247000;	//Centratore 5: Posizione 4 di arrivo
   C5_Velocita_1 : DINT  := L#50;	//Centratore 5: Velocita' 1 di avvicinamento
   C5_Velocita_2 : DINT  := L#50;	//Centratore 5: Velocita' 2
   C5_Velocita_3 : DINT  := L#50;	//Centratore 5: Velocita' 3
   C5_Velocita_4 : DINT  := L#50;	//Centratore 5: Velocita' 4 di arrivo
   C5_Accell_1 : DINT  := L#500;	//Centratore 5: Accelerazione 1 di avvicinamento
   C5_Accell_2 : DINT  := L#500;	//Centratore 5: Accelerazione 2
   C5_Accell_3 : DINT  := L#500;	//Centratore 5: Accelerazione 3
   C5_Accell_4 : DINT  := L#500;	//Centratore 5: Accelerazione 4 di arrivo
   word_348 : WORD ;
   C6_Posizione_1 : DINT  := L#1180000;	//Centratore 6: Posizione 1 di avicinamento
   C6_Posizione_2 : DINT  := L#1200000;	//Centratore 6: Posizione 2 di cambio velocita'
   C6_Posizione_3 : DINT  := L#1220000;	//Centratore 6: Posizione 3 di cambio velocita'
   C6_Posizione_4 : DINT  := L#1237400;	//Centratore 6: Posizione 4 di arrivo
   C6_Velocita_1 : DINT  := L#50;	//Centratore 6: Velocita' 1 di avvicinamento
   C6_Velocita_2 : DINT  := L#50;	//Centratore 6: Velocita' 2
   C6_Velocita_3 : DINT  := L#50;	//Centratore 6: Velocita' 3
   C6_Velocita_4 : DINT  := L#50;	//Centratore 6: Velocita' 4 di arrivo
   C6_Accell_1 : DINT  := L#500;	//Centratore 6: Accelerazione 1 di avvicinamento
   C6_Accell_2 : DINT  := L#500;	//Centratore 6: Accelerazione 2
   C6_Accell_3 : DINT  := L#500;	//Centratore 6: Accelerazione 3
   C6_Accell_4 : DINT  := L#500;	//Centratore 6: Accelerazione 4 di arrivo
   word_398 : WORD ;
  END_STRUCT ;
BEGIN
   LARGHEZZA_LAMIERA := 3.060000e+003;
   COMPENSAZ_TAV_1 := -7.000000e+001;
   QUOTA_H_SFOGLIATORE := 2.000000e+003;
   QUOTA_H_CENTRATORE := 1.960000e+003;
   word16 := S5T#0MS;
   INCLINAZ_TAVOLA_ESCLUSA := FALSE;
   dword20 := 0.000000e+000;
   dword24 := 0.000000e+000;
   dword28 := 0.000000e+000;
   dword32 := 0.000000e+000;
   dword36 := 0.000000e+000;
   NR_MATRICOLA := 2;
   word42 := W#16#0;
   MAGNETE_1_ESCLUSO := FALSE;
   MAGNETE_2_ESCLUSO := FALSE;
   MAGNETE_3_ESCLUSO := FALSE;
   MAGNETE_4_ESCLUSO := FALSE;
   MAGNETE_5_ESCLUSO := FALSE;
   MAGNETE_6_ESCLUSO := FALSE;
   MAGNETE_LAT_SX_ESCLUSO := FALSE;
   MAGNETE_LAT_DX_ESCLUSO := FALSE;
   COMPENSAZ_TAV_2 := -3.000000e+001;
   STAT22 := W#16#0;
   STAT23 := W#16#0;
   STAT24 := W#16#0;
   STAT25 := W#16#0;
   STAT251 := W#16#0;
   STAT26 := T#0MS;
   STAT29 := T#0MS;
   STAT30 := T#0MS;
   STAT31 := T#0MS;
   C1_Timer := 0.000000e+000;
   C2_Timer := 0.000000e+000;
   C3_Timer := 0.000000e+000;
   C4_Timer := 0.000000e+000;
   C5_Timer := 0.000000e+000;
   C6_Timer := 0.000000e+000;
   C1_Posizione_1 := L#163000;
   C1_Posizione_2 := L#183000;
   C1_Posizione_3 := L#193000;
   C1_Posizione_4 := L#235000;
   C1_Velocita_1 := L#500;
   C1_Velocita_2 := L#200;
   C1_Velocita_3 := L#200;
   C1_Velocita_4 := L#50;
   C1_Accell_1 := L#500;
   C1_Accell_2 := L#500;
   C1_Accell_3 := L#500;
   C1_Accell_4 := L#500;
   word_148 := W#16#0;
   C2_Posizione_1 := L#326000;
   C2_Posizione_2 := L#346000;
   C2_Posizione_3 := L#356000;
   C2_Posizione_4 := L#401000;
   C2_Velocita_1 := L#500;
   C2_Velocita_2 := L#200;
   C2_Velocita_3 := L#200;
   C2_Velocita_4 := L#50;
   C2_Accell_1 := L#500;
   C2_Accell_2 := L#500;
   C2_Accell_3 := L#500;
   C2_Accell_4 := L#500;
   word_198 := W#16#0;
   C3_Posizione_1 := L#200000;
   C3_Posizione_2 := L#220000;
   C3_Posizione_3 := L#230000;
   C3_Posizione_4 := L#385000;
   C3_Velocita_1 := L#500;
   C3_Velocita_2 := L#200;
   C3_Velocita_3 := L#200;
   C3_Velocita_4 := L#50;
   C3_Accell_1 := L#500;
   C3_Accell_2 := L#500;
   C3_Accell_3 := L#500;
   C3_Accell_4 := L#500;
   word_248 := W#16#0;
   C4_Posizione_1 := L#100000;
   C4_Posizione_2 := L#120000;
   C4_Posizione_3 := L#130000;
   C4_Posizione_4 := L#283000;
   C4_Velocita_1 := L#500;
   C4_Velocita_2 := L#200;
   C4_Velocita_3 := L#200;
   C4_Velocita_4 := L#50;
   C4_Accell_1 := L#500;
   C4_Accell_2 := L#500;
   C4_Accell_3 := L#500;
   C4_Accell_4 := L#500;
   word_298 := W#16#0;
   C5_Posizione_1 := L#395000;
   C5_Posizione_2 := L#415000;
   C5_Posizione_3 := L#425000;
   C5_Posizione_4 := L#510000;
   C5_Velocita_1 := L#500;
   C5_Velocita_2 := L#200;
   C5_Velocita_3 := L#200;
   C5_Velocita_4 := L#50;
   C5_Accell_1 := L#500;
   C5_Accell_2 := L#500;
   C5_Accell_3 := L#500;
   C5_Accell_4 := L#500;
   word_348 := W#16#0;
   C6_Posizione_1 := L#430000;
   C6_Posizione_2 := L#450000;
   C6_Posizione_3 := L#460000;
   C6_Posizione_4 := L#525000;
   C6_Velocita_1 := L#500;
   C6_Velocita_2 := L#200;
   C6_Velocita_3 := L#200;
   C6_Velocita_4 := L#50;
   C6_Accell_1 := L#500;
   C6_Accell_2 := L#500;
   C6_Accell_3 := L#500;
   C6_Accell_4 := L#500;
   word_398 := W#16#0;
END_DATA_BLOCK

DATA_BLOCK "MATRICOLA 14"
AUTHOR : Lodato
FAMILY : DESTACK
NAME : DATI
VERSION : 0.1


  STRUCT
   LARGHEZZA_LAMIERA : REAL  := 1.500000e+003;	//LARGHEZZA LAMIERA ATTUALE
   COMPENSAZ_TAV_1 : REAL ;	//COMPENSAZIONE TAVOLA 1
   QUOTA_H_SFOGLIATORE : REAL ;	//Quota impostata altezza sfogliatore
   QUOTA_H_CENTRATORE : REAL ;	//Quota impostata altezza centratore
   word16 : S5TIME ;
   INCLINAZ_TAVOLA_ESCLUSA : BOOL ;	//INCLINAZIONE TAVOLA ESCLUSA
   dword20 : REAL ;
   dword24 : REAL ;
   dword28 : REAL ;
   dword32 : REAL ;
   dword36 : REAL ;
   NR_MATRICOLA : INT  := 1;	//Numero di matricola
   word42 : WORD ;
   MAGNETE_1_ESCLUSO : BOOL ;	//MAGNETE 1 ESCLUSO DA MP270
   MAGNETE_2_ESCLUSO : BOOL ;	//MAGNETE 2 ESCLUSO DA MP270
   MAGNETE_3_ESCLUSO : BOOL ;	//MAGNETE 3 ESCLUSO DA MP270
   MAGNETE_4_ESCLUSO : BOOL ;	//MAGNETE 4 ESCLUSO DA MP270
   MAGNETE_5_ESCLUSO : BOOL ;	//MAGNETE 5 ESCLUSO DA MP270
   MAGNETE_6_ESCLUSO : BOOL ;	//MAGNETE 6 ESCLUSO DA MP270
   MAGNETE_LAT_SX_ESCLUSO : BOOL ;	//MAGNETE LATERALE SX ESCLUSO DA MP270
   MAGNETE_LAT_DX_ESCLUSO : BOOL ;	//MAGNETE LATERALE DX ESCLUSO DA MP270
   COMPENSAZ_TAV_2 : REAL ;	//COMPENSAZIONE TAVOLA 2
   STAT22 : WORD ;
   STAT23 : WORD ;
   STAT24 : WORD ;
   STAT25 : WORD ;
   STAT251 : WORD ;
   STAT26 : TIME ;
   STAT29 : TIME ;
   STAT30 : TIME ;
   STAT31 : TIME ;
   C1_Timer : REAL ;	//Centratore 1: Timer ritardo partenza
   C2_Timer : REAL ;	//Centratore 2: Timer ritardo partenza
   C3_Timer : REAL ;	//Centratore 3: Timer ritardo partenza
   C4_Timer : REAL ;	//Centratore 4: Timer ritardo partenza
   C5_Timer : REAL ;	//Centratore 5: Timer ritardo partenza
   C6_Timer : REAL ;	//Centratore 6: Timer ritardo partenza
   C1_Posizione_1 : DINT  := L#500000;	//Centratore 1: Posizione 1 di avicinamento
   C1_Posizione_2 : DINT  := L#520000;	//Centratore 1: Posizione 2 di cambio velocita'
   C1_Posizione_3 : DINT  := L#530000;	//Centratore 1: Posizione 3 di cambio velocita'
   C1_Posizione_4 : DINT  := L#565400;	//Centratore 1: Posizione 4 di arrivo
   C1_Velocita_1 : DINT  := L#50;	//Centratore 1: Velocita' 1 di avvicinamento
   C1_Velocita_2 : DINT  := L#50;	//Centratore 1: Velocita' 2
   C1_Velocita_3 : DINT  := L#50;	//Centratore 1: Velocita' 3
   C1_Velocita_4 : DINT  := L#50;	//Centratore 1: Velocita' 4 di arrivo
   C1_Accell_1 : DINT  := L#500;	//Centratore 1: Accelerazione 1 di avvicinamento
   C1_Accell_2 : DINT  := L#500;	//Centratore 1: Accelerazione 2
   C1_Accell_3 : DINT  := L#500;	//Centratore 1: Accelerazione 3
   C1_Accell_4 : DINT  := L#500;	//Centratore 1: Accelerazione 4 di arrivo
   word_148 : WORD ;
   C2_Posizione_1 : DINT  := L#500000;	//Centratore 2: Posizione 1 di avicinamento
   C2_Posizione_2 : DINT  := L#520000;	//Centratore 2: Posizione 2 di cambio velocita'
   C2_Posizione_3 : DINT  := L#530000;	//Centratore 2: Posizione 3 di cambio velocita'
   C2_Posizione_4 : DINT  := L#559000;	//Centratore 2: Posizione 4 di arrivo
   C2_Velocita_1 : DINT  := L#50;	//Centratore 2: Velocita' 1 di avvicinamento
   C2_Velocita_2 : DINT  := L#50;	//Centratore 2: Velocita' 2
   C2_Velocita_3 : DINT  := L#50;	//Centratore 2: Velocita' 3
   C2_Velocita_4 : DINT  := L#50;	//Centratore 2: Velocita' 4 di arrivo
   C2_Accell_1 : DINT  := L#500;	//Centratore 2: Accelerazione 1 di avvicinamento
   C2_Accell_2 : DINT  := L#500;	//Centratore 2: Accelerazione 2
   C2_Accell_3 : DINT  := L#500;	//Centratore 2: Accelerazione 3
   C2_Accell_4 : DINT  := L#500;	//Centratore 2: Accelerazione 4 di arrivo
   word_198 : WORD ;
   C3_Posizione_1 : DINT  := L#630000;	//Centratore 3: Posizione 1 di avicinamento
   C3_Posizione_2 : DINT  := L#650000;	//Centratore 3: Posizione 2 di cambio velocita'
   C3_Posizione_3 : DINT  := L#660000;	//Centratore 3: Posizione 3 di cambio velocita'
   C3_Posizione_4 : DINT  := L#698600;	//Centratore 3: Posizione 4 di arrivo
   C3_Velocita_1 : DINT  := L#50;	//Centratore 3: Velocita' 1 di avvicinamento
   C3_Velocita_2 : DINT  := L#50;	//Centratore 3: Velocita' 2
   C3_Velocita_3 : DINT  := L#50;	//Centratore 3: Velocita' 3
   C3_Velocita_4 : DINT  := L#50;	//Centratore 3: Velocita' 4 di arrivo
   C3_Accell_1 : DINT  := L#500;	//Centratore 3: Accelerazione 1 di avvicinamento
   C3_Accell_2 : DINT  := L#500;	//Centratore 3: Accelerazione 2
   C3_Accell_3 : DINT  := L#500;	//Centratore 3: Accelerazione 3
   C3_Accell_4 : DINT  := L#500;	//Centratore 3: Accelerazione 4 di arrivo
   word_248 : WORD ;
   C4_Posizione_1 : DINT  := L#630000;	//Centratore 4: Posizione 1 di avicinamento
   C4_Posizione_2 : DINT  := L#650000;	//Centratore 4: Posizione 2 di cambio velocita'
   C4_Posizione_3 : DINT  := L#660000;	//Centratore 4: Posizione 3 di cambio velocita'
   C4_Posizione_4 : DINT  := L#706200;	//Centratore 4: Posizione 4 di arrivo
   C4_Velocita_1 : DINT  := L#50;	//Centratore 4: Velocita' 1 di avvicinamento
   C4_Velocita_2 : DINT  := L#50;	//Centratore 4: Velocita' 2
   C4_Velocita_3 : DINT  := L#50;	//Centratore 4: Velocita' 3
   C4_Velocita_4 : DINT  := L#50;	//Centratore 4: Velocita' 4 di arrivo
   C4_Accell_1 : DINT  := L#500;	//Centratore 4: Accelerazione 1 di avvicinamento
   C4_Accell_2 : DINT  := L#500;	//Centratore 4: Accelerazione 2
   C4_Accell_3 : DINT  := L#500;	//Centratore 4: Accelerazione 3
   C4_Accell_4 : DINT  := L#500;	//Centratore 4: Accelerazione 4 di arrivo
   word_298 : WORD ;
   C5_Posizione_1 : DINT  := L#1180000;	//Centratore 5: Posizione 1 di avicinamento
   C5_Posizione_2 : DINT  := L#1200000;	//Centratore 5: Posizione 2 di cambio velocita'
   C5_Posizione_3 : DINT  := L#1220000;	//Centratore 5: Posizione 3 di cambio velocita'
   C5_Posizione_4 : DINT  := L#1247000;	//Centratore 5: Posizione 4 di arrivo
   C5_Velocita_1 : DINT  := L#50;	//Centratore 5: Velocita' 1 di avvicinamento
   C5_Velocita_2 : DINT  := L#50;	//Centratore 5: Velocita' 2
   C5_Velocita_3 : DINT  := L#50;	//Centratore 5: Velocita' 3
   C5_Velocita_4 : DINT  := L#50;	//Centratore 5: Velocita' 4 di arrivo
   C5_Accell_1 : DINT  := L#500;	//Centratore 5: Accelerazione 1 di avvicinamento
   C5_Accell_2 : DINT  := L#500;	//Centratore 5: Accelerazione 2
   C5_Accell_3 : DINT  := L#500;	//Centratore 5: Accelerazione 3
   C5_Accell_4 : DINT  := L#500;	//Centratore 5: Accelerazione 4 di arrivo
   word_348 : WORD ;
   C6_Posizione_1 : DINT  := L#1180000;	//Centratore 6: Posizione 1 di avicinamento
   C6_Posizione_2 : DINT  := L#1200000;	//Centratore 6: Posizione 2 di cambio velocita'
   C6_Posizione_3 : DINT  := L#1220000;	//Centratore 6: Posizione 3 di cambio velocita'
   C6_Posizione_4 : DINT  := L#1237400;	//Centratore 6: Posizione 4 di arrivo
   C6_Velocita_1 : DINT  := L#50;	//Centratore 6: Velocita' 1 di avvicinamento
   C6_Velocita_2 : DINT  := L#50;	//Centratore 6: Velocita' 2
   C6_Velocita_3 : DINT  := L#50;	//Centratore 6: Velocita' 3
   C6_Velocita_4 : DINT  := L#50;	//Centratore 6: Velocita' 4 di arrivo
   C6_Accell_1 : DINT  := L#500;	//Centratore 6: Accelerazione 1 di avvicinamento
   C6_Accell_2 : DINT  := L#500;	//Centratore 6: Accelerazione 2
   C6_Accell_3 : DINT  := L#500;	//Centratore 6: Accelerazione 3
   C6_Accell_4 : DINT  := L#500;	//Centratore 6: Accelerazione 4 di arrivo
   word_398 : WORD ;
  END_STRUCT ;
BEGIN
   LARGHEZZA_LAMIERA := 3.060000e+003;
   COMPENSAZ_TAV_1 := -7.000000e+001;
   QUOTA_H_SFOGLIATORE := 2.000000e+003;
   QUOTA_H_CENTRATORE := 1.960000e+003;
   word16 := S5T#0MS;
   INCLINAZ_TAVOLA_ESCLUSA := FALSE;
   dword20 := 0.000000e+000;
   dword24 := 0.000000e+000;
   dword28 := 0.000000e+000;
   dword32 := 0.000000e+000;
   dword36 := 0.000000e+000;
   NR_MATRICOLA := 2;
   word42 := W#16#0;
   MAGNETE_1_ESCLUSO := FALSE;
   MAGNETE_2_ESCLUSO := FALSE;
   MAGNETE_3_ESCLUSO := FALSE;
   MAGNETE_4_ESCLUSO := FALSE;
   MAGNETE_5_ESCLUSO := FALSE;
   MAGNETE_6_ESCLUSO := FALSE;
   MAGNETE_LAT_SX_ESCLUSO := FALSE;
   MAGNETE_LAT_DX_ESCLUSO := FALSE;
   COMPENSAZ_TAV_2 := -3.000000e+001;
   STAT22 := W#16#0;
   STAT23 := W#16#0;
   STAT24 := W#16#0;
   STAT25 := W#16#0;
   STAT251 := W#16#0;
   STAT26 := T#0MS;
   STAT29 := T#0MS;
   STAT30 := T#0MS;
   STAT31 := T#0MS;
   C1_Timer := 0.000000e+000;
   C2_Timer := 0.000000e+000;
   C3_Timer := 0.000000e+000;
   C4_Timer := 0.000000e+000;
   C5_Timer := 0.000000e+000;
   C6_Timer := 0.000000e+000;
   C1_Posizione_1 := L#163000;
   C1_Posizione_2 := L#183000;
   C1_Posizione_3 := L#193000;
   C1_Posizione_4 := L#235000;
   C1_Velocita_1 := L#500;
   C1_Velocita_2 := L#200;
   C1_Velocita_3 := L#200;
   C1_Velocita_4 := L#50;
   C1_Accell_1 := L#500;
   C1_Accell_2 := L#500;
   C1_Accell_3 := L#500;
   C1_Accell_4 := L#500;
   word_148 := W#16#0;
   C2_Posizione_1 := L#326000;
   C2_Posizione_2 := L#346000;
   C2_Posizione_3 := L#356000;
   C2_Posizione_4 := L#401000;
   C2_Velocita_1 := L#500;
   C2_Velocita_2 := L#200;
   C2_Velocita_3 := L#200;
   C2_Velocita_4 := L#50;
   C2_Accell_1 := L#500;
   C2_Accell_2 := L#500;
   C2_Accell_3 := L#500;
   C2_Accell_4 := L#500;
   word_198 := W#16#0;
   C3_Posizione_1 := L#200000;
   C3_Posizione_2 := L#220000;
   C3_Posizione_3 := L#230000;
   C3_Posizione_4 := L#385000;
   C3_Velocita_1 := L#500;
   C3_Velocita_2 := L#200;
   C3_Velocita_3 := L#200;
   C3_Velocita_4 := L#50;
   C3_Accell_1 := L#500;
   C3_Accell_2 := L#500;
   C3_Accell_3 := L#500;
   C3_Accell_4 := L#500;
   word_248 := W#16#0;
   C4_Posizione_1 := L#100000;
   C4_Posizione_2 := L#120000;
   C4_Posizione_3 := L#130000;
   C4_Posizione_4 := L#283000;
   C4_Velocita_1 := L#500;
   C4_Velocita_2 := L#200;
   C4_Velocita_3 := L#200;
   C4_Velocita_4 := L#50;
   C4_Accell_1 := L#500;
   C4_Accell_2 := L#500;
   C4_Accell_3 := L#500;
   C4_Accell_4 := L#500;
   word_298 := W#16#0;
   C5_Posizione_1 := L#395000;
   C5_Posizione_2 := L#415000;
   C5_Posizione_3 := L#425000;
   C5_Posizione_4 := L#510000;
   C5_Velocita_1 := L#500;
   C5_Velocita_2 := L#200;
   C5_Velocita_3 := L#200;
   C5_Velocita_4 := L#50;
   C5_Accell_1 := L#500;
   C5_Accell_2 := L#500;
   C5_Accell_3 := L#500;
   C5_Accell_4 := L#500;
   word_348 := W#16#0;
   C6_Posizione_1 := L#430000;
   C6_Posizione_2 := L#450000;
   C6_Posizione_3 := L#460000;
   C6_Posizione_4 := L#525000;
   C6_Velocita_1 := L#500;
   C6_Velocita_2 := L#200;
   C6_Velocita_3 := L#200;
   C6_Velocita_4 := L#50;
   C6_Accell_1 := L#500;
   C6_Accell_2 := L#500;
   C6_Accell_3 := L#500;
   C6_Accell_4 := L#500;
   word_398 := W#16#0;
END_DATA_BLOCK

DATA_BLOCK "MATRICOLA 15"
AUTHOR : Lodato
FAMILY : DESTACK
NAME : DATI
VERSION : 0.1


  STRUCT
   LARGHEZZA_LAMIERA : REAL  := 1.500000e+003;	//LARGHEZZA LAMIERA ATTUALE
   COMPENSAZ_TAV_1 : REAL ;	//COMPENSAZIONE TAVOLA 1
   QUOTA_H_SFOGLIATORE : REAL ;	//Quota impostata altezza sfogliatore
   QUOTA_H_CENTRATORE : REAL ;	//Quota impostata altezza centratore
   word16 : S5TIME ;
   INCLINAZ_TAVOLA_ESCLUSA : BOOL ;	//INCLINAZIONE TAVOLA ESCLUSA
   dword20 : REAL ;
   dword24 : REAL ;
   dword28 : REAL ;
   dword32 : REAL ;
   dword36 : REAL ;
   NR_MATRICOLA : INT  := 1;	//Numero di matricola
   word42 : WORD ;
   MAGNETE_1_ESCLUSO : BOOL ;	//MAGNETE 1 ESCLUSO DA MP270
   MAGNETE_2_ESCLUSO : BOOL ;	//MAGNETE 2 ESCLUSO DA MP270
   MAGNETE_3_ESCLUSO : BOOL ;	//MAGNETE 3 ESCLUSO DA MP270
   MAGNETE_4_ESCLUSO : BOOL ;	//MAGNETE 4 ESCLUSO DA MP270
   MAGNETE_5_ESCLUSO : BOOL ;	//MAGNETE 5 ESCLUSO DA MP270
   MAGNETE_6_ESCLUSO : BOOL ;	//MAGNETE 6 ESCLUSO DA MP270
   MAGNETE_LAT_SX_ESCLUSO : BOOL ;	//MAGNETE LATERALE SX ESCLUSO DA MP270
   MAGNETE_LAT_DX_ESCLUSO : BOOL ;	//MAGNETE LATERALE DX ESCLUSO DA MP270
   COMPENSAZ_TAV_2 : REAL ;	//COMPENSAZIONE TAVOLA 2
   STAT22 : WORD ;
   STAT23 : WORD ;
   STAT24 : WORD ;
   STAT25 : WORD ;
   STAT251 : WORD ;
   STAT26 : TIME ;
   STAT29 : TIME ;
   STAT30 : TIME ;
   STAT31 : TIME ;
   C1_Timer : REAL ;	//Centratore 1: Timer ritardo partenza
   C2_Timer : REAL ;	//Centratore 2: Timer ritardo partenza
   C3_Timer : REAL ;	//Centratore 3: Timer ritardo partenza
   C4_Timer : REAL ;	//Centratore 4: Timer ritardo partenza
   C5_Timer : REAL ;	//Centratore 5: Timer ritardo partenza
   C6_Timer : REAL ;	//Centratore 6: Timer ritardo partenza
   C1_Posizione_1 : DINT  := L#500000;	//Centratore 1: Posizione 1 di avicinamento
   C1_Posizione_2 : DINT  := L#520000;	//Centratore 1: Posizione 2 di cambio velocita'
   C1_Posizione_3 : DINT  := L#530000;	//Centratore 1: Posizione 3 di cambio velocita'
   C1_Posizione_4 : DINT  := L#565400;	//Centratore 1: Posizione 4 di arrivo
   C1_Velocita_1 : DINT  := L#50;	//Centratore 1: Velocita' 1 di avvicinamento
   C1_Velocita_2 : DINT  := L#50;	//Centratore 1: Velocita' 2
   C1_Velocita_3 : DINT  := L#50;	//Centratore 1: Velocita' 3
   C1_Velocita_4 : DINT  := L#50;	//Centratore 1: Velocita' 4 di arrivo
   C1_Accell_1 : DINT  := L#500;	//Centratore 1: Accelerazione 1 di avvicinamento
   C1_Accell_2 : DINT  := L#500;	//Centratore 1: Accelerazione 2
   C1_Accell_3 : DINT  := L#500;	//Centratore 1: Accelerazione 3
   C1_Accell_4 : DINT  := L#500;	//Centratore 1: Accelerazione 4 di arrivo
   word_148 : WORD ;
   C2_Posizione_1 : DINT  := L#500000;	//Centratore 2: Posizione 1 di avicinamento
   C2_Posizione_2 : DINT  := L#520000;	//Centratore 2: Posizione 2 di cambio velocita'
   C2_Posizione_3 : DINT  := L#530000;	//Centratore 2: Posizione 3 di cambio velocita'
   C2_Posizione_4 : DINT  := L#559000;	//Centratore 2: Posizione 4 di arrivo
   C2_Velocita_1 : DINT  := L#50;	//Centratore 2: Velocita' 1 di avvicinamento
   C2_Velocita_2 : DINT  := L#50;	//Centratore 2: Velocita' 2
   C2_Velocita_3 : DINT  := L#50;	//Centratore 2: Velocita' 3
   C2_Velocita_4 : DINT  := L#50;	//Centratore 2: Velocita' 4 di arrivo
   C2_Accell_1 : DINT  := L#500;	//Centratore 2: Accelerazione 1 di avvicinamento
   C2_Accell_2 : DINT  := L#500;	//Centratore 2: Accelerazione 2
   C2_Accell_3 : DINT  := L#500;	//Centratore 2: Accelerazione 3
   C2_Accell_4 : DINT  := L#500;	//Centratore 2: Accelerazione 4 di arrivo
   word_198 : WORD ;
   C3_Posizione_1 : DINT  := L#630000;	//Centratore 3: Posizione 1 di avicinamento
   C3_Posizione_2 : DINT  := L#650000;	//Centratore 3: Posizione 2 di cambio velocita'
   C3_Posizione_3 : DINT  := L#660000;	//Centratore 3: Posizione 3 di cambio velocita'
   C3_Posizione_4 : DINT  := L#698600;	//Centratore 3: Posizione 4 di arrivo
   C3_Velocita_1 : DINT  := L#50;	//Centratore 3: Velocita' 1 di avvicinamento
   C3_Velocita_2 : DINT  := L#50;	//Centratore 3: Velocita' 2
   C3_Velocita_3 : DINT  := L#50;	//Centratore 3: Velocita' 3
   C3_Velocita_4 : DINT  := L#50;	//Centratore 3: Velocita' 4 di arrivo
   C3_Accell_1 : DINT  := L#500;	//Centratore 3: Accelerazione 1 di avvicinamento
   C3_Accell_2 : DINT  := L#500;	//Centratore 3: Accelerazione 2
   C3_Accell_3 : DINT  := L#500;	//Centratore 3: Accelerazione 3
   C3_Accell_4 : DINT  := L#500;	//Centratore 3: Accelerazione 4 di arrivo
   word_248 : WORD ;
   C4_Posizione_1 : DINT  := L#630000;	//Centratore 4: Posizione 1 di avicinamento
   C4_Posizione_2 : DINT  := L#650000;	//Centratore 4: Posizione 2 di cambio velocita'
   C4_Posizione_3 : DINT  := L#660000;	//Centratore 4: Posizione 3 di cambio velocita'
   C4_Posizione_4 : DINT  := L#706200;	//Centratore 4: Posizione 4 di arrivo
   C4_Velocita_1 : DINT  := L#50;	//Centratore 4: Velocita' 1 di avvicinamento
   C4_Velocita_2 : DINT  := L#50;	//Centratore 4: Velocita' 2
   C4_Velocita_3 : DINT  := L#50;	//Centratore 4: Velocita' 3
   C4_Velocita_4 : DINT  := L#50;	//Centratore 4: Velocita' 4 di arrivo
   C4_Accell_1 : DINT  := L#500;	//Centratore 4: Accelerazione 1 di avvicinamento
   C4_Accell_2 : DINT  := L#500;	//Centratore 4: Accelerazione 2
   C4_Accell_3 : DINT  := L#500;	//Centratore 4: Accelerazione 3
   C4_Accell_4 : DINT  := L#500;	//Centratore 4: Accelerazione 4 di arrivo
   word_298 : WORD ;
   C5_Posizione_1 : DINT  := L#1180000;	//Centratore 5: Posizione 1 di avicinamento
   C5_Posizione_2 : DINT  := L#1200000;	//Centratore 5: Posizione 2 di cambio velocita'
   C5_Posizione_3 : DINT  := L#1220000;	//Centratore 5: Posizione 3 di cambio velocita'
   C5_Posizione_4 : DINT  := L#1247000;	//Centratore 5: Posizione 4 di arrivo
   C5_Velocita_1 : DINT  := L#50;	//Centratore 5: Velocita' 1 di avvicinamento
   C5_Velocita_2 : DINT  := L#50;	//Centratore 5: Velocita' 2
   C5_Velocita_3 : DINT  := L#50;	//Centratore 5: Velocita' 3
   C5_Velocita_4 : DINT  := L#50;	//Centratore 5: Velocita' 4 di arrivo
   C5_Accell_1 : DINT  := L#500;	//Centratore 5: Accelerazione 1 di avvicinamento
   C5_Accell_2 : DINT  := L#500;	//Centratore 5: Accelerazione 2
   C5_Accell_3 : DINT  := L#500;	//Centratore 5: Accelerazione 3
   C5_Accell_4 : DINT  := L#500;	//Centratore 5: Accelerazione 4 di arrivo
   word_348 : WORD ;
   C6_Posizione_1 : DINT  := L#1180000;	//Centratore 6: Posizione 1 di avicinamento
   C6_Posizione_2 : DINT  := L#1200000;	//Centratore 6: Posizione 2 di cambio velocita'
   C6_Posizione_3 : DINT  := L#1220000;	//Centratore 6: Posizione 3 di cambio velocita'
   C6_Posizione_4 : DINT  := L#1237400;	//Centratore 6: Posizione 4 di arrivo
   C6_Velocita_1 : DINT  := L#50;	//Centratore 6: Velocita' 1 di avvicinamento
   C6_Velocita_2 : DINT  := L#50;	//Centratore 6: Velocita' 2
   C6_Velocita_3 : DINT  := L#50;	//Centratore 6: Velocita' 3
   C6_Velocita_4 : DINT  := L#50;	//Centratore 6: Velocita' 4 di arrivo
   C6_Accell_1 : DINT  := L#500;	//Centratore 6: Accelerazione 1 di avvicinamento
   C6_Accell_2 : DINT  := L#500;	//Centratore 6: Accelerazione 2
   C6_Accell_3 : DINT  := L#500;	//Centratore 6: Accelerazione 3
   C6_Accell_4 : DINT  := L#500;	//Centratore 6: Accelerazione 4 di arrivo
   word_398 : WORD ;
  END_STRUCT ;
BEGIN
   LARGHEZZA_LAMIERA := 3.060000e+003;
   COMPENSAZ_TAV_1 := -7.000000e+001;
   QUOTA_H_SFOGLIATORE := 2.000000e+003;
   QUOTA_H_CENTRATORE := 1.960000e+003;
   word16 := S5T#0MS;
   INCLINAZ_TAVOLA_ESCLUSA := FALSE;
   dword20 := 0.000000e+000;
   dword24 := 0.000000e+000;
   dword28 := 0.000000e+000;
   dword32 := 0.000000e+000;
   dword36 := 0.000000e+000;
   NR_MATRICOLA := 2;
   word42 := W#16#0;
   MAGNETE_1_ESCLUSO := FALSE;
   MAGNETE_2_ESCLUSO := FALSE;
   MAGNETE_3_ESCLUSO := FALSE;
   MAGNETE_4_ESCLUSO := FALSE;
   MAGNETE_5_ESCLUSO := FALSE;
   MAGNETE_6_ESCLUSO := FALSE;
   MAGNETE_LAT_SX_ESCLUSO := FALSE;
   MAGNETE_LAT_DX_ESCLUSO := FALSE;
   COMPENSAZ_TAV_2 := -3.000000e+001;
   STAT22 := W#16#0;
   STAT23 := W#16#0;
   STAT24 := W#16#0;
   STAT25 := W#16#0;
   STAT251 := W#16#0;
   STAT26 := T#0MS;
   STAT29 := T#0MS;
   STAT30 := T#0MS;
   STAT31 := T#0MS;
   C1_Timer := 0.000000e+000;
   C2_Timer := 0.000000e+000;
   C3_Timer := 0.000000e+000;
   C4_Timer := 0.000000e+000;
   C5_Timer := 0.000000e+000;
   C6_Timer := 0.000000e+000;
   C1_Posizione_1 := L#163000;
   C1_Posizione_2 := L#183000;
   C1_Posizione_3 := L#193000;
   C1_Posizione_4 := L#235000;
   C1_Velocita_1 := L#500;
   C1_Velocita_2 := L#200;
   C1_Velocita_3 := L#200;
   C1_Velocita_4 := L#50;
   C1_Accell_1 := L#500;
   C1_Accell_2 := L#500;
   C1_Accell_3 := L#500;
   C1_Accell_4 := L#500;
   word_148 := W#16#0;
   C2_Posizione_1 := L#326000;
   C2_Posizione_2 := L#346000;
   C2_Posizione_3 := L#356000;
   C2_Posizione_4 := L#401000;
   C2_Velocita_1 := L#500;
   C2_Velocita_2 := L#200;
   C2_Velocita_3 := L#200;
   C2_Velocita_4 := L#50;
   C2_Accell_1 := L#500;
   C2_Accell_2 := L#500;
   C2_Accell_3 := L#500;
   C2_Accell_4 := L#500;
   word_198 := W#16#0;
   C3_Posizione_1 := L#200000;
   C3_Posizione_2 := L#220000;
   C3_Posizione_3 := L#230000;
   C3_Posizione_4 := L#385000;
   C3_Velocita_1 := L#500;
   C3_Velocita_2 := L#200;
   C3_Velocita_3 := L#200;
   C3_Velocita_4 := L#50;
   C3_Accell_1 := L#500;
   C3_Accell_2 := L#500;
   C3_Accell_3 := L#500;
   C3_Accell_4 := L#500;
   word_248 := W#16#0;
   C4_Posizione_1 := L#100000;
   C4_Posizione_2 := L#120000;
   C4_Posizione_3 := L#130000;
   C4_Posizione_4 := L#283000;
   C4_Velocita_1 := L#500;
   C4_Velocita_2 := L#200;
   C4_Velocita_3 := L#200;
   C4_Velocita_4 := L#50;
   C4_Accell_1 := L#500;
   C4_Accell_2 := L#500;
   C4_Accell_3 := L#500;
   C4_Accell_4 := L#500;
   word_298 := W#16#0;
   C5_Posizione_1 := L#395000;
   C5_Posizione_2 := L#415000;
   C5_Posizione_3 := L#425000;
   C5_Posizione_4 := L#510000;
   C5_Velocita_1 := L#500;
   C5_Velocita_2 := L#200;
   C5_Velocita_3 := L#200;
   C5_Velocita_4 := L#50;
   C5_Accell_1 := L#500;
   C5_Accell_2 := L#500;
   C5_Accell_3 := L#500;
   C5_Accell_4 := L#500;
   word_348 := W#16#0;
   C6_Posizione_1 := L#430000;
   C6_Posizione_2 := L#450000;
   C6_Posizione_3 := L#460000;
   C6_Posizione_4 := L#525000;
   C6_Velocita_1 := L#500;
   C6_Velocita_2 := L#200;
   C6_Velocita_3 := L#200;
   C6_Velocita_4 := L#50;
   C6_Accell_1 := L#500;
   C6_Accell_2 := L#500;
   C6_Accell_3 := L#500;
   C6_Accell_4 := L#500;
   word_398 := W#16#0;
END_DATA_BLOCK

DATA_BLOCK "MATRICOLA 16"
AUTHOR : Lodato
FAMILY : DESTACK
NAME : DATI
VERSION : 0.1


  STRUCT
   LARGHEZZA_LAMIERA : REAL  := 1.500000e+003;	//LARGHEZZA LAMIERA ATTUALE
   COMPENSAZ_TAV_1 : REAL ;	//COMPENSAZIONE TAVOLA 1
   QUOTA_H_SFOGLIATORE : REAL ;	//Quota impostata altezza sfogliatore
   QUOTA_H_CENTRATORE : REAL ;	//Quota impostata altezza centratore
   word16 : S5TIME ;
   INCLINAZ_TAVOLA_ESCLUSA : BOOL ;	//INCLINAZIONE TAVOLA ESCLUSA
   dword20 : REAL ;
   dword24 : REAL ;
   dword28 : REAL ;
   dword32 : REAL ;
   dword36 : REAL ;
   NR_MATRICOLA : INT  := 1;	//Numero di matricola
   word42 : WORD ;
   MAGNETE_1_ESCLUSO : BOOL ;	//MAGNETE 1 ESCLUSO DA MP270
   MAGNETE_2_ESCLUSO : BOOL ;	//MAGNETE 2 ESCLUSO DA MP270
   MAGNETE_3_ESCLUSO : BOOL ;	//MAGNETE 3 ESCLUSO DA MP270
   MAGNETE_4_ESCLUSO : BOOL ;	//MAGNETE 4 ESCLUSO DA MP270
   MAGNETE_5_ESCLUSO : BOOL ;	//MAGNETE 5 ESCLUSO DA MP270
   MAGNETE_6_ESCLUSO : BOOL ;	//MAGNETE 6 ESCLUSO DA MP270
   MAGNETE_LAT_SX_ESCLUSO : BOOL ;	//MAGNETE LATERALE SX ESCLUSO DA MP270
   MAGNETE_LAT_DX_ESCLUSO : BOOL ;	//MAGNETE LATERALE DX ESCLUSO DA MP270
   COMPENSAZ_TAV_2 : REAL ;	//COMPENSAZIONE TAVOLA 2
   STAT22 : WORD ;
   STAT23 : WORD ;
   STAT24 : WORD ;
   STAT25 : WORD ;
   STAT251 : WORD ;
   STAT26 : TIME ;
   STAT29 : TIME ;
   STAT30 : TIME ;
   STAT31 : TIME ;
   C1_Timer : REAL ;	//Centratore 1: Timer ritardo partenza
   C2_Timer : REAL ;	//Centratore 2: Timer ritardo partenza
   C3_Timer : REAL ;	//Centratore 3: Timer ritardo partenza
   C4_Timer : REAL ;	//Centratore 4: Timer ritardo partenza
   C5_Timer : REAL ;	//Centratore 5: Timer ritardo partenza
   C6_Timer : REAL ;	//Centratore 6: Timer ritardo partenza
   C1_Posizione_1 : DINT  := L#500000;	//Centratore 1: Posizione 1 di avicinamento
   C1_Posizione_2 : DINT  := L#520000;	//Centratore 1: Posizione 2 di cambio velocita'
   C1_Posizione_3 : DINT  := L#530000;	//Centratore 1: Posizione 3 di cambio velocita'
   C1_Posizione_4 : DINT  := L#565400;	//Centratore 1: Posizione 4 di arrivo
   C1_Velocita_1 : DINT  := L#50;	//Centratore 1: Velocita' 1 di avvicinamento
   C1_Velocita_2 : DINT  := L#50;	//Centratore 1: Velocita' 2
   C1_Velocita_3 : DINT  := L#50;	//Centratore 1: Velocita' 3
   C1_Velocita_4 : DINT  := L#50;	//Centratore 1: Velocita' 4 di arrivo
   C1_Accell_1 : DINT  := L#500;	//Centratore 1: Accelerazione 1 di avvicinamento
   C1_Accell_2 : DINT  := L#500;	//Centratore 1: Accelerazione 2
   C1_Accell_3 : DINT  := L#500;	//Centratore 1: Accelerazione 3
   C1_Accell_4 : DINT  := L#500;	//Centratore 1: Accelerazione 4 di arrivo
   word_148 : WORD ;
   C2_Posizione_1 : DINT  := L#500000;	//Centratore 2: Posizione 1 di avicinamento
   C2_Posizione_2 : DINT  := L#520000;	//Centratore 2: Posizione 2 di cambio velocita'
   C2_Posizione_3 : DINT  := L#530000;	//Centratore 2: Posizione 3 di cambio velocita'
   C2_Posizione_4 : DINT  := L#559000;	//Centratore 2: Posizione 4 di arrivo
   C2_Velocita_1 : DINT  := L#50;	//Centratore 2: Velocita' 1 di avvicinamento
   C2_Velocita_2 : DINT  := L#50;	//Centratore 2: Velocita' 2
   C2_Velocita_3 : DINT  := L#50;	//Centratore 2: Velocita' 3
   C2_Velocita_4 : DINT  := L#50;	//Centratore 2: Velocita' 4 di arrivo
   C2_Accell_1 : DINT  := L#500;	//Centratore 2: Accelerazione 1 di avvicinamento
   C2_Accell_2 : DINT  := L#500;	//Centratore 2: Accelerazione 2
   C2_Accell_3 : DINT  := L#500;	//Centratore 2: Accelerazione 3
   C2_Accell_4 : DINT  := L#500;	//Centratore 2: Accelerazione 4 di arrivo
   word_198 : WORD ;
   C3_Posizione_1 : DINT  := L#630000;	//Centratore 3: Posizione 1 di avicinamento
   C3_Posizione_2 : DINT  := L#650000;	//Centratore 3: Posizione 2 di cambio velocita'
   C3_Posizione_3 : DINT  := L#660000;	//Centratore 3: Posizione 3 di cambio velocita'
   C3_Posizione_4 : DINT  := L#698600;	//Centratore 3: Posizione 4 di arrivo
   C3_Velocita_1 : DINT  := L#50;	//Centratore 3: Velocita' 1 di avvicinamento
   C3_Velocita_2 : DINT  := L#50;	//Centratore 3: Velocita' 2
   C3_Velocita_3 : DINT  := L#50;	//Centratore 3: Velocita' 3
   C3_Velocita_4 : DINT  := L#50;	//Centratore 3: Velocita' 4 di arrivo
   C3_Accell_1 : DINT  := L#500;	//Centratore 3: Accelerazione 1 di avvicinamento
   C3_Accell_2 : DINT  := L#500;	//Centratore 3: Accelerazione 2
   C3_Accell_3 : DINT  := L#500;	//Centratore 3: Accelerazione 3
   C3_Accell_4 : DINT  := L#500;	//Centratore 3: Accelerazione 4 di arrivo
   word_248 : WORD ;
   C4_Posizione_1 : DINT  := L#630000;	//Centratore 4: Posizione 1 di avicinamento
   C4_Posizione_2 : DINT  := L#650000;	//Centratore 4: Posizione 2 di cambio velocita'
   C4_Posizione_3 : DINT  := L#660000;	//Centratore 4: Posizione 3 di cambio velocita'
   C4_Posizione_4 : DINT  := L#706200;	//Centratore 4: Posizione 4 di arrivo
   C4_Velocita_1 : DINT  := L#50;	//Centratore 4: Velocita' 1 di avvicinamento
   C4_Velocita_2 : DINT  := L#50;	//Centratore 4: Velocita' 2
   C4_Velocita_3 : DINT  := L#50;	//Centratore 4: Velocita' 3
   C4_Velocita_4 : DINT  := L#50;	//Centratore 4: Velocita' 4 di arrivo
   C4_Accell_1 : DINT  := L#500;	//Centratore 4: Accelerazione 1 di avvicinamento
   C4_Accell_2 : DINT  := L#500;	//Centratore 4: Accelerazione 2
   C4_Accell_3 : DINT  := L#500;	//Centratore 4: Accelerazione 3
   C4_Accell_4 : DINT  := L#500;	//Centratore 4: Accelerazione 4 di arrivo
   word_298 : WORD ;
   C5_Posizione_1 : DINT  := L#1180000;	//Centratore 5: Posizione 1 di avicinamento
   C5_Posizione_2 : DINT  := L#1200000;	//Centratore 5: Posizione 2 di cambio velocita'
   C5_Posizione_3 : DINT  := L#1220000;	//Centratore 5: Posizione 3 di cambio velocita'
   C5_Posizione_4 : DINT  := L#1247000;	//Centratore 5: Posizione 4 di arrivo
   C5_Velocita_1 : DINT  := L#50;	//Centratore 5: Velocita' 1 di avvicinamento
   C5_Velocita_2 : DINT  := L#50;	//Centratore 5: Velocita' 2
   C5_Velocita_3 : DINT  := L#50;	//Centratore 5: Velocita' 3
   C5_Velocita_4 : DINT  := L#50;	//Centratore 5: Velocita' 4 di arrivo
   C5_Accell_1 : DINT  := L#500;	//Centratore 5: Accelerazione 1 di avvicinamento
   C5_Accell_2 : DINT  := L#500;	//Centratore 5: Accelerazione 2
   C5_Accell_3 : DINT  := L#500;	//Centratore 5: Accelerazione 3
   C5_Accell_4 : DINT  := L#500;	//Centratore 5: Accelerazione 4 di arrivo
   word_348 : WORD ;
   C6_Posizione_1 : DINT  := L#1180000;	//Centratore 6: Posizione 1 di avicinamento
   C6_Posizione_2 : DINT  := L#1200000;	//Centratore 6: Posizione 2 di cambio velocita'
   C6_Posizione_3 : DINT  := L#1220000;	//Centratore 6: Posizione 3 di cambio velocita'
   C6_Posizione_4 : DINT  := L#1237400;	//Centratore 6: Posizione 4 di arrivo
   C6_Velocita_1 : DINT  := L#50;	//Centratore 6: Velocita' 1 di avvicinamento
   C6_Velocita_2 : DINT  := L#50;	//Centratore 6: Velocita' 2
   C6_Velocita_3 : DINT  := L#50;	//Centratore 6: Velocita' 3
   C6_Velocita_4 : DINT  := L#50;	//Centratore 6: Velocita' 4 di arrivo
   C6_Accell_1 : DINT  := L#500;	//Centratore 6: Accelerazione 1 di avvicinamento
   C6_Accell_2 : DINT  := L#500;	//Centratore 6: Accelerazione 2
   C6_Accell_3 : DINT  := L#500;	//Centratore 6: Accelerazione 3
   C6_Accell_4 : DINT  := L#500;	//Centratore 6: Accelerazione 4 di arrivo
   word_398 : WORD ;
  END_STRUCT ;
BEGIN
   LARGHEZZA_LAMIERA := 3.060000e+003;
   COMPENSAZ_TAV_1 := -7.000000e+001;
   QUOTA_H_SFOGLIATORE := 2.000000e+003;
   QUOTA_H_CENTRATORE := 1.960000e+003;
   word16 := S5T#0MS;
   INCLINAZ_TAVOLA_ESCLUSA := FALSE;
   dword20 := 0.000000e+000;
   dword24 := 0.000000e+000;
   dword28 := 0.000000e+000;
   dword32 := 0.000000e+000;
   dword36 := 0.000000e+000;
   NR_MATRICOLA := 2;
   word42 := W#16#0;
   MAGNETE_1_ESCLUSO := FALSE;
   MAGNETE_2_ESCLUSO := FALSE;
   MAGNETE_3_ESCLUSO := FALSE;
   MAGNETE_4_ESCLUSO := FALSE;
   MAGNETE_5_ESCLUSO := FALSE;
   MAGNETE_6_ESCLUSO := FALSE;
   MAGNETE_LAT_SX_ESCLUSO := FALSE;
   MAGNETE_LAT_DX_ESCLUSO := FALSE;
   COMPENSAZ_TAV_2 := -3.000000e+001;
   STAT22 := W#16#0;
   STAT23 := W#16#0;
   STAT24 := W#16#0;
   STAT25 := W#16#0;
   STAT251 := W#16#0;
   STAT26 := T#0MS;
   STAT29 := T#0MS;
   STAT30 := T#0MS;
   STAT31 := T#0MS;
   C1_Timer := 0.000000e+000;
   C2_Timer := 0.000000e+000;
   C3_Timer := 0.000000e+000;
   C4_Timer := 0.000000e+000;
   C5_Timer := 0.000000e+000;
   C6_Timer := 0.000000e+000;
   C1_Posizione_1 := L#163000;
   C1_Posizione_2 := L#183000;
   C1_Posizione_3 := L#193000;
   C1_Posizione_4 := L#235000;
   C1_Velocita_1 := L#500;
   C1_Velocita_2 := L#200;
   C1_Velocita_3 := L#200;
   C1_Velocita_4 := L#50;
   C1_Accell_1 := L#500;
   C1_Accell_2 := L#500;
   C1_Accell_3 := L#500;
   C1_Accell_4 := L#500;
   word_148 := W#16#0;
   C2_Posizione_1 := L#326000;
   C2_Posizione_2 := L#346000;
   C2_Posizione_3 := L#356000;
   C2_Posizione_4 := L#401000;
   C2_Velocita_1 := L#500;
   C2_Velocita_2 := L#200;
   C2_Velocita_3 := L#200;
   C2_Velocita_4 := L#50;
   C2_Accell_1 := L#500;
   C2_Accell_2 := L#500;
   C2_Accell_3 := L#500;
   C2_Accell_4 := L#500;
   word_198 := W#16#0;
   C3_Posizione_1 := L#200000;
   C3_Posizione_2 := L#220000;
   C3_Posizione_3 := L#230000;
   C3_Posizione_4 := L#385000;
   C3_Velocita_1 := L#500;
   C3_Velocita_2 := L#200;
   C3_Velocita_3 := L#200;
   C3_Velocita_4 := L#50;
   C3_Accell_1 := L#500;
   C3_Accell_2 := L#500;
   C3_Accell_3 := L#500;
   C3_Accell_4 := L#500;
   word_248 := W#16#0;
   C4_Posizione_1 := L#100000;
   C4_Posizione_2 := L#120000;
   C4_Posizione_3 := L#130000;
   C4_Posizione_4 := L#283000;
   C4_Velocita_1 := L#500;
   C4_Velocita_2 := L#200;
   C4_Velocita_3 := L#200;
   C4_Velocita_4 := L#50;
   C4_Accell_1 := L#500;
   C4_Accell_2 := L#500;
   C4_Accell_3 := L#500;
   C4_Accell_4 := L#500;
   word_298 := W#16#0;
   C5_Posizione_1 := L#395000;
   C5_Posizione_2 := L#415000;
   C5_Posizione_3 := L#425000;
   C5_Posizione_4 := L#510000;
   C5_Velocita_1 := L#500;
   C5_Velocita_2 := L#200;
   C5_Velocita_3 := L#200;
   C5_Velocita_4 := L#50;
   C5_Accell_1 := L#500;
   C5_Accell_2 := L#500;
   C5_Accell_3 := L#500;
   C5_Accell_4 := L#500;
   word_348 := W#16#0;
   C6_Posizione_1 := L#430000;
   C6_Posizione_2 := L#450000;
   C6_Posizione_3 := L#460000;
   C6_Posizione_4 := L#525000;
   C6_Velocita_1 := L#500;
   C6_Velocita_2 := L#200;
   C6_Velocita_3 := L#200;
   C6_Velocita_4 := L#50;
   C6_Accell_1 := L#500;
   C6_Accell_2 := L#500;
   C6_Accell_3 := L#500;
   C6_Accell_4 := L#500;
   word_398 := W#16#0;
END_DATA_BLOCK

DATA_BLOCK "MATRICOLA 17"
AUTHOR : Lodato
FAMILY : DESTACK
NAME : DATI
VERSION : 0.1


  STRUCT
   LARGHEZZA_LAMIERA : REAL  := 1.500000e+003;	//LARGHEZZA LAMIERA ATTUALE
   COMPENSAZ_TAV_1 : REAL ;	//COMPENSAZIONE TAVOLA 1
   QUOTA_H_SFOGLIATORE : REAL ;	//Quota impostata altezza sfogliatore
   QUOTA_H_CENTRATORE : REAL ;	//Quota impostata altezza centratore
   word16 : S5TIME ;
   INCLINAZ_TAVOLA_ESCLUSA : BOOL ;	//INCLINAZIONE TAVOLA ESCLUSA
   dword20 : REAL ;
   dword24 : REAL ;
   dword28 : REAL ;
   dword32 : REAL ;
   dword36 : REAL ;
   NR_MATRICOLA : INT  := 1;	//Numero di matricola
   word42 : WORD ;
   MAGNETE_1_ESCLUSO : BOOL ;	//MAGNETE 1 ESCLUSO DA MP270
   MAGNETE_2_ESCLUSO : BOOL ;	//MAGNETE 2 ESCLUSO DA MP270
   MAGNETE_3_ESCLUSO : BOOL ;	//MAGNETE 3 ESCLUSO DA MP270
   MAGNETE_4_ESCLUSO : BOOL ;	//MAGNETE 4 ESCLUSO DA MP270
   MAGNETE_5_ESCLUSO : BOOL ;	//MAGNETE 5 ESCLUSO DA MP270
   MAGNETE_6_ESCLUSO : BOOL ;	//MAGNETE 6 ESCLUSO DA MP270
   MAGNETE_LAT_SX_ESCLUSO : BOOL ;	//MAGNETE LATERALE SX ESCLUSO DA MP270
   MAGNETE_LAT_DX_ESCLUSO : BOOL ;	//MAGNETE LATERALE DX ESCLUSO DA MP270
   COMPENSAZ_TAV_2 : REAL ;	//COMPENSAZIONE TAVOLA 2
   STAT22 : WORD ;
   STAT23 : WORD ;
   STAT24 : WORD ;
   STAT25 : WORD ;
   STAT251 : WORD ;
   STAT26 : TIME ;
   STAT29 : TIME ;
   STAT30 : TIME ;
   STAT31 : TIME ;
   C1_Timer : REAL ;	//Centratore 1: Timer ritardo partenza
   C2_Timer : REAL ;	//Centratore 2: Timer ritardo partenza
   C3_Timer : REAL ;	//Centratore 3: Timer ritardo partenza
   C4_Timer : REAL ;	//Centratore 4: Timer ritardo partenza
   C5_Timer : REAL ;	//Centratore 5: Timer ritardo partenza
   C6_Timer : REAL ;	//Centratore 6: Timer ritardo partenza
   C1_Posizione_1 : DINT  := L#500000;	//Centratore 1: Posizione 1 di avicinamento
   C1_Posizione_2 : DINT  := L#520000;	//Centratore 1: Posizione 2 di cambio velocita'
   C1_Posizione_3 : DINT  := L#530000;	//Centratore 1: Posizione 3 di cambio velocita'
   C1_Posizione_4 : DINT  := L#565400;	//Centratore 1: Posizione 4 di arrivo
   C1_Velocita_1 : DINT  := L#50;	//Centratore 1: Velocita' 1 di avvicinamento
   C1_Velocita_2 : DINT  := L#50;	//Centratore 1: Velocita' 2
   C1_Velocita_3 : DINT  := L#50;	//Centratore 1: Velocita' 3
   C1_Velocita_4 : DINT  := L#50;	//Centratore 1: Velocita' 4 di arrivo
   C1_Accell_1 : DINT  := L#500;	//Centratore 1: Accelerazione 1 di avvicinamento
   C1_Accell_2 : DINT  := L#500;	//Centratore 1: Accelerazione 2
   C1_Accell_3 : DINT  := L#500;	//Centratore 1: Accelerazione 3
   C1_Accell_4 : DINT  := L#500;	//Centratore 1: Accelerazione 4 di arrivo
   word_148 : WORD ;
   C2_Posizione_1 : DINT  := L#500000;	//Centratore 2: Posizione 1 di avicinamento
   C2_Posizione_2 : DINT  := L#520000;	//Centratore 2: Posizione 2 di cambio velocita'
   C2_Posizione_3 : DINT  := L#530000;	//Centratore 2: Posizione 3 di cambio velocita'
   C2_Posizione_4 : DINT  := L#559000;	//Centratore 2: Posizione 4 di arrivo
   C2_Velocita_1 : DINT  := L#50;	//Centratore 2: Velocita' 1 di avvicinamento
   C2_Velocita_2 : DINT  := L#50;	//Centratore 2: Velocita' 2
   C2_Velocita_3 : DINT  := L#50;	//Centratore 2: Velocita' 3
   C2_Velocita_4 : DINT  := L#50;	//Centratore 2: Velocita' 4 di arrivo
   C2_Accell_1 : DINT  := L#500;	//Centratore 2: Accelerazione 1 di avvicinamento
   C2_Accell_2 : DINT  := L#500;	//Centratore 2: Accelerazione 2
   C2_Accell_3 : DINT  := L#500;	//Centratore 2: Accelerazione 3
   C2_Accell_4 : DINT  := L#500;	//Centratore 2: Accelerazione 4 di arrivo
   word_198 : WORD ;
   C3_Posizione_1 : DINT  := L#630000;	//Centratore 3: Posizione 1 di avicinamento
   C3_Posizione_2 : DINT  := L#650000;	//Centratore 3: Posizione 2 di cambio velocita'
   C3_Posizione_3 : DINT  := L#660000;	//Centratore 3: Posizione 3 di cambio velocita'
   C3_Posizione_4 : DINT  := L#698600;	//Centratore 3: Posizione 4 di arrivo
   C3_Velocita_1 : DINT  := L#50;	//Centratore 3: Velocita' 1 di avvicinamento
   C3_Velocita_2 : DINT  := L#50;	//Centratore 3: Velocita' 2
   C3_Velocita_3 : DINT  := L#50;	//Centratore 3: Velocita' 3
   C3_Velocita_4 : DINT  := L#50;	//Centratore 3: Velocita' 4 di arrivo
   C3_Accell_1 : DINT  := L#500;	//Centratore 3: Accelerazione 1 di avvicinamento
   C3_Accell_2 : DINT  := L#500;	//Centratore 3: Accelerazione 2
   C3_Accell_3 : DINT  := L#500;	//Centratore 3: Accelerazione 3
   C3_Accell_4 : DINT  := L#500;	//Centratore 3: Accelerazione 4 di arrivo
   word_248 : WORD ;
   C4_Posizione_1 : DINT  := L#630000;	//Centratore 4: Posizione 1 di avicinamento
   C4_Posizione_2 : DINT  := L#650000;	//Centratore 4: Posizione 2 di cambio velocita'
   C4_Posizione_3 : DINT  := L#660000;	//Centratore 4: Posizione 3 di cambio velocita'
   C4_Posizione_4 : DINT  := L#706200;	//Centratore 4: Posizione 4 di arrivo
   C4_Velocita_1 : DINT  := L#50;	//Centratore 4: Velocita' 1 di avvicinamento
   C4_Velocita_2 : DINT  := L#50;	//Centratore 4: Velocita' 2
   C4_Velocita_3 : DINT  := L#50;	//Centratore 4: Velocita' 3
   C4_Velocita_4 : DINT  := L#50;	//Centratore 4: Velocita' 4 di arrivo
   C4_Accell_1 : DINT  := L#500;	//Centratore 4: Accelerazione 1 di avvicinamento
   C4_Accell_2 : DINT  := L#500;	//Centratore 4: Accelerazione 2
   C4_Accell_3 : DINT  := L#500;	//Centratore 4: Accelerazione 3
   C4_Accell_4 : DINT  := L#500;	//Centratore 4: Accelerazione 4 di arrivo
   word_298 : WORD ;
   C5_Posizione_1 : DINT  := L#1180000;	//Centratore 5: Posizione 1 di avicinamento
   C5_Posizione_2 : DINT  := L#1200000;	//Centratore 5: Posizione 2 di cambio velocita'
   C5_Posizione_3 : DINT  := L#1220000;	//Centratore 5: Posizione 3 di cambio velocita'
   C5_Posizione_4 : DINT  := L#1247000;	//Centratore 5: Posizione 4 di arrivo
   C5_Velocita_1 : DINT  := L#50;	//Centratore 5: Velocita' 1 di avvicinamento
   C5_Velocita_2 : DINT  := L#50;	//Centratore 5: Velocita' 2
   C5_Velocita_3 : DINT  := L#50;	//Centratore 5: Velocita' 3
   C5_Velocita_4 : DINT  := L#50;	//Centratore 5: Velocita' 4 di arrivo
   C5_Accell_1 : DINT  := L#500;	//Centratore 5: Accelerazione 1 di avvicinamento
   C5_Accell_2 : DINT  := L#500;	//Centratore 5: Accelerazione 2
   C5_Accell_3 : DINT  := L#500;	//Centratore 5: Accelerazione 3
   C5_Accell_4 : DINT  := L#500;	//Centratore 5: Accelerazione 4 di arrivo
   word_348 : WORD ;
   C6_Posizione_1 : DINT  := L#1180000;	//Centratore 6: Posizione 1 di avicinamento
   C6_Posizione_2 : DINT  := L#1200000;	//Centratore 6: Posizione 2 di cambio velocita'
   C6_Posizione_3 : DINT  := L#1220000;	//Centratore 6: Posizione 3 di cambio velocita'
   C6_Posizione_4 : DINT  := L#1237400;	//Centratore 6: Posizione 4 di arrivo
   C6_Velocita_1 : DINT  := L#50;	//Centratore 6: Velocita' 1 di avvicinamento
   C6_Velocita_2 : DINT  := L#50;	//Centratore 6: Velocita' 2
   C6_Velocita_3 : DINT  := L#50;	//Centratore 6: Velocita' 3
   C6_Velocita_4 : DINT  := L#50;	//Centratore 6: Velocita' 4 di arrivo
   C6_Accell_1 : DINT  := L#500;	//Centratore 6: Accelerazione 1 di avvicinamento
   C6_Accell_2 : DINT  := L#500;	//Centratore 6: Accelerazione 2
   C6_Accell_3 : DINT  := L#500;	//Centratore 6: Accelerazione 3
   C6_Accell_4 : DINT  := L#500;	//Centratore 6: Accelerazione 4 di arrivo
   word_398 : WORD ;
  END_STRUCT ;
BEGIN
   LARGHEZZA_LAMIERA := 3.060000e+003;
   COMPENSAZ_TAV_1 := -7.000000e+001;
   QUOTA_H_SFOGLIATORE := 2.000000e+003;
   QUOTA_H_CENTRATORE := 1.960000e+003;
   word16 := S5T#0MS;
   INCLINAZ_TAVOLA_ESCLUSA := FALSE;
   dword20 := 0.000000e+000;
   dword24 := 0.000000e+000;
   dword28 := 0.000000e+000;
   dword32 := 0.000000e+000;
   dword36 := 0.000000e+000;
   NR_MATRICOLA := 2;
   word42 := W#16#0;
   MAGNETE_1_ESCLUSO := FALSE;
   MAGNETE_2_ESCLUSO := FALSE;
   MAGNETE_3_ESCLUSO := FALSE;
   MAGNETE_4_ESCLUSO := FALSE;
   MAGNETE_5_ESCLUSO := FALSE;
   MAGNETE_6_ESCLUSO := FALSE;
   MAGNETE_LAT_SX_ESCLUSO := FALSE;
   MAGNETE_LAT_DX_ESCLUSO := FALSE;
   COMPENSAZ_TAV_2 := -3.000000e+001;
   STAT22 := W#16#0;
   STAT23 := W#16#0;
   STAT24 := W#16#0;
   STAT25 := W#16#0;
   STAT251 := W#16#0;
   STAT26 := T#0MS;
   STAT29 := T#0MS;
   STAT30 := T#0MS;
   STAT31 := T#0MS;
   C1_Timer := 0.000000e+000;
   C2_Timer := 0.000000e+000;
   C3_Timer := 0.000000e+000;
   C4_Timer := 0.000000e+000;
   C5_Timer := 0.000000e+000;
   C6_Timer := 0.000000e+000;
   C1_Posizione_1 := L#163000;
   C1_Posizione_2 := L#183000;
   C1_Posizione_3 := L#193000;
   C1_Posizione_4 := L#235000;
   C1_Velocita_1 := L#500;
   C1_Velocita_2 := L#200;
   C1_Velocita_3 := L#200;
   C1_Velocita_4 := L#50;
   C1_Accell_1 := L#500;
   C1_Accell_2 := L#500;
   C1_Accell_3 := L#500;
   C1_Accell_4 := L#500;
   word_148 := W#16#0;
   C2_Posizione_1 := L#326000;
   C2_Posizione_2 := L#346000;
   C2_Posizione_3 := L#356000;
   C2_Posizione_4 := L#401000;
   C2_Velocita_1 := L#500;
   C2_Velocita_2 := L#200;
   C2_Velocita_3 := L#200;
   C2_Velocita_4 := L#50;
   C2_Accell_1 := L#500;
   C2_Accell_2 := L#500;
   C2_Accell_3 := L#500;
   C2_Accell_4 := L#500;
   word_198 := W#16#0;
   C3_Posizione_1 := L#200000;
   C3_Posizione_2 := L#220000;
   C3_Posizione_3 := L#230000;
   C3_Posizione_4 := L#385000;
   C3_Velocita_1 := L#500;
   C3_Velocita_2 := L#200;
   C3_Velocita_3 := L#200;
   C3_Velocita_4 := L#50;
   C3_Accell_1 := L#500;
   C3_Accell_2 := L#500;
   C3_Accell_3 := L#500;
   C3_Accell_4 := L#500;
   word_248 := W#16#0;
   C4_Posizione_1 := L#100000;
   C4_Posizione_2 := L#120000;
   C4_Posizione_3 := L#130000;
   C4_Posizione_4 := L#283000;
   C4_Velocita_1 := L#500;
   C4_Velocita_2 := L#200;
   C4_Velocita_3 := L#200;
   C4_Velocita_4 := L#50;
   C4_Accell_1 := L#500;
   C4_Accell_2 := L#500;
   C4_Accell_3 := L#500;
   C4_Accell_4 := L#500;
   word_298 := W#16#0;
   C5_Posizione_1 := L#395000;
   C5_Posizione_2 := L#415000;
   C5_Posizione_3 := L#425000;
   C5_Posizione_4 := L#510000;
   C5_Velocita_1 := L#500;
   C5_Velocita_2 := L#200;
   C5_Velocita_3 := L#200;
   C5_Velocita_4 := L#50;
   C5_Accell_1 := L#500;
   C5_Accell_2 := L#500;
   C5_Accell_3 := L#500;
   C5_Accell_4 := L#500;
   word_348 := W#16#0;
   C6_Posizione_1 := L#430000;
   C6_Posizione_2 := L#450000;
   C6_Posizione_3 := L#460000;
   C6_Posizione_4 := L#525000;
   C6_Velocita_1 := L#500;
   C6_Velocita_2 := L#200;
   C6_Velocita_3 := L#200;
   C6_Velocita_4 := L#50;
   C6_Accell_1 := L#500;
   C6_Accell_2 := L#500;
   C6_Accell_3 := L#500;
   C6_Accell_4 := L#500;
   word_398 := W#16#0;
END_DATA_BLOCK

DATA_BLOCK "MATRICOLA 18"
AUTHOR : Lodato
FAMILY : DESTACK
NAME : DATI
VERSION : 0.1


  STRUCT
   LARGHEZZA_LAMIERA : REAL  := 1.500000e+003;	//LARGHEZZA LAMIERA ATTUALE
   COMPENSAZ_TAV_1 : REAL ;	//COMPENSAZIONE TAVOLA 1
   QUOTA_H_SFOGLIATORE : REAL ;	//Quota impostata altezza sfogliatore
   QUOTA_H_CENTRATORE : REAL ;	//Quota impostata altezza centratore
   word16 : S5TIME ;
   INCLINAZ_TAVOLA_ESCLUSA : BOOL ;	//INCLINAZIONE TAVOLA ESCLUSA
   dword20 : REAL ;
   dword24 : REAL ;
   dword28 : REAL ;
   dword32 : REAL ;
   dword36 : REAL ;
   NR_MATRICOLA : INT  := 1;	//Numero di matricola
   word42 : WORD ;
   MAGNETE_1_ESCLUSO : BOOL ;	//MAGNETE 1 ESCLUSO DA MP270
   MAGNETE_2_ESCLUSO : BOOL ;	//MAGNETE 2 ESCLUSO DA MP270
   MAGNETE_3_ESCLUSO : BOOL ;	//MAGNETE 3 ESCLUSO DA MP270
   MAGNETE_4_ESCLUSO : BOOL ;	//MAGNETE 4 ESCLUSO DA MP270
   MAGNETE_5_ESCLUSO : BOOL ;	//MAGNETE 5 ESCLUSO DA MP270
   MAGNETE_6_ESCLUSO : BOOL ;	//MAGNETE 6 ESCLUSO DA MP270
   MAGNETE_LAT_SX_ESCLUSO : BOOL ;	//MAGNETE LATERALE SX ESCLUSO DA MP270
   MAGNETE_LAT_DX_ESCLUSO : BOOL ;	//MAGNETE LATERALE DX ESCLUSO DA MP270
   COMPENSAZ_TAV_2 : REAL ;	//COMPENSAZIONE TAVOLA 2
   STAT22 : WORD ;
   STAT23 : WORD ;
   STAT24 : WORD ;
   STAT25 : WORD ;
   STAT251 : WORD ;
   STAT26 : TIME ;
   STAT29 : TIME ;
   STAT30 : TIME ;
   STAT31 : TIME ;
   C1_Timer : REAL ;	//Centratore 1: Timer ritardo partenza
   C2_Timer : REAL ;	//Centratore 2: Timer ritardo partenza
   C3_Timer : REAL ;	//Centratore 3: Timer ritardo partenza
   C4_Timer : REAL ;	//Centratore 4: Timer ritardo partenza
   C5_Timer : REAL ;	//Centratore 5: Timer ritardo partenza
   C6_Timer : REAL ;	//Centratore 6: Timer ritardo partenza
   C1_Posizione_1 : DINT  := L#500000;	//Centratore 1: Posizione 1 di avicinamento
   C1_Posizione_2 : DINT  := L#520000;	//Centratore 1: Posizione 2 di cambio velocita'
   C1_Posizione_3 : DINT  := L#530000;	//Centratore 1: Posizione 3 di cambio velocita'
   C1_Posizione_4 : DINT  := L#565400;	//Centratore 1: Posizione 4 di arrivo
   C1_Velocita_1 : DINT  := L#50;	//Centratore 1: Velocita' 1 di avvicinamento
   C1_Velocita_2 : DINT  := L#50;	//Centratore 1: Velocita' 2
   C1_Velocita_3 : DINT  := L#50;	//Centratore 1: Velocita' 3
   C1_Velocita_4 : DINT  := L#50;	//Centratore 1: Velocita' 4 di arrivo
   C1_Accell_1 : DINT  := L#500;	//Centratore 1: Accelerazione 1 di avvicinamento
   C1_Accell_2 : DINT  := L#500;	//Centratore 1: Accelerazione 2
   C1_Accell_3 : DINT  := L#500;	//Centratore 1: Accelerazione 3
   C1_Accell_4 : DINT  := L#500;	//Centratore 1: Accelerazione 4 di arrivo
   word_148 : WORD ;
   C2_Posizione_1 : DINT  := L#500000;	//Centratore 2: Posizione 1 di avicinamento
   C2_Posizione_2 : DINT  := L#520000;	//Centratore 2: Posizione 2 di cambio velocita'
   C2_Posizione_3 : DINT  := L#530000;	//Centratore 2: Posizione 3 di cambio velocita'
   C2_Posizione_4 : DINT  := L#559000;	//Centratore 2: Posizione 4 di arrivo
   C2_Velocita_1 : DINT  := L#50;	//Centratore 2: Velocita' 1 di avvicinamento
   C2_Velocita_2 : DINT  := L#50;	//Centratore 2: Velocita' 2
   C2_Velocita_3 : DINT  := L#50;	//Centratore 2: Velocita' 3
   C2_Velocita_4 : DINT  := L#50;	//Centratore 2: Velocita' 4 di arrivo
   C2_Accell_1 : DINT  := L#500;	//Centratore 2: Accelerazione 1 di avvicinamento
   C2_Accell_2 : DINT  := L#500;	//Centratore 2: Accelerazione 2
   C2_Accell_3 : DINT  := L#500;	//Centratore 2: Accelerazione 3
   C2_Accell_4 : DINT  := L#500;	//Centratore 2: Accelerazione 4 di arrivo
   word_198 : WORD ;
   C3_Posizione_1 : DINT  := L#630000;	//Centratore 3: Posizione 1 di avicinamento
   C3_Posizione_2 : DINT  := L#650000;	//Centratore 3: Posizione 2 di cambio velocita'
   C3_Posizione_3 : DINT  := L#660000;	//Centratore 3: Posizione 3 di cambio velocita'
   C3_Posizione_4 : DINT  := L#698600;	//Centratore 3: Posizione 4 di arrivo
   C3_Velocita_1 : DINT  := L#50;	//Centratore 3: Velocita' 1 di avvicinamento
   C3_Velocita_2 : DINT  := L#50;	//Centratore 3: Velocita' 2
   C3_Velocita_3 : DINT  := L#50;	//Centratore 3: Velocita' 3
   C3_Velocita_4 : DINT  := L#50;	//Centratore 3: Velocita' 4 di arrivo
   C3_Accell_1 : DINT  := L#500;	//Centratore 3: Accelerazione 1 di avvicinamento
   C3_Accell_2 : DINT  := L#500;	//Centratore 3: Accelerazione 2
   C3_Accell_3 : DINT  := L#500;	//Centratore 3: Accelerazione 3
   C3_Accell_4 : DINT  := L#500;	//Centratore 3: Accelerazione 4 di arrivo
   word_248 : WORD ;
   C4_Posizione_1 : DINT  := L#630000;	//Centratore 4: Posizione 1 di avicinamento
   C4_Posizione_2 : DINT  := L#650000;	//Centratore 4: Posizione 2 di cambio velocita'
   C4_Posizione_3 : DINT  := L#660000;	//Centratore 4: Posizione 3 di cambio velocita'
   C4_Posizione_4 : DINT  := L#706200;	//Centratore 4: Posizione 4 di arrivo
   C4_Velocita_1 : DINT  := L#50;	//Centratore 4: Velocita' 1 di avvicinamento
   C4_Velocita_2 : DINT  := L#50;	//Centratore 4: Velocita' 2
   C4_Velocita_3 : DINT  := L#50;	//Centratore 4: Velocita' 3
   C4_Velocita_4 : DINT  := L#50;	//Centratore 4: Velocita' 4 di arrivo
   C4_Accell_1 : DINT  := L#500;	//Centratore 4: Accelerazione 1 di avvicinamento
   C4_Accell_2 : DINT  := L#500;	//Centratore 4: Accelerazione 2
   C4_Accell_3 : DINT  := L#500;	//Centratore 4: Accelerazione 3
   C4_Accell_4 : DINT  := L#500;	//Centratore 4: Accelerazione 4 di arrivo
   word_298 : WORD ;
   C5_Posizione_1 : DINT  := L#1180000;	//Centratore 5: Posizione 1 di avicinamento
   C5_Posizione_2 : DINT  := L#1200000;	//Centratore 5: Posizione 2 di cambio velocita'
   C5_Posizione_3 : DINT  := L#1220000;	//Centratore 5: Posizione 3 di cambio velocita'
   C5_Posizione_4 : DINT  := L#1247000;	//Centratore 5: Posizione 4 di arrivo
   C5_Velocita_1 : DINT  := L#50;	//Centratore 5: Velocita' 1 di avvicinamento
   C5_Velocita_2 : DINT  := L#50;	//Centratore 5: Velocita' 2
   C5_Velocita_3 : DINT  := L#50;	//Centratore 5: Velocita' 3
   C5_Velocita_4 : DINT  := L#50;	//Centratore 5: Velocita' 4 di arrivo
   C5_Accell_1 : DINT  := L#500;	//Centratore 5: Accelerazione 1 di avvicinamento
   C5_Accell_2 : DINT  := L#500;	//Centratore 5: Accelerazione 2
   C5_Accell_3 : DINT  := L#500;	//Centratore 5: Accelerazione 3
   C5_Accell_4 : DINT  := L#500;	//Centratore 5: Accelerazione 4 di arrivo
   word_348 : WORD ;
   C6_Posizione_1 : DINT  := L#1180000;	//Centratore 6: Posizione 1 di avicinamento
   C6_Posizione_2 : DINT  := L#1200000;	//Centratore 6: Posizione 2 di cambio velocita'
   C6_Posizione_3 : DINT  := L#1220000;	//Centratore 6: Posizione 3 di cambio velocita'
   C6_Posizione_4 : DINT  := L#1237400;	//Centratore 6: Posizione 4 di arrivo
   C6_Velocita_1 : DINT  := L#50;	//Centratore 6: Velocita' 1 di avvicinamento
   C6_Velocita_2 : DINT  := L#50;	//Centratore 6: Velocita' 2
   C6_Velocita_3 : DINT  := L#50;	//Centratore 6: Velocita' 3
   C6_Velocita_4 : DINT  := L#50;	//Centratore 6: Velocita' 4 di arrivo
   C6_Accell_1 : DINT  := L#500;	//Centratore 6: Accelerazione 1 di avvicinamento
   C6_Accell_2 : DINT  := L#500;	//Centratore 6: Accelerazione 2
   C6_Accell_3 : DINT  := L#500;	//Centratore 6: Accelerazione 3
   C6_Accell_4 : DINT  := L#500;	//Centratore 6: Accelerazione 4 di arrivo
   word_398 : WORD ;
  END_STRUCT ;
BEGIN
   LARGHEZZA_LAMIERA := 3.060000e+003;
   COMPENSAZ_TAV_1 := -7.000000e+001;
   QUOTA_H_SFOGLIATORE := 2.000000e+003;
   QUOTA_H_CENTRATORE := 1.960000e+003;
   word16 := S5T#0MS;
   INCLINAZ_TAVOLA_ESCLUSA := FALSE;
   dword20 := 0.000000e+000;
   dword24 := 0.000000e+000;
   dword28 := 0.000000e+000;
   dword32 := 0.000000e+000;
   dword36 := 0.000000e+000;
   NR_MATRICOLA := 2;
   word42 := W#16#0;
   MAGNETE_1_ESCLUSO := FALSE;
   MAGNETE_2_ESCLUSO := FALSE;
   MAGNETE_3_ESCLUSO := FALSE;
   MAGNETE_4_ESCLUSO := FALSE;
   MAGNETE_5_ESCLUSO := FALSE;
   MAGNETE_6_ESCLUSO := FALSE;
   MAGNETE_LAT_SX_ESCLUSO := FALSE;
   MAGNETE_LAT_DX_ESCLUSO := FALSE;
   COMPENSAZ_TAV_2 := -3.000000e+001;
   STAT22 := W#16#0;
   STAT23 := W#16#0;
   STAT24 := W#16#0;
   STAT25 := W#16#0;
   STAT251 := W#16#0;
   STAT26 := T#0MS;
   STAT29 := T#0MS;
   STAT30 := T#0MS;
   STAT31 := T#0MS;
   C1_Timer := 0.000000e+000;
   C2_Timer := 0.000000e+000;
   C3_Timer := 0.000000e+000;
   C4_Timer := 0.000000e+000;
   C5_Timer := 0.000000e+000;
   C6_Timer := 0.000000e+000;
   C1_Posizione_1 := L#163000;
   C1_Posizione_2 := L#183000;
   C1_Posizione_3 := L#193000;
   C1_Posizione_4 := L#235000;
   C1_Velocita_1 := L#500;
   C1_Velocita_2 := L#200;
   C1_Velocita_3 := L#200;
   C1_Velocita_4 := L#50;
   C1_Accell_1 := L#500;
   C1_Accell_2 := L#500;
   C1_Accell_3 := L#500;
   C1_Accell_4 := L#500;
   word_148 := W#16#0;
   C2_Posizione_1 := L#326000;
   C2_Posizione_2 := L#346000;
   C2_Posizione_3 := L#356000;
   C2_Posizione_4 := L#401000;
   C2_Velocita_1 := L#500;
   C2_Velocita_2 := L#200;
   C2_Velocita_3 := L#200;
   C2_Velocita_4 := L#50;
   C2_Accell_1 := L#500;
   C2_Accell_2 := L#500;
   C2_Accell_3 := L#500;
   C2_Accell_4 := L#500;
   word_198 := W#16#0;
   C3_Posizione_1 := L#200000;
   C3_Posizione_2 := L#220000;
   C3_Posizione_3 := L#230000;
   C3_Posizione_4 := L#385000;
   C3_Velocita_1 := L#500;
   C3_Velocita_2 := L#200;
   C3_Velocita_3 := L#200;
   C3_Velocita_4 := L#50;
   C3_Accell_1 := L#500;
   C3_Accell_2 := L#500;
   C3_Accell_3 := L#500;
   C3_Accell_4 := L#500;
   word_248 := W#16#0;
   C4_Posizione_1 := L#100000;
   C4_Posizione_2 := L#120000;
   C4_Posizione_3 := L#130000;
   C4_Posizione_4 := L#283000;
   C4_Velocita_1 := L#500;
   C4_Velocita_2 := L#200;
   C4_Velocita_3 := L#200;
   C4_Velocita_4 := L#50;
   C4_Accell_1 := L#500;
   C4_Accell_2 := L#500;
   C4_Accell_3 := L#500;
   C4_Accell_4 := L#500;
   word_298 := W#16#0;
   C5_Posizione_1 := L#395000;
   C5_Posizione_2 := L#415000;
   C5_Posizione_3 := L#425000;
   C5_Posizione_4 := L#510000;
   C5_Velocita_1 := L#500;
   C5_Velocita_2 := L#200;
   C5_Velocita_3 := L#200;
   C5_Velocita_4 := L#50;
   C5_Accell_1 := L#500;
   C5_Accell_2 := L#500;
   C5_Accell_3 := L#500;
   C5_Accell_4 := L#500;
   word_348 := W#16#0;
   C6_Posizione_1 := L#430000;
   C6_Posizione_2 := L#450000;
   C6_Posizione_3 := L#460000;
   C6_Posizione_4 := L#525000;
   C6_Velocita_1 := L#500;
   C6_Velocita_2 := L#200;
   C6_Velocita_3 := L#200;
   C6_Velocita_4 := L#50;
   C6_Accell_1 := L#500;
   C6_Accell_2 := L#500;
   C6_Accell_3 := L#500;
   C6_Accell_4 := L#500;
   word_398 := W#16#0;
END_DATA_BLOCK

DATA_BLOCK "MATRICOLA 19"
AUTHOR : Lodato
FAMILY : DESTACK
NAME : DATI
VERSION : 0.1


  STRUCT
   LARGHEZZA_LAMIERA : REAL  := 1.500000e+003;	//LARGHEZZA LAMIERA ATTUALE
   COMPENSAZ_TAV_1 : REAL ;	//COMPENSAZIONE TAVOLA 1
   QUOTA_H_SFOGLIATORE : REAL ;	//Quota impostata altezza sfogliatore
   QUOTA_H_CENTRATORE : REAL ;	//Quota impostata altezza centratore
   word16 : S5TIME ;
   INCLINAZ_TAVOLA_ESCLUSA : BOOL ;	//INCLINAZIONE TAVOLA ESCLUSA
   dword20 : REAL ;
   dword24 : REAL ;
   dword28 : REAL ;
   dword32 : REAL ;
   dword36 : REAL ;
   NR_MATRICOLA : INT  := 1;	//Numero di matricola
   word42 : WORD ;
   MAGNETE_1_ESCLUSO : BOOL ;	//MAGNETE 1 ESCLUSO DA MP270
   MAGNETE_2_ESCLUSO : BOOL ;	//MAGNETE 2 ESCLUSO DA MP270
   MAGNETE_3_ESCLUSO : BOOL ;	//MAGNETE 3 ESCLUSO DA MP270
   MAGNETE_4_ESCLUSO : BOOL ;	//MAGNETE 4 ESCLUSO DA MP270
   MAGNETE_5_ESCLUSO : BOOL ;	//MAGNETE 5 ESCLUSO DA MP270
   MAGNETE_6_ESCLUSO : BOOL ;	//MAGNETE 6 ESCLUSO DA MP270
   MAGNETE_LAT_SX_ESCLUSO : BOOL ;	//MAGNETE LATERALE SX ESCLUSO DA MP270
   MAGNETE_LAT_DX_ESCLUSO : BOOL ;	//MAGNETE LATERALE DX ESCLUSO DA MP270
   COMPENSAZ_TAV_2 : REAL ;	//COMPENSAZIONE TAVOLA 2
   STAT22 : WORD ;
   STAT23 : WORD ;
   STAT24 : WORD ;
   STAT25 : WORD ;
   STAT251 : WORD ;
   STAT26 : TIME ;
   STAT29 : TIME ;
   STAT30 : TIME ;
   STAT31 : TIME ;
   C1_Timer : REAL ;	//Centratore 1: Timer ritardo partenza
   C2_Timer : REAL ;	//Centratore 2: Timer ritardo partenza
   C3_Timer : REAL ;	//Centratore 3: Timer ritardo partenza
   C4_Timer : REAL ;	//Centratore 4: Timer ritardo partenza
   C5_Timer : REAL ;	//Centratore 5: Timer ritardo partenza
   C6_Timer : REAL ;	//Centratore 6: Timer ritardo partenza
   C1_Posizione_1 : DINT  := L#500000;	//Centratore 1: Posizione 1 di avicinamento
   C1_Posizione_2 : DINT  := L#520000;	//Centratore 1: Posizione 2 di cambio velocita'
   C1_Posizione_3 : DINT  := L#530000;	//Centratore 1: Posizione 3 di cambio velocita'
   C1_Posizione_4 : DINT  := L#565400;	//Centratore 1: Posizione 4 di arrivo
   C1_Velocita_1 : DINT  := L#50;	//Centratore 1: Velocita' 1 di avvicinamento
   C1_Velocita_2 : DINT  := L#50;	//Centratore 1: Velocita' 2
   C1_Velocita_3 : DINT  := L#50;	//Centratore 1: Velocita' 3
   C1_Velocita_4 : DINT  := L#50;	//Centratore 1: Velocita' 4 di arrivo
   C1_Accell_1 : DINT  := L#500;	//Centratore 1: Accelerazione 1 di avvicinamento
   C1_Accell_2 : DINT  := L#500;	//Centratore 1: Accelerazione 2
   C1_Accell_3 : DINT  := L#500;	//Centratore 1: Accelerazione 3
   C1_Accell_4 : DINT  := L#500;	//Centratore 1: Accelerazione 4 di arrivo
   word_148 : WORD ;
   C2_Posizione_1 : DINT  := L#500000;	//Centratore 2: Posizione 1 di avicinamento
   C2_Posizione_2 : DINT  := L#520000;	//Centratore 2: Posizione 2 di cambio velocita'
   C2_Posizione_3 : DINT  := L#530000;	//Centratore 2: Posizione 3 di cambio velocita'
   C2_Posizione_4 : DINT  := L#559000;	//Centratore 2: Posizione 4 di arrivo
   C2_Velocita_1 : DINT  := L#50;	//Centratore 2: Velocita' 1 di avvicinamento
   C2_Velocita_2 : DINT  := L#50;	//Centratore 2: Velocita' 2
   C2_Velocita_3 : DINT  := L#50;	//Centratore 2: Velocita' 3
   C2_Velocita_4 : DINT  := L#50;	//Centratore 2: Velocita' 4 di arrivo
   C2_Accell_1 : DINT  := L#500;	//Centratore 2: Accelerazione 1 di avvicinamento
   C2_Accell_2 : DINT  := L#500;	//Centratore 2: Accelerazione 2
   C2_Accell_3 : DINT  := L#500;	//Centratore 2: Accelerazione 3
   C2_Accell_4 : DINT  := L#500;	//Centratore 2: Accelerazione 4 di arrivo
   word_198 : WORD ;
   C3_Posizione_1 : DINT  := L#630000;	//Centratore 3: Posizione 1 di avicinamento
   C3_Posizione_2 : DINT  := L#650000;	//Centratore 3: Posizione 2 di cambio velocita'
   C3_Posizione_3 : DINT  := L#660000;	//Centratore 3: Posizione 3 di cambio velocita'
   C3_Posizione_4 : DINT  := L#698600;	//Centratore 3: Posizione 4 di arrivo
   C3_Velocita_1 : DINT  := L#50;	//Centratore 3: Velocita' 1 di avvicinamento
   C3_Velocita_2 : DINT  := L#50;	//Centratore 3: Velocita' 2
   C3_Velocita_3 : DINT  := L#50;	//Centratore 3: Velocita' 3
   C3_Velocita_4 : DINT  := L#50;	//Centratore 3: Velocita' 4 di arrivo
   C3_Accell_1 : DINT  := L#500;	//Centratore 3: Accelerazione 1 di avvicinamento
   C3_Accell_2 : DINT  := L#500;	//Centratore 3: Accelerazione 2
   C3_Accell_3 : DINT  := L#500;	//Centratore 3: Accelerazione 3
   C3_Accell_4 : DINT  := L#500;	//Centratore 3: Accelerazione 4 di arrivo
   word_248 : WORD ;
   C4_Posizione_1 : DINT  := L#630000;	//Centratore 4: Posizione 1 di avicinamento
   C4_Posizione_2 : DINT  := L#650000;	//Centratore 4: Posizione 2 di cambio velocita'
   C4_Posizione_3 : DINT  := L#660000;	//Centratore 4: Posizione 3 di cambio velocita'
   C4_Posizione_4 : DINT  := L#706200;	//Centratore 4: Posizione 4 di arrivo
   C4_Velocita_1 : DINT  := L#50;	//Centratore 4: Velocita' 1 di avvicinamento
   C4_Velocita_2 : DINT  := L#50;	//Centratore 4: Velocita' 2
   C4_Velocita_3 : DINT  := L#50;	//Centratore 4: Velocita' 3
   C4_Velocita_4 : DINT  := L#50;	//Centratore 4: Velocita' 4 di arrivo
   C4_Accell_1 : DINT  := L#500;	//Centratore 4: Accelerazione 1 di avvicinamento
   C4_Accell_2 : DINT  := L#500;	//Centratore 4: Accelerazione 2
   C4_Accell_3 : DINT  := L#500;	//Centratore 4: Accelerazione 3
   C4_Accell_4 : DINT  := L#500;	//Centratore 4: Accelerazione 4 di arrivo
   word_298 : WORD ;
   C5_Posizione_1 : DINT  := L#1180000;	//Centratore 5: Posizione 1 di avicinamento
   C5_Posizione_2 : DINT  := L#1200000;	//Centratore 5: Posizione 2 di cambio velocita'
   C5_Posizione_3 : DINT  := L#1220000;	//Centratore 5: Posizione 3 di cambio velocita'
   C5_Posizione_4 : DINT  := L#1247000;	//Centratore 5: Posizione 4 di arrivo
   C5_Velocita_1 : DINT  := L#50;	//Centratore 5: Velocita' 1 di avvicinamento
   C5_Velocita_2 : DINT  := L#50;	//Centratore 5: Velocita' 2
   C5_Velocita_3 : DINT  := L#50;	//Centratore 5: Velocita' 3
   C5_Velocita_4 : DINT  := L#50;	//Centratore 5: Velocita' 4 di arrivo
   C5_Accell_1 : DINT  := L#500;	//Centratore 5: Accelerazione 1 di avvicinamento
   C5_Accell_2 : DINT  := L#500;	//Centratore 5: Accelerazione 2
   C5_Accell_3 : DINT  := L#500;	//Centratore 5: Accelerazione 3
   C5_Accell_4 : DINT  := L#500;	//Centratore 5: Accelerazione 4 di arrivo
   word_348 : WORD ;
   C6_Posizione_1 : DINT  := L#1180000;	//Centratore 6: Posizione 1 di avicinamento
   C6_Posizione_2 : DINT  := L#1200000;	//Centratore 6: Posizione 2 di cambio velocita'
   C6_Posizione_3 : DINT  := L#1220000;	//Centratore 6: Posizione 3 di cambio velocita'
   C6_Posizione_4 : DINT  := L#1237400;	//Centratore 6: Posizione 4 di arrivo
   C6_Velocita_1 : DINT  := L#50;	//Centratore 6: Velocita' 1 di avvicinamento
   C6_Velocita_2 : DINT  := L#50;	//Centratore 6: Velocita' 2
   C6_Velocita_3 : DINT  := L#50;	//Centratore 6: Velocita' 3
   C6_Velocita_4 : DINT  := L#50;	//Centratore 6: Velocita' 4 di arrivo
   C6_Accell_1 : DINT  := L#500;	//Centratore 6: Accelerazione 1 di avvicinamento
   C6_Accell_2 : DINT  := L#500;	//Centratore 6: Accelerazione 2
   C6_Accell_3 : DINT  := L#500;	//Centratore 6: Accelerazione 3
   C6_Accell_4 : DINT  := L#500;	//Centratore 6: Accelerazione 4 di arrivo
   word_398 : WORD ;
  END_STRUCT ;
BEGIN
   LARGHEZZA_LAMIERA := 3.060000e+003;
   COMPENSAZ_TAV_1 := -7.000000e+001;
   QUOTA_H_SFOGLIATORE := 2.000000e+003;
   QUOTA_H_CENTRATORE := 1.960000e+003;
   word16 := S5T#0MS;
   INCLINAZ_TAVOLA_ESCLUSA := FALSE;
   dword20 := 0.000000e+000;
   dword24 := 0.000000e+000;
   dword28 := 0.000000e+000;
   dword32 := 0.000000e+000;
   dword36 := 0.000000e+000;
   NR_MATRICOLA := 2;
   word42 := W#16#0;
   MAGNETE_1_ESCLUSO := FALSE;
   MAGNETE_2_ESCLUSO := FALSE;
   MAGNETE_3_ESCLUSO := FALSE;
   MAGNETE_4_ESCLUSO := FALSE;
   MAGNETE_5_ESCLUSO := FALSE;
   MAGNETE_6_ESCLUSO := FALSE;
   MAGNETE_LAT_SX_ESCLUSO := FALSE;
   MAGNETE_LAT_DX_ESCLUSO := FALSE;
   COMPENSAZ_TAV_2 := -3.000000e+001;
   STAT22 := W#16#0;
   STAT23 := W#16#0;
   STAT24 := W#16#0;
   STAT25 := W#16#0;
   STAT251 := W#16#0;
   STAT26 := T#0MS;
   STAT29 := T#0MS;
   STAT30 := T#0MS;
   STAT31 := T#0MS;
   C1_Timer := 0.000000e+000;
   C2_Timer := 0.000000e+000;
   C3_Timer := 0.000000e+000;
   C4_Timer := 0.000000e+000;
   C5_Timer := 0.000000e+000;
   C6_Timer := 0.000000e+000;
   C1_Posizione_1 := L#163000;
   C1_Posizione_2 := L#183000;
   C1_Posizione_3 := L#193000;
   C1_Posizione_4 := L#235000;
   C1_Velocita_1 := L#500;
   C1_Velocita_2 := L#200;
   C1_Velocita_3 := L#200;
   C1_Velocita_4 := L#50;
   C1_Accell_1 := L#500;
   C1_Accell_2 := L#500;
   C1_Accell_3 := L#500;
   C1_Accell_4 := L#500;
   word_148 := W#16#0;
   C2_Posizione_1 := L#326000;
   C2_Posizione_2 := L#346000;
   C2_Posizione_3 := L#356000;
   C2_Posizione_4 := L#401000;
   C2_Velocita_1 := L#500;
   C2_Velocita_2 := L#200;
   C2_Velocita_3 := L#200;
   C2_Velocita_4 := L#50;
   C2_Accell_1 := L#500;
   C2_Accell_2 := L#500;
   C2_Accell_3 := L#500;
   C2_Accell_4 := L#500;
   word_198 := W#16#0;
   C3_Posizione_1 := L#200000;
   C3_Posizione_2 := L#220000;
   C3_Posizione_3 := L#230000;
   C3_Posizione_4 := L#385000;
   C3_Velocita_1 := L#500;
   C3_Velocita_2 := L#200;
   C3_Velocita_3 := L#200;
   C3_Velocita_4 := L#50;
   C3_Accell_1 := L#500;
   C3_Accell_2 := L#500;
   C3_Accell_3 := L#500;
   C3_Accell_4 := L#500;
   word_248 := W#16#0;
   C4_Posizione_1 := L#100000;
   C4_Posizione_2 := L#120000;
   C4_Posizione_3 := L#130000;
   C4_Posizione_4 := L#283000;
   C4_Velocita_1 := L#500;
   C4_Velocita_2 := L#200;
   C4_Velocita_3 := L#200;
   C4_Velocita_4 := L#50;
   C4_Accell_1 := L#500;
   C4_Accell_2 := L#500;
   C4_Accell_3 := L#500;
   C4_Accell_4 := L#500;
   word_298 := W#16#0;
   C5_Posizione_1 := L#395000;
   C5_Posizione_2 := L#415000;
   C5_Posizione_3 := L#425000;
   C5_Posizione_4 := L#510000;
   C5_Velocita_1 := L#500;
   C5_Velocita_2 := L#200;
   C5_Velocita_3 := L#200;
   C5_Velocita_4 := L#50;
   C5_Accell_1 := L#500;
   C5_Accell_2 := L#500;
   C5_Accell_3 := L#500;
   C5_Accell_4 := L#500;
   word_348 := W#16#0;
   C6_Posizione_1 := L#430000;
   C6_Posizione_2 := L#450000;
   C6_Posizione_3 := L#460000;
   C6_Posizione_4 := L#525000;
   C6_Velocita_1 := L#500;
   C6_Velocita_2 := L#200;
   C6_Velocita_3 := L#200;
   C6_Velocita_4 := L#50;
   C6_Accell_1 := L#500;
   C6_Accell_2 := L#500;
   C6_Accell_3 := L#500;
   C6_Accell_4 := L#500;
   word_398 := W#16#0;
END_DATA_BLOCK

DATA_BLOCK "MATRICOLA 20"
AUTHOR : Lodato
FAMILY : DESTACK
NAME : DATI
VERSION : 0.1


  STRUCT
   LARGHEZZA_LAMIERA : REAL  := 1.500000e+003;	//LARGHEZZA LAMIERA ATTUALE
   COMPENSAZ_TAV_1 : REAL ;	//COMPENSAZIONE TAVOLA 1
   QUOTA_H_SFOGLIATORE : REAL ;	//Quota impostata altezza sfogliatore
   QUOTA_H_CENTRATORE : REAL ;	//Quota impostata altezza centratore
   word16 : S5TIME ;
   INCLINAZ_TAVOLA_ESCLUSA : BOOL ;	//INCLINAZIONE TAVOLA ESCLUSA
   dword20 : REAL ;
   dword24 : REAL ;
   dword28 : REAL ;
   dword32 : REAL ;
   dword36 : REAL ;
   NR_MATRICOLA : INT  := 1;	//Numero di matricola
   word42 : WORD ;
   MAGNETE_1_ESCLUSO : BOOL ;	//MAGNETE 1 ESCLUSO DA MP270
   MAGNETE_2_ESCLUSO : BOOL ;	//MAGNETE 2 ESCLUSO DA MP270
   MAGNETE_3_ESCLUSO : BOOL ;	//MAGNETE 3 ESCLUSO DA MP270
   MAGNETE_4_ESCLUSO : BOOL ;	//MAGNETE 4 ESCLUSO DA MP270
   MAGNETE_5_ESCLUSO : BOOL ;	//MAGNETE 5 ESCLUSO DA MP270
   MAGNETE_6_ESCLUSO : BOOL ;	//MAGNETE 6 ESCLUSO DA MP270
   MAGNETE_LAT_SX_ESCLUSO : BOOL ;	//MAGNETE LATERALE SX ESCLUSO DA MP270
   MAGNETE_LAT_DX_ESCLUSO : BOOL ;	//MAGNETE LATERALE DX ESCLUSO DA MP270
   COMPENSAZ_TAV_2 : REAL ;	//COMPENSAZIONE TAVOLA 2
   STAT22 : WORD ;
   STAT23 : WORD ;
   STAT24 : WORD ;
   STAT25 : WORD ;
   STAT251 : WORD ;
   STAT26 : TIME ;
   STAT29 : TIME ;
   STAT30 : TIME ;
   STAT31 : TIME ;
   C1_Timer : REAL ;	//Centratore 1: Timer ritardo partenza
   C2_Timer : REAL ;	//Centratore 2: Timer ritardo partenza
   C3_Timer : REAL ;	//Centratore 3: Timer ritardo partenza
   C4_Timer : REAL ;	//Centratore 4: Timer ritardo partenza
   C5_Timer : REAL ;	//Centratore 5: Timer ritardo partenza
   C6_Timer : REAL ;	//Centratore 6: Timer ritardo partenza
   C1_Posizione_1 : DINT  := L#500000;	//Centratore 1: Posizione 1 di avicinamento
   C1_Posizione_2 : DINT  := L#520000;	//Centratore 1: Posizione 2 di cambio velocita'
   C1_Posizione_3 : DINT  := L#530000;	//Centratore 1: Posizione 3 di cambio velocita'
   C1_Posizione_4 : DINT  := L#565400;	//Centratore 1: Posizione 4 di arrivo
   C1_Velocita_1 : DINT  := L#50;	//Centratore 1: Velocita' 1 di avvicinamento
   C1_Velocita_2 : DINT  := L#50;	//Centratore 1: Velocita' 2
   C1_Velocita_3 : DINT  := L#50;	//Centratore 1: Velocita' 3
   C1_Velocita_4 : DINT  := L#50;	//Centratore 1: Velocita' 4 di arrivo
   C1_Accell_1 : DINT  := L#500;	//Centratore 1: Accelerazione 1 di avvicinamento
   C1_Accell_2 : DINT  := L#500;	//Centratore 1: Accelerazione 2
   C1_Accell_3 : DINT  := L#500;	//Centratore 1: Accelerazione 3
   C1_Accell_4 : DINT  := L#500;	//Centratore 1: Accelerazione 4 di arrivo
   word_148 : WORD ;
   C2_Posizione_1 : DINT  := L#500000;	//Centratore 2: Posizione 1 di avicinamento
   C2_Posizione_2 : DINT  := L#520000;	//Centratore 2: Posizione 2 di cambio velocita'
   C2_Posizione_3 : DINT  := L#530000;	//Centratore 2: Posizione 3 di cambio velocita'
   C2_Posizione_4 : DINT  := L#559000;	//Centratore 2: Posizione 4 di arrivo
   C2_Velocita_1 : DINT  := L#50;	//Centratore 2: Velocita' 1 di avvicinamento
   C2_Velocita_2 : DINT  := L#50;	//Centratore 2: Velocita' 2
   C2_Velocita_3 : DINT  := L#50;	//Centratore 2: Velocita' 3
   C2_Velocita_4 : DINT  := L#50;	//Centratore 2: Velocita' 4 di arrivo
   C2_Accell_1 : DINT  := L#500;	//Centratore 2: Accelerazione 1 di avvicinamento
   C2_Accell_2 : DINT  := L#500;	//Centratore 2: Accelerazione 2
   C2_Accell_3 : DINT  := L#500;	//Centratore 2: Accelerazione 3
   C2_Accell_4 : DINT  := L#500;	//Centratore 2: Accelerazione 4 di arrivo
   word_198 : WORD ;
   C3_Posizione_1 : DINT  := L#630000;	//Centratore 3: Posizione 1 di avicinamento
   C3_Posizione_2 : DINT  := L#650000;	//Centratore 3: Posizione 2 di cambio velocita'
   C3_Posizione_3 : DINT  := L#660000;	//Centratore 3: Posizione 3 di cambio velocita'
   C3_Posizione_4 : DINT  := L#698600;	//Centratore 3: Posizione 4 di arrivo
   C3_Velocita_1 : DINT  := L#50;	//Centratore 3: Velocita' 1 di avvicinamento
   C3_Velocita_2 : DINT  := L#50;	//Centratore 3: Velocita' 2
   C3_Velocita_3 : DINT  := L#50;	//Centratore 3: Velocita' 3
   C3_Velocita_4 : DINT  := L#50;	//Centratore 3: Velocita' 4 di arrivo
   C3_Accell_1 : DINT  := L#500;	//Centratore 3: Accelerazione 1 di avvicinamento
   C3_Accell_2 : DINT  := L#500;	//Centratore 3: Accelerazione 2
   C3_Accell_3 : DINT  := L#500;	//Centratore 3: Accelerazione 3
   C3_Accell_4 : DINT  := L#500;	//Centratore 3: Accelerazione 4 di arrivo
   word_248 : WORD ;
   C4_Posizione_1 : DINT  := L#630000;	//Centratore 4: Posizione 1 di avicinamento
   C4_Posizione_2 : DINT  := L#650000;	//Centratore 4: Posizione 2 di cambio velocita'
   C4_Posizione_3 : DINT  := L#660000;	//Centratore 4: Posizione 3 di cambio velocita'
   C4_Posizione_4 : DINT  := L#706200;	//Centratore 4: Posizione 4 di arrivo
   C4_Velocita_1 : DINT  := L#50;	//Centratore 4: Velocita' 1 di avvicinamento
   C4_Velocita_2 : DINT  := L#50;	//Centratore 4: Velocita' 2
   C4_Velocita_3 : DINT  := L#50;	//Centratore 4: Velocita' 3
   C4_Velocita_4 : DINT  := L#50;	//Centratore 4: Velocita' 4 di arrivo
   C4_Accell_1 : DINT  := L#500;	//Centratore 4: Accelerazione 1 di avvicinamento
   C4_Accell_2 : DINT  := L#500;	//Centratore 4: Accelerazione 2
   C4_Accell_3 : DINT  := L#500;	//Centratore 4: Accelerazione 3
   C4_Accell_4 : DINT  := L#500;	//Centratore 4: Accelerazione 4 di arrivo
   word_298 : WORD ;
   C5_Posizione_1 : DINT  := L#1180000;	//Centratore 5: Posizione 1 di avicinamento
   C5_Posizione_2 : DINT  := L#1200000;	//Centratore 5: Posizione 2 di cambio velocita'
   C5_Posizione_3 : DINT  := L#1220000;	//Centratore 5: Posizione 3 di cambio velocita'
   C5_Posizione_4 : DINT  := L#1247000;	//Centratore 5: Posizione 4 di arrivo
   C5_Velocita_1 : DINT  := L#50;	//Centratore 5: Velocita' 1 di avvicinamento
   C5_Velocita_2 : DINT  := L#50;	//Centratore 5: Velocita' 2
   C5_Velocita_3 : DINT  := L#50;	//Centratore 5: Velocita' 3
   C5_Velocita_4 : DINT  := L#50;	//Centratore 5: Velocita' 4 di arrivo
   C5_Accell_1 : DINT  := L#500;	//Centratore 5: Accelerazione 1 di avvicinamento
   C5_Accell_2 : DINT  := L#500;	//Centratore 5: Accelerazione 2
   C5_Accell_3 : DINT  := L#500;	//Centratore 5: Accelerazione 3
   C5_Accell_4 : DINT  := L#500;	//Centratore 5: Accelerazione 4 di arrivo
   word_348 : WORD ;
   C6_Posizione_1 : DINT  := L#1180000;	//Centratore 6: Posizione 1 di avicinamento
   C6_Posizione_2 : DINT  := L#1200000;	//Centratore 6: Posizione 2 di cambio velocita'
   C6_Posizione_3 : DINT  := L#1220000;	//Centratore 6: Posizione 3 di cambio velocita'
   C6_Posizione_4 : DINT  := L#1237400;	//Centratore 6: Posizione 4 di arrivo
   C6_Velocita_1 : DINT  := L#50;	//Centratore 6: Velocita' 1 di avvicinamento
   C6_Velocita_2 : DINT  := L#50;	//Centratore 6: Velocita' 2
   C6_Velocita_3 : DINT  := L#50;	//Centratore 6: Velocita' 3
   C6_Velocita_4 : DINT  := L#50;	//Centratore 6: Velocita' 4 di arrivo
   C6_Accell_1 : DINT  := L#500;	//Centratore 6: Accelerazione 1 di avvicinamento
   C6_Accell_2 : DINT  := L#500;	//Centratore 6: Accelerazione 2
   C6_Accell_3 : DINT  := L#500;	//Centratore 6: Accelerazione 3
   C6_Accell_4 : DINT  := L#500;	//Centratore 6: Accelerazione 4 di arrivo
   word_398 : WORD ;
  END_STRUCT ;
BEGIN
   LARGHEZZA_LAMIERA := 3.060000e+003;
   COMPENSAZ_TAV_1 := -7.000000e+001;
   QUOTA_H_SFOGLIATORE := 2.000000e+003;
   QUOTA_H_CENTRATORE := 1.960000e+003;
   word16 := S5T#0MS;
   INCLINAZ_TAVOLA_ESCLUSA := FALSE;
   dword20 := 0.000000e+000;
   dword24 := 0.000000e+000;
   dword28 := 0.000000e+000;
   dword32 := 0.000000e+000;
   dword36 := 0.000000e+000;
   NR_MATRICOLA := 2;
   word42 := W#16#0;
   MAGNETE_1_ESCLUSO := FALSE;
   MAGNETE_2_ESCLUSO := FALSE;
   MAGNETE_3_ESCLUSO := FALSE;
   MAGNETE_4_ESCLUSO := FALSE;
   MAGNETE_5_ESCLUSO := FALSE;
   MAGNETE_6_ESCLUSO := FALSE;
   MAGNETE_LAT_SX_ESCLUSO := FALSE;
   MAGNETE_LAT_DX_ESCLUSO := FALSE;
   COMPENSAZ_TAV_2 := -3.000000e+001;
   STAT22 := W#16#0;
   STAT23 := W#16#0;
   STAT24 := W#16#0;
   STAT25 := W#16#0;
   STAT251 := W#16#0;
   STAT26 := T#0MS;
   STAT29 := T#0MS;
   STAT30 := T#0MS;
   STAT31 := T#0MS;
   C1_Timer := 0.000000e+000;
   C2_Timer := 0.000000e+000;
   C3_Timer := 0.000000e+000;
   C4_Timer := 0.000000e+000;
   C5_Timer := 0.000000e+000;
   C6_Timer := 0.000000e+000;
   C1_Posizione_1 := L#163000;
   C1_Posizione_2 := L#183000;
   C1_Posizione_3 := L#193000;
   C1_Posizione_4 := L#235000;
   C1_Velocita_1 := L#500;
   C1_Velocita_2 := L#200;
   C1_Velocita_3 := L#200;
   C1_Velocita_4 := L#50;
   C1_Accell_1 := L#500;
   C1_Accell_2 := L#500;
   C1_Accell_3 := L#500;
   C1_Accell_4 := L#500;
   word_148 := W#16#0;
   C2_Posizione_1 := L#326000;
   C2_Posizione_2 := L#346000;
   C2_Posizione_3 := L#356000;
   C2_Posizione_4 := L#401000;
   C2_Velocita_1 := L#500;
   C2_Velocita_2 := L#200;
   C2_Velocita_3 := L#200;
   C2_Velocita_4 := L#50;
   C2_Accell_1 := L#500;
   C2_Accell_2 := L#500;
   C2_Accell_3 := L#500;
   C2_Accell_4 := L#500;
   word_198 := W#16#0;
   C3_Posizione_1 := L#200000;
   C3_Posizione_2 := L#220000;
   C3_Posizione_3 := L#230000;
   C3_Posizione_4 := L#385000;
   C3_Velocita_1 := L#500;
   C3_Velocita_2 := L#200;
   C3_Velocita_3 := L#200;
   C3_Velocita_4 := L#50;
   C3_Accell_1 := L#500;
   C3_Accell_2 := L#500;
   C3_Accell_3 := L#500;
   C3_Accell_4 := L#500;
   word_248 := W#16#0;
   C4_Posizione_1 := L#100000;
   C4_Posizione_2 := L#120000;
   C4_Posizione_3 := L#130000;
   C4_Posizione_4 := L#283000;
   C4_Velocita_1 := L#500;
   C4_Velocita_2 := L#200;
   C4_Velocita_3 := L#200;
   C4_Velocita_4 := L#50;
   C4_Accell_1 := L#500;
   C4_Accell_2 := L#500;
   C4_Accell_3 := L#500;
   C4_Accell_4 := L#500;
   word_298 := W#16#0;
   C5_Posizione_1 := L#395000;
   C5_Posizione_2 := L#415000;
   C5_Posizione_3 := L#425000;
   C5_Posizione_4 := L#510000;
   C5_Velocita_1 := L#500;
   C5_Velocita_2 := L#200;
   C5_Velocita_3 := L#200;
   C5_Velocita_4 := L#50;
   C5_Accell_1 := L#500;
   C5_Accell_2 := L#500;
   C5_Accell_3 := L#500;
   C5_Accell_4 := L#500;
   word_348 := W#16#0;
   C6_Posizione_1 := L#430000;
   C6_Posizione_2 := L#450000;
   C6_Posizione_3 := L#460000;
   C6_Posizione_4 := L#525000;
   C6_Velocita_1 := L#500;
   C6_Velocita_2 := L#200;
   C6_Velocita_3 := L#200;
   C6_Velocita_4 := L#50;
   C6_Accell_1 := L#500;
   C6_Accell_2 := L#500;
   C6_Accell_3 := L#500;
   C6_Accell_4 := L#500;
   word_398 := W#16#0;
END_DATA_BLOCK

DATA_BLOCK "MATRICOLA 21"
AUTHOR : Lodato
FAMILY : DESTACK
NAME : DATI
VERSION : 0.1


  STRUCT
   LARGHEZZA_LAMIERA : REAL  := 1.500000e+003;	//LARGHEZZA LAMIERA ATTUALE
   COMPENSAZ_TAV_1 : REAL ;	//COMPENSAZIONE TAVOLA 1
   QUOTA_H_SFOGLIATORE : REAL ;	//Quota impostata altezza sfogliatore
   QUOTA_H_CENTRATORE : REAL ;	//Quota impostata altezza centratore
   word16 : S5TIME ;
   INCLINAZ_TAVOLA_ESCLUSA : BOOL ;	//INCLINAZIONE TAVOLA ESCLUSA
   dword20 : REAL ;
   dword24 : REAL ;
   dword28 : REAL ;
   dword32 : REAL ;
   dword36 : REAL ;
   NR_MATRICOLA : INT  := 1;	//Numero di matricola
   word42 : WORD ;
   MAGNETE_1_ESCLUSO : BOOL ;	//MAGNETE 1 ESCLUSO DA MP270
   MAGNETE_2_ESCLUSO : BOOL ;	//MAGNETE 2 ESCLUSO DA MP270
   MAGNETE_3_ESCLUSO : BOOL ;	//MAGNETE 3 ESCLUSO DA MP270
   MAGNETE_4_ESCLUSO : BOOL ;	//MAGNETE 4 ESCLUSO DA MP270
   MAGNETE_5_ESCLUSO : BOOL ;	//MAGNETE 5 ESCLUSO DA MP270
   MAGNETE_6_ESCLUSO : BOOL ;	//MAGNETE 6 ESCLUSO DA MP270
   MAGNETE_LAT_SX_ESCLUSO : BOOL ;	//MAGNETE LATERALE SX ESCLUSO DA MP270
   MAGNETE_LAT_DX_ESCLUSO : BOOL ;	//MAGNETE LATERALE DX ESCLUSO DA MP270
   COMPENSAZ_TAV_2 : REAL ;	//COMPENSAZIONE TAVOLA 2
   STAT22 : WORD ;
   STAT23 : WORD ;
   STAT24 : WORD ;
   STAT25 : WORD ;
   STAT251 : WORD ;
   STAT26 : TIME ;
   STAT29 : TIME ;
   STAT30 : TIME ;
   STAT31 : TIME ;
   C1_Timer : REAL ;	//Centratore 1: Timer ritardo partenza
   C2_Timer : REAL ;	//Centratore 2: Timer ritardo partenza
   C3_Timer : REAL ;	//Centratore 3: Timer ritardo partenza
   C4_Timer : REAL ;	//Centratore 4: Timer ritardo partenza
   C5_Timer : REAL ;	//Centratore 5: Timer ritardo partenza
   C6_Timer : REAL ;	//Centratore 6: Timer ritardo partenza
   C1_Posizione_1 : DINT  := L#500000;	//Centratore 1: Posizione 1 di avicinamento
   C1_Posizione_2 : DINT  := L#520000;	//Centratore 1: Posizione 2 di cambio velocita'
   C1_Posizione_3 : DINT  := L#530000;	//Centratore 1: Posizione 3 di cambio velocita'
   C1_Posizione_4 : DINT  := L#565400;	//Centratore 1: Posizione 4 di arrivo
   C1_Velocita_1 : DINT  := L#50;	//Centratore 1: Velocita' 1 di avvicinamento
   C1_Velocita_2 : DINT  := L#50;	//Centratore 1: Velocita' 2
   C1_Velocita_3 : DINT  := L#50;	//Centratore 1: Velocita' 3
   C1_Velocita_4 : DINT  := L#50;	//Centratore 1: Velocita' 4 di arrivo
   C1_Accell_1 : DINT  := L#500;	//Centratore 1: Accelerazione 1 di avvicinamento
   C1_Accell_2 : DINT  := L#500;	//Centratore 1: Accelerazione 2
   C1_Accell_3 : DINT  := L#500;	//Centratore 1: Accelerazione 3
   C1_Accell_4 : DINT  := L#500;	//Centratore 1: Accelerazione 4 di arrivo
   word_148 : WORD ;
   C2_Posizione_1 : DINT  := L#500000;	//Centratore 2: Posizione 1 di avicinamento
   C2_Posizione_2 : DINT  := L#520000;	//Centratore 2: Posizione 2 di cambio velocita'
   C2_Posizione_3 : DINT  := L#530000;	//Centratore 2: Posizione 3 di cambio velocita'
   C2_Posizione_4 : DINT  := L#559000;	//Centratore 2: Posizione 4 di arrivo
   C2_Velocita_1 : DINT  := L#50;	//Centratore 2: Velocita' 1 di avvicinamento
   C2_Velocita_2 : DINT  := L#50;	//Centratore 2: Velocita' 2
   C2_Velocita_3 : DINT  := L#50;	//Centratore 2: Velocita' 3
   C2_Velocita_4 : DINT  := L#50;	//Centratore 2: Velocita' 4 di arrivo
   C2_Accell_1 : DINT  := L#500;	//Centratore 2: Accelerazione 1 di avvicinamento
   C2_Accell_2 : DINT  := L#500;	//Centratore 2: Accelerazione 2
   C2_Accell_3 : DINT  := L#500;	//Centratore 2: Accelerazione 3
   C2_Accell_4 : DINT  := L#500;	//Centratore 2: Accelerazione 4 di arrivo
   word_198 : WORD ;
   C3_Posizione_1 : DINT  := L#630000;	//Centratore 3: Posizione 1 di avicinamento
   C3_Posizione_2 : DINT  := L#650000;	//Centratore 3: Posizione 2 di cambio velocita'
   C3_Posizione_3 : DINT  := L#660000;	//Centratore 3: Posizione 3 di cambio velocita'
   C3_Posizione_4 : DINT  := L#698600;	//Centratore 3: Posizione 4 di arrivo
   C3_Velocita_1 : DINT  := L#50;	//Centratore 3: Velocita' 1 di avvicinamento
   C3_Velocita_2 : DINT  := L#50;	//Centratore 3: Velocita' 2
   C3_Velocita_3 : DINT  := L#50;	//Centratore 3: Velocita' 3
   C3_Velocita_4 : DINT  := L#50;	//Centratore 3: Velocita' 4 di arrivo
   C3_Accell_1 : DINT  := L#500;	//Centratore 3: Accelerazione 1 di avvicinamento
   C3_Accell_2 : DINT  := L#500;	//Centratore 3: Accelerazione 2
   C3_Accell_3 : DINT  := L#500;	//Centratore 3: Accelerazione 3
   C3_Accell_4 : DINT  := L#500;	//Centratore 3: Accelerazione 4 di arrivo
   word_248 : WORD ;
   C4_Posizione_1 : DINT  := L#630000;	//Centratore 4: Posizione 1 di avicinamento
   C4_Posizione_2 : DINT  := L#650000;	//Centratore 4: Posizione 2 di cambio velocita'
   C4_Posizione_3 : DINT  := L#660000;	//Centratore 4: Posizione 3 di cambio velocita'
   C4_Posizione_4 : DINT  := L#706200;	//Centratore 4: Posizione 4 di arrivo
   C4_Velocita_1 : DINT  := L#50;	//Centratore 4: Velocita' 1 di avvicinamento
   C4_Velocita_2 : DINT  := L#50;	//Centratore 4: Velocita' 2
   C4_Velocita_3 : DINT  := L#50;	//Centratore 4: Velocita' 3
   C4_Velocita_4 : DINT  := L#50;	//Centratore 4: Velocita' 4 di arrivo
   C4_Accell_1 : DINT  := L#500;	//Centratore 4: Accelerazione 1 di avvicinamento
   C4_Accell_2 : DINT  := L#500;	//Centratore 4: Accelerazione 2
   C4_Accell_3 : DINT  := L#500;	//Centratore 4: Accelerazione 3
   C4_Accell_4 : DINT  := L#500;	//Centratore 4: Accelerazione 4 di arrivo
   word_298 : WORD ;
   C5_Posizione_1 : DINT  := L#1180000;	//Centratore 5: Posizione 1 di avicinamento
   C5_Posizione_2 : DINT  := L#1200000;	//Centratore 5: Posizione 2 di cambio velocita'
   C5_Posizione_3 : DINT  := L#1220000;	//Centratore 5: Posizione 3 di cambio velocita'
   C5_Posizione_4 : DINT  := L#1247000;	//Centratore 5: Posizione 4 di arrivo
   C5_Velocita_1 : DINT  := L#50;	//Centratore 5: Velocita' 1 di avvicinamento
   C5_Velocita_2 : DINT  := L#50;	//Centratore 5: Velocita' 2
   C5_Velocita_3 : DINT  := L#50;	//Centratore 5: Velocita' 3
   C5_Velocita_4 : DINT  := L#50;	//Centratore 5: Velocita' 4 di arrivo
   C5_Accell_1 : DINT  := L#500;	//Centratore 5: Accelerazione 1 di avvicinamento
   C5_Accell_2 : DINT  := L#500;	//Centratore 5: Accelerazione 2
   C5_Accell_3 : DINT  := L#500;	//Centratore 5: Accelerazione 3
   C5_Accell_4 : DINT  := L#500;	//Centratore 5: Accelerazione 4 di arrivo
   word_348 : WORD ;
   C6_Posizione_1 : DINT  := L#1180000;	//Centratore 6: Posizione 1 di avicinamento
   C6_Posizione_2 : DINT  := L#1200000;	//Centratore 6: Posizione 2 di cambio velocita'
   C6_Posizione_3 : DINT  := L#1220000;	//Centratore 6: Posizione 3 di cambio velocita'
   C6_Posizione_4 : DINT  := L#1237400;	//Centratore 6: Posizione 4 di arrivo
   C6_Velocita_1 : DINT  := L#50;	//Centratore 6: Velocita' 1 di avvicinamento
   C6_Velocita_2 : DINT  := L#50;	//Centratore 6: Velocita' 2
   C6_Velocita_3 : DINT  := L#50;	//Centratore 6: Velocita' 3
   C6_Velocita_4 : DINT  := L#50;	//Centratore 6: Velocita' 4 di arrivo
   C6_Accell_1 : DINT  := L#500;	//Centratore 6: Accelerazione 1 di avvicinamento
   C6_Accell_2 : DINT  := L#500;	//Centratore 6: Accelerazione 2
   C6_Accell_3 : DINT  := L#500;	//Centratore 6: Accelerazione 3
   C6_Accell_4 : DINT  := L#500;	//Centratore 6: Accelerazione 4 di arrivo
   word_398 : WORD ;
  END_STRUCT ;
BEGIN
   LARGHEZZA_LAMIERA := 3.060000e+003;
   COMPENSAZ_TAV_1 := -7.000000e+001;
   QUOTA_H_SFOGLIATORE := 2.000000e+003;
   QUOTA_H_CENTRATORE := 1.960000e+003;
   word16 := S5T#0MS;
   INCLINAZ_TAVOLA_ESCLUSA := FALSE;
   dword20 := 0.000000e+000;
   dword24 := 0.000000e+000;
   dword28 := 0.000000e+000;
   dword32 := 0.000000e+000;
   dword36 := 0.000000e+000;
   NR_MATRICOLA := 2;
   word42 := W#16#0;
   MAGNETE_1_ESCLUSO := FALSE;
   MAGNETE_2_ESCLUSO := FALSE;
   MAGNETE_3_ESCLUSO := FALSE;
   MAGNETE_4_ESCLUSO := FALSE;
   MAGNETE_5_ESCLUSO := FALSE;
   MAGNETE_6_ESCLUSO := FALSE;
   MAGNETE_LAT_SX_ESCLUSO := FALSE;
   MAGNETE_LAT_DX_ESCLUSO := FALSE;
   COMPENSAZ_TAV_2 := -3.000000e+001;
   STAT22 := W#16#0;
   STAT23 := W#16#0;
   STAT24 := W#16#0;
   STAT25 := W#16#0;
   STAT251 := W#16#0;
   STAT26 := T#0MS;
   STAT29 := T#0MS;
   STAT30 := T#0MS;
   STAT31 := T#0MS;
   C1_Timer := 0.000000e+000;
   C2_Timer := 0.000000e+000;
   C3_Timer := 0.000000e+000;
   C4_Timer := 0.000000e+000;
   C5_Timer := 0.000000e+000;
   C6_Timer := 0.000000e+000;
   C1_Posizione_1 := L#163000;
   C1_Posizione_2 := L#183000;
   C1_Posizione_3 := L#193000;
   C1_Posizione_4 := L#235000;
   C1_Velocita_1 := L#500;
   C1_Velocita_2 := L#200;
   C1_Velocita_3 := L#200;
   C1_Velocita_4 := L#50;
   C1_Accell_1 := L#500;
   C1_Accell_2 := L#500;
   C1_Accell_3 := L#500;
   C1_Accell_4 := L#500;
   word_148 := W#16#0;
   C2_Posizione_1 := L#326000;
   C2_Posizione_2 := L#346000;
   C2_Posizione_3 := L#356000;
   C2_Posizione_4 := L#401000;
   C2_Velocita_1 := L#500;
   C2_Velocita_2 := L#200;
   C2_Velocita_3 := L#200;
   C2_Velocita_4 := L#50;
   C2_Accell_1 := L#500;
   C2_Accell_2 := L#500;
   C2_Accell_3 := L#500;
   C2_Accell_4 := L#500;
   word_198 := W#16#0;
   C3_Posizione_1 := L#200000;
   C3_Posizione_2 := L#220000;
   C3_Posizione_3 := L#230000;
   C3_Posizione_4 := L#385000;
   C3_Velocita_1 := L#500;
   C3_Velocita_2 := L#200;
   C3_Velocita_3 := L#200;
   C3_Velocita_4 := L#50;
   C3_Accell_1 := L#500;
   C3_Accell_2 := L#500;
   C3_Accell_3 := L#500;
   C3_Accell_4 := L#500;
   word_248 := W#16#0;
   C4_Posizione_1 := L#100000;
   C4_Posizione_2 := L#120000;
   C4_Posizione_3 := L#130000;
   C4_Posizione_4 := L#283000;
   C4_Velocita_1 := L#500;
   C4_Velocita_2 := L#200;
   C4_Velocita_3 := L#200;
   C4_Velocita_4 := L#50;
   C4_Accell_1 := L#500;
   C4_Accell_2 := L#500;
   C4_Accell_3 := L#500;
   C4_Accell_4 := L#500;
   word_298 := W#16#0;
   C5_Posizione_1 := L#395000;
   C5_Posizione_2 := L#415000;
   C5_Posizione_3 := L#425000;
   C5_Posizione_4 := L#510000;
   C5_Velocita_1 := L#500;
   C5_Velocita_2 := L#200;
   C5_Velocita_3 := L#200;
   C5_Velocita_4 := L#50;
   C5_Accell_1 := L#500;
   C5_Accell_2 := L#500;
   C5_Accell_3 := L#500;
   C5_Accell_4 := L#500;
   word_348 := W#16#0;
   C6_Posizione_1 := L#430000;
   C6_Posizione_2 := L#450000;
   C6_Posizione_3 := L#460000;
   C6_Posizione_4 := L#525000;
   C6_Velocita_1 := L#500;
   C6_Velocita_2 := L#200;
   C6_Velocita_3 := L#200;
   C6_Velocita_4 := L#50;
   C6_Accell_1 := L#500;
   C6_Accell_2 := L#500;
   C6_Accell_3 := L#500;
   C6_Accell_4 := L#500;
   word_398 := W#16#0;
END_DATA_BLOCK

DATA_BLOCK "MATRICOLA 22"
AUTHOR : Lodato
FAMILY : DESTACK
NAME : DATI
VERSION : 0.1


  STRUCT
   LARGHEZZA_LAMIERA : REAL  := 1.500000e+003;	//LARGHEZZA LAMIERA ATTUALE
   COMPENSAZ_TAV_1 : REAL ;	//COMPENSAZIONE TAVOLA 1
   QUOTA_H_SFOGLIATORE : REAL ;	//Quota impostata altezza sfogliatore
   QUOTA_H_CENTRATORE : REAL ;	//Quota impostata altezza centratore
   word16 : S5TIME ;
   INCLINAZ_TAVOLA_ESCLUSA : BOOL ;	//INCLINAZIONE TAVOLA ESCLUSA
   dword20 : REAL ;
   dword24 : REAL ;
   dword28 : REAL ;
   dword32 : REAL ;
   dword36 : REAL ;
   NR_MATRICOLA : INT  := 1;	//Numero di matricola
   word42 : WORD ;
   MAGNETE_1_ESCLUSO : BOOL ;	//MAGNETE 1 ESCLUSO DA MP270
   MAGNETE_2_ESCLUSO : BOOL ;	//MAGNETE 2 ESCLUSO DA MP270
   MAGNETE_3_ESCLUSO : BOOL ;	//MAGNETE 3 ESCLUSO DA MP270
   MAGNETE_4_ESCLUSO : BOOL ;	//MAGNETE 4 ESCLUSO DA MP270
   MAGNETE_5_ESCLUSO : BOOL ;	//MAGNETE 5 ESCLUSO DA MP270
   MAGNETE_6_ESCLUSO : BOOL ;	//MAGNETE 6 ESCLUSO DA MP270
   MAGNETE_LAT_SX_ESCLUSO : BOOL ;	//MAGNETE LATERALE SX ESCLUSO DA MP270
   MAGNETE_LAT_DX_ESCLUSO : BOOL ;	//MAGNETE LATERALE DX ESCLUSO DA MP270
   COMPENSAZ_TAV_2 : REAL ;	//COMPENSAZIONE TAVOLA 2
   STAT22 : WORD ;
   STAT23 : WORD ;
   STAT24 : WORD ;
   STAT25 : WORD ;
   STAT251 : WORD ;
   STAT26 : TIME ;
   STAT29 : TIME ;
   STAT30 : TIME ;
   STAT31 : TIME ;
   C1_Timer : REAL ;	//Centratore 1: Timer ritardo partenza
   C2_Timer : REAL ;	//Centratore 2: Timer ritardo partenza
   C3_Timer : REAL ;	//Centratore 3: Timer ritardo partenza
   C4_Timer : REAL ;	//Centratore 4: Timer ritardo partenza
   C5_Timer : REAL ;	//Centratore 5: Timer ritardo partenza
   C6_Timer : REAL ;	//Centratore 6: Timer ritardo partenza
   C1_Posizione_1 : DINT  := L#500000;	//Centratore 1: Posizione 1 di avicinamento
   C1_Posizione_2 : DINT  := L#520000;	//Centratore 1: Posizione 2 di cambio velocita'
   C1_Posizione_3 : DINT  := L#530000;	//Centratore 1: Posizione 3 di cambio velocita'
   C1_Posizione_4 : DINT  := L#565400;	//Centratore 1: Posizione 4 di arrivo
   C1_Velocita_1 : DINT  := L#50;	//Centratore 1: Velocita' 1 di avvicinamento
   C1_Velocita_2 : DINT  := L#50;	//Centratore 1: Velocita' 2
   C1_Velocita_3 : DINT  := L#50;	//Centratore 1: Velocita' 3
   C1_Velocita_4 : DINT  := L#50;	//Centratore 1: Velocita' 4 di arrivo
   C1_Accell_1 : DINT  := L#500;	//Centratore 1: Accelerazione 1 di avvicinamento
   C1_Accell_2 : DINT  := L#500;	//Centratore 1: Accelerazione 2
   C1_Accell_3 : DINT  := L#500;	//Centratore 1: Accelerazione 3
   C1_Accell_4 : DINT  := L#500;	//Centratore 1: Accelerazione 4 di arrivo
   word_148 : WORD ;
   C2_Posizione_1 : DINT  := L#500000;	//Centratore 2: Posizione 1 di avicinamento
   C2_Posizione_2 : DINT  := L#520000;	//Centratore 2: Posizione 2 di cambio velocita'
   C2_Posizione_3 : DINT  := L#530000;	//Centratore 2: Posizione 3 di cambio velocita'
   C2_Posizione_4 : DINT  := L#559000;	//Centratore 2: Posizione 4 di arrivo
   C2_Velocita_1 : DINT  := L#50;	//Centratore 2: Velocita' 1 di avvicinamento
   C2_Velocita_2 : DINT  := L#50;	//Centratore 2: Velocita' 2
   C2_Velocita_3 : DINT  := L#50;	//Centratore 2: Velocita' 3
   C2_Velocita_4 : DINT  := L#50;	//Centratore 2: Velocita' 4 di arrivo
   C2_Accell_1 : DINT  := L#500;	//Centratore 2: Accelerazione 1 di avvicinamento
   C2_Accell_2 : DINT  := L#500;	//Centratore 2: Accelerazione 2
   C2_Accell_3 : DINT  := L#500;	//Centratore 2: Accelerazione 3
   C2_Accell_4 : DINT  := L#500;	//Centratore 2: Accelerazione 4 di arrivo
   word_198 : WORD ;
   C3_Posizione_1 : DINT  := L#630000;	//Centratore 3: Posizione 1 di avicinamento
   C3_Posizione_2 : DINT  := L#650000;	//Centratore 3: Posizione 2 di cambio velocita'
   C3_Posizione_3 : DINT  := L#660000;	//Centratore 3: Posizione 3 di cambio velocita'
   C3_Posizione_4 : DINT  := L#698600;	//Centratore 3: Posizione 4 di arrivo
   C3_Velocita_1 : DINT  := L#50;	//Centratore 3: Velocita' 1 di avvicinamento
   C3_Velocita_2 : DINT  := L#50;	//Centratore 3: Velocita' 2
   C3_Velocita_3 : DINT  := L#50;	//Centratore 3: Velocita' 3
   C3_Velocita_4 : DINT  := L#50;	//Centratore 3: Velocita' 4 di arrivo
   C3_Accell_1 : DINT  := L#500;	//Centratore 3: Accelerazione 1 di avvicinamento
   C3_Accell_2 : DINT  := L#500;	//Centratore 3: Accelerazione 2
   C3_Accell_3 : DINT  := L#500;	//Centratore 3: Accelerazione 3
   C3_Accell_4 : DINT  := L#500;	//Centratore 3: Accelerazione 4 di arrivo
   word_248 : WORD ;
   C4_Posizione_1 : DINT  := L#630000;	//Centratore 4: Posizione 1 di avicinamento
   C4_Posizione_2 : DINT  := L#650000;	//Centratore 4: Posizione 2 di cambio velocita'
   C4_Posizione_3 : DINT  := L#660000;	//Centratore 4: Posizione 3 di cambio velocita'
   C4_Posizione_4 : DINT  := L#706200;	//Centratore 4: Posizione 4 di arrivo
   C4_Velocita_1 : DINT  := L#50;	//Centratore 4: Velocita' 1 di avvicinamento
   C4_Velocita_2 : DINT  := L#50;	//Centratore 4: Velocita' 2
   C4_Velocita_3 : DINT  := L#50;	//Centratore 4: Velocita' 3
   C4_Velocita_4 : DINT  := L#50;	//Centratore 4: Velocita' 4 di arrivo
   C4_Accell_1 : DINT  := L#500;	//Centratore 4: Accelerazione 1 di avvicinamento
   C4_Accell_2 : DINT  := L#500;	//Centratore 4: Accelerazione 2
   C4_Accell_3 : DINT  := L#500;	//Centratore 4: Accelerazione 3
   C4_Accell_4 : DINT  := L#500;	//Centratore 4: Accelerazione 4 di arrivo
   word_298 : WORD ;
   C5_Posizione_1 : DINT  := L#1180000;	//Centratore 5: Posizione 1 di avicinamento
   C5_Posizione_2 : DINT  := L#1200000;	//Centratore 5: Posizione 2 di cambio velocita'
   C5_Posizione_3 : DINT  := L#1220000;	//Centratore 5: Posizione 3 di cambio velocita'
   C5_Posizione_4 : DINT  := L#1247000;	//Centratore 5: Posizione 4 di arrivo
   C5_Velocita_1 : DINT  := L#50;	//Centratore 5: Velocita' 1 di avvicinamento
   C5_Velocita_2 : DINT  := L#50;	//Centratore 5: Velocita' 2
   C5_Velocita_3 : DINT  := L#50;	//Centratore 5: Velocita' 3
   C5_Velocita_4 : DINT  := L#50;	//Centratore 5: Velocita' 4 di arrivo
   C5_Accell_1 : DINT  := L#500;	//Centratore 5: Accelerazione 1 di avvicinamento
   C5_Accell_2 : DINT  := L#500;	//Centratore 5: Accelerazione 2
   C5_Accell_3 : DINT  := L#500;	//Centratore 5: Accelerazione 3
   C5_Accell_4 : DINT  := L#500;	//Centratore 5: Accelerazione 4 di arrivo
   word_348 : WORD ;
   C6_Posizione_1 : DINT  := L#1180000;	//Centratore 6: Posizione 1 di avicinamento
   C6_Posizione_2 : DINT  := L#1200000;	//Centratore 6: Posizione 2 di cambio velocita'
   C6_Posizione_3 : DINT  := L#1220000;	//Centratore 6: Posizione 3 di cambio velocita'
   C6_Posizione_4 : DINT  := L#1237400;	//Centratore 6: Posizione 4 di arrivo
   C6_Velocita_1 : DINT  := L#50;	//Centratore 6: Velocita' 1 di avvicinamento
   C6_Velocita_2 : DINT  := L#50;	//Centratore 6: Velocita' 2
   C6_Velocita_3 : DINT  := L#50;	//Centratore 6: Velocita' 3
   C6_Velocita_4 : DINT  := L#50;	//Centratore 6: Velocita' 4 di arrivo
   C6_Accell_1 : DINT  := L#500;	//Centratore 6: Accelerazione 1 di avvicinamento
   C6_Accell_2 : DINT  := L#500;	//Centratore 6: Accelerazione 2
   C6_Accell_3 : DINT  := L#500;	//Centratore 6: Accelerazione 3
   C6_Accell_4 : DINT  := L#500;	//Centratore 6: Accelerazione 4 di arrivo
   word_398 : WORD ;
  END_STRUCT ;
BEGIN
   LARGHEZZA_LAMIERA := 3.060000e+003;
   COMPENSAZ_TAV_1 := -7.000000e+001;
   QUOTA_H_SFOGLIATORE := 2.000000e+003;
   QUOTA_H_CENTRATORE := 1.960000e+003;
   word16 := S5T#0MS;
   INCLINAZ_TAVOLA_ESCLUSA := FALSE;
   dword20 := 0.000000e+000;
   dword24 := 0.000000e+000;
   dword28 := 0.000000e+000;
   dword32 := 0.000000e+000;
   dword36 := 0.000000e+000;
   NR_MATRICOLA := 2;
   word42 := W#16#0;
   MAGNETE_1_ESCLUSO := FALSE;
   MAGNETE_2_ESCLUSO := FALSE;
   MAGNETE_3_ESCLUSO := FALSE;
   MAGNETE_4_ESCLUSO := FALSE;
   MAGNETE_5_ESCLUSO := FALSE;
   MAGNETE_6_ESCLUSO := FALSE;
   MAGNETE_LAT_SX_ESCLUSO := FALSE;
   MAGNETE_LAT_DX_ESCLUSO := FALSE;
   COMPENSAZ_TAV_2 := -3.000000e+001;
   STAT22 := W#16#0;
   STAT23 := W#16#0;
   STAT24 := W#16#0;
   STAT25 := W#16#0;
   STAT251 := W#16#0;
   STAT26 := T#0MS;
   STAT29 := T#0MS;
   STAT30 := T#0MS;
   STAT31 := T#0MS;
   C1_Timer := 0.000000e+000;
   C2_Timer := 0.000000e+000;
   C3_Timer := 0.000000e+000;
   C4_Timer := 0.000000e+000;
   C5_Timer := 0.000000e+000;
   C6_Timer := 0.000000e+000;
   C1_Posizione_1 := L#163000;
   C1_Posizione_2 := L#183000;
   C1_Posizione_3 := L#193000;
   C1_Posizione_4 := L#235000;
   C1_Velocita_1 := L#500;
   C1_Velocita_2 := L#200;
   C1_Velocita_3 := L#200;
   C1_Velocita_4 := L#50;
   C1_Accell_1 := L#500;
   C1_Accell_2 := L#500;
   C1_Accell_3 := L#500;
   C1_Accell_4 := L#500;
   word_148 := W#16#0;
   C2_Posizione_1 := L#326000;
   C2_Posizione_2 := L#346000;
   C2_Posizione_3 := L#356000;
   C2_Posizione_4 := L#401000;
   C2_Velocita_1 := L#500;
   C2_Velocita_2 := L#200;
   C2_Velocita_3 := L#200;
   C2_Velocita_4 := L#50;
   C2_Accell_1 := L#500;
   C2_Accell_2 := L#500;
   C2_Accell_3 := L#500;
   C2_Accell_4 := L#500;
   word_198 := W#16#0;
   C3_Posizione_1 := L#200000;
   C3_Posizione_2 := L#220000;
   C3_Posizione_3 := L#230000;
   C3_Posizione_4 := L#385000;
   C3_Velocita_1 := L#500;
   C3_Velocita_2 := L#200;
   C3_Velocita_3 := L#200;
   C3_Velocita_4 := L#50;
   C3_Accell_1 := L#500;
   C3_Accell_2 := L#500;
   C3_Accell_3 := L#500;
   C3_Accell_4 := L#500;
   word_248 := W#16#0;
   C4_Posizione_1 := L#100000;
   C4_Posizione_2 := L#120000;
   C4_Posizione_3 := L#130000;
   C4_Posizione_4 := L#283000;
   C4_Velocita_1 := L#500;
   C4_Velocita_2 := L#200;
   C4_Velocita_3 := L#200;
   C4_Velocita_4 := L#50;
   C4_Accell_1 := L#500;
   C4_Accell_2 := L#500;
   C4_Accell_3 := L#500;
   C4_Accell_4 := L#500;
   word_298 := W#16#0;
   C5_Posizione_1 := L#395000;
   C5_Posizione_2 := L#415000;
   C5_Posizione_3 := L#425000;
   C5_Posizione_4 := L#510000;
   C5_Velocita_1 := L#500;
   C5_Velocita_2 := L#200;
   C5_Velocita_3 := L#200;
   C5_Velocita_4 := L#50;
   C5_Accell_1 := L#500;
   C5_Accell_2 := L#500;
   C5_Accell_3 := L#500;
   C5_Accell_4 := L#500;
   word_348 := W#16#0;
   C6_Posizione_1 := L#430000;
   C6_Posizione_2 := L#450000;
   C6_Posizione_3 := L#460000;
   C6_Posizione_4 := L#525000;
   C6_Velocita_1 := L#500;
   C6_Velocita_2 := L#200;
   C6_Velocita_3 := L#200;
   C6_Velocita_4 := L#50;
   C6_Accell_1 := L#500;
   C6_Accell_2 := L#500;
   C6_Accell_3 := L#500;
   C6_Accell_4 := L#500;
   word_398 := W#16#0;
END_DATA_BLOCK

DATA_BLOCK "MATRICOLA 23"
AUTHOR : Lodato
FAMILY : DESTACK
NAME : DATI
VERSION : 0.1


  STRUCT
   LARGHEZZA_LAMIERA : REAL  := 1.500000e+003;	//LARGHEZZA LAMIERA ATTUALE
   COMPENSAZ_TAV_1 : REAL ;	//COMPENSAZIONE TAVOLA 1
   QUOTA_H_SFOGLIATORE : REAL ;	//Quota impostata altezza sfogliatore
   QUOTA_H_CENTRATORE : REAL ;	//Quota impostata altezza centratore
   word16 : S5TIME ;
   INCLINAZ_TAVOLA_ESCLUSA : BOOL ;	//INCLINAZIONE TAVOLA ESCLUSA
   dword20 : REAL ;
   dword24 : REAL ;
   dword28 : REAL ;
   dword32 : REAL ;
   dword36 : REAL ;
   NR_MATRICOLA : INT  := 1;	//Numero di matricola
   word42 : WORD ;
   MAGNETE_1_ESCLUSO : BOOL ;	//MAGNETE 1 ESCLUSO DA MP270
   MAGNETE_2_ESCLUSO : BOOL ;	//MAGNETE 2 ESCLUSO DA MP270
   MAGNETE_3_ESCLUSO : BOOL ;	//MAGNETE 3 ESCLUSO DA MP270
   MAGNETE_4_ESCLUSO : BOOL ;	//MAGNETE 4 ESCLUSO DA MP270
   MAGNETE_5_ESCLUSO : BOOL ;	//MAGNETE 5 ESCLUSO DA MP270
   MAGNETE_6_ESCLUSO : BOOL ;	//MAGNETE 6 ESCLUSO DA MP270
   MAGNETE_LAT_SX_ESCLUSO : BOOL ;	//MAGNETE LATERALE SX ESCLUSO DA MP270
   MAGNETE_LAT_DX_ESCLUSO : BOOL ;	//MAGNETE LATERALE DX ESCLUSO DA MP270
   COMPENSAZ_TAV_2 : REAL ;	//COMPENSAZIONE TAVOLA 2
   STAT22 : WORD ;
   STAT23 : WORD ;
   STAT24 : WORD ;
   STAT25 : WORD ;
   STAT251 : WORD ;
   STAT26 : TIME ;
   STAT29 : TIME ;
   STAT30 : TIME ;
   STAT31 : TIME ;
   C1_Timer : REAL ;	//Centratore 1: Timer ritardo partenza
   C2_Timer : REAL ;	//Centratore 2: Timer ritardo partenza
   C3_Timer : REAL ;	//Centratore 3: Timer ritardo partenza
   C4_Timer : REAL ;	//Centratore 4: Timer ritardo partenza
   C5_Timer : REAL ;	//Centratore 5: Timer ritardo partenza
   C6_Timer : REAL ;	//Centratore 6: Timer ritardo partenza
   C1_Posizione_1 : DINT  := L#500000;	//Centratore 1: Posizione 1 di avicinamento
   C1_Posizione_2 : DINT  := L#520000;	//Centratore 1: Posizione 2 di cambio velocita'
   C1_Posizione_3 : DINT  := L#530000;	//Centratore 1: Posizione 3 di cambio velocita'
   C1_Posizione_4 : DINT  := L#565400;	//Centratore 1: Posizione 4 di arrivo
   C1_Velocita_1 : DINT  := L#50;	//Centratore 1: Velocita' 1 di avvicinamento
   C1_Velocita_2 : DINT  := L#50;	//Centratore 1: Velocita' 2
   C1_Velocita_3 : DINT  := L#50;	//Centratore 1: Velocita' 3
   C1_Velocita_4 : DINT  := L#50;	//Centratore 1: Velocita' 4 di arrivo
   C1_Accell_1 : DINT  := L#500;	//Centratore 1: Accelerazione 1 di avvicinamento
   C1_Accell_2 : DINT  := L#500;	//Centratore 1: Accelerazione 2
   C1_Accell_3 : DINT  := L#500;	//Centratore 1: Accelerazione 3
   C1_Accell_4 : DINT  := L#500;	//Centratore 1: Accelerazione 4 di arrivo
   word_148 : WORD ;
   C2_Posizione_1 : DINT  := L#500000;	//Centratore 2: Posizione 1 di avicinamento
   C2_Posizione_2 : DINT  := L#520000;	//Centratore 2: Posizione 2 di cambio velocita'
   C2_Posizione_3 : DINT  := L#530000;	//Centratore 2: Posizione 3 di cambio velocita'
   C2_Posizione_4 : DINT  := L#559000;	//Centratore 2: Posizione 4 di arrivo
   C2_Velocita_1 : DINT  := L#50;	//Centratore 2: Velocita' 1 di avvicinamento
   C2_Velocita_2 : DINT  := L#50;	//Centratore 2: Velocita' 2
   C2_Velocita_3 : DINT  := L#50;	//Centratore 2: Velocita' 3
   C2_Velocita_4 : DINT  := L#50;	//Centratore 2: Velocita' 4 di arrivo
   C2_Accell_1 : DINT  := L#500;	//Centratore 2: Accelerazione 1 di avvicinamento
   C2_Accell_2 : DINT  := L#500;	//Centratore 2: Accelerazione 2
   C2_Accell_3 : DINT  := L#500;	//Centratore 2: Accelerazione 3
   C2_Accell_4 : DINT  := L#500;	//Centratore 2: Accelerazione 4 di arrivo
   word_198 : WORD ;
   C3_Posizione_1 : DINT  := L#630000;	//Centratore 3: Posizione 1 di avicinamento
   C3_Posizione_2 : DINT  := L#650000;	//Centratore 3: Posizione 2 di cambio velocita'
   C3_Posizione_3 : DINT  := L#660000;	//Centratore 3: Posizione 3 di cambio velocita'
   C3_Posizione_4 : DINT  := L#698600;	//Centratore 3: Posizione 4 di arrivo
   C3_Velocita_1 : DINT  := L#50;	//Centratore 3: Velocita' 1 di avvicinamento
   C3_Velocita_2 : DINT  := L#50;	//Centratore 3: Velocita' 2
   C3_Velocita_3 : DINT  := L#50;	//Centratore 3: Velocita' 3
   C3_Velocita_4 : DINT  := L#50;	//Centratore 3: Velocita' 4 di arrivo
   C3_Accell_1 : DINT  := L#500;	//Centratore 3: Accelerazione 1 di avvicinamento
   C3_Accell_2 : DINT  := L#500;	//Centratore 3: Accelerazione 2
   C3_Accell_3 : DINT  := L#500;	//Centratore 3: Accelerazione 3
   C3_Accell_4 : DINT  := L#500;	//Centratore 3: Accelerazione 4 di arrivo
   word_248 : WORD ;
   C4_Posizione_1 : DINT  := L#630000;	//Centratore 4: Posizione 1 di avicinamento
   C4_Posizione_2 : DINT  := L#650000;	//Centratore 4: Posizione 2 di cambio velocita'
   C4_Posizione_3 : DINT  := L#660000;	//Centratore 4: Posizione 3 di cambio velocita'
   C4_Posizione_4 : DINT  := L#706200;	//Centratore 4: Posizione 4 di arrivo
   C4_Velocita_1 : DINT  := L#50;	//Centratore 4: Velocita' 1 di avvicinamento
   C4_Velocita_2 : DINT  := L#50;	//Centratore 4: Velocita' 2
   C4_Velocita_3 : DINT  := L#50;	//Centratore 4: Velocita' 3
   C4_Velocita_4 : DINT  := L#50;	//Centratore 4: Velocita' 4 di arrivo
   C4_Accell_1 : DINT  := L#500;	//Centratore 4: Accelerazione 1 di avvicinamento
   C4_Accell_2 : DINT  := L#500;	//Centratore 4: Accelerazione 2
   C4_Accell_3 : DINT  := L#500;	//Centratore 4: Accelerazione 3
   C4_Accell_4 : DINT  := L#500;	//Centratore 4: Accelerazione 4 di arrivo
   word_298 : WORD ;
   C5_Posizione_1 : DINT  := L#1180000;	//Centratore 5: Posizione 1 di avicinamento
   C5_Posizione_2 : DINT  := L#1200000;	//Centratore 5: Posizione 2 di cambio velocita'
   C5_Posizione_3 : DINT  := L#1220000;	//Centratore 5: Posizione 3 di cambio velocita'
   C5_Posizione_4 : DINT  := L#1247000;	//Centratore 5: Posizione 4 di arrivo
   C5_Velocita_1 : DINT  := L#50;	//Centratore 5: Velocita' 1 di avvicinamento
   C5_Velocita_2 : DINT  := L#50;	//Centratore 5: Velocita' 2
   C5_Velocita_3 : DINT  := L#50;	//Centratore 5: Velocita' 3
   C5_Velocita_4 : DINT  := L#50;	//Centratore 5: Velocita' 4 di arrivo
   C5_Accell_1 : DINT  := L#500;	//Centratore 5: Accelerazione 1 di avvicinamento
   C5_Accell_2 : DINT  := L#500;	//Centratore 5: Accelerazione 2
   C5_Accell_3 : DINT  := L#500;	//Centratore 5: Accelerazione 3
   C5_Accell_4 : DINT  := L#500;	//Centratore 5: Accelerazione 4 di arrivo
   word_348 : WORD ;
   C6_Posizione_1 : DINT  := L#1180000;	//Centratore 6: Posizione 1 di avicinamento
   C6_Posizione_2 : DINT  := L#1200000;	//Centratore 6: Posizione 2 di cambio velocita'
   C6_Posizione_3 : DINT  := L#1220000;	//Centratore 6: Posizione 3 di cambio velocita'
   C6_Posizione_4 : DINT  := L#1237400;	//Centratore 6: Posizione 4 di arrivo
   C6_Velocita_1 : DINT  := L#50;	//Centratore 6: Velocita' 1 di avvicinamento
   C6_Velocita_2 : DINT  := L#50;	//Centratore 6: Velocita' 2
   C6_Velocita_3 : DINT  := L#50;	//Centratore 6: Velocita' 3
   C6_Velocita_4 : DINT  := L#50;	//Centratore 6: Velocita' 4 di arrivo
   C6_Accell_1 : DINT  := L#500;	//Centratore 6: Accelerazione 1 di avvicinamento
   C6_Accell_2 : DINT  := L#500;	//Centratore 6: Accelerazione 2
   C6_Accell_3 : DINT  := L#500;	//Centratore 6: Accelerazione 3
   C6_Accell_4 : DINT  := L#500;	//Centratore 6: Accelerazione 4 di arrivo
   word_398 : WORD ;
  END_STRUCT ;
BEGIN
   LARGHEZZA_LAMIERA := 3.060000e+003;
   COMPENSAZ_TAV_1 := -7.000000e+001;
   QUOTA_H_SFOGLIATORE := 2.000000e+003;
   QUOTA_H_CENTRATORE := 1.960000e+003;
   word16 := S5T#0MS;
   INCLINAZ_TAVOLA_ESCLUSA := FALSE;
   dword20 := 0.000000e+000;
   dword24 := 0.000000e+000;
   dword28 := 0.000000e+000;
   dword32 := 0.000000e+000;
   dword36 := 0.000000e+000;
   NR_MATRICOLA := 2;
   word42 := W#16#0;
   MAGNETE_1_ESCLUSO := FALSE;
   MAGNETE_2_ESCLUSO := FALSE;
   MAGNETE_3_ESCLUSO := FALSE;
   MAGNETE_4_ESCLUSO := FALSE;
   MAGNETE_5_ESCLUSO := FALSE;
   MAGNETE_6_ESCLUSO := FALSE;
   MAGNETE_LAT_SX_ESCLUSO := FALSE;
   MAGNETE_LAT_DX_ESCLUSO := FALSE;
   COMPENSAZ_TAV_2 := -3.000000e+001;
   STAT22 := W#16#0;
   STAT23 := W#16#0;
   STAT24 := W#16#0;
   STAT25 := W#16#0;
   STAT251 := W#16#0;
   STAT26 := T#0MS;
   STAT29 := T#0MS;
   STAT30 := T#0MS;
   STAT31 := T#0MS;
   C1_Timer := 0.000000e+000;
   C2_Timer := 0.000000e+000;
   C3_Timer := 0.000000e+000;
   C4_Timer := 0.000000e+000;
   C5_Timer := 0.000000e+000;
   C6_Timer := 0.000000e+000;
   C1_Posizione_1 := L#163000;
   C1_Posizione_2 := L#183000;
   C1_Posizione_3 := L#193000;
   C1_Posizione_4 := L#235000;
   C1_Velocita_1 := L#500;
   C1_Velocita_2 := L#200;
   C1_Velocita_3 := L#200;
   C1_Velocita_4 := L#50;
   C1_Accell_1 := L#500;
   C1_Accell_2 := L#500;
   C1_Accell_3 := L#500;
   C1_Accell_4 := L#500;
   word_148 := W#16#0;
   C2_Posizione_1 := L#326000;
   C2_Posizione_2 := L#346000;
   C2_Posizione_3 := L#356000;
   C2_Posizione_4 := L#401000;
   C2_Velocita_1 := L#500;
   C2_Velocita_2 := L#200;
   C2_Velocita_3 := L#200;
   C2_Velocita_4 := L#50;
   C2_Accell_1 := L#500;
   C2_Accell_2 := L#500;
   C2_Accell_3 := L#500;
   C2_Accell_4 := L#500;
   word_198 := W#16#0;
   C3_Posizione_1 := L#200000;
   C3_Posizione_2 := L#220000;
   C3_Posizione_3 := L#230000;
   C3_Posizione_4 := L#385000;
   C3_Velocita_1 := L#500;
   C3_Velocita_2 := L#200;
   C3_Velocita_3 := L#200;
   C3_Velocita_4 := L#50;
   C3_Accell_1 := L#500;
   C3_Accell_2 := L#500;
   C3_Accell_3 := L#500;
   C3_Accell_4 := L#500;
   word_248 := W#16#0;
   C4_Posizione_1 := L#100000;
   C4_Posizione_2 := L#120000;
   C4_Posizione_3 := L#130000;
   C4_Posizione_4 := L#283000;
   C4_Velocita_1 := L#500;
   C4_Velocita_2 := L#200;
   C4_Velocita_3 := L#200;
   C4_Velocita_4 := L#50;
   C4_Accell_1 := L#500;
   C4_Accell_2 := L#500;
   C4_Accell_3 := L#500;
   C4_Accell_4 := L#500;
   word_298 := W#16#0;
   C5_Posizione_1 := L#395000;
   C5_Posizione_2 := L#415000;
   C5_Posizione_3 := L#425000;
   C5_Posizione_4 := L#510000;
   C5_Velocita_1 := L#500;
   C5_Velocita_2 := L#200;
   C5_Velocita_3 := L#200;
   C5_Velocita_4 := L#50;
   C5_Accell_1 := L#500;
   C5_Accell_2 := L#500;
   C5_Accell_3 := L#500;
   C5_Accell_4 := L#500;
   word_348 := W#16#0;
   C6_Posizione_1 := L#430000;
   C6_Posizione_2 := L#450000;
   C6_Posizione_3 := L#460000;
   C6_Posizione_4 := L#525000;
   C6_Velocita_1 := L#500;
   C6_Velocita_2 := L#200;
   C6_Velocita_3 := L#200;
   C6_Velocita_4 := L#50;
   C6_Accell_1 := L#500;
   C6_Accell_2 := L#500;
   C6_Accell_3 := L#500;
   C6_Accell_4 := L#500;
   word_398 := W#16#0;
END_DATA_BLOCK

DATA_BLOCK "MATRICOLA 24"
AUTHOR : Lodato
FAMILY : DESTACK
NAME : DATI
VERSION : 0.1


  STRUCT
   LARGHEZZA_LAMIERA : REAL  := 1.500000e+003;	//LARGHEZZA LAMIERA ATTUALE
   COMPENSAZ_TAV_1 : REAL ;	//COMPENSAZIONE TAVOLA 1
   QUOTA_H_SFOGLIATORE : REAL ;	//Quota impostata altezza sfogliatore
   QUOTA_H_CENTRATORE : REAL ;	//Quota impostata altezza centratore
   word16 : S5TIME ;
   INCLINAZ_TAVOLA_ESCLUSA : BOOL ;	//INCLINAZIONE TAVOLA ESCLUSA
   dword20 : REAL ;
   dword24 : REAL ;
   dword28 : REAL ;
   dword32 : REAL ;
   dword36 : REAL ;
   NR_MATRICOLA : INT  := 1;	//Numero di matricola
   word42 : WORD ;
   MAGNETE_1_ESCLUSO : BOOL ;	//MAGNETE 1 ESCLUSO DA MP270
   MAGNETE_2_ESCLUSO : BOOL ;	//MAGNETE 2 ESCLUSO DA MP270
   MAGNETE_3_ESCLUSO : BOOL ;	//MAGNETE 3 ESCLUSO DA MP270
   MAGNETE_4_ESCLUSO : BOOL ;	//MAGNETE 4 ESCLUSO DA MP270
   MAGNETE_5_ESCLUSO : BOOL ;	//MAGNETE 5 ESCLUSO DA MP270
   MAGNETE_6_ESCLUSO : BOOL ;	//MAGNETE 6 ESCLUSO DA MP270
   MAGNETE_LAT_SX_ESCLUSO : BOOL ;	//MAGNETE LATERALE SX ESCLUSO DA MP270
   MAGNETE_LAT_DX_ESCLUSO : BOOL ;	//MAGNETE LATERALE DX ESCLUSO DA MP270
   COMPENSAZ_TAV_2 : REAL ;	//COMPENSAZIONE TAVOLA 2
   STAT22 : WORD ;
   STAT23 : WORD ;
   STAT24 : WORD ;
   STAT25 : WORD ;
   STAT251 : WORD ;
   STAT26 : TIME ;
   STAT29 : TIME ;
   STAT30 : TIME ;
   STAT31 : TIME ;
   C1_Timer : REAL ;	//Centratore 1: Timer ritardo partenza
   C2_Timer : REAL ;	//Centratore 2: Timer ritardo partenza
   C3_Timer : REAL ;	//Centratore 3: Timer ritardo partenza
   C4_Timer : REAL ;	//Centratore 4: Timer ritardo partenza
   C5_Timer : REAL ;	//Centratore 5: Timer ritardo partenza
   C6_Timer : REAL ;	//Centratore 6: Timer ritardo partenza
   C1_Posizione_1 : DINT  := L#500000;	//Centratore 1: Posizione 1 di avicinamento
   C1_Posizione_2 : DINT  := L#520000;	//Centratore 1: Posizione 2 di cambio velocita'
   C1_Posizione_3 : DINT  := L#530000;	//Centratore 1: Posizione 3 di cambio velocita'
   C1_Posizione_4 : DINT  := L#565400;	//Centratore 1: Posizione 4 di arrivo
   C1_Velocita_1 : DINT  := L#50;	//Centratore 1: Velocita' 1 di avvicinamento
   C1_Velocita_2 : DINT  := L#50;	//Centratore 1: Velocita' 2
   C1_Velocita_3 : DINT  := L#50;	//Centratore 1: Velocita' 3
   C1_Velocita_4 : DINT  := L#50;	//Centratore 1: Velocita' 4 di arrivo
   C1_Accell_1 : DINT  := L#500;	//Centratore 1: Accelerazione 1 di avvicinamento
   C1_Accell_2 : DINT  := L#500;	//Centratore 1: Accelerazione 2
   C1_Accell_3 : DINT  := L#500;	//Centratore 1: Accelerazione 3
   C1_Accell_4 : DINT  := L#500;	//Centratore 1: Accelerazione 4 di arrivo
   word_148 : WORD ;
   C2_Posizione_1 : DINT  := L#500000;	//Centratore 2: Posizione 1 di avicinamento
   C2_Posizione_2 : DINT  := L#520000;	//Centratore 2: Posizione 2 di cambio velocita'
   C2_Posizione_3 : DINT  := L#530000;	//Centratore 2: Posizione 3 di cambio velocita'
   C2_Posizione_4 : DINT  := L#559000;	//Centratore 2: Posizione 4 di arrivo
   C2_Velocita_1 : DINT  := L#50;	//Centratore 2: Velocita' 1 di avvicinamento
   C2_Velocita_2 : DINT  := L#50;	//Centratore 2: Velocita' 2
   C2_Velocita_3 : DINT  := L#50;	//Centratore 2: Velocita' 3
   C2_Velocita_4 : DINT  := L#50;	//Centratore 2: Velocita' 4 di arrivo
   C2_Accell_1 : DINT  := L#500;	//Centratore 2: Accelerazione 1 di avvicinamento
   C2_Accell_2 : DINT  := L#500;	//Centratore 2: Accelerazione 2
   C2_Accell_3 : DINT  := L#500;	//Centratore 2: Accelerazione 3
   C2_Accell_4 : DINT  := L#500;	//Centratore 2: Accelerazione 4 di arrivo
   word_198 : WORD ;
   C3_Posizione_1 : DINT  := L#630000;	//Centratore 3: Posizione 1 di avicinamento
   C3_Posizione_2 : DINT  := L#650000;	//Centratore 3: Posizione 2 di cambio velocita'
   C3_Posizione_3 : DINT  := L#660000;	//Centratore 3: Posizione 3 di cambio velocita'
   C3_Posizione_4 : DINT  := L#698600;	//Centratore 3: Posizione 4 di arrivo
   C3_Velocita_1 : DINT  := L#50;	//Centratore 3: Velocita' 1 di avvicinamento
   C3_Velocita_2 : DINT  := L#50;	//Centratore 3: Velocita' 2
   C3_Velocita_3 : DINT  := L#50;	//Centratore 3: Velocita' 3
   C3_Velocita_4 : DINT  := L#50;	//Centratore 3: Velocita' 4 di arrivo
   C3_Accell_1 : DINT  := L#500;	//Centratore 3: Accelerazione 1 di avvicinamento
   C3_Accell_2 : DINT  := L#500;	//Centratore 3: Accelerazione 2
   C3_Accell_3 : DINT  := L#500;	//Centratore 3: Accelerazione 3
   C3_Accell_4 : DINT  := L#500;	//Centratore 3: Accelerazione 4 di arrivo
   word_248 : WORD ;
   C4_Posizione_1 : DINT  := L#630000;	//Centratore 4: Posizione 1 di avicinamento
   C4_Posizione_2 : DINT  := L#650000;	//Centratore 4: Posizione 2 di cambio velocita'
   C4_Posizione_3 : DINT  := L#660000;	//Centratore 4: Posizione 3 di cambio velocita'
   C4_Posizione_4 : DINT  := L#706200;	//Centratore 4: Posizione 4 di arrivo
   C4_Velocita_1 : DINT  := L#50;	//Centratore 4: Velocita' 1 di avvicinamento
   C4_Velocita_2 : DINT  := L#50;	//Centratore 4: Velocita' 2
   C4_Velocita_3 : DINT  := L#50;	//Centratore 4: Velocita' 3
   C4_Velocita_4 : DINT  := L#50;	//Centratore 4: Velocita' 4 di arrivo
   C4_Accell_1 : DINT  := L#500;	//Centratore 4: Accelerazione 1 di avvicinamento
   C4_Accell_2 : DINT  := L#500;	//Centratore 4: Accelerazione 2
   C4_Accell_3 : DINT  := L#500;	//Centratore 4: Accelerazione 3
   C4_Accell_4 : DINT  := L#500;	//Centratore 4: Accelerazione 4 di arrivo
   word_298 : WORD ;
   C5_Posizione_1 : DINT  := L#1180000;	//Centratore 5: Posizione 1 di avicinamento
   C5_Posizione_2 : DINT  := L#1200000;	//Centratore 5: Posizione 2 di cambio velocita'
   C5_Posizione_3 : DINT  := L#1220000;	//Centratore 5: Posizione 3 di cambio velocita'
   C5_Posizione_4 : DINT  := L#1247000;	//Centratore 5: Posizione 4 di arrivo
   C5_Velocita_1 : DINT  := L#50;	//Centratore 5: Velocita' 1 di avvicinamento
   C5_Velocita_2 : DINT  := L#50;	//Centratore 5: Velocita' 2
   C5_Velocita_3 : DINT  := L#50;	//Centratore 5: Velocita' 3
   C5_Velocita_4 : DINT  := L#50;	//Centratore 5: Velocita' 4 di arrivo
   C5_Accell_1 : DINT  := L#500;	//Centratore 5: Accelerazione 1 di avvicinamento
   C5_Accell_2 : DINT  := L#500;	//Centratore 5: Accelerazione 2
   C5_Accell_3 : DINT  := L#500;	//Centratore 5: Accelerazione 3
   C5_Accell_4 : DINT  := L#500;	//Centratore 5: Accelerazione 4 di arrivo
   word_348 : WORD ;
   C6_Posizione_1 : DINT  := L#1180000;	//Centratore 6: Posizione 1 di avicinamento
   C6_Posizione_2 : DINT  := L#1200000;	//Centratore 6: Posizione 2 di cambio velocita'
   C6_Posizione_3 : DINT  := L#1220000;	//Centratore 6: Posizione 3 di cambio velocita'
   C6_Posizione_4 : DINT  := L#1237400;	//Centratore 6: Posizione 4 di arrivo
   C6_Velocita_1 : DINT  := L#50;	//Centratore 6: Velocita' 1 di avvicinamento
   C6_Velocita_2 : DINT  := L#50;	//Centratore 6: Velocita' 2
   C6_Velocita_3 : DINT  := L#50;	//Centratore 6: Velocita' 3
   C6_Velocita_4 : DINT  := L#50;	//Centratore 6: Velocita' 4 di arrivo
   C6_Accell_1 : DINT  := L#500;	//Centratore 6: Accelerazione 1 di avvicinamento
   C6_Accell_2 : DINT  := L#500;	//Centratore 6: Accelerazione 2
   C6_Accell_3 : DINT  := L#500;	//Centratore 6: Accelerazione 3
   C6_Accell_4 : DINT  := L#500;	//Centratore 6: Accelerazione 4 di arrivo
   word_398 : WORD ;
  END_STRUCT ;
BEGIN
   LARGHEZZA_LAMIERA := 3.060000e+003;
   COMPENSAZ_TAV_1 := -7.000000e+001;
   QUOTA_H_SFOGLIATORE := 2.000000e+003;
   QUOTA_H_CENTRATORE := 1.960000e+003;
   word16 := S5T#0MS;
   INCLINAZ_TAVOLA_ESCLUSA := FALSE;
   dword20 := 0.000000e+000;
   dword24 := 0.000000e+000;
   dword28 := 0.000000e+000;
   dword32 := 0.000000e+000;
   dword36 := 0.000000e+000;
   NR_MATRICOLA := 2;
   word42 := W#16#0;
   MAGNETE_1_ESCLUSO := FALSE;
   MAGNETE_2_ESCLUSO := FALSE;
   MAGNETE_3_ESCLUSO := FALSE;
   MAGNETE_4_ESCLUSO := FALSE;
   MAGNETE_5_ESCLUSO := FALSE;
   MAGNETE_6_ESCLUSO := FALSE;
   MAGNETE_LAT_SX_ESCLUSO := FALSE;
   MAGNETE_LAT_DX_ESCLUSO := FALSE;
   COMPENSAZ_TAV_2 := -3.000000e+001;
   STAT22 := W#16#0;
   STAT23 := W#16#0;
   STAT24 := W#16#0;
   STAT25 := W#16#0;
   STAT251 := W#16#0;
   STAT26 := T#0MS;
   STAT29 := T#0MS;
   STAT30 := T#0MS;
   STAT31 := T#0MS;
   C1_Timer := 0.000000e+000;
   C2_Timer := 0.000000e+000;
   C3_Timer := 0.000000e+000;
   C4_Timer := 0.000000e+000;
   C5_Timer := 0.000000e+000;
   C6_Timer := 0.000000e+000;
   C1_Posizione_1 := L#163000;
   C1_Posizione_2 := L#183000;
   C1_Posizione_3 := L#193000;
   C1_Posizione_4 := L#235000;
   C1_Velocita_1 := L#500;
   C1_Velocita_2 := L#200;
   C1_Velocita_3 := L#200;
   C1_Velocita_4 := L#50;
   C1_Accell_1 := L#500;
   C1_Accell_2 := L#500;
   C1_Accell_3 := L#500;
   C1_Accell_4 := L#500;
   word_148 := W#16#0;
   C2_Posizione_1 := L#326000;
   C2_Posizione_2 := L#346000;
   C2_Posizione_3 := L#356000;
   C2_Posizione_4 := L#401000;
   C2_Velocita_1 := L#500;
   C2_Velocita_2 := L#200;
   C2_Velocita_3 := L#200;
   C2_Velocita_4 := L#50;
   C2_Accell_1 := L#500;
   C2_Accell_2 := L#500;
   C2_Accell_3 := L#500;
   C2_Accell_4 := L#500;
   word_198 := W#16#0;
   C3_Posizione_1 := L#200000;
   C3_Posizione_2 := L#220000;
   C3_Posizione_3 := L#230000;
   C3_Posizione_4 := L#385000;
   C3_Velocita_1 := L#500;
   C3_Velocita_2 := L#200;
   C3_Velocita_3 := L#200;
   C3_Velocita_4 := L#50;
   C3_Accell_1 := L#500;
   C3_Accell_2 := L#500;
   C3_Accell_3 := L#500;
   C3_Accell_4 := L#500;
   word_248 := W#16#0;
   C4_Posizione_1 := L#100000;
   C4_Posizione_2 := L#120000;
   C4_Posizione_3 := L#130000;
   C4_Posizione_4 := L#283000;
   C4_Velocita_1 := L#500;
   C4_Velocita_2 := L#200;
   C4_Velocita_3 := L#200;
   C4_Velocita_4 := L#50;
   C4_Accell_1 := L#500;
   C4_Accell_2 := L#500;
   C4_Accell_3 := L#500;
   C4_Accell_4 := L#500;
   word_298 := W#16#0;
   C5_Posizione_1 := L#395000;
   C5_Posizione_2 := L#415000;
   C5_Posizione_3 := L#425000;
   C5_Posizione_4 := L#510000;
   C5_Velocita_1 := L#500;
   C5_Velocita_2 := L#200;
   C5_Velocita_3 := L#200;
   C5_Velocita_4 := L#50;
   C5_Accell_1 := L#500;
   C5_Accell_2 := L#500;
   C5_Accell_3 := L#500;
   C5_Accell_4 := L#500;
   word_348 := W#16#0;
   C6_Posizione_1 := L#430000;
   C6_Posizione_2 := L#450000;
   C6_Posizione_3 := L#460000;
   C6_Posizione_4 := L#525000;
   C6_Velocita_1 := L#500;
   C6_Velocita_2 := L#200;
   C6_Velocita_3 := L#200;
   C6_Velocita_4 := L#50;
   C6_Accell_1 := L#500;
   C6_Accell_2 := L#500;
   C6_Accell_3 := L#500;
   C6_Accell_4 := L#500;
   word_398 := W#16#0;
END_DATA_BLOCK

DATA_BLOCK "MATRICOLA 25"
AUTHOR : Lodato
FAMILY : DESTACK
NAME : DATI
VERSION : 0.1


  STRUCT
   LARGHEZZA_LAMIERA : REAL  := 1.500000e+003;	//LARGHEZZA LAMIERA ATTUALE
   COMPENSAZ_TAV_1 : REAL ;	//COMPENSAZIONE TAVOLA 1
   QUOTA_H_SFOGLIATORE : REAL ;	//Quota impostata altezza sfogliatore
   QUOTA_H_CENTRATORE : REAL ;	//Quota impostata altezza centratore
   word16 : S5TIME ;
   INCLINAZ_TAVOLA_ESCLUSA : BOOL ;	//INCLINAZIONE TAVOLA ESCLUSA
   dword20 : REAL ;
   dword24 : REAL ;
   dword28 : REAL ;
   dword32 : REAL ;
   dword36 : REAL ;
   NR_MATRICOLA : INT  := 1;	//Numero di matricola
   word42 : WORD ;
   MAGNETE_1_ESCLUSO : BOOL ;	//MAGNETE 1 ESCLUSO DA MP270
   MAGNETE_2_ESCLUSO : BOOL ;	//MAGNETE 2 ESCLUSO DA MP270
   MAGNETE_3_ESCLUSO : BOOL ;	//MAGNETE 3 ESCLUSO DA MP270
   MAGNETE_4_ESCLUSO : BOOL ;	//MAGNETE 4 ESCLUSO DA MP270
   MAGNETE_5_ESCLUSO : BOOL ;	//MAGNETE 5 ESCLUSO DA MP270
   MAGNETE_6_ESCLUSO : BOOL ;	//MAGNETE 6 ESCLUSO DA MP270
   MAGNETE_LAT_SX_ESCLUSO : BOOL ;	//MAGNETE LATERALE SX ESCLUSO DA MP270
   MAGNETE_LAT_DX_ESCLUSO : BOOL ;	//MAGNETE LATERALE DX ESCLUSO DA MP270
   COMPENSAZ_TAV_2 : REAL ;	//COMPENSAZIONE TAVOLA 2
   STAT22 : WORD ;
   STAT23 : WORD ;
   STAT24 : WORD ;
   STAT25 : WORD ;
   STAT251 : WORD ;
   STAT26 : TIME ;
   STAT29 : TIME ;
   STAT30 : TIME ;
   STAT31 : TIME ;
   C1_Timer : REAL ;	//Centratore 1: Timer ritardo partenza
   C2_Timer : REAL ;	//Centratore 2: Timer ritardo partenza
   C3_Timer : REAL ;	//Centratore 3: Timer ritardo partenza
   C4_Timer : REAL ;	//Centratore 4: Timer ritardo partenza
   C5_Timer : REAL ;	//Centratore 5: Timer ritardo partenza
   C6_Timer : REAL ;	//Centratore 6: Timer ritardo partenza
   C1_Posizione_1 : DINT  := L#500000;	//Centratore 1: Posizione 1 di avicinamento
   C1_Posizione_2 : DINT  := L#520000;	//Centratore 1: Posizione 2 di cambio velocita'
   C1_Posizione_3 : DINT  := L#530000;	//Centratore 1: Posizione 3 di cambio velocita'
   C1_Posizione_4 : DINT  := L#565400;	//Centratore 1: Posizione 4 di arrivo
   C1_Velocita_1 : DINT  := L#50;	//Centratore 1: Velocita' 1 di avvicinamento
   C1_Velocita_2 : DINT  := L#50;	//Centratore 1: Velocita' 2
   C1_Velocita_3 : DINT  := L#50;	//Centratore 1: Velocita' 3
   C1_Velocita_4 : DINT  := L#50;	//Centratore 1: Velocita' 4 di arrivo
   C1_Accell_1 : DINT  := L#500;	//Centratore 1: Accelerazione 1 di avvicinamento
   C1_Accell_2 : DINT  := L#500;	//Centratore 1: Accelerazione 2
   C1_Accell_3 : DINT  := L#500;	//Centratore 1: Accelerazione 3
   C1_Accell_4 : DINT  := L#500;	//Centratore 1: Accelerazione 4 di arrivo
   word_148 : WORD ;
   C2_Posizione_1 : DINT  := L#500000;	//Centratore 2: Posizione 1 di avicinamento
   C2_Posizione_2 : DINT  := L#520000;	//Centratore 2: Posizione 2 di cambio velocita'
   C2_Posizione_3 : DINT  := L#530000;	//Centratore 2: Posizione 3 di cambio velocita'
   C2_Posizione_4 : DINT  := L#559000;	//Centratore 2: Posizione 4 di arrivo
   C2_Velocita_1 : DINT  := L#50;	//Centratore 2: Velocita' 1 di avvicinamento
   C2_Velocita_2 : DINT  := L#50;	//Centratore 2: Velocita' 2
   C2_Velocita_3 : DINT  := L#50;	//Centratore 2: Velocita' 3
   C2_Velocita_4 : DINT  := L#50;	//Centratore 2: Velocita' 4 di arrivo
   C2_Accell_1 : DINT  := L#500;	//Centratore 2: Accelerazione 1 di avvicinamento
   C2_Accell_2 : DINT  := L#500;	//Centratore 2: Accelerazione 2
   C2_Accell_3 : DINT  := L#500;	//Centratore 2: Accelerazione 3
   C2_Accell_4 : DINT  := L#500;	//Centratore 2: Accelerazione 4 di arrivo
   word_198 : WORD ;
   C3_Posizione_1 : DINT  := L#630000;	//Centratore 3: Posizione 1 di avicinamento
   C3_Posizione_2 : DINT  := L#650000;	//Centratore 3: Posizione 2 di cambio velocita'
   C3_Posizione_3 : DINT  := L#660000;	//Centratore 3: Posizione 3 di cambio velocita'
   C3_Posizione_4 : DINT  := L#698600;	//Centratore 3: Posizione 4 di arrivo
   C3_Velocita_1 : DINT  := L#50;	//Centratore 3: Velocita' 1 di avvicinamento
   C3_Velocita_2 : DINT  := L#50;	//Centratore 3: Velocita' 2
   C3_Velocita_3 : DINT  := L#50;	//Centratore 3: Velocita' 3
   C3_Velocita_4 : DINT  := L#50;	//Centratore 3: Velocita' 4 di arrivo
   C3_Accell_1 : DINT  := L#500;	//Centratore 3: Accelerazione 1 di avvicinamento
   C3_Accell_2 : DINT  := L#500;	//Centratore 3: Accelerazione 2
   C3_Accell_3 : DINT  := L#500;	//Centratore 3: Accelerazione 3
   C3_Accell_4 : DINT  := L#500;	//Centratore 3: Accelerazione 4 di arrivo
   word_248 : WORD ;
   C4_Posizione_1 : DINT  := L#630000;	//Centratore 4: Posizione 1 di avicinamento
   C4_Posizione_2 : DINT  := L#650000;	//Centratore 4: Posizione 2 di cambio velocita'
   C4_Posizione_3 : DINT  := L#660000;	//Centratore 4: Posizione 3 di cambio velocita'
   C4_Posizione_4 : DINT  := L#706200;	//Centratore 4: Posizione 4 di arrivo
   C4_Velocita_1 : DINT  := L#50;	//Centratore 4: Velocita' 1 di avvicinamento
   C4_Velocita_2 : DINT  := L#50;	//Centratore 4: Velocita' 2
   C4_Velocita_3 : DINT  := L#50;	//Centratore 4: Velocita' 3
   C4_Velocita_4 : DINT  := L#50;	//Centratore 4: Velocita' 4 di arrivo
   C4_Accell_1 : DINT  := L#500;	//Centratore 4: Accelerazione 1 di avvicinamento
   C4_Accell_2 : DINT  := L#500;	//Centratore 4: Accelerazione 2
   C4_Accell_3 : DINT  := L#500;	//Centratore 4: Accelerazione 3
   C4_Accell_4 : DINT  := L#500;	//Centratore 4: Accelerazione 4 di arrivo
   word_298 : WORD ;
   C5_Posizione_1 : DINT  := L#1180000;	//Centratore 5: Posizione 1 di avicinamento
   C5_Posizione_2 : DINT  := L#1200000;	//Centratore 5: Posizione 2 di cambio velocita'
   C5_Posizione_3 : DINT  := L#1220000;	//Centratore 5: Posizione 3 di cambio velocita'
   C5_Posizione_4 : DINT  := L#1247000;	//Centratore 5: Posizione 4 di arrivo
   C5_Velocita_1 : DINT  := L#50;	//Centratore 5: Velocita' 1 di avvicinamento
   C5_Velocita_2 : DINT  := L#50;	//Centratore 5: Velocita' 2
   C5_Velocita_3 : DINT  := L#50;	//Centratore 5: Velocita' 3
   C5_Velocita_4 : DINT  := L#50;	//Centratore 5: Velocita' 4 di arrivo
   C5_Accell_1 : DINT  := L#500;	//Centratore 5: Accelerazione 1 di avvicinamento
   C5_Accell_2 : DINT  := L#500;	//Centratore 5: Accelerazione 2
   C5_Accell_3 : DINT  := L#500;	//Centratore 5: Accelerazione 3
   C5_Accell_4 : DINT  := L#500;	//Centratore 5: Accelerazione 4 di arrivo
   word_348 : WORD ;
   C6_Posizione_1 : DINT  := L#1180000;	//Centratore 6: Posizione 1 di avicinamento
   C6_Posizione_2 : DINT  := L#1200000;	//Centratore 6: Posizione 2 di cambio velocita'
   C6_Posizione_3 : DINT  := L#1220000;	//Centratore 6: Posizione 3 di cambio velocita'
   C6_Posizione_4 : DINT  := L#1237400;	//Centratore 6: Posizione 4 di arrivo
   C6_Velocita_1 : DINT  := L#50;	//Centratore 6: Velocita' 1 di avvicinamento
   C6_Velocita_2 : DINT  := L#50;	//Centratore 6: Velocita' 2
   C6_Velocita_3 : DINT  := L#50;	//Centratore 6: Velocita' 3
   C6_Velocita_4 : DINT  := L#50;	//Centratore 6: Velocita' 4 di arrivo
   C6_Accell_1 : DINT  := L#500;	//Centratore 6: Accelerazione 1 di avvicinamento
   C6_Accell_2 : DINT  := L#500;	//Centratore 6: Accelerazione 2
   C6_Accell_3 : DINT  := L#500;	//Centratore 6: Accelerazione 3
   C6_Accell_4 : DINT  := L#500;	//Centratore 6: Accelerazione 4 di arrivo
   word_398 : WORD ;
  END_STRUCT ;
BEGIN
   LARGHEZZA_LAMIERA := 3.060000e+003;
   COMPENSAZ_TAV_1 := -7.000000e+001;
   QUOTA_H_SFOGLIATORE := 2.000000e+003;
   QUOTA_H_CENTRATORE := 1.960000e+003;
   word16 := S5T#0MS;
   INCLINAZ_TAVOLA_ESCLUSA := FALSE;
   dword20 := 0.000000e+000;
   dword24 := 0.000000e+000;
   dword28 := 0.000000e+000;
   dword32 := 0.000000e+000;
   dword36 := 0.000000e+000;
   NR_MATRICOLA := 2;
   word42 := W#16#0;
   MAGNETE_1_ESCLUSO := FALSE;
   MAGNETE_2_ESCLUSO := FALSE;
   MAGNETE_3_ESCLUSO := FALSE;
   MAGNETE_4_ESCLUSO := FALSE;
   MAGNETE_5_ESCLUSO := FALSE;
   MAGNETE_6_ESCLUSO := FALSE;
   MAGNETE_LAT_SX_ESCLUSO := FALSE;
   MAGNETE_LAT_DX_ESCLUSO := FALSE;
   COMPENSAZ_TAV_2 := -3.000000e+001;
   STAT22 := W#16#0;
   STAT23 := W#16#0;
   STAT24 := W#16#0;
   STAT25 := W#16#0;
   STAT251 := W#16#0;
   STAT26 := T#0MS;
   STAT29 := T#0MS;
   STAT30 := T#0MS;
   STAT31 := T#0MS;
   C1_Timer := 0.000000e+000;
   C2_Timer := 0.000000e+000;
   C3_Timer := 0.000000e+000;
   C4_Timer := 0.000000e+000;
   C5_Timer := 0.000000e+000;
   C6_Timer := 0.000000e+000;
   C1_Posizione_1 := L#163000;
   C1_Posizione_2 := L#183000;
   C1_Posizione_3 := L#193000;
   C1_Posizione_4 := L#235000;
   C1_Velocita_1 := L#500;
   C1_Velocita_2 := L#200;
   C1_Velocita_3 := L#200;
   C1_Velocita_4 := L#50;
   C1_Accell_1 := L#500;
   C1_Accell_2 := L#500;
   C1_Accell_3 := L#500;
   C1_Accell_4 := L#500;
   word_148 := W#16#0;
   C2_Posizione_1 := L#326000;
   C2_Posizione_2 := L#346000;
   C2_Posizione_3 := L#356000;
   C2_Posizione_4 := L#401000;
   C2_Velocita_1 := L#500;
   C2_Velocita_2 := L#200;
   C2_Velocita_3 := L#200;
   C2_Velocita_4 := L#50;
   C2_Accell_1 := L#500;
   C2_Accell_2 := L#500;
   C2_Accell_3 := L#500;
   C2_Accell_4 := L#500;
   word_198 := W#16#0;
   C3_Posizione_1 := L#200000;
   C3_Posizione_2 := L#220000;
   C3_Posizione_3 := L#230000;
   C3_Posizione_4 := L#385000;
   C3_Velocita_1 := L#500;
   C3_Velocita_2 := L#200;
   C3_Velocita_3 := L#200;
   C3_Velocita_4 := L#50;
   C3_Accell_1 := L#500;
   C3_Accell_2 := L#500;
   C3_Accell_3 := L#500;
   C3_Accell_4 := L#500;
   word_248 := W#16#0;
   C4_Posizione_1 := L#100000;
   C4_Posizione_2 := L#120000;
   C4_Posizione_3 := L#130000;
   C4_Posizione_4 := L#283000;
   C4_Velocita_1 := L#500;
   C4_Velocita_2 := L#200;
   C4_Velocita_3 := L#200;
   C4_Velocita_4 := L#50;
   C4_Accell_1 := L#500;
   C4_Accell_2 := L#500;
   C4_Accell_3 := L#500;
   C4_Accell_4 := L#500;
   word_298 := W#16#0;
   C5_Posizione_1 := L#395000;
   C5_Posizione_2 := L#415000;
   C5_Posizione_3 := L#425000;
   C5_Posizione_4 := L#510000;
   C5_Velocita_1 := L#500;
   C5_Velocita_2 := L#200;
   C5_Velocita_3 := L#200;
   C5_Velocita_4 := L#50;
   C5_Accell_1 := L#500;
   C5_Accell_2 := L#500;
   C5_Accell_3 := L#500;
   C5_Accell_4 := L#500;
   word_348 := W#16#0;
   C6_Posizione_1 := L#430000;
   C6_Posizione_2 := L#450000;
   C6_Posizione_3 := L#460000;
   C6_Posizione_4 := L#525000;
   C6_Velocita_1 := L#500;
   C6_Velocita_2 := L#200;
   C6_Velocita_3 := L#200;
   C6_Velocita_4 := L#50;
   C6_Accell_1 := L#500;
   C6_Accell_2 := L#500;
   C6_Accell_3 := L#500;
   C6_Accell_4 := L#500;
   word_398 := W#16#0;
END_DATA_BLOCK

DATA_BLOCK "MATRICOLA 26"
AUTHOR : Lodato
FAMILY : DESTACK
NAME : DATI
VERSION : 0.1


  STRUCT
   LARGHEZZA_LAMIERA : REAL  := 1.500000e+003;	//LARGHEZZA LAMIERA ATTUALE
   COMPENSAZ_TAV_1 : REAL ;	//COMPENSAZIONE TAVOLA 1
   QUOTA_H_SFOGLIATORE : REAL ;	//Quota impostata altezza sfogliatore
   QUOTA_H_CENTRATORE : REAL ;	//Quota impostata altezza centratore
   word16 : S5TIME ;
   INCLINAZ_TAVOLA_ESCLUSA : BOOL ;	//INCLINAZIONE TAVOLA ESCLUSA
   dword20 : REAL ;
   dword24 : REAL ;
   dword28 : REAL ;
   dword32 : REAL ;
   dword36 : REAL ;
   NR_MATRICOLA : INT  := 1;	//Numero di matricola
   word42 : WORD ;
   MAGNETE_1_ESCLUSO : BOOL ;	//MAGNETE 1 ESCLUSO DA MP270
   MAGNETE_2_ESCLUSO : BOOL ;	//MAGNETE 2 ESCLUSO DA MP270
   MAGNETE_3_ESCLUSO : BOOL ;	//MAGNETE 3 ESCLUSO DA MP270
   MAGNETE_4_ESCLUSO : BOOL ;	//MAGNETE 4 ESCLUSO DA MP270
   MAGNETE_5_ESCLUSO : BOOL ;	//MAGNETE 5 ESCLUSO DA MP270
   MAGNETE_6_ESCLUSO : BOOL ;	//MAGNETE 6 ESCLUSO DA MP270
   MAGNETE_LAT_SX_ESCLUSO : BOOL ;	//MAGNETE LATERALE SX ESCLUSO DA MP270
   MAGNETE_LAT_DX_ESCLUSO : BOOL ;	//MAGNETE LATERALE DX ESCLUSO DA MP270
   COMPENSAZ_TAV_2 : REAL ;	//COMPENSAZIONE TAVOLA 2
   STAT22 : WORD ;
   STAT23 : WORD ;
   STAT24 : WORD ;
   STAT25 : WORD ;
   STAT251 : WORD ;
   STAT26 : TIME ;
   STAT29 : TIME ;
   STAT30 : TIME ;
   STAT31 : TIME ;
   C1_Timer : REAL ;	//Centratore 1: Timer ritardo partenza
   C2_Timer : REAL ;	//Centratore 2: Timer ritardo partenza
   C3_Timer : REAL ;	//Centratore 3: Timer ritardo partenza
   C4_Timer : REAL ;	//Centratore 4: Timer ritardo partenza
   C5_Timer : REAL ;	//Centratore 5: Timer ritardo partenza
   C6_Timer : REAL ;	//Centratore 6: Timer ritardo partenza
   C1_Posizione_1 : DINT  := L#500000;	//Centratore 1: Posizione 1 di avicinamento
   C1_Posizione_2 : DINT  := L#520000;	//Centratore 1: Posizione 2 di cambio velocita'
   C1_Posizione_3 : DINT  := L#530000;	//Centratore 1: Posizione 3 di cambio velocita'
   C1_Posizione_4 : DINT  := L#565400;	//Centratore 1: Posizione 4 di arrivo
   C1_Velocita_1 : DINT  := L#50;	//Centratore 1: Velocita' 1 di avvicinamento
   C1_Velocita_2 : DINT  := L#50;	//Centratore 1: Velocita' 2
   C1_Velocita_3 : DINT  := L#50;	//Centratore 1: Velocita' 3
   C1_Velocita_4 : DINT  := L#50;	//Centratore 1: Velocita' 4 di arrivo
   C1_Accell_1 : DINT  := L#500;	//Centratore 1: Accelerazione 1 di avvicinamento
   C1_Accell_2 : DINT  := L#500;	//Centratore 1: Accelerazione 2
   C1_Accell_3 : DINT  := L#500;	//Centratore 1: Accelerazione 3
   C1_Accell_4 : DINT  := L#500;	//Centratore 1: Accelerazione 4 di arrivo
   word_148 : WORD ;
   C2_Posizione_1 : DINT  := L#500000;	//Centratore 2: Posizione 1 di avicinamento
   C2_Posizione_2 : DINT  := L#520000;	//Centratore 2: Posizione 2 di cambio velocita'
   C2_Posizione_3 : DINT  := L#530000;	//Centratore 2: Posizione 3 di cambio velocita'
   C2_Posizione_4 : DINT  := L#559000;	//Centratore 2: Posizione 4 di arrivo
   C2_Velocita_1 : DINT  := L#50;	//Centratore 2: Velocita' 1 di avvicinamento
   C2_Velocita_2 : DINT  := L#50;	//Centratore 2: Velocita' 2
   C2_Velocita_3 : DINT  := L#50;	//Centratore 2: Velocita' 3
   C2_Velocita_4 : DINT  := L#50;	//Centratore 2: Velocita' 4 di arrivo
   C2_Accell_1 : DINT  := L#500;	//Centratore 2: Accelerazione 1 di avvicinamento
   C2_Accell_2 : DINT  := L#500;	//Centratore 2: Accelerazione 2
   C2_Accell_3 : DINT  := L#500;	//Centratore 2: Accelerazione 3
   C2_Accell_4 : DINT  := L#500;	//Centratore 2: Accelerazione 4 di arrivo
   word_198 : WORD ;
   C3_Posizione_1 : DINT  := L#630000;	//Centratore 3: Posizione 1 di avicinamento
   C3_Posizione_2 : DINT  := L#650000;	//Centratore 3: Posizione 2 di cambio velocita'
   C3_Posizione_3 : DINT  := L#660000;	//Centratore 3: Posizione 3 di cambio velocita'
   C3_Posizione_4 : DINT  := L#698600;	//Centratore 3: Posizione 4 di arrivo
   C3_Velocita_1 : DINT  := L#50;	//Centratore 3: Velocita' 1 di avvicinamento
   C3_Velocita_2 : DINT  := L#50;	//Centratore 3: Velocita' 2
   C3_Velocita_3 : DINT  := L#50;	//Centratore 3: Velocita' 3
   C3_Velocita_4 : DINT  := L#50;	//Centratore 3: Velocita' 4 di arrivo
   C3_Accell_1 : DINT  := L#500;	//Centratore 3: Accelerazione 1 di avvicinamento
   C3_Accell_2 : DINT  := L#500;	//Centratore 3: Accelerazione 2
   C3_Accell_3 : DINT  := L#500;	//Centratore 3: Accelerazione 3
   C3_Accell_4 : DINT  := L#500;	//Centratore 3: Accelerazione 4 di arrivo
   word_248 : WORD ;
   C4_Posizione_1 : DINT  := L#630000;	//Centratore 4: Posizione 1 di avicinamento
   C4_Posizione_2 : DINT  := L#650000;	//Centratore 4: Posizione 2 di cambio velocita'
   C4_Posizione_3 : DINT  := L#660000;	//Centratore 4: Posizione 3 di cambio velocita'
   C4_Posizione_4 : DINT  := L#706200;	//Centratore 4: Posizione 4 di arrivo
   C4_Velocita_1 : DINT  := L#50;	//Centratore 4: Velocita' 1 di avvicinamento
   C4_Velocita_2 : DINT  := L#50;	//Centratore 4: Velocita' 2
   C4_Velocita_3 : DINT  := L#50;	//Centratore 4: Velocita' 3
   C4_Velocita_4 : DINT  := L#50;	//Centratore 4: Velocita' 4 di arrivo
   C4_Accell_1 : DINT  := L#500;	//Centratore 4: Accelerazione 1 di avvicinamento
   C4_Accell_2 : DINT  := L#500;	//Centratore 4: Accelerazione 2
   C4_Accell_3 : DINT  := L#500;	//Centratore 4: Accelerazione 3
   C4_Accell_4 : DINT  := L#500;	//Centratore 4: Accelerazione 4 di arrivo
   word_298 : WORD ;
   C5_Posizione_1 : DINT  := L#1180000;	//Centratore 5: Posizione 1 di avicinamento
   C5_Posizione_2 : DINT  := L#1200000;	//Centratore 5: Posizione 2 di cambio velocita'
   C5_Posizione_3 : DINT  := L#1220000;	//Centratore 5: Posizione 3 di cambio velocita'
   C5_Posizione_4 : DINT  := L#1247000;	//Centratore 5: Posizione 4 di arrivo
   C5_Velocita_1 : DINT  := L#50;	//Centratore 5: Velocita' 1 di avvicinamento
   C5_Velocita_2 : DINT  := L#50;	//Centratore 5: Velocita' 2
   C5_Velocita_3 : DINT  := L#50;	//Centratore 5: Velocita' 3
   C5_Velocita_4 : DINT  := L#50;	//Centratore 5: Velocita' 4 di arrivo
   C5_Accell_1 : DINT  := L#500;	//Centratore 5: Accelerazione 1 di avvicinamento
   C5_Accell_2 : DINT  := L#500;	//Centratore 5: Accelerazione 2
   C5_Accell_3 : DINT  := L#500;	//Centratore 5: Accelerazione 3
   C5_Accell_4 : DINT  := L#500;	//Centratore 5: Accelerazione 4 di arrivo
   word_348 : WORD ;
   C6_Posizione_1 : DINT  := L#1180000;	//Centratore 6: Posizione 1 di avicinamento
   C6_Posizione_2 : DINT  := L#1200000;	//Centratore 6: Posizione 2 di cambio velocita'
   C6_Posizione_3 : DINT  := L#1220000;	//Centratore 6: Posizione 3 di cambio velocita'
   C6_Posizione_4 : DINT  := L#1237400;	//Centratore 6: Posizione 4 di arrivo
   C6_Velocita_1 : DINT  := L#50;	//Centratore 6: Velocita' 1 di avvicinamento
   C6_Velocita_2 : DINT  := L#50;	//Centratore 6: Velocita' 2
   C6_Velocita_3 : DINT  := L#50;	//Centratore 6: Velocita' 3
   C6_Velocita_4 : DINT  := L#50;	//Centratore 6: Velocita' 4 di arrivo
   C6_Accell_1 : DINT  := L#500;	//Centratore 6: Accelerazione 1 di avvicinamento
   C6_Accell_2 : DINT  := L#500;	//Centratore 6: Accelerazione 2
   C6_Accell_3 : DINT  := L#500;	//Centratore 6: Accelerazione 3
   C6_Accell_4 : DINT  := L#500;	//Centratore 6: Accelerazione 4 di arrivo
   word_398 : WORD ;
  END_STRUCT ;
BEGIN
   LARGHEZZA_LAMIERA := 3.060000e+003;
   COMPENSAZ_TAV_1 := -7.000000e+001;
   QUOTA_H_SFOGLIATORE := 2.000000e+003;
   QUOTA_H_CENTRATORE := 1.960000e+003;
   word16 := S5T#0MS;
   INCLINAZ_TAVOLA_ESCLUSA := FALSE;
   dword20 := 0.000000e+000;
   dword24 := 0.000000e+000;
   dword28 := 0.000000e+000;
   dword32 := 0.000000e+000;
   dword36 := 0.000000e+000;
   NR_MATRICOLA := 2;
   word42 := W#16#0;
   MAGNETE_1_ESCLUSO := FALSE;
   MAGNETE_2_ESCLUSO := FALSE;
   MAGNETE_3_ESCLUSO := FALSE;
   MAGNETE_4_ESCLUSO := FALSE;
   MAGNETE_5_ESCLUSO := FALSE;
   MAGNETE_6_ESCLUSO := FALSE;
   MAGNETE_LAT_SX_ESCLUSO := FALSE;
   MAGNETE_LAT_DX_ESCLUSO := FALSE;
   COMPENSAZ_TAV_2 := -3.000000e+001;
   STAT22 := W#16#0;
   STAT23 := W#16#0;
   STAT24 := W#16#0;
   STAT25 := W#16#0;
   STAT251 := W#16#0;
   STAT26 := T#0MS;
   STAT29 := T#0MS;
   STAT30 := T#0MS;
   STAT31 := T#0MS;
   C1_Timer := 0.000000e+000;
   C2_Timer := 0.000000e+000;
   C3_Timer := 0.000000e+000;
   C4_Timer := 0.000000e+000;
   C5_Timer := 0.000000e+000;
   C6_Timer := 0.000000e+000;
   C1_Posizione_1 := L#163000;
   C1_Posizione_2 := L#183000;
   C1_Posizione_3 := L#193000;
   C1_Posizione_4 := L#235000;
   C1_Velocita_1 := L#500;
   C1_Velocita_2 := L#200;
   C1_Velocita_3 := L#200;
   C1_Velocita_4 := L#50;
   C1_Accell_1 := L#500;
   C1_Accell_2 := L#500;
   C1_Accell_3 := L#500;
   C1_Accell_4 := L#500;
   word_148 := W#16#0;
   C2_Posizione_1 := L#326000;
   C2_Posizione_2 := L#346000;
   C2_Posizione_3 := L#356000;
   C2_Posizione_4 := L#401000;
   C2_Velocita_1 := L#500;
   C2_Velocita_2 := L#200;
   C2_Velocita_3 := L#200;
   C2_Velocita_4 := L#50;
   C2_Accell_1 := L#500;
   C2_Accell_2 := L#500;
   C2_Accell_3 := L#500;
   C2_Accell_4 := L#500;
   word_198 := W#16#0;
   C3_Posizione_1 := L#200000;
   C3_Posizione_2 := L#220000;
   C3_Posizione_3 := L#230000;
   C3_Posizione_4 := L#385000;
   C3_Velocita_1 := L#500;
   C3_Velocita_2 := L#200;
   C3_Velocita_3 := L#200;
   C3_Velocita_4 := L#50;
   C3_Accell_1 := L#500;
   C3_Accell_2 := L#500;
   C3_Accell_3 := L#500;
   C3_Accell_4 := L#500;
   word_248 := W#16#0;
   C4_Posizione_1 := L#100000;
   C4_Posizione_2 := L#120000;
   C4_Posizione_3 := L#130000;
   C4_Posizione_4 := L#283000;
   C4_Velocita_1 := L#500;
   C4_Velocita_2 := L#200;
   C4_Velocita_3 := L#200;
   C4_Velocita_4 := L#50;
   C4_Accell_1 := L#500;
   C4_Accell_2 := L#500;
   C4_Accell_3 := L#500;
   C4_Accell_4 := L#500;
   word_298 := W#16#0;
   C5_Posizione_1 := L#395000;
   C5_Posizione_2 := L#415000;
   C5_Posizione_3 := L#425000;
   C5_Posizione_4 := L#510000;
   C5_Velocita_1 := L#500;
   C5_Velocita_2 := L#200;
   C5_Velocita_3 := L#200;
   C5_Velocita_4 := L#50;
   C5_Accell_1 := L#500;
   C5_Accell_2 := L#500;
   C5_Accell_3 := L#500;
   C5_Accell_4 := L#500;
   word_348 := W#16#0;
   C6_Posizione_1 := L#430000;
   C6_Posizione_2 := L#450000;
   C6_Posizione_3 := L#460000;
   C6_Posizione_4 := L#525000;
   C6_Velocita_1 := L#500;
   C6_Velocita_2 := L#200;
   C6_Velocita_3 := L#200;
   C6_Velocita_4 := L#50;
   C6_Accell_1 := L#500;
   C6_Accell_2 := L#500;
   C6_Accell_3 := L#500;
   C6_Accell_4 := L#500;
   word_398 := W#16#0;
END_DATA_BLOCK

DATA_BLOCK "MATRICOLA 27"
AUTHOR : Lodato
FAMILY : DESTACK
NAME : DATI
VERSION : 0.1


  STRUCT
   LARGHEZZA_LAMIERA : REAL  := 1.500000e+003;	//LARGHEZZA LAMIERA ATTUALE
   COMPENSAZ_TAV_1 : REAL ;	//COMPENSAZIONE TAVOLA 1
   QUOTA_H_SFOGLIATORE : REAL ;	//Quota impostata altezza sfogliatore
   QUOTA_H_CENTRATORE : REAL ;	//Quota impostata altezza centratore
   word16 : S5TIME ;
   INCLINAZ_TAVOLA_ESCLUSA : BOOL ;	//INCLINAZIONE TAVOLA ESCLUSA
   dword20 : REAL ;
   dword24 : REAL ;
   dword28 : REAL ;
   dword32 : REAL ;
   dword36 : REAL ;
   NR_MATRICOLA : INT  := 1;	//Numero di matricola
   word42 : WORD ;
   MAGNETE_1_ESCLUSO : BOOL ;	//MAGNETE 1 ESCLUSO DA MP270
   MAGNETE_2_ESCLUSO : BOOL ;	//MAGNETE 2 ESCLUSO DA MP270
   MAGNETE_3_ESCLUSO : BOOL ;	//MAGNETE 3 ESCLUSO DA MP270
   MAGNETE_4_ESCLUSO : BOOL ;	//MAGNETE 4 ESCLUSO DA MP270
   MAGNETE_5_ESCLUSO : BOOL ;	//MAGNETE 5 ESCLUSO DA MP270
   MAGNETE_6_ESCLUSO : BOOL ;	//MAGNETE 6 ESCLUSO DA MP270
   MAGNETE_LAT_SX_ESCLUSO : BOOL ;	//MAGNETE LATERALE SX ESCLUSO DA MP270
   MAGNETE_LAT_DX_ESCLUSO : BOOL ;	//MAGNETE LATERALE DX ESCLUSO DA MP270
   COMPENSAZ_TAV_2 : REAL ;	//COMPENSAZIONE TAVOLA 2
   STAT22 : WORD ;
   STAT23 : WORD ;
   STAT24 : WORD ;
   STAT25 : WORD ;
   STAT251 : WORD ;
   STAT26 : TIME ;
   STAT29 : TIME ;
   STAT30 : TIME ;
   STAT31 : TIME ;
   C1_Timer : REAL ;	//Centratore 1: Timer ritardo partenza
   C2_Timer : REAL ;	//Centratore 2: Timer ritardo partenza
   C3_Timer : REAL ;	//Centratore 3: Timer ritardo partenza
   C4_Timer : REAL ;	//Centratore 4: Timer ritardo partenza
   C5_Timer : REAL ;	//Centratore 5: Timer ritardo partenza
   C6_Timer : REAL ;	//Centratore 6: Timer ritardo partenza
   C1_Posizione_1 : DINT  := L#500000;	//Centratore 1: Posizione 1 di avicinamento
   C1_Posizione_2 : DINT  := L#520000;	//Centratore 1: Posizione 2 di cambio velocita'
   C1_Posizione_3 : DINT  := L#530000;	//Centratore 1: Posizione 3 di cambio velocita'
   C1_Posizione_4 : DINT  := L#565400;	//Centratore 1: Posizione 4 di arrivo
   C1_Velocita_1 : DINT  := L#50;	//Centratore 1: Velocita' 1 di avvicinamento
   C1_Velocita_2 : DINT  := L#50;	//Centratore 1: Velocita' 2
   C1_Velocita_3 : DINT  := L#50;	//Centratore 1: Velocita' 3
   C1_Velocita_4 : DINT  := L#50;	//Centratore 1: Velocita' 4 di arrivo
   C1_Accell_1 : DINT  := L#500;	//Centratore 1: Accelerazione 1 di avvicinamento
   C1_Accell_2 : DINT  := L#500;	//Centratore 1: Accelerazione 2
   C1_Accell_3 : DINT  := L#500;	//Centratore 1: Accelerazione 3
   C1_Accell_4 : DINT  := L#500;	//Centratore 1: Accelerazione 4 di arrivo
   word_148 : WORD ;
   C2_Posizione_1 : DINT  := L#500000;	//Centratore 2: Posizione 1 di avicinamento
   C2_Posizione_2 : DINT  := L#520000;	//Centratore 2: Posizione 2 di cambio velocita'
   C2_Posizione_3 : DINT  := L#530000;	//Centratore 2: Posizione 3 di cambio velocita'
   C2_Posizione_4 : DINT  := L#559000;	//Centratore 2: Posizione 4 di arrivo
   C2_Velocita_1 : DINT  := L#50;	//Centratore 2: Velocita' 1 di avvicinamento
   C2_Velocita_2 : DINT  := L#50;	//Centratore 2: Velocita' 2
   C2_Velocita_3 : DINT  := L#50;	//Centratore 2: Velocita' 3
   C2_Velocita_4 : DINT  := L#50;	//Centratore 2: Velocita' 4 di arrivo
   C2_Accell_1 : DINT  := L#500;	//Centratore 2: Accelerazione 1 di avvicinamento
   C2_Accell_2 : DINT  := L#500;	//Centratore 2: Accelerazione 2
   C2_Accell_3 : DINT  := L#500;	//Centratore 2: Accelerazione 3
   C2_Accell_4 : DINT  := L#500;	//Centratore 2: Accelerazione 4 di arrivo
   word_198 : WORD ;
   C3_Posizione_1 : DINT  := L#630000;	//Centratore 3: Posizione 1 di avicinamento
   C3_Posizione_2 : DINT  := L#650000;	//Centratore 3: Posizione 2 di cambio velocita'
   C3_Posizione_3 : DINT  := L#660000;	//Centratore 3: Posizione 3 di cambio velocita'
   C3_Posizione_4 : DINT  := L#698600;	//Centratore 3: Posizione 4 di arrivo
   C3_Velocita_1 : DINT  := L#50;	//Centratore 3: Velocita' 1 di avvicinamento
   C3_Velocita_2 : DINT  := L#50;	//Centratore 3: Velocita' 2
   C3_Velocita_3 : DINT  := L#50;	//Centratore 3: Velocita' 3
   C3_Velocita_4 : DINT  := L#50;	//Centratore 3: Velocita' 4 di arrivo
   C3_Accell_1 : DINT  := L#500;	//Centratore 3: Accelerazione 1 di avvicinamento
   C3_Accell_2 : DINT  := L#500;	//Centratore 3: Accelerazione 2
   C3_Accell_3 : DINT  := L#500;	//Centratore 3: Accelerazione 3
   C3_Accell_4 : DINT  := L#500;	//Centratore 3: Accelerazione 4 di arrivo
   word_248 : WORD ;
   C4_Posizione_1 : DINT  := L#630000;	//Centratore 4: Posizione 1 di avicinamento
   C4_Posizione_2 : DINT  := L#650000;	//Centratore 4: Posizione 2 di cambio velocita'
   C4_Posizione_3 : DINT  := L#660000;	//Centratore 4: Posizione 3 di cambio velocita'
   C4_Posizione_4 : DINT  := L#706200;	//Centratore 4: Posizione 4 di arrivo
   C4_Velocita_1 : DINT  := L#50;	//Centratore 4: Velocita' 1 di avvicinamento
   C4_Velocita_2 : DINT  := L#50;	//Centratore 4: Velocita' 2
   C4_Velocita_3 : DINT  := L#50;	//Centratore 4: Velocita' 3
   C4_Velocita_4 : DINT  := L#50;	//Centratore 4: Velocita' 4 di arrivo
   C4_Accell_1 : DINT  := L#500;	//Centratore 4: Accelerazione 1 di avvicinamento
   C4_Accell_2 : DINT  := L#500;	//Centratore 4: Accelerazione 2
   C4_Accell_3 : DINT  := L#500;	//Centratore 4: Accelerazione 3
   C4_Accell_4 : DINT  := L#500;	//Centratore 4: Accelerazione 4 di arrivo
   word_298 : WORD ;
   C5_Posizione_1 : DINT  := L#1180000;	//Centratore 5: Posizione 1 di avicinamento
   C5_Posizione_2 : DINT  := L#1200000;	//Centratore 5: Posizione 2 di cambio velocita'
   C5_Posizione_3 : DINT  := L#1220000;	//Centratore 5: Posizione 3 di cambio velocita'
   C5_Posizione_4 : DINT  := L#1247000;	//Centratore 5: Posizione 4 di arrivo
   C5_Velocita_1 : DINT  := L#50;	//Centratore 5: Velocita' 1 di avvicinamento
   C5_Velocita_2 : DINT  := L#50;	//Centratore 5: Velocita' 2
   C5_Velocita_3 : DINT  := L#50;	//Centratore 5: Velocita' 3
   C5_Velocita_4 : DINT  := L#50;	//Centratore 5: Velocita' 4 di arrivo
   C5_Accell_1 : DINT  := L#500;	//Centratore 5: Accelerazione 1 di avvicinamento
   C5_Accell_2 : DINT  := L#500;	//Centratore 5: Accelerazione 2
   C5_Accell_3 : DINT  := L#500;	//Centratore 5: Accelerazione 3
   C5_Accell_4 : DINT  := L#500;	//Centratore 5: Accelerazione 4 di arrivo
   word_348 : WORD ;
   C6_Posizione_1 : DINT  := L#1180000;	//Centratore 6: Posizione 1 di avicinamento
   C6_Posizione_2 : DINT  := L#1200000;	//Centratore 6: Posizione 2 di cambio velocita'
   C6_Posizione_3 : DINT  := L#1220000;	//Centratore 6: Posizione 3 di cambio velocita'
   C6_Posizione_4 : DINT  := L#1237400;	//Centratore 6: Posizione 4 di arrivo
   C6_Velocita_1 : DINT  := L#50;	//Centratore 6: Velocita' 1 di avvicinamento
   C6_Velocita_2 : DINT  := L#50;	//Centratore 6: Velocita' 2
   C6_Velocita_3 : DINT  := L#50;	//Centratore 6: Velocita' 3
   C6_Velocita_4 : DINT  := L#50;	//Centratore 6: Velocita' 4 di arrivo
   C6_Accell_1 : DINT  := L#500;	//Centratore 6: Accelerazione 1 di avvicinamento
   C6_Accell_2 : DINT  := L#500;	//Centratore 6: Accelerazione 2
   C6_Accell_3 : DINT  := L#500;	//Centratore 6: Accelerazione 3
   C6_Accell_4 : DINT  := L#500;	//Centratore 6: Accelerazione 4 di arrivo
   word_398 : WORD ;
  END_STRUCT ;
BEGIN
   LARGHEZZA_LAMIERA := 3.060000e+003;
   COMPENSAZ_TAV_1 := -7.000000e+001;
   QUOTA_H_SFOGLIATORE := 2.000000e+003;
   QUOTA_H_CENTRATORE := 1.960000e+003;
   word16 := S5T#0MS;
   INCLINAZ_TAVOLA_ESCLUSA := FALSE;
   dword20 := 0.000000e+000;
   dword24 := 0.000000e+000;
   dword28 := 0.000000e+000;
   dword32 := 0.000000e+000;
   dword36 := 0.000000e+000;
   NR_MATRICOLA := 2;
   word42 := W#16#0;
   MAGNETE_1_ESCLUSO := FALSE;
   MAGNETE_2_ESCLUSO := FALSE;
   MAGNETE_3_ESCLUSO := FALSE;
   MAGNETE_4_ESCLUSO := FALSE;
   MAGNETE_5_ESCLUSO := FALSE;
   MAGNETE_6_ESCLUSO := FALSE;
   MAGNETE_LAT_SX_ESCLUSO := FALSE;
   MAGNETE_LAT_DX_ESCLUSO := FALSE;
   COMPENSAZ_TAV_2 := -3.000000e+001;
   STAT22 := W#16#0;
   STAT23 := W#16#0;
   STAT24 := W#16#0;
   STAT25 := W#16#0;
   STAT251 := W#16#0;
   STAT26 := T#0MS;
   STAT29 := T#0MS;
   STAT30 := T#0MS;
   STAT31 := T#0MS;
   C1_Timer := 0.000000e+000;
   C2_Timer := 0.000000e+000;
   C3_Timer := 0.000000e+000;
   C4_Timer := 0.000000e+000;
   C5_Timer := 0.000000e+000;
   C6_Timer := 0.000000e+000;
   C1_Posizione_1 := L#163000;
   C1_Posizione_2 := L#183000;
   C1_Posizione_3 := L#193000;
   C1_Posizione_4 := L#235000;
   C1_Velocita_1 := L#500;
   C1_Velocita_2 := L#200;
   C1_Velocita_3 := L#200;
   C1_Velocita_4 := L#50;
   C1_Accell_1 := L#500;
   C1_Accell_2 := L#500;
   C1_Accell_3 := L#500;
   C1_Accell_4 := L#500;
   word_148 := W#16#0;
   C2_Posizione_1 := L#326000;
   C2_Posizione_2 := L#346000;
   C2_Posizione_3 := L#356000;
   C2_Posizione_4 := L#401000;
   C2_Velocita_1 := L#500;
   C2_Velocita_2 := L#200;
   C2_Velocita_3 := L#200;
   C2_Velocita_4 := L#50;
   C2_Accell_1 := L#500;
   C2_Accell_2 := L#500;
   C2_Accell_3 := L#500;
   C2_Accell_4 := L#500;
   word_198 := W#16#0;
   C3_Posizione_1 := L#200000;
   C3_Posizione_2 := L#220000;
   C3_Posizione_3 := L#230000;
   C3_Posizione_4 := L#385000;
   C3_Velocita_1 := L#500;
   C3_Velocita_2 := L#200;
   C3_Velocita_3 := L#200;
   C3_Velocita_4 := L#50;
   C3_Accell_1 := L#500;
   C3_Accell_2 := L#500;
   C3_Accell_3 := L#500;
   C3_Accell_4 := L#500;
   word_248 := W#16#0;
   C4_Posizione_1 := L#100000;
   C4_Posizione_2 := L#120000;
   C4_Posizione_3 := L#130000;
   C4_Posizione_4 := L#283000;
   C4_Velocita_1 := L#500;
   C4_Velocita_2 := L#200;
   C4_Velocita_3 := L#200;
   C4_Velocita_4 := L#50;
   C4_Accell_1 := L#500;
   C4_Accell_2 := L#500;
   C4_Accell_3 := L#500;
   C4_Accell_4 := L#500;
   word_298 := W#16#0;
   C5_Posizione_1 := L#395000;
   C5_Posizione_2 := L#415000;
   C5_Posizione_3 := L#425000;
   C5_Posizione_4 := L#510000;
   C5_Velocita_1 := L#500;
   C5_Velocita_2 := L#200;
   C5_Velocita_3 := L#200;
   C5_Velocita_4 := L#50;
   C5_Accell_1 := L#500;
   C5_Accell_2 := L#500;
   C5_Accell_3 := L#500;
   C5_Accell_4 := L#500;
   word_348 := W#16#0;
   C6_Posizione_1 := L#430000;
   C6_Posizione_2 := L#450000;
   C6_Posizione_3 := L#460000;
   C6_Posizione_4 := L#525000;
   C6_Velocita_1 := L#500;
   C6_Velocita_2 := L#200;
   C6_Velocita_3 := L#200;
   C6_Velocita_4 := L#50;
   C6_Accell_1 := L#500;
   C6_Accell_2 := L#500;
   C6_Accell_3 := L#500;
   C6_Accell_4 := L#500;
   word_398 := W#16#0;
END_DATA_BLOCK

DATA_BLOCK "MATRICOLA 28"
AUTHOR : Lodato
FAMILY : DESTACK
NAME : DATI
VERSION : 0.1


  STRUCT
   LARGHEZZA_LAMIERA : REAL  := 1.500000e+003;	//LARGHEZZA LAMIERA ATTUALE
   COMPENSAZ_TAV_1 : REAL ;	//COMPENSAZIONE TAVOLA 1
   QUOTA_H_SFOGLIATORE : REAL ;	//Quota impostata altezza sfogliatore
   QUOTA_H_CENTRATORE : REAL ;	//Quota impostata altezza centratore
   word16 : S5TIME ;
   INCLINAZ_TAVOLA_ESCLUSA : BOOL ;	//INCLINAZIONE TAVOLA ESCLUSA
   dword20 : REAL ;
   dword24 : REAL ;
   dword28 : REAL ;
   dword32 : REAL ;
   dword36 : REAL ;
   NR_MATRICOLA : INT  := 1;	//Numero di matricola
   word42 : WORD ;
   MAGNETE_1_ESCLUSO : BOOL ;	//MAGNETE 1 ESCLUSO DA MP270
   MAGNETE_2_ESCLUSO : BOOL ;	//MAGNETE 2 ESCLUSO DA MP270
   MAGNETE_3_ESCLUSO : BOOL ;	//MAGNETE 3 ESCLUSO DA MP270
   MAGNETE_4_ESCLUSO : BOOL ;	//MAGNETE 4 ESCLUSO DA MP270
   MAGNETE_5_ESCLUSO : BOOL ;	//MAGNETE 5 ESCLUSO DA MP270
   MAGNETE_6_ESCLUSO : BOOL ;	//MAGNETE 6 ESCLUSO DA MP270
   MAGNETE_LAT_SX_ESCLUSO : BOOL ;	//MAGNETE LATERALE SX ESCLUSO DA MP270
   MAGNETE_LAT_DX_ESCLUSO : BOOL ;	//MAGNETE LATERALE DX ESCLUSO DA MP270
   COMPENSAZ_TAV_2 : REAL ;	//COMPENSAZIONE TAVOLA 2
   STAT22 : WORD ;
   STAT23 : WORD ;
   STAT24 : WORD ;
   STAT25 : WORD ;
   STAT251 : WORD ;
   STAT26 : TIME ;
   STAT29 : TIME ;
   STAT30 : TIME ;
   STAT31 : TIME ;
   C1_Timer : REAL ;	//Centratore 1: Timer ritardo partenza
   C2_Timer : REAL ;	//Centratore 2: Timer ritardo partenza
   C3_Timer : REAL ;	//Centratore 3: Timer ritardo partenza
   C4_Timer : REAL ;	//Centratore 4: Timer ritardo partenza
   C5_Timer : REAL ;	//Centratore 5: Timer ritardo partenza
   C6_Timer : REAL ;	//Centratore 6: Timer ritardo partenza
   C1_Posizione_1 : DINT  := L#500000;	//Centratore 1: Posizione 1 di avicinamento
   C1_Posizione_2 : DINT  := L#520000;	//Centratore 1: Posizione 2 di cambio velocita'
   C1_Posizione_3 : DINT  := L#530000;	//Centratore 1: Posizione 3 di cambio velocita'
   C1_Posizione_4 : DINT  := L#565400;	//Centratore 1: Posizione 4 di arrivo
   C1_Velocita_1 : DINT  := L#50;	//Centratore 1: Velocita' 1 di avvicinamento
   C1_Velocita_2 : DINT  := L#50;	//Centratore 1: Velocita' 2
   C1_Velocita_3 : DINT  := L#50;	//Centratore 1: Velocita' 3
   C1_Velocita_4 : DINT  := L#50;	//Centratore 1: Velocita' 4 di arrivo
   C1_Accell_1 : DINT  := L#500;	//Centratore 1: Accelerazione 1 di avvicinamento
   C1_Accell_2 : DINT  := L#500;	//Centratore 1: Accelerazione 2
   C1_Accell_3 : DINT  := L#500;	//Centratore 1: Accelerazione 3
   C1_Accell_4 : DINT  := L#500;	//Centratore 1: Accelerazione 4 di arrivo
   word_148 : WORD ;
   C2_Posizione_1 : DINT  := L#500000;	//Centratore 2: Posizione 1 di avicinamento
   C2_Posizione_2 : DINT  := L#520000;	//Centratore 2: Posizione 2 di cambio velocita'
   C2_Posizione_3 : DINT  := L#530000;	//Centratore 2: Posizione 3 di cambio velocita'
   C2_Posizione_4 : DINT  := L#559000;	//Centratore 2: Posizione 4 di arrivo
   C2_Velocita_1 : DINT  := L#50;	//Centratore 2: Velocita' 1 di avvicinamento
   C2_Velocita_2 : DINT  := L#50;	//Centratore 2: Velocita' 2
   C2_Velocita_3 : DINT  := L#50;	//Centratore 2: Velocita' 3
   C2_Velocita_4 : DINT  := L#50;	//Centratore 2: Velocita' 4 di arrivo
   C2_Accell_1 : DINT  := L#500;	//Centratore 2: Accelerazione 1 di avvicinamento
   C2_Accell_2 : DINT  := L#500;	//Centratore 2: Accelerazione 2
   C2_Accell_3 : DINT  := L#500;	//Centratore 2: Accelerazione 3
   C2_Accell_4 : DINT  := L#500;	//Centratore 2: Accelerazione 4 di arrivo
   word_198 : WORD ;
   C3_Posizione_1 : DINT  := L#630000;	//Centratore 3: Posizione 1 di avicinamento
   C3_Posizione_2 : DINT  := L#650000;	//Centratore 3: Posizione 2 di cambio velocita'
   C3_Posizione_3 : DINT  := L#660000;	//Centratore 3: Posizione 3 di cambio velocita'
   C3_Posizione_4 : DINT  := L#698600;	//Centratore 3: Posizione 4 di arrivo
   C3_Velocita_1 : DINT  := L#50;	//Centratore 3: Velocita' 1 di avvicinamento
   C3_Velocita_2 : DINT  := L#50;	//Centratore 3: Velocita' 2
   C3_Velocita_3 : DINT  := L#50;	//Centratore 3: Velocita' 3
   C3_Velocita_4 : DINT  := L#50;	//Centratore 3: Velocita' 4 di arrivo
   C3_Accell_1 : DINT  := L#500;	//Centratore 3: Accelerazione 1 di avvicinamento
   C3_Accell_2 : DINT  := L#500;	//Centratore 3: Accelerazione 2
   C3_Accell_3 : DINT  := L#500;	//Centratore 3: Accelerazione 3
   C3_Accell_4 : DINT  := L#500;	//Centratore 3: Accelerazione 4 di arrivo
   word_248 : WORD ;
   C4_Posizione_1 : DINT  := L#630000;	//Centratore 4: Posizione 1 di avicinamento
   C4_Posizione_2 : DINT  := L#650000;	//Centratore 4: Posizione 2 di cambio velocita'
   C4_Posizione_3 : DINT  := L#660000;	//Centratore 4: Posizione 3 di cambio velocita'
   C4_Posizione_4 : DINT  := L#706200;	//Centratore 4: Posizione 4 di arrivo
   C4_Velocita_1 : DINT  := L#50;	//Centratore 4: Velocita' 1 di avvicinamento
   C4_Velocita_2 : DINT  := L#50;	//Centratore 4: Velocita' 2
   C4_Velocita_3 : DINT  := L#50;	//Centratore 4: Velocita' 3
   C4_Velocita_4 : DINT  := L#50;	//Centratore 4: Velocita' 4 di arrivo
   C4_Accell_1 : DINT  := L#500;	//Centratore 4: Accelerazione 1 di avvicinamento
   C4_Accell_2 : DINT  := L#500;	//Centratore 4: Accelerazione 2
   C4_Accell_3 : DINT  := L#500;	//Centratore 4: Accelerazione 3
   C4_Accell_4 : DINT  := L#500;	//Centratore 4: Accelerazione 4 di arrivo
   word_298 : WORD ;
   C5_Posizione_1 : DINT  := L#1180000;	//Centratore 5: Posizione 1 di avicinamento
   C5_Posizione_2 : DINT  := L#1200000;	//Centratore 5: Posizione 2 di cambio velocita'
   C5_Posizione_3 : DINT  := L#1220000;	//Centratore 5: Posizione 3 di cambio velocita'
   C5_Posizione_4 : DINT  := L#1247000;	//Centratore 5: Posizione 4 di arrivo
   C5_Velocita_1 : DINT  := L#50;	//Centratore 5: Velocita' 1 di avvicinamento
   C5_Velocita_2 : DINT  := L#50;	//Centratore 5: Velocita' 2
   C5_Velocita_3 : DINT  := L#50;	//Centratore 5: Velocita' 3
   C5_Velocita_4 : DINT  := L#50;	//Centratore 5: Velocita' 4 di arrivo
   C5_Accell_1 : DINT  := L#500;	//Centratore 5: Accelerazione 1 di avvicinamento
   C5_Accell_2 : DINT  := L#500;	//Centratore 5: Accelerazione 2
   C5_Accell_3 : DINT  := L#500;	//Centratore 5: Accelerazione 3
   C5_Accell_4 : DINT  := L#500;	//Centratore 5: Accelerazione 4 di arrivo
   word_348 : WORD ;
   C6_Posizione_1 : DINT  := L#1180000;	//Centratore 6: Posizione 1 di avicinamento
   C6_Posizione_2 : DINT  := L#1200000;	//Centratore 6: Posizione 2 di cambio velocita'
   C6_Posizione_3 : DINT  := L#1220000;	//Centratore 6: Posizione 3 di cambio velocita'
   C6_Posizione_4 : DINT  := L#1237400;	//Centratore 6: Posizione 4 di arrivo
   C6_Velocita_1 : DINT  := L#50;	//Centratore 6: Velocita' 1 di avvicinamento
   C6_Velocita_2 : DINT  := L#50;	//Centratore 6: Velocita' 2
   C6_Velocita_3 : DINT  := L#50;	//Centratore 6: Velocita' 3
   C6_Velocita_4 : DINT  := L#50;	//Centratore 6: Velocita' 4 di arrivo
   C6_Accell_1 : DINT  := L#500;	//Centratore 6: Accelerazione 1 di avvicinamento
   C6_Accell_2 : DINT  := L#500;	//Centratore 6: Accelerazione 2
   C6_Accell_3 : DINT  := L#500;	//Centratore 6: Accelerazione 3
   C6_Accell_4 : DINT  := L#500;	//Centratore 6: Accelerazione 4 di arrivo
   word_398 : WORD ;
  END_STRUCT ;
BEGIN
   LARGHEZZA_LAMIERA := 3.060000e+003;
   COMPENSAZ_TAV_1 := -7.000000e+001;
   QUOTA_H_SFOGLIATORE := 2.000000e+003;
   QUOTA_H_CENTRATORE := 1.960000e+003;
   word16 := S5T#0MS;
   INCLINAZ_TAVOLA_ESCLUSA := FALSE;
   dword20 := 0.000000e+000;
   dword24 := 0.000000e+000;
   dword28 := 0.000000e+000;
   dword32 := 0.000000e+000;
   dword36 := 0.000000e+000;
   NR_MATRICOLA := 2;
   word42 := W#16#0;
   MAGNETE_1_ESCLUSO := FALSE;
   MAGNETE_2_ESCLUSO := FALSE;
   MAGNETE_3_ESCLUSO := FALSE;
   MAGNETE_4_ESCLUSO := FALSE;
   MAGNETE_5_ESCLUSO := FALSE;
   MAGNETE_6_ESCLUSO := FALSE;
   MAGNETE_LAT_SX_ESCLUSO := FALSE;
   MAGNETE_LAT_DX_ESCLUSO := FALSE;
   COMPENSAZ_TAV_2 := -3.000000e+001;
   STAT22 := W#16#0;
   STAT23 := W#16#0;
   STAT24 := W#16#0;
   STAT25 := W#16#0;
   STAT251 := W#16#0;
   STAT26 := T#0MS;
   STAT29 := T#0MS;
   STAT30 := T#0MS;
   STAT31 := T#0MS;
   C1_Timer := 0.000000e+000;
   C2_Timer := 0.000000e+000;
   C3_Timer := 0.000000e+000;
   C4_Timer := 0.000000e+000;
   C5_Timer := 0.000000e+000;
   C6_Timer := 0.000000e+000;
   C1_Posizione_1 := L#163000;
   C1_Posizione_2 := L#183000;
   C1_Posizione_3 := L#193000;
   C1_Posizione_4 := L#235000;
   C1_Velocita_1 := L#500;
   C1_Velocita_2 := L#200;
   C1_Velocita_3 := L#200;
   C1_Velocita_4 := L#50;
   C1_Accell_1 := L#500;
   C1_Accell_2 := L#500;
   C1_Accell_3 := L#500;
   C1_Accell_4 := L#500;
   word_148 := W#16#0;
   C2_Posizione_1 := L#326000;
   C2_Posizione_2 := L#346000;
   C2_Posizione_3 := L#356000;
   C2_Posizione_4 := L#401000;
   C2_Velocita_1 := L#500;
   C2_Velocita_2 := L#200;
   C2_Velocita_3 := L#200;
   C2_Velocita_4 := L#50;
   C2_Accell_1 := L#500;
   C2_Accell_2 := L#500;
   C2_Accell_3 := L#500;
   C2_Accell_4 := L#500;
   word_198 := W#16#0;
   C3_Posizione_1 := L#200000;
   C3_Posizione_2 := L#220000;
   C3_Posizione_3 := L#230000;
   C3_Posizione_4 := L#385000;
   C3_Velocita_1 := L#500;
   C3_Velocita_2 := L#200;
   C3_Velocita_3 := L#200;
   C3_Velocita_4 := L#50;
   C3_Accell_1 := L#500;
   C3_Accell_2 := L#500;
   C3_Accell_3 := L#500;
   C3_Accell_4 := L#500;
   word_248 := W#16#0;
   C4_Posizione_1 := L#100000;
   C4_Posizione_2 := L#120000;
   C4_Posizione_3 := L#130000;
   C4_Posizione_4 := L#283000;
   C4_Velocita_1 := L#500;
   C4_Velocita_2 := L#200;
   C4_Velocita_3 := L#200;
   C4_Velocita_4 := L#50;
   C4_Accell_1 := L#500;
   C4_Accell_2 := L#500;
   C4_Accell_3 := L#500;
   C4_Accell_4 := L#500;
   word_298 := W#16#0;
   C5_Posizione_1 := L#395000;
   C5_Posizione_2 := L#415000;
   C5_Posizione_3 := L#425000;
   C5_Posizione_4 := L#510000;
   C5_Velocita_1 := L#500;
   C5_Velocita_2 := L#200;
   C5_Velocita_3 := L#200;
   C5_Velocita_4 := L#50;
   C5_Accell_1 := L#500;
   C5_Accell_2 := L#500;
   C5_Accell_3 := L#500;
   C5_Accell_4 := L#500;
   word_348 := W#16#0;
   C6_Posizione_1 := L#430000;
   C6_Posizione_2 := L#450000;
   C6_Posizione_3 := L#460000;
   C6_Posizione_4 := L#525000;
   C6_Velocita_1 := L#500;
   C6_Velocita_2 := L#200;
   C6_Velocita_3 := L#200;
   C6_Velocita_4 := L#50;
   C6_Accell_1 := L#500;
   C6_Accell_2 := L#500;
   C6_Accell_3 := L#500;
   C6_Accell_4 := L#500;
   word_398 := W#16#0;
END_DATA_BLOCK

DATA_BLOCK "MATRICOLA 29"
AUTHOR : Lodato
FAMILY : DESTACK
NAME : DATI
VERSION : 0.1


  STRUCT
   LARGHEZZA_LAMIERA : REAL  := 1.500000e+003;	//LARGHEZZA LAMIERA ATTUALE
   COMPENSAZ_TAV_1 : REAL ;	//COMPENSAZIONE TAVOLA 1
   QUOTA_H_SFOGLIATORE : REAL ;	//Quota impostata altezza sfogliatore
   QUOTA_H_CENTRATORE : REAL ;	//Quota impostata altezza centratore
   word16 : S5TIME ;
   INCLINAZ_TAVOLA_ESCLUSA : BOOL ;	//INCLINAZIONE TAVOLA ESCLUSA
   dword20 : REAL ;
   dword24 : REAL ;
   dword28 : REAL ;
   dword32 : REAL ;
   dword36 : REAL ;
   NR_MATRICOLA : INT  := 1;	//Numero di matricola
   word42 : WORD ;
   MAGNETE_1_ESCLUSO : BOOL ;	//MAGNETE 1 ESCLUSO DA MP270
   MAGNETE_2_ESCLUSO : BOOL ;	//MAGNETE 2 ESCLUSO DA MP270
   MAGNETE_3_ESCLUSO : BOOL ;	//MAGNETE 3 ESCLUSO DA MP270
   MAGNETE_4_ESCLUSO : BOOL ;	//MAGNETE 4 ESCLUSO DA MP270
   MAGNETE_5_ESCLUSO : BOOL ;	//MAGNETE 5 ESCLUSO DA MP270
   MAGNETE_6_ESCLUSO : BOOL ;	//MAGNETE 6 ESCLUSO DA MP270
   MAGNETE_LAT_SX_ESCLUSO : BOOL ;	//MAGNETE LATERALE SX ESCLUSO DA MP270
   MAGNETE_LAT_DX_ESCLUSO : BOOL ;	//MAGNETE LATERALE DX ESCLUSO DA MP270
   COMPENSAZ_TAV_2 : REAL ;	//COMPENSAZIONE TAVOLA 2
   STAT22 : WORD ;
   STAT23 : WORD ;
   STAT24 : WORD ;
   STAT25 : WORD ;
   STAT251 : WORD ;
   STAT26 : TIME ;
   STAT29 : TIME ;
   STAT30 : TIME ;
   STAT31 : TIME ;
   C1_Timer : REAL ;	//Centratore 1: Timer ritardo partenza
   C2_Timer : REAL ;	//Centratore 2: Timer ritardo partenza
   C3_Timer : REAL ;	//Centratore 3: Timer ritardo partenza
   C4_Timer : REAL ;	//Centratore 4: Timer ritardo partenza
   C5_Timer : REAL ;	//Centratore 5: Timer ritardo partenza
   C6_Timer : REAL ;	//Centratore 6: Timer ritardo partenza
   C1_Posizione_1 : DINT  := L#500000;	//Centratore 1: Posizione 1 di avicinamento
   C1_Posizione_2 : DINT  := L#520000;	//Centratore 1: Posizione 2 di cambio velocita'
   C1_Posizione_3 : DINT  := L#530000;	//Centratore 1: Posizione 3 di cambio velocita'
   C1_Posizione_4 : DINT  := L#565400;	//Centratore 1: Posizione 4 di arrivo
   C1_Velocita_1 : DINT  := L#50;	//Centratore 1: Velocita' 1 di avvicinamento
   C1_Velocita_2 : DINT  := L#50;	//Centratore 1: Velocita' 2
   C1_Velocita_3 : DINT  := L#50;	//Centratore 1: Velocita' 3
   C1_Velocita_4 : DINT  := L#50;	//Centratore 1: Velocita' 4 di arrivo
   C1_Accell_1 : DINT  := L#500;	//Centratore 1: Accelerazione 1 di avvicinamento
   C1_Accell_2 : DINT  := L#500;	//Centratore 1: Accelerazione 2
   C1_Accell_3 : DINT  := L#500;	//Centratore 1: Accelerazione 3
   C1_Accell_4 : DINT  := L#500;	//Centratore 1: Accelerazione 4 di arrivo
   word_148 : WORD ;
   C2_Posizione_1 : DINT  := L#500000;	//Centratore 2: Posizione 1 di avicinamento
   C2_Posizione_2 : DINT  := L#520000;	//Centratore 2: Posizione 2 di cambio velocita'
   C2_Posizione_3 : DINT  := L#530000;	//Centratore 2: Posizione 3 di cambio velocita'
   C2_Posizione_4 : DINT  := L#559000;	//Centratore 2: Posizione 4 di arrivo
   C2_Velocita_1 : DINT  := L#50;	//Centratore 2: Velocita' 1 di avvicinamento
   C2_Velocita_2 : DINT  := L#50;	//Centratore 2: Velocita' 2
   C2_Velocita_3 : DINT  := L#50;	//Centratore 2: Velocita' 3
   C2_Velocita_4 : DINT  := L#50;	//Centratore 2: Velocita' 4 di arrivo
   C2_Accell_1 : DINT  := L#500;	//Centratore 2: Accelerazione 1 di avvicinamento
   C2_Accell_2 : DINT  := L#500;	//Centratore 2: Accelerazione 2
   C2_Accell_3 : DINT  := L#500;	//Centratore 2: Accelerazione 3
   C2_Accell_4 : DINT  := L#500;	//Centratore 2: Accelerazione 4 di arrivo
   word_198 : WORD ;
   C3_Posizione_1 : DINT  := L#630000;	//Centratore 3: Posizione 1 di avicinamento
   C3_Posizione_2 : DINT  := L#650000;	//Centratore 3: Posizione 2 di cambio velocita'
   C3_Posizione_3 : DINT  := L#660000;	//Centratore 3: Posizione 3 di cambio velocita'
   C3_Posizione_4 : DINT  := L#698600;	//Centratore 3: Posizione 4 di arrivo
   C3_Velocita_1 : DINT  := L#50;	//Centratore 3: Velocita' 1 di avvicinamento
   C3_Velocita_2 : DINT  := L#50;	//Centratore 3: Velocita' 2
   C3_Velocita_3 : DINT  := L#50;	//Centratore 3: Velocita' 3
   C3_Velocita_4 : DINT  := L#50;	//Centratore 3: Velocita' 4 di arrivo
   C3_Accell_1 : DINT  := L#500;	//Centratore 3: Accelerazione 1 di avvicinamento
   C3_Accell_2 : DINT  := L#500;	//Centratore 3: Accelerazione 2
   C3_Accell_3 : DINT  := L#500;	//Centratore 3: Accelerazione 3
   C3_Accell_4 : DINT  := L#500;	//Centratore 3: Accelerazione 4 di arrivo
   word_248 : WORD ;
   C4_Posizione_1 : DINT  := L#630000;	//Centratore 4: Posizione 1 di avicinamento
   C4_Posizione_2 : DINT  := L#650000;	//Centratore 4: Posizione 2 di cambio velocita'
   C4_Posizione_3 : DINT  := L#660000;	//Centratore 4: Posizione 3 di cambio velocita'
   C4_Posizione_4 : DINT  := L#706200;	//Centratore 4: Posizione 4 di arrivo
   C4_Velocita_1 : DINT  := L#50;	//Centratore 4: Velocita' 1 di avvicinamento
   C4_Velocita_2 : DINT  := L#50;	//Centratore 4: Velocita' 2
   C4_Velocita_3 : DINT  := L#50;	//Centratore 4: Velocita' 3
   C4_Velocita_4 : DINT  := L#50;	//Centratore 4: Velocita' 4 di arrivo
   C4_Accell_1 : DINT  := L#500;	//Centratore 4: Accelerazione 1 di avvicinamento
   C4_Accell_2 : DINT  := L#500;	//Centratore 4: Accelerazione 2
   C4_Accell_3 : DINT  := L#500;	//Centratore 4: Accelerazione 3
   C4_Accell_4 : DINT  := L#500;	//Centratore 4: Accelerazione 4 di arrivo
   word_298 : WORD ;
   C5_Posizione_1 : DINT  := L#1180000;	//Centratore 5: Posizione 1 di avicinamento
   C5_Posizione_2 : DINT  := L#1200000;	//Centratore 5: Posizione 2 di cambio velocita'
   C5_Posizione_3 : DINT  := L#1220000;	//Centratore 5: Posizione 3 di cambio velocita'
   C5_Posizione_4 : DINT  := L#1247000;	//Centratore 5: Posizione 4 di arrivo
   C5_Velocita_1 : DINT  := L#50;	//Centratore 5: Velocita' 1 di avvicinamento
   C5_Velocita_2 : DINT  := L#50;	//Centratore 5: Velocita' 2
   C5_Velocita_3 : DINT  := L#50;	//Centratore 5: Velocita' 3
   C5_Velocita_4 : DINT  := L#50;	//Centratore 5: Velocita' 4 di arrivo
   C5_Accell_1 : DINT  := L#500;	//Centratore 5: Accelerazione 1 di avvicinamento
   C5_Accell_2 : DINT  := L#500;	//Centratore 5: Accelerazione 2
   C5_Accell_3 : DINT  := L#500;	//Centratore 5: Accelerazione 3
   C5_Accell_4 : DINT  := L#500;	//Centratore 5: Accelerazione 4 di arrivo
   word_348 : WORD ;
   C6_Posizione_1 : DINT  := L#1180000;	//Centratore 6: Posizione 1 di avicinamento
   C6_Posizione_2 : DINT  := L#1200000;	//Centratore 6: Posizione 2 di cambio velocita'
   C6_Posizione_3 : DINT  := L#1220000;	//Centratore 6: Posizione 3 di cambio velocita'
   C6_Posizione_4 : DINT  := L#1237400;	//Centratore 6: Posizione 4 di arrivo
   C6_Velocita_1 : DINT  := L#50;	//Centratore 6: Velocita' 1 di avvicinamento
   C6_Velocita_2 : DINT  := L#50;	//Centratore 6: Velocita' 2
   C6_Velocita_3 : DINT  := L#50;	//Centratore 6: Velocita' 3
   C6_Velocita_4 : DINT  := L#50;	//Centratore 6: Velocita' 4 di arrivo
   C6_Accell_1 : DINT  := L#500;	//Centratore 6: Accelerazione 1 di avvicinamento
   C6_Accell_2 : DINT  := L#500;	//Centratore 6: Accelerazione 2
   C6_Accell_3 : DINT  := L#500;	//Centratore 6: Accelerazione 3
   C6_Accell_4 : DINT  := L#500;	//Centratore 6: Accelerazione 4 di arrivo
   word_398 : WORD ;
  END_STRUCT ;
BEGIN
   LARGHEZZA_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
